VERSION 5.7 ;
  NOWIREEXTENSIONATPIN ON ;
  DIVIDERCHAR "/" ;
  BUSBITCHARS "[]" ;
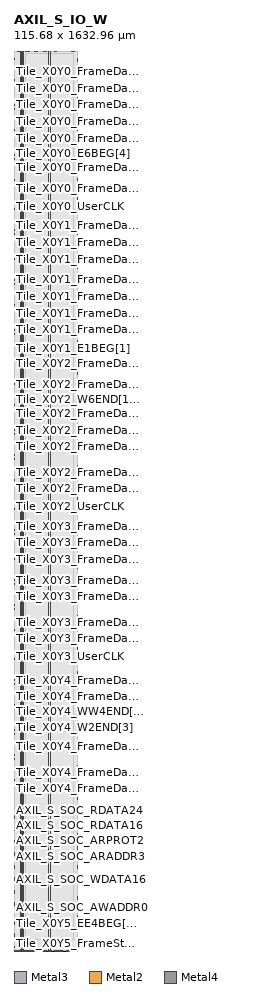
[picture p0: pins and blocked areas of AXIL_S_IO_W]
MACRO AXIL_S_IO_W
  CLASS BLOCK ;
  FOREIGN AXIL_S_IO_W ;
  ORIGIN 0.000 0.000 ;
  SIZE 115.680 BY 1632.960 ;
  PIN AXIL_S_SOC_ARADDR0
    DIRECTION INPUT ;
    USE SIGNAL ;
    ANTENNAGATEAREA 2.132000 ;
    PORT
      LAYER Metal3 ;
        RECT 0.000 165.700 0.400 166.100 ;
    END
  END AXIL_S_SOC_ARADDR0
  PIN AXIL_S_SOC_ARADDR1
    DIRECTION INPUT ;
    USE SIGNAL ;
    ANTENNAGATEAREA 2.132000 ;
    PORT
      LAYER Metal3 ;
        RECT 0.000 167.380 0.400 167.780 ;
    END
  END AXIL_S_SOC_ARADDR1
  PIN AXIL_S_SOC_ARADDR2
    DIRECTION INPUT ;
    USE SIGNAL ;
    ANTENNAGATEAREA 2.132000 ;
    PORT
      LAYER Metal3 ;
        RECT 0.000 169.060 0.400 169.460 ;
    END
  END AXIL_S_SOC_ARADDR2
  PIN AXIL_S_SOC_ARADDR3
    DIRECTION INPUT ;
    USE SIGNAL ;
    ANTENNAGATEAREA 2.132000 ;
    PORT
      LAYER Metal3 ;
        RECT 0.000 170.740 0.400 171.140 ;
    END
  END AXIL_S_SOC_ARADDR3
  PIN AXIL_S_SOC_ARADDR4
    DIRECTION INPUT ;
    USE SIGNAL ;
    ANTENNAGATEAREA 2.132000 ;
    PORT
      LAYER Metal3 ;
        RECT 0.000 172.420 0.400 172.820 ;
    END
  END AXIL_S_SOC_ARADDR4
  PIN AXIL_S_SOC_ARADDR5
    DIRECTION INPUT ;
    USE SIGNAL ;
    ANTENNAGATEAREA 2.132000 ;
    PORT
      LAYER Metal3 ;
        RECT 0.000 174.100 0.400 174.500 ;
    END
  END AXIL_S_SOC_ARADDR5
  PIN AXIL_S_SOC_ARADDR6
    DIRECTION INPUT ;
    USE SIGNAL ;
    ANTENNAGATEAREA 1.279200 ;
    PORT
      LAYER Metal3 ;
        RECT 0.000 175.780 0.400 176.180 ;
    END
  END AXIL_S_SOC_ARADDR6
  PIN AXIL_S_SOC_ARADDR7
    DIRECTION INPUT ;
    USE SIGNAL ;
    ANTENNAGATEAREA 1.279200 ;
    PORT
      LAYER Metal3 ;
        RECT 0.000 177.460 0.400 177.860 ;
    END
  END AXIL_S_SOC_ARADDR7
  PIN AXIL_S_SOC_ARADDR8
    DIRECTION INPUT ;
    USE SIGNAL ;
    ANTENNAGATEAREA 0.852800 ;
    PORT
      LAYER Metal3 ;
        RECT 0.000 179.140 0.400 179.540 ;
    END
  END AXIL_S_SOC_ARADDR8
  PIN AXIL_S_SOC_ARADDR9
    DIRECTION INPUT ;
    USE SIGNAL ;
    ANTENNAGATEAREA 0.852800 ;
    PORT
      LAYER Metal3 ;
        RECT 0.000 180.820 0.400 181.220 ;
    END
  END AXIL_S_SOC_ARADDR9
  PIN AXIL_S_SOC_ARPROT0
    DIRECTION INPUT ;
    USE SIGNAL ;
    ANTENNAGATEAREA 4.050800 ;
    PORT
      LAYER Metal3 ;
        RECT 0.000 182.500 0.400 182.900 ;
    END
  END AXIL_S_SOC_ARPROT0
  PIN AXIL_S_SOC_ARPROT1
    DIRECTION INPUT ;
    USE SIGNAL ;
    ANTENNAGATEAREA 3.411200 ;
    PORT
      LAYER Metal3 ;
        RECT 0.000 184.180 0.400 184.580 ;
    END
  END AXIL_S_SOC_ARPROT1
  PIN AXIL_S_SOC_ARPROT2
    DIRECTION INPUT ;
    USE SIGNAL ;
    ANTENNAGATEAREA 3.198000 ;
    PORT
      LAYER Metal3 ;
        RECT 0.000 185.860 0.400 186.260 ;
    END
  END AXIL_S_SOC_ARPROT2
  PIN AXIL_S_SOC_ARREADY
    DIRECTION OUTPUT ;
    USE SIGNAL ;
    ANTENNADIFFAREA 2.647800 ;
    PORT
      LAYER Metal3 ;
        RECT 0.000 199.300 0.400 199.700 ;
    END
  END AXIL_S_SOC_ARREADY
  PIN AXIL_S_SOC_ARVALID
    DIRECTION INPUT ;
    USE SIGNAL ;
    ANTENNAGATEAREA 2.984800 ;
    PORT
      LAYER Metal3 ;
        RECT 0.000 187.540 0.400 187.940 ;
    END
  END AXIL_S_SOC_ARVALID
  PIN AXIL_S_SOC_AWADDR0
    DIRECTION INPUT ;
    USE SIGNAL ;
    ANTENNAGATEAREA 2.132000 ;
    PORT
      LAYER Metal3 ;
        RECT 0.000 78.340 0.400 78.740 ;
    END
  END AXIL_S_SOC_AWADDR0
  PIN AXIL_S_SOC_AWADDR1
    DIRECTION INPUT ;
    USE SIGNAL ;
    ANTENNAGATEAREA 2.132000 ;
    PORT
      LAYER Metal3 ;
        RECT 0.000 80.020 0.400 80.420 ;
    END
  END AXIL_S_SOC_AWADDR1
  PIN AXIL_S_SOC_AWADDR2
    DIRECTION INPUT ;
    USE SIGNAL ;
    ANTENNAGATEAREA 1.279200 ;
    PORT
      LAYER Metal3 ;
        RECT 0.000 81.700 0.400 82.100 ;
    END
  END AXIL_S_SOC_AWADDR2
  PIN AXIL_S_SOC_AWADDR3
    DIRECTION INPUT ;
    USE SIGNAL ;
    ANTENNAGATEAREA 1.279200 ;
    PORT
      LAYER Metal3 ;
        RECT 0.000 83.380 0.400 83.780 ;
    END
  END AXIL_S_SOC_AWADDR3
  PIN AXIL_S_SOC_AWADDR4
    DIRECTION INPUT ;
    USE SIGNAL ;
    ANTENNAGATEAREA 1.279200 ;
    PORT
      LAYER Metal3 ;
        RECT 0.000 85.060 0.400 85.460 ;
    END
  END AXIL_S_SOC_AWADDR4
  PIN AXIL_S_SOC_AWADDR5
    DIRECTION INPUT ;
    USE SIGNAL ;
    ANTENNAGATEAREA 1.279200 ;
    PORT
      LAYER Metal3 ;
        RECT 0.000 86.740 0.400 87.140 ;
    END
  END AXIL_S_SOC_AWADDR5
  PIN AXIL_S_SOC_AWADDR6
    DIRECTION INPUT ;
    USE SIGNAL ;
    ANTENNAGATEAREA 1.279200 ;
    PORT
      LAYER Metal3 ;
        RECT 0.000 88.420 0.400 88.820 ;
    END
  END AXIL_S_SOC_AWADDR6
  PIN AXIL_S_SOC_AWADDR7
    DIRECTION INPUT ;
    USE SIGNAL ;
    ANTENNAGATEAREA 1.279200 ;
    PORT
      LAYER Metal3 ;
        RECT 0.000 90.100 0.400 90.500 ;
    END
  END AXIL_S_SOC_AWADDR7
  PIN AXIL_S_SOC_AWADDR8
    DIRECTION INPUT ;
    USE SIGNAL ;
    ANTENNAGATEAREA 0.852800 ;
    PORT
      LAYER Metal3 ;
        RECT 0.000 91.780 0.400 92.180 ;
    END
  END AXIL_S_SOC_AWADDR8
  PIN AXIL_S_SOC_AWADDR9
    DIRECTION INPUT ;
    USE SIGNAL ;
    ANTENNAGATEAREA 0.852800 ;
    PORT
      LAYER Metal3 ;
        RECT 0.000 93.460 0.400 93.860 ;
    END
  END AXIL_S_SOC_AWADDR9
  PIN AXIL_S_SOC_AWPROT0
    DIRECTION INPUT ;
    USE SIGNAL ;
    ANTENNAGATEAREA 0.852800 ;
    PORT
      LAYER Metal3 ;
        RECT 0.000 95.140 0.400 95.540 ;
    END
  END AXIL_S_SOC_AWPROT0
  PIN AXIL_S_SOC_AWPROT1
    DIRECTION INPUT ;
    USE SIGNAL ;
    ANTENNAGATEAREA 0.852800 ;
    PORT
      LAYER Metal3 ;
        RECT 0.000 96.820 0.400 97.220 ;
    END
  END AXIL_S_SOC_AWPROT1
  PIN AXIL_S_SOC_AWPROT2
    DIRECTION INPUT ;
    USE SIGNAL ;
    ANTENNAGATEAREA 0.852800 ;
    PORT
      LAYER Metal3 ;
        RECT 0.000 98.500 0.400 98.900 ;
    END
  END AXIL_S_SOC_AWPROT2
  PIN AXIL_S_SOC_AWREADY
    DIRECTION OUTPUT ;
    USE SIGNAL ;
    ANTENNADIFFAREA 2.647800 ;
    PORT
      LAYER Metal3 ;
        RECT 0.000 190.900 0.400 191.300 ;
    END
  END AXIL_S_SOC_AWREADY
  PIN AXIL_S_SOC_AWVALID
    DIRECTION INPUT ;
    USE SIGNAL ;
    ANTENNAGATEAREA 0.852800 ;
    PORT
      LAYER Metal3 ;
        RECT 0.000 100.180 0.400 100.580 ;
    END
  END AXIL_S_SOC_AWVALID
  PIN AXIL_S_SOC_BREADY
    DIRECTION INPUT ;
    USE SIGNAL ;
    ANTENNAGATEAREA 2.132000 ;
    PORT
      LAYER Metal3 ;
        RECT 0.000 164.020 0.400 164.420 ;
    END
  END AXIL_S_SOC_BREADY
  PIN AXIL_S_SOC_BRESP0
    DIRECTION OUTPUT ;
    USE SIGNAL ;
    ANTENNADIFFAREA 2.647800 ;
    PORT
      LAYER Metal3 ;
        RECT 0.000 194.260 0.400 194.660 ;
    END
  END AXIL_S_SOC_BRESP0
  PIN AXIL_S_SOC_BRESP1
    DIRECTION OUTPUT ;
    USE SIGNAL ;
    ANTENNADIFFAREA 2.647800 ;
    PORT
      LAYER Metal3 ;
        RECT 0.000 195.940 0.400 196.340 ;
    END
  END AXIL_S_SOC_BRESP1
  PIN AXIL_S_SOC_BVALID
    DIRECTION OUTPUT ;
    USE SIGNAL ;
    ANTENNADIFFAREA 2.647800 ;
    PORT
      LAYER Metal3 ;
        RECT 0.000 197.620 0.400 198.020 ;
    END
  END AXIL_S_SOC_BVALID
  PIN AXIL_S_SOC_RDATA0
    DIRECTION OUTPUT ;
    USE SIGNAL ;
    ANTENNADIFFAREA 2.647800 ;
    PORT
      LAYER Metal3 ;
        RECT 0.000 200.980 0.400 201.380 ;
    END
  END AXIL_S_SOC_RDATA0
  PIN AXIL_S_SOC_RDATA1
    DIRECTION OUTPUT ;
    USE SIGNAL ;
    ANTENNADIFFAREA 2.647800 ;
    PORT
      LAYER Metal3 ;
        RECT 0.000 202.660 0.400 203.060 ;
    END
  END AXIL_S_SOC_RDATA1
  PIN AXIL_S_SOC_RDATA10
    DIRECTION OUTPUT ;
    USE SIGNAL ;
    ANTENNADIFFAREA 2.647800 ;
    PORT
      LAYER Metal3 ;
        RECT 0.000 217.780 0.400 218.180 ;
    END
  END AXIL_S_SOC_RDATA10
  PIN AXIL_S_SOC_RDATA11
    DIRECTION OUTPUT ;
    USE SIGNAL ;
    ANTENNADIFFAREA 2.647800 ;
    PORT
      LAYER Metal3 ;
        RECT 0.000 219.460 0.400 219.860 ;
    END
  END AXIL_S_SOC_RDATA11
  PIN AXIL_S_SOC_RDATA12
    DIRECTION OUTPUT ;
    USE SIGNAL ;
    ANTENNADIFFAREA 2.647800 ;
    PORT
      LAYER Metal3 ;
        RECT 0.000 221.140 0.400 221.540 ;
    END
  END AXIL_S_SOC_RDATA12
  PIN AXIL_S_SOC_RDATA13
    DIRECTION OUTPUT ;
    USE SIGNAL ;
    ANTENNADIFFAREA 2.647800 ;
    PORT
      LAYER Metal3 ;
        RECT 0.000 222.820 0.400 223.220 ;
    END
  END AXIL_S_SOC_RDATA13
  PIN AXIL_S_SOC_RDATA14
    DIRECTION OUTPUT ;
    USE SIGNAL ;
    ANTENNADIFFAREA 2.647800 ;
    PORT
      LAYER Metal3 ;
        RECT 0.000 224.500 0.400 224.900 ;
    END
  END AXIL_S_SOC_RDATA14
  PIN AXIL_S_SOC_RDATA15
    DIRECTION OUTPUT ;
    USE SIGNAL ;
    ANTENNADIFFAREA 2.647800 ;
    PORT
      LAYER Metal3 ;
        RECT 0.000 226.180 0.400 226.580 ;
    END
  END AXIL_S_SOC_RDATA15
  PIN AXIL_S_SOC_RDATA16
    DIRECTION OUTPUT ;
    USE SIGNAL ;
    ANTENNADIFFAREA 2.647800 ;
    PORT
      LAYER Metal3 ;
        RECT 0.000 227.860 0.400 228.260 ;
    END
  END AXIL_S_SOC_RDATA16
  PIN AXIL_S_SOC_RDATA17
    DIRECTION OUTPUT ;
    USE SIGNAL ;
    ANTENNADIFFAREA 2.647800 ;
    PORT
      LAYER Metal3 ;
        RECT 0.000 229.540 0.400 229.940 ;
    END
  END AXIL_S_SOC_RDATA17
  PIN AXIL_S_SOC_RDATA18
    DIRECTION OUTPUT ;
    USE SIGNAL ;
    ANTENNADIFFAREA 2.647800 ;
    PORT
      LAYER Metal3 ;
        RECT 0.000 231.220 0.400 231.620 ;
    END
  END AXIL_S_SOC_RDATA18
  PIN AXIL_S_SOC_RDATA19
    DIRECTION OUTPUT ;
    USE SIGNAL ;
    ANTENNADIFFAREA 2.647800 ;
    PORT
      LAYER Metal3 ;
        RECT 0.000 232.900 0.400 233.300 ;
    END
  END AXIL_S_SOC_RDATA19
  PIN AXIL_S_SOC_RDATA2
    DIRECTION OUTPUT ;
    USE SIGNAL ;
    ANTENNADIFFAREA 2.647800 ;
    PORT
      LAYER Metal3 ;
        RECT 0.000 204.340 0.400 204.740 ;
    END
  END AXIL_S_SOC_RDATA2
  PIN AXIL_S_SOC_RDATA20
    DIRECTION OUTPUT ;
    USE SIGNAL ;
    ANTENNADIFFAREA 2.647800 ;
    PORT
      LAYER Metal3 ;
        RECT 0.000 234.580 0.400 234.980 ;
    END
  END AXIL_S_SOC_RDATA20
  PIN AXIL_S_SOC_RDATA21
    DIRECTION OUTPUT ;
    USE SIGNAL ;
    ANTENNADIFFAREA 2.647800 ;
    PORT
      LAYER Metal3 ;
        RECT 0.000 236.260 0.400 236.660 ;
    END
  END AXIL_S_SOC_RDATA21
  PIN AXIL_S_SOC_RDATA22
    DIRECTION OUTPUT ;
    USE SIGNAL ;
    ANTENNADIFFAREA 2.647800 ;
    PORT
      LAYER Metal3 ;
        RECT 0.000 237.940 0.400 238.340 ;
    END
  END AXIL_S_SOC_RDATA22
  PIN AXIL_S_SOC_RDATA23
    DIRECTION OUTPUT ;
    USE SIGNAL ;
    ANTENNADIFFAREA 2.647800 ;
    PORT
      LAYER Metal3 ;
        RECT 0.000 239.620 0.400 240.020 ;
    END
  END AXIL_S_SOC_RDATA23
  PIN AXIL_S_SOC_RDATA24
    DIRECTION OUTPUT ;
    USE SIGNAL ;
    ANTENNADIFFAREA 2.647800 ;
    PORT
      LAYER Metal3 ;
        RECT 0.000 241.300 0.400 241.700 ;
    END
  END AXIL_S_SOC_RDATA24
  PIN AXIL_S_SOC_RDATA25
    DIRECTION OUTPUT ;
    USE SIGNAL ;
    ANTENNADIFFAREA 2.647800 ;
    PORT
      LAYER Metal3 ;
        RECT 0.000 242.980 0.400 243.380 ;
    END
  END AXIL_S_SOC_RDATA25
  PIN AXIL_S_SOC_RDATA26
    DIRECTION OUTPUT ;
    USE SIGNAL ;
    ANTENNADIFFAREA 2.647800 ;
    PORT
      LAYER Metal3 ;
        RECT 0.000 244.660 0.400 245.060 ;
    END
  END AXIL_S_SOC_RDATA26
  PIN AXIL_S_SOC_RDATA27
    DIRECTION OUTPUT ;
    USE SIGNAL ;
    ANTENNADIFFAREA 2.647800 ;
    PORT
      LAYER Metal3 ;
        RECT 0.000 246.340 0.400 246.740 ;
    END
  END AXIL_S_SOC_RDATA27
  PIN AXIL_S_SOC_RDATA28
    DIRECTION OUTPUT ;
    USE SIGNAL ;
    ANTENNADIFFAREA 2.647800 ;
    PORT
      LAYER Metal3 ;
        RECT 0.000 248.020 0.400 248.420 ;
    END
  END AXIL_S_SOC_RDATA28
  PIN AXIL_S_SOC_RDATA29
    DIRECTION OUTPUT ;
    USE SIGNAL ;
    ANTENNADIFFAREA 2.647800 ;
    PORT
      LAYER Metal3 ;
        RECT 0.000 249.700 0.400 250.100 ;
    END
  END AXIL_S_SOC_RDATA29
  PIN AXIL_S_SOC_RDATA3
    DIRECTION OUTPUT ;
    USE SIGNAL ;
    ANTENNADIFFAREA 2.647800 ;
    PORT
      LAYER Metal3 ;
        RECT 0.000 206.020 0.400 206.420 ;
    END
  END AXIL_S_SOC_RDATA3
  PIN AXIL_S_SOC_RDATA30
    DIRECTION OUTPUT ;
    USE SIGNAL ;
    ANTENNADIFFAREA 2.647800 ;
    PORT
      LAYER Metal3 ;
        RECT 0.000 251.380 0.400 251.780 ;
    END
  END AXIL_S_SOC_RDATA30
  PIN AXIL_S_SOC_RDATA31
    DIRECTION OUTPUT ;
    USE SIGNAL ;
    ANTENNADIFFAREA 2.647800 ;
    PORT
      LAYER Metal3 ;
        RECT 0.000 253.060 0.400 253.460 ;
    END
  END AXIL_S_SOC_RDATA31
  PIN AXIL_S_SOC_RDATA4
    DIRECTION OUTPUT ;
    USE SIGNAL ;
    ANTENNADIFFAREA 2.647800 ;
    PORT
      LAYER Metal3 ;
        RECT 0.000 207.700 0.400 208.100 ;
    END
  END AXIL_S_SOC_RDATA4
  PIN AXIL_S_SOC_RDATA5
    DIRECTION OUTPUT ;
    USE SIGNAL ;
    ANTENNADIFFAREA 2.647800 ;
    PORT
      LAYER Metal3 ;
        RECT 0.000 209.380 0.400 209.780 ;
    END
  END AXIL_S_SOC_RDATA5
  PIN AXIL_S_SOC_RDATA6
    DIRECTION OUTPUT ;
    USE SIGNAL ;
    ANTENNADIFFAREA 2.647800 ;
    PORT
      LAYER Metal3 ;
        RECT 0.000 211.060 0.400 211.460 ;
    END
  END AXIL_S_SOC_RDATA6
  PIN AXIL_S_SOC_RDATA7
    DIRECTION OUTPUT ;
    USE SIGNAL ;
    ANTENNADIFFAREA 2.647800 ;
    PORT
      LAYER Metal3 ;
        RECT 0.000 212.740 0.400 213.140 ;
    END
  END AXIL_S_SOC_RDATA7
  PIN AXIL_S_SOC_RDATA8
    DIRECTION OUTPUT ;
    USE SIGNAL ;
    ANTENNADIFFAREA 2.647800 ;
    PORT
      LAYER Metal3 ;
        RECT 0.000 214.420 0.400 214.820 ;
    END
  END AXIL_S_SOC_RDATA8
  PIN AXIL_S_SOC_RDATA9
    DIRECTION OUTPUT ;
    USE SIGNAL ;
    ANTENNADIFFAREA 2.647800 ;
    PORT
      LAYER Metal3 ;
        RECT 0.000 216.100 0.400 216.500 ;
    END
  END AXIL_S_SOC_RDATA9
  PIN AXIL_S_SOC_RREADY
    DIRECTION INPUT ;
    USE SIGNAL ;
    ANTENNAGATEAREA 2.984800 ;
    PORT
      LAYER Metal3 ;
        RECT 0.000 189.220 0.400 189.620 ;
    END
  END AXIL_S_SOC_RREADY
  PIN AXIL_S_SOC_RRESP0
    DIRECTION OUTPUT ;
    USE SIGNAL ;
    ANTENNADIFFAREA 2.647800 ;
    PORT
      LAYER Metal3 ;
        RECT 0.000 254.740 0.400 255.140 ;
    END
  END AXIL_S_SOC_RRESP0
  PIN AXIL_S_SOC_RRESP1
    DIRECTION OUTPUT ;
    USE SIGNAL ;
    ANTENNADIFFAREA 2.647800 ;
    PORT
      LAYER Metal3 ;
        RECT 0.000 256.420 0.400 256.820 ;
    END
  END AXIL_S_SOC_RRESP1
  PIN AXIL_S_SOC_RVALID
    DIRECTION OUTPUT ;
    USE SIGNAL ;
    ANTENNADIFFAREA 2.647800 ;
    PORT
      LAYER Metal3 ;
        RECT 0.000 258.100 0.400 258.500 ;
    END
  END AXIL_S_SOC_RVALID
  PIN AXIL_S_SOC_WDATA0
    DIRECTION INPUT ;
    USE SIGNAL ;
    ANTENNAGATEAREA 1.279200 ;
    PORT
      LAYER Metal3 ;
        RECT 0.000 101.860 0.400 102.260 ;
    END
  END AXIL_S_SOC_WDATA0
  PIN AXIL_S_SOC_WDATA1
    DIRECTION INPUT ;
    USE SIGNAL ;
    ANTENNAGATEAREA 1.279200 ;
    ANTENNADIFFAREA 24.184799 ;
    PORT
      LAYER Metal3 ;
        RECT 0.000 103.540 0.400 103.940 ;
    END
  END AXIL_S_SOC_WDATA1
  PIN AXIL_S_SOC_WDATA10
    DIRECTION INPUT ;
    USE SIGNAL ;
    ANTENNAGATEAREA 0.852800 ;
    ANTENNADIFFAREA 32.246399 ;
    PORT
      LAYER Metal3 ;
        RECT 0.000 118.660 0.400 119.060 ;
    END
  END AXIL_S_SOC_WDATA10
  PIN AXIL_S_SOC_WDATA11
    DIRECTION INPUT ;
    USE SIGNAL ;
    ANTENNAGATEAREA 0.852800 ;
    PORT
      LAYER Metal3 ;
        RECT 0.000 120.340 0.400 120.740 ;
    END
  END AXIL_S_SOC_WDATA11
  PIN AXIL_S_SOC_WDATA12
    DIRECTION INPUT ;
    USE SIGNAL ;
    ANTENNAGATEAREA 0.852800 ;
    ANTENNADIFFAREA 32.246399 ;
    PORT
      LAYER Metal3 ;
        RECT 0.000 122.020 0.400 122.420 ;
    END
  END AXIL_S_SOC_WDATA12
  PIN AXIL_S_SOC_WDATA13
    DIRECTION INPUT ;
    USE SIGNAL ;
    ANTENNAGATEAREA 0.852800 ;
    ANTENNADIFFAREA 32.246399 ;
    PORT
      LAYER Metal3 ;
        RECT 0.000 123.700 0.400 124.100 ;
    END
  END AXIL_S_SOC_WDATA13
  PIN AXIL_S_SOC_WDATA14
    DIRECTION INPUT ;
    USE SIGNAL ;
    ANTENNAGATEAREA 0.852800 ;
    ANTENNADIFFAREA 32.246399 ;
    PORT
      LAYER Metal3 ;
        RECT 0.000 125.380 0.400 125.780 ;
    END
  END AXIL_S_SOC_WDATA14
  PIN AXIL_S_SOC_WDATA15
    DIRECTION INPUT ;
    USE SIGNAL ;
    ANTENNAGATEAREA 0.852800 ;
    ANTENNADIFFAREA 32.246399 ;
    PORT
      LAYER Metal3 ;
        RECT 0.000 127.060 0.400 127.460 ;
    END
  END AXIL_S_SOC_WDATA15
  PIN AXIL_S_SOC_WDATA16
    DIRECTION INPUT ;
    USE SIGNAL ;
    ANTENNAGATEAREA 1.279200 ;
    ANTENNADIFFAREA 72.554398 ;
    PORT
      LAYER Metal3 ;
        RECT 0.000 128.740 0.400 129.140 ;
    END
  END AXIL_S_SOC_WDATA16
  PIN AXIL_S_SOC_WDATA17
    DIRECTION INPUT ;
    USE SIGNAL ;
    ANTENNAGATEAREA 1.279200 ;
    PORT
      LAYER Metal3 ;
        RECT 0.000 130.420 0.400 130.820 ;
    END
  END AXIL_S_SOC_WDATA17
  PIN AXIL_S_SOC_WDATA18
    DIRECTION INPUT ;
    USE SIGNAL ;
    ANTENNAGATEAREA 1.279200 ;
    ANTENNADIFFAREA 72.554398 ;
    PORT
      LAYER Metal3 ;
        RECT 0.000 132.100 0.400 132.500 ;
    END
  END AXIL_S_SOC_WDATA18
  PIN AXIL_S_SOC_WDATA19
    DIRECTION INPUT ;
    USE SIGNAL ;
    ANTENNAGATEAREA 1.279200 ;
    ANTENNADIFFAREA 72.554398 ;
    PORT
      LAYER Metal3 ;
        RECT 0.000 133.780 0.400 134.180 ;
    END
  END AXIL_S_SOC_WDATA19
  PIN AXIL_S_SOC_WDATA2
    DIRECTION INPUT ;
    USE SIGNAL ;
    ANTENNAGATEAREA 1.279200 ;
    PORT
      LAYER Metal3 ;
        RECT 0.000 105.220 0.400 105.620 ;
    END
  END AXIL_S_SOC_WDATA2
  PIN AXIL_S_SOC_WDATA20
    DIRECTION INPUT ;
    USE SIGNAL ;
    ANTENNAGATEAREA 1.279200 ;
    ANTENNADIFFAREA 72.554398 ;
    PORT
      LAYER Metal3 ;
        RECT 0.000 135.460 0.400 135.860 ;
    END
  END AXIL_S_SOC_WDATA20
  PIN AXIL_S_SOC_WDATA21
    DIRECTION INPUT ;
    USE SIGNAL ;
    ANTENNAGATEAREA 1.279200 ;
    PORT
      LAYER Metal3 ;
        RECT 0.000 137.140 0.400 137.540 ;
    END
  END AXIL_S_SOC_WDATA21
  PIN AXIL_S_SOC_WDATA22
    DIRECTION INPUT ;
    USE SIGNAL ;
    ANTENNAGATEAREA 1.279200 ;
    ANTENNADIFFAREA 72.554398 ;
    PORT
      LAYER Metal3 ;
        RECT 0.000 138.820 0.400 139.220 ;
    END
  END AXIL_S_SOC_WDATA22
  PIN AXIL_S_SOC_WDATA23
    DIRECTION INPUT ;
    USE SIGNAL ;
    ANTENNAGATEAREA 1.279200 ;
    PORT
      LAYER Metal3 ;
        RECT 0.000 140.500 0.400 140.900 ;
    END
  END AXIL_S_SOC_WDATA23
  PIN AXIL_S_SOC_WDATA24
    DIRECTION INPUT ;
    USE SIGNAL ;
    ANTENNAGATEAREA 0.852800 ;
    ANTENNADIFFAREA 32.246399 ;
    PORT
      LAYER Metal3 ;
        RECT 0.000 142.180 0.400 142.580 ;
    END
  END AXIL_S_SOC_WDATA24
  PIN AXIL_S_SOC_WDATA25
    DIRECTION INPUT ;
    USE SIGNAL ;
    ANTENNAGATEAREA 0.852800 ;
    ANTENNADIFFAREA 32.246399 ;
    PORT
      LAYER Metal3 ;
        RECT 0.000 143.860 0.400 144.260 ;
    END
  END AXIL_S_SOC_WDATA25
  PIN AXIL_S_SOC_WDATA26
    DIRECTION INPUT ;
    USE SIGNAL ;
    ANTENNAGATEAREA 0.852800 ;
    ANTENNADIFFAREA 32.246399 ;
    PORT
      LAYER Metal3 ;
        RECT 0.000 145.540 0.400 145.940 ;
    END
  END AXIL_S_SOC_WDATA26
  PIN AXIL_S_SOC_WDATA27
    DIRECTION INPUT ;
    USE SIGNAL ;
    ANTENNAGATEAREA 0.852800 ;
    ANTENNADIFFAREA 32.246399 ;
    PORT
      LAYER Metal3 ;
        RECT 0.000 147.220 0.400 147.620 ;
    END
  END AXIL_S_SOC_WDATA27
  PIN AXIL_S_SOC_WDATA28
    DIRECTION INPUT ;
    USE SIGNAL ;
    ANTENNAGATEAREA 0.852800 ;
    ANTENNADIFFAREA 32.246399 ;
    PORT
      LAYER Metal3 ;
        RECT 0.000 148.900 0.400 149.300 ;
    END
  END AXIL_S_SOC_WDATA28
  PIN AXIL_S_SOC_WDATA29
    DIRECTION INPUT ;
    USE SIGNAL ;
    ANTENNAGATEAREA 0.852800 ;
    ANTENNADIFFAREA 32.246399 ;
    PORT
      LAYER Metal3 ;
        RECT 0.000 150.580 0.400 150.980 ;
    END
  END AXIL_S_SOC_WDATA29
  PIN AXIL_S_SOC_WDATA3
    DIRECTION INPUT ;
    USE SIGNAL ;
    ANTENNAGATEAREA 1.279200 ;
    PORT
      LAYER Metal3 ;
        RECT 0.000 106.900 0.400 107.300 ;
    END
  END AXIL_S_SOC_WDATA3
  PIN AXIL_S_SOC_WDATA30
    DIRECTION INPUT ;
    USE SIGNAL ;
    ANTENNAGATEAREA 0.852800 ;
    ANTENNADIFFAREA 32.246399 ;
    PORT
      LAYER Metal3 ;
        RECT 0.000 152.260 0.400 152.660 ;
    END
  END AXIL_S_SOC_WDATA30
  PIN AXIL_S_SOC_WDATA31
    DIRECTION INPUT ;
    USE SIGNAL ;
    ANTENNAGATEAREA 0.852800 ;
    ANTENNADIFFAREA 32.246399 ;
    PORT
      LAYER Metal3 ;
        RECT 0.000 153.940 0.400 154.340 ;
    END
  END AXIL_S_SOC_WDATA31
  PIN AXIL_S_SOC_WDATA4
    DIRECTION INPUT ;
    USE SIGNAL ;
    ANTENNAGATEAREA 1.279200 ;
    PORT
      LAYER Metal3 ;
        RECT 0.000 108.580 0.400 108.980 ;
    END
  END AXIL_S_SOC_WDATA4
  PIN AXIL_S_SOC_WDATA5
    DIRECTION INPUT ;
    USE SIGNAL ;
    ANTENNAGATEAREA 1.279200 ;
    PORT
      LAYER Metal3 ;
        RECT 0.000 110.260 0.400 110.660 ;
    END
  END AXIL_S_SOC_WDATA5
  PIN AXIL_S_SOC_WDATA6
    DIRECTION INPUT ;
    USE SIGNAL ;
    ANTENNAGATEAREA 1.279200 ;
    PORT
      LAYER Metal3 ;
        RECT 0.000 111.940 0.400 112.340 ;
    END
  END AXIL_S_SOC_WDATA6
  PIN AXIL_S_SOC_WDATA7
    DIRECTION INPUT ;
    USE SIGNAL ;
    ANTENNAGATEAREA 1.279200 ;
    PORT
      LAYER Metal3 ;
        RECT 0.000 113.620 0.400 114.020 ;
    END
  END AXIL_S_SOC_WDATA7
  PIN AXIL_S_SOC_WDATA8
    DIRECTION INPUT ;
    USE SIGNAL ;
    ANTENNAGATEAREA 0.852800 ;
    ANTENNADIFFAREA 32.246399 ;
    PORT
      LAYER Metal3 ;
        RECT 0.000 115.300 0.400 115.700 ;
    END
  END AXIL_S_SOC_WDATA8
  PIN AXIL_S_SOC_WDATA9
    DIRECTION INPUT ;
    USE SIGNAL ;
    ANTENNAGATEAREA 0.852800 ;
    ANTENNADIFFAREA 32.246399 ;
    PORT
      LAYER Metal3 ;
        RECT 0.000 116.980 0.400 117.380 ;
    END
  END AXIL_S_SOC_WDATA9
  PIN AXIL_S_SOC_WREADY
    DIRECTION OUTPUT ;
    USE SIGNAL ;
    ANTENNADIFFAREA 2.647800 ;
    PORT
      LAYER Metal3 ;
        RECT 0.000 192.580 0.400 192.980 ;
    END
  END AXIL_S_SOC_WREADY
  PIN AXIL_S_SOC_WSTRB0
    DIRECTION INPUT ;
    USE SIGNAL ;
    ANTENNAGATEAREA 2.984800 ;
    PORT
      LAYER Metal3 ;
        RECT 0.000 155.620 0.400 156.020 ;
    END
  END AXIL_S_SOC_WSTRB0
  PIN AXIL_S_SOC_WSTRB1
    DIRECTION INPUT ;
    USE SIGNAL ;
    ANTENNAGATEAREA 2.984800 ;
    PORT
      LAYER Metal3 ;
        RECT 0.000 157.300 0.400 157.700 ;
    END
  END AXIL_S_SOC_WSTRB1
  PIN AXIL_S_SOC_WSTRB2
    DIRECTION INPUT ;
    USE SIGNAL ;
    ANTENNAGATEAREA 2.558400 ;
    PORT
      LAYER Metal3 ;
        RECT 0.000 158.980 0.400 159.380 ;
    END
  END AXIL_S_SOC_WSTRB2
  PIN AXIL_S_SOC_WSTRB3
    DIRECTION INPUT ;
    USE SIGNAL ;
    ANTENNAGATEAREA 2.558400 ;
    PORT
      LAYER Metal3 ;
        RECT 0.000 160.660 0.400 161.060 ;
    END
  END AXIL_S_SOC_WSTRB3
  PIN AXIL_S_SOC_WVALID
    DIRECTION INPUT ;
    USE SIGNAL ;
    ANTENNAGATEAREA 2.132000 ;
    PORT
      LAYER Metal3 ;
        RECT 0.000 162.340 0.400 162.740 ;
    END
  END AXIL_S_SOC_WVALID
  PIN Tile_X0Y0_E1BEG[0]
    DIRECTION OUTPUT ;
    USE SIGNAL ;
    ANTENNADIFFAREA 2.724000 ;
    PORT
      LAYER Metal3 ;
        RECT 115.280 1362.700 115.680 1363.100 ;
    END
  END Tile_X0Y0_E1BEG[0]
  PIN Tile_X0Y0_E1BEG[1]
    DIRECTION OUTPUT ;
    USE SIGNAL ;
    ANTENNADIFFAREA 2.724000 ;
    PORT
      LAYER Metal3 ;
        RECT 115.280 1364.380 115.680 1364.780 ;
    END
  END Tile_X0Y0_E1BEG[1]
  PIN Tile_X0Y0_E1BEG[2]
    DIRECTION OUTPUT ;
    USE SIGNAL ;
    ANTENNADIFFAREA 2.724000 ;
    PORT
      LAYER Metal3 ;
        RECT 115.280 1366.060 115.680 1366.460 ;
    END
  END Tile_X0Y0_E1BEG[2]
  PIN Tile_X0Y0_E1BEG[3]
    DIRECTION OUTPUT ;
    USE SIGNAL ;
    ANTENNADIFFAREA 2.724000 ;
    PORT
      LAYER Metal3 ;
        RECT 115.280 1367.740 115.680 1368.140 ;
    END
  END Tile_X0Y0_E1BEG[3]
  PIN Tile_X0Y0_E2BEG[0]
    DIRECTION OUTPUT ;
    USE SIGNAL ;
    ANTENNADIFFAREA 2.724000 ;
    PORT
      LAYER Metal3 ;
        RECT 115.280 1371.940 115.680 1372.340 ;
    END
  END Tile_X0Y0_E2BEG[0]
  PIN Tile_X0Y0_E2BEG[1]
    DIRECTION OUTPUT ;
    USE SIGNAL ;
    ANTENNADIFFAREA 2.724000 ;
    PORT
      LAYER Metal3 ;
        RECT 115.280 1373.620 115.680 1374.020 ;
    END
  END Tile_X0Y0_E2BEG[1]
  PIN Tile_X0Y0_E2BEG[2]
    DIRECTION OUTPUT ;
    USE SIGNAL ;
    ANTENNADIFFAREA 2.724000 ;
    PORT
      LAYER Metal3 ;
        RECT 115.280 1375.300 115.680 1375.700 ;
    END
  END Tile_X0Y0_E2BEG[2]
  PIN Tile_X0Y0_E2BEG[3]
    DIRECTION OUTPUT ;
    USE SIGNAL ;
    ANTENNADIFFAREA 2.724000 ;
    PORT
      LAYER Metal3 ;
        RECT 115.280 1376.980 115.680 1377.380 ;
    END
  END Tile_X0Y0_E2BEG[3]
  PIN Tile_X0Y0_E2BEG[4]
    DIRECTION OUTPUT ;
    USE SIGNAL ;
    ANTENNADIFFAREA 2.724000 ;
    PORT
      LAYER Metal3 ;
        RECT 115.280 1378.660 115.680 1379.060 ;
    END
  END Tile_X0Y0_E2BEG[4]
  PIN Tile_X0Y0_E2BEG[5]
    DIRECTION OUTPUT ;
    USE SIGNAL ;
    ANTENNADIFFAREA 2.724000 ;
    PORT
      LAYER Metal3 ;
        RECT 115.280 1380.340 115.680 1380.740 ;
    END
  END Tile_X0Y0_E2BEG[5]
  PIN Tile_X0Y0_E2BEG[6]
    DIRECTION OUTPUT ;
    USE SIGNAL ;
    ANTENNADIFFAREA 2.724000 ;
    PORT
      LAYER Metal3 ;
        RECT 115.280 1382.020 115.680 1382.420 ;
    END
  END Tile_X0Y0_E2BEG[6]
  PIN Tile_X0Y0_E2BEG[7]
    DIRECTION OUTPUT ;
    USE SIGNAL ;
    ANTENNADIFFAREA 2.724000 ;
    PORT
      LAYER Metal3 ;
        RECT 115.280 1383.700 115.680 1384.100 ;
    END
  END Tile_X0Y0_E2BEG[7]
  PIN Tile_X0Y0_E2BEGb[0]
    DIRECTION OUTPUT ;
    USE SIGNAL ;
    ANTENNADIFFAREA 2.724000 ;
    PORT
      LAYER Metal3 ;
        RECT 115.280 1388.740 115.680 1389.140 ;
    END
  END Tile_X0Y0_E2BEGb[0]
  PIN Tile_X0Y0_E2BEGb[1]
    DIRECTION OUTPUT ;
    USE SIGNAL ;
    ANTENNADIFFAREA 2.724000 ;
    PORT
      LAYER Metal3 ;
        RECT 115.280 1390.420 115.680 1390.820 ;
    END
  END Tile_X0Y0_E2BEGb[1]
  PIN Tile_X0Y0_E2BEGb[2]
    DIRECTION OUTPUT ;
    USE SIGNAL ;
    ANTENNADIFFAREA 2.724000 ;
    PORT
      LAYER Metal3 ;
        RECT 115.280 1392.100 115.680 1392.500 ;
    END
  END Tile_X0Y0_E2BEGb[2]
  PIN Tile_X0Y0_E2BEGb[3]
    DIRECTION OUTPUT ;
    USE SIGNAL ;
    ANTENNADIFFAREA 2.724000 ;
    PORT
      LAYER Metal3 ;
        RECT 115.280 1393.780 115.680 1394.180 ;
    END
  END Tile_X0Y0_E2BEGb[3]
  PIN Tile_X0Y0_E2BEGb[4]
    DIRECTION OUTPUT ;
    USE SIGNAL ;
    ANTENNADIFFAREA 2.724000 ;
    PORT
      LAYER Metal3 ;
        RECT 115.280 1395.460 115.680 1395.860 ;
    END
  END Tile_X0Y0_E2BEGb[4]
  PIN Tile_X0Y0_E2BEGb[5]
    DIRECTION OUTPUT ;
    USE SIGNAL ;
    ANTENNADIFFAREA 2.724000 ;
    PORT
      LAYER Metal3 ;
        RECT 115.280 1397.140 115.680 1397.540 ;
    END
  END Tile_X0Y0_E2BEGb[5]
  PIN Tile_X0Y0_E2BEGb[6]
    DIRECTION OUTPUT ;
    USE SIGNAL ;
    ANTENNADIFFAREA 2.724000 ;
    PORT
      LAYER Metal3 ;
        RECT 115.280 1398.820 115.680 1399.220 ;
    END
  END Tile_X0Y0_E2BEGb[6]
  PIN Tile_X0Y0_E2BEGb[7]
    DIRECTION OUTPUT ;
    USE SIGNAL ;
    ANTENNADIFFAREA 2.724000 ;
    PORT
      LAYER Metal3 ;
        RECT 115.280 1400.500 115.680 1400.900 ;
    END
  END Tile_X0Y0_E2BEGb[7]
  PIN Tile_X0Y0_E6BEG[0]
    DIRECTION OUTPUT ;
    USE SIGNAL ;
    ANTENNADIFFAREA 2.724000 ;
    PORT
      LAYER Metal3 ;
        RECT 115.280 1439.980 115.680 1440.380 ;
    END
  END Tile_X0Y0_E6BEG[0]
  PIN Tile_X0Y0_E6BEG[10]
    DIRECTION OUTPUT ;
    USE SIGNAL ;
    ANTENNADIFFAREA 2.724000 ;
    PORT
      LAYER Metal3 ;
        RECT 115.280 1456.780 115.680 1457.180 ;
    END
  END Tile_X0Y0_E6BEG[10]
  PIN Tile_X0Y0_E6BEG[11]
    DIRECTION OUTPUT ;
    USE SIGNAL ;
    ANTENNADIFFAREA 2.724000 ;
    PORT
      LAYER Metal3 ;
        RECT 115.280 1458.460 115.680 1458.860 ;
    END
  END Tile_X0Y0_E6BEG[11]
  PIN Tile_X0Y0_E6BEG[1]
    DIRECTION OUTPUT ;
    USE SIGNAL ;
    ANTENNADIFFAREA 2.724000 ;
    PORT
      LAYER Metal3 ;
        RECT 115.280 1441.660 115.680 1442.060 ;
    END
  END Tile_X0Y0_E6BEG[1]
  PIN Tile_X0Y0_E6BEG[2]
    DIRECTION OUTPUT ;
    USE SIGNAL ;
    ANTENNADIFFAREA 2.724000 ;
    PORT
      LAYER Metal3 ;
        RECT 115.280 1443.340 115.680 1443.740 ;
    END
  END Tile_X0Y0_E6BEG[2]
  PIN Tile_X0Y0_E6BEG[3]
    DIRECTION OUTPUT ;
    USE SIGNAL ;
    ANTENNADIFFAREA 2.724000 ;
    PORT
      LAYER Metal3 ;
        RECT 115.280 1445.020 115.680 1445.420 ;
    END
  END Tile_X0Y0_E6BEG[3]
  PIN Tile_X0Y0_E6BEG[4]
    DIRECTION OUTPUT ;
    USE SIGNAL ;
    ANTENNADIFFAREA 2.724000 ;
    PORT
      LAYER Metal3 ;
        RECT 115.280 1446.700 115.680 1447.100 ;
    END
  END Tile_X0Y0_E6BEG[4]
  PIN Tile_X0Y0_E6BEG[5]
    DIRECTION OUTPUT ;
    USE SIGNAL ;
    ANTENNADIFFAREA 2.724000 ;
    PORT
      LAYER Metal3 ;
        RECT 115.280 1448.380 115.680 1448.780 ;
    END
  END Tile_X0Y0_E6BEG[5]
  PIN Tile_X0Y0_E6BEG[6]
    DIRECTION OUTPUT ;
    USE SIGNAL ;
    ANTENNADIFFAREA 2.724000 ;
    PORT
      LAYER Metal3 ;
        RECT 115.280 1450.060 115.680 1450.460 ;
    END
  END Tile_X0Y0_E6BEG[6]
  PIN Tile_X0Y0_E6BEG[7]
    DIRECTION OUTPUT ;
    USE SIGNAL ;
    ANTENNADIFFAREA 2.724000 ;
    PORT
      LAYER Metal3 ;
        RECT 115.280 1451.740 115.680 1452.140 ;
    END
  END Tile_X0Y0_E6BEG[7]
  PIN Tile_X0Y0_E6BEG[8]
    DIRECTION OUTPUT ;
    USE SIGNAL ;
    ANTENNADIFFAREA 2.724000 ;
    PORT
      LAYER Metal3 ;
        RECT 115.280 1453.420 115.680 1453.820 ;
    END
  END Tile_X0Y0_E6BEG[8]
  PIN Tile_X0Y0_E6BEG[9]
    DIRECTION OUTPUT ;
    USE SIGNAL ;
    ANTENNADIFFAREA 2.724000 ;
    PORT
      LAYER Metal3 ;
        RECT 115.280 1455.100 115.680 1455.500 ;
    END
  END Tile_X0Y0_E6BEG[9]
  PIN Tile_X0Y0_EE4BEG[0]
    DIRECTION OUTPUT ;
    USE SIGNAL ;
    ANTENNADIFFAREA 2.724000 ;
    PORT
      LAYER Metal3 ;
        RECT 115.280 1407.220 115.680 1407.620 ;
    END
  END Tile_X0Y0_EE4BEG[0]
  PIN Tile_X0Y0_EE4BEG[10]
    DIRECTION OUTPUT ;
    USE SIGNAL ;
    ANTENNADIFFAREA 2.724000 ;
    PORT
      LAYER Metal3 ;
        RECT 115.280 1424.020 115.680 1424.420 ;
    END
  END Tile_X0Y0_EE4BEG[10]
  PIN Tile_X0Y0_EE4BEG[11]
    DIRECTION OUTPUT ;
    USE SIGNAL ;
    ANTENNADIFFAREA 2.724000 ;
    PORT
      LAYER Metal3 ;
        RECT 115.280 1425.700 115.680 1426.100 ;
    END
  END Tile_X0Y0_EE4BEG[11]
  PIN Tile_X0Y0_EE4BEG[12]
    DIRECTION OUTPUT ;
    USE SIGNAL ;
    ANTENNADIFFAREA 2.724000 ;
    PORT
      LAYER Metal3 ;
        RECT 115.280 1427.380 115.680 1427.780 ;
    END
  END Tile_X0Y0_EE4BEG[12]
  PIN Tile_X0Y0_EE4BEG[13]
    DIRECTION OUTPUT ;
    USE SIGNAL ;
    ANTENNADIFFAREA 2.724000 ;
    PORT
      LAYER Metal3 ;
        RECT 115.280 1429.060 115.680 1429.460 ;
    END
  END Tile_X0Y0_EE4BEG[13]
  PIN Tile_X0Y0_EE4BEG[14]
    DIRECTION OUTPUT ;
    USE SIGNAL ;
    ANTENNADIFFAREA 2.724000 ;
    PORT
      LAYER Metal3 ;
        RECT 115.280 1430.740 115.680 1431.140 ;
    END
  END Tile_X0Y0_EE4BEG[14]
  PIN Tile_X0Y0_EE4BEG[15]
    DIRECTION OUTPUT ;
    USE SIGNAL ;
    ANTENNADIFFAREA 2.724000 ;
    PORT
      LAYER Metal3 ;
        RECT 115.280 1432.420 115.680 1432.820 ;
    END
  END Tile_X0Y0_EE4BEG[15]
  PIN Tile_X0Y0_EE4BEG[1]
    DIRECTION OUTPUT ;
    USE SIGNAL ;
    ANTENNADIFFAREA 2.724000 ;
    PORT
      LAYER Metal3 ;
        RECT 115.280 1408.900 115.680 1409.300 ;
    END
  END Tile_X0Y0_EE4BEG[1]
  PIN Tile_X0Y0_EE4BEG[2]
    DIRECTION OUTPUT ;
    USE SIGNAL ;
    ANTENNADIFFAREA 2.724000 ;
    PORT
      LAYER Metal3 ;
        RECT 115.280 1410.580 115.680 1410.980 ;
    END
  END Tile_X0Y0_EE4BEG[2]
  PIN Tile_X0Y0_EE4BEG[3]
    DIRECTION OUTPUT ;
    USE SIGNAL ;
    ANTENNADIFFAREA 2.724000 ;
    PORT
      LAYER Metal3 ;
        RECT 115.280 1412.260 115.680 1412.660 ;
    END
  END Tile_X0Y0_EE4BEG[3]
  PIN Tile_X0Y0_EE4BEG[4]
    DIRECTION OUTPUT ;
    USE SIGNAL ;
    ANTENNADIFFAREA 2.724000 ;
    PORT
      LAYER Metal3 ;
        RECT 115.280 1413.940 115.680 1414.340 ;
    END
  END Tile_X0Y0_EE4BEG[4]
  PIN Tile_X0Y0_EE4BEG[5]
    DIRECTION OUTPUT ;
    USE SIGNAL ;
    ANTENNADIFFAREA 2.724000 ;
    PORT
      LAYER Metal3 ;
        RECT 115.280 1415.620 115.680 1416.020 ;
    END
  END Tile_X0Y0_EE4BEG[5]
  PIN Tile_X0Y0_EE4BEG[6]
    DIRECTION OUTPUT ;
    USE SIGNAL ;
    ANTENNADIFFAREA 2.724000 ;
    PORT
      LAYER Metal3 ;
        RECT 115.280 1417.300 115.680 1417.700 ;
    END
  END Tile_X0Y0_EE4BEG[6]
  PIN Tile_X0Y0_EE4BEG[7]
    DIRECTION OUTPUT ;
    USE SIGNAL ;
    ANTENNADIFFAREA 2.724000 ;
    PORT
      LAYER Metal3 ;
        RECT 115.280 1418.980 115.680 1419.380 ;
    END
  END Tile_X0Y0_EE4BEG[7]
  PIN Tile_X0Y0_EE4BEG[8]
    DIRECTION OUTPUT ;
    USE SIGNAL ;
    ANTENNADIFFAREA 2.724000 ;
    PORT
      LAYER Metal3 ;
        RECT 115.280 1420.660 115.680 1421.060 ;
    END
  END Tile_X0Y0_EE4BEG[8]
  PIN Tile_X0Y0_EE4BEG[9]
    DIRECTION OUTPUT ;
    USE SIGNAL ;
    ANTENNADIFFAREA 2.724000 ;
    PORT
      LAYER Metal3 ;
        RECT 115.280 1422.340 115.680 1422.740 ;
    END
  END Tile_X0Y0_EE4BEG[9]
  PIN Tile_X0Y0_FrameData[0]
    DIRECTION INPUT ;
    USE SIGNAL ;
    ANTENNAGATEAREA 1.445600 ;
    PORT
      LAYER Metal3 ;
        RECT 0.000 1383.700 0.400 1384.100 ;
    END
  END Tile_X0Y0_FrameData[0]
  PIN Tile_X0Y0_FrameData[10]
    DIRECTION INPUT ;
    USE SIGNAL ;
    ANTENNAGATEAREA 1.445600 ;
    PORT
      LAYER Metal3 ;
        RECT 0.000 1459.300 0.400 1459.700 ;
    END
  END Tile_X0Y0_FrameData[10]
  PIN Tile_X0Y0_FrameData[11]
    DIRECTION INPUT ;
    USE SIGNAL ;
    ANTENNAGATEAREA 1.445600 ;
    PORT
      LAYER Metal3 ;
        RECT 0.000 1466.860 0.400 1467.260 ;
    END
  END Tile_X0Y0_FrameData[11]
  PIN Tile_X0Y0_FrameData[12]
    DIRECTION INPUT ;
    USE SIGNAL ;
    ANTENNAGATEAREA 1.445600 ;
    PORT
      LAYER Metal3 ;
        RECT 0.000 1474.420 0.400 1474.820 ;
    END
  END Tile_X0Y0_FrameData[12]
  PIN Tile_X0Y0_FrameData[13]
    DIRECTION INPUT ;
    USE SIGNAL ;
    ANTENNAGATEAREA 1.445600 ;
    PORT
      LAYER Metal3 ;
        RECT 0.000 1481.980 0.400 1482.380 ;
    END
  END Tile_X0Y0_FrameData[13]
  PIN Tile_X0Y0_FrameData[14]
    DIRECTION INPUT ;
    USE SIGNAL ;
    ANTENNAGATEAREA 1.445600 ;
    PORT
      LAYER Metal3 ;
        RECT 0.000 1489.540 0.400 1489.940 ;
    END
  END Tile_X0Y0_FrameData[14]
  PIN Tile_X0Y0_FrameData[15]
    DIRECTION INPUT ;
    USE SIGNAL ;
    ANTENNAGATEAREA 1.445600 ;
    PORT
      LAYER Metal3 ;
        RECT 0.000 1497.100 0.400 1497.500 ;
    END
  END Tile_X0Y0_FrameData[15]
  PIN Tile_X0Y0_FrameData[16]
    DIRECTION INPUT ;
    USE SIGNAL ;
    ANTENNAGATEAREA 1.626300 ;
    PORT
      LAYER Metal3 ;
        RECT 0.000 1504.660 0.400 1505.060 ;
    END
  END Tile_X0Y0_FrameData[16]
  PIN Tile_X0Y0_FrameData[17]
    DIRECTION INPUT ;
    USE SIGNAL ;
    ANTENNAGATEAREA 1.626300 ;
    PORT
      LAYER Metal3 ;
        RECT 0.000 1512.220 0.400 1512.620 ;
    END
  END Tile_X0Y0_FrameData[17]
  PIN Tile_X0Y0_FrameData[18]
    DIRECTION INPUT ;
    USE SIGNAL ;
    ANTENNAGATEAREA 1.626300 ;
    PORT
      LAYER Metal3 ;
        RECT 0.000 1519.780 0.400 1520.180 ;
    END
  END Tile_X0Y0_FrameData[18]
  PIN Tile_X0Y0_FrameData[19]
    DIRECTION INPUT ;
    USE SIGNAL ;
    ANTENNAGATEAREA 1.626300 ;
    PORT
      LAYER Metal3 ;
        RECT 0.000 1527.340 0.400 1527.740 ;
    END
  END Tile_X0Y0_FrameData[19]
  PIN Tile_X0Y0_FrameData[1]
    DIRECTION INPUT ;
    USE SIGNAL ;
    ANTENNAGATEAREA 1.445600 ;
    PORT
      LAYER Metal3 ;
        RECT 0.000 1391.260 0.400 1391.660 ;
    END
  END Tile_X0Y0_FrameData[1]
  PIN Tile_X0Y0_FrameData[20]
    DIRECTION INPUT ;
    USE SIGNAL ;
    ANTENNAGATEAREA 1.626300 ;
    PORT
      LAYER Metal3 ;
        RECT 0.000 1534.900 0.400 1535.300 ;
    END
  END Tile_X0Y0_FrameData[20]
  PIN Tile_X0Y0_FrameData[21]
    DIRECTION INPUT ;
    USE SIGNAL ;
    ANTENNAGATEAREA 1.626300 ;
    PORT
      LAYER Metal3 ;
        RECT 0.000 1542.460 0.400 1542.860 ;
    END
  END Tile_X0Y0_FrameData[21]
  PIN Tile_X0Y0_FrameData[22]
    DIRECTION INPUT ;
    USE SIGNAL ;
    ANTENNAGATEAREA 1.626300 ;
    PORT
      LAYER Metal3 ;
        RECT 0.000 1550.020 0.400 1550.420 ;
    END
  END Tile_X0Y0_FrameData[22]
  PIN Tile_X0Y0_FrameData[23]
    DIRECTION INPUT ;
    USE SIGNAL ;
    ANTENNAGATEAREA 1.626300 ;
    PORT
      LAYER Metal3 ;
        RECT 0.000 1557.580 0.400 1557.980 ;
    END
  END Tile_X0Y0_FrameData[23]
  PIN Tile_X0Y0_FrameData[24]
    DIRECTION INPUT ;
    USE SIGNAL ;
    ANTENNAGATEAREA 1.626300 ;
    PORT
      LAYER Metal3 ;
        RECT 0.000 1565.140 0.400 1565.540 ;
    END
  END Tile_X0Y0_FrameData[24]
  PIN Tile_X0Y0_FrameData[25]
    DIRECTION INPUT ;
    USE SIGNAL ;
    ANTENNAGATEAREA 1.626300 ;
    PORT
      LAYER Metal3 ;
        RECT 0.000 1572.700 0.400 1573.100 ;
    END
  END Tile_X0Y0_FrameData[25]
  PIN Tile_X0Y0_FrameData[26]
    DIRECTION INPUT ;
    USE SIGNAL ;
    ANTENNAGATEAREA 1.626300 ;
    PORT
      LAYER Metal3 ;
        RECT 0.000 1580.260 0.400 1580.660 ;
    END
  END Tile_X0Y0_FrameData[26]
  PIN Tile_X0Y0_FrameData[27]
    DIRECTION INPUT ;
    USE SIGNAL ;
    ANTENNAGATEAREA 1.626300 ;
    PORT
      LAYER Metal3 ;
        RECT 0.000 1587.820 0.400 1588.220 ;
    END
  END Tile_X0Y0_FrameData[27]
  PIN Tile_X0Y0_FrameData[28]
    DIRECTION INPUT ;
    USE SIGNAL ;
    ANTENNAGATEAREA 1.626300 ;
    PORT
      LAYER Metal3 ;
        RECT 0.000 1595.380 0.400 1595.780 ;
    END
  END Tile_X0Y0_FrameData[28]
  PIN Tile_X0Y0_FrameData[29]
    DIRECTION INPUT ;
    USE SIGNAL ;
    ANTENNAGATEAREA 1.626300 ;
    PORT
      LAYER Metal3 ;
        RECT 0.000 1602.940 0.400 1603.340 ;
    END
  END Tile_X0Y0_FrameData[29]
  PIN Tile_X0Y0_FrameData[2]
    DIRECTION INPUT ;
    USE SIGNAL ;
    ANTENNAGATEAREA 1.445600 ;
    PORT
      LAYER Metal3 ;
        RECT 0.000 1398.820 0.400 1399.220 ;
    END
  END Tile_X0Y0_FrameData[2]
  PIN Tile_X0Y0_FrameData[30]
    DIRECTION INPUT ;
    USE SIGNAL ;
    ANTENNAGATEAREA 1.626300 ;
    PORT
      LAYER Metal3 ;
        RECT 0.000 1610.500 0.400 1610.900 ;
    END
  END Tile_X0Y0_FrameData[30]
  PIN Tile_X0Y0_FrameData[31]
    DIRECTION INPUT ;
    USE SIGNAL ;
    ANTENNAGATEAREA 1.626300 ;
    PORT
      LAYER Metal3 ;
        RECT 0.000 1618.060 0.400 1618.460 ;
    END
  END Tile_X0Y0_FrameData[31]
  PIN Tile_X0Y0_FrameData[3]
    DIRECTION INPUT ;
    USE SIGNAL ;
    ANTENNAGATEAREA 1.445600 ;
    PORT
      LAYER Metal3 ;
        RECT 0.000 1406.380 0.400 1406.780 ;
    END
  END Tile_X0Y0_FrameData[3]
  PIN Tile_X0Y0_FrameData[4]
    DIRECTION INPUT ;
    USE SIGNAL ;
    ANTENNAGATEAREA 1.445600 ;
    PORT
      LAYER Metal3 ;
        RECT 0.000 1413.940 0.400 1414.340 ;
    END
  END Tile_X0Y0_FrameData[4]
  PIN Tile_X0Y0_FrameData[5]
    DIRECTION INPUT ;
    USE SIGNAL ;
    ANTENNAGATEAREA 1.445600 ;
    PORT
      LAYER Metal3 ;
        RECT 0.000 1421.500 0.400 1421.900 ;
    END
  END Tile_X0Y0_FrameData[5]
  PIN Tile_X0Y0_FrameData[6]
    DIRECTION INPUT ;
    USE SIGNAL ;
    ANTENNAGATEAREA 1.445600 ;
    PORT
      LAYER Metal3 ;
        RECT 0.000 1429.060 0.400 1429.460 ;
    END
  END Tile_X0Y0_FrameData[6]
  PIN Tile_X0Y0_FrameData[7]
    DIRECTION INPUT ;
    USE SIGNAL ;
    ANTENNAGATEAREA 1.445600 ;
    PORT
      LAYER Metal3 ;
        RECT 0.000 1436.620 0.400 1437.020 ;
    END
  END Tile_X0Y0_FrameData[7]
  PIN Tile_X0Y0_FrameData[8]
    DIRECTION INPUT ;
    USE SIGNAL ;
    ANTENNAGATEAREA 1.445600 ;
    PORT
      LAYER Metal3 ;
        RECT 0.000 1444.180 0.400 1444.580 ;
    END
  END Tile_X0Y0_FrameData[8]
  PIN Tile_X0Y0_FrameData[9]
    DIRECTION INPUT ;
    USE SIGNAL ;
    ANTENNAGATEAREA 1.445600 ;
    PORT
      LAYER Metal3 ;
        RECT 0.000 1451.740 0.400 1452.140 ;
    END
  END Tile_X0Y0_FrameData[9]
  PIN Tile_X0Y0_FrameData_O[0]
    DIRECTION OUTPUT ;
    USE SIGNAL ;
    ANTENNADIFFAREA 2.724000 ;
    PORT
      LAYER Metal3 ;
        RECT 115.280 1572.700 115.680 1573.100 ;
    END
  END Tile_X0Y0_FrameData_O[0]
  PIN Tile_X0Y0_FrameData_O[10]
    DIRECTION OUTPUT ;
    USE SIGNAL ;
    ANTENNADIFFAREA 2.724000 ;
    PORT
      LAYER Metal3 ;
        RECT 115.280 1589.500 115.680 1589.900 ;
    END
  END Tile_X0Y0_FrameData_O[10]
  PIN Tile_X0Y0_FrameData_O[11]
    DIRECTION OUTPUT ;
    USE SIGNAL ;
    ANTENNADIFFAREA 2.724000 ;
    PORT
      LAYER Metal3 ;
        RECT 115.280 1591.180 115.680 1591.580 ;
    END
  END Tile_X0Y0_FrameData_O[11]
  PIN Tile_X0Y0_FrameData_O[12]
    DIRECTION OUTPUT ;
    USE SIGNAL ;
    ANTENNADIFFAREA 2.724000 ;
    PORT
      LAYER Metal3 ;
        RECT 115.280 1592.860 115.680 1593.260 ;
    END
  END Tile_X0Y0_FrameData_O[12]
  PIN Tile_X0Y0_FrameData_O[13]
    DIRECTION OUTPUT ;
    USE SIGNAL ;
    ANTENNADIFFAREA 2.724000 ;
    PORT
      LAYER Metal3 ;
        RECT 115.280 1594.540 115.680 1594.940 ;
    END
  END Tile_X0Y0_FrameData_O[13]
  PIN Tile_X0Y0_FrameData_O[14]
    DIRECTION OUTPUT ;
    USE SIGNAL ;
    ANTENNADIFFAREA 2.724000 ;
    PORT
      LAYER Metal3 ;
        RECT 115.280 1596.220 115.680 1596.620 ;
    END
  END Tile_X0Y0_FrameData_O[14]
  PIN Tile_X0Y0_FrameData_O[15]
    DIRECTION OUTPUT ;
    USE SIGNAL ;
    ANTENNADIFFAREA 2.724000 ;
    PORT
      LAYER Metal3 ;
        RECT 115.280 1597.900 115.680 1598.300 ;
    END
  END Tile_X0Y0_FrameData_O[15]
  PIN Tile_X0Y0_FrameData_O[16]
    DIRECTION OUTPUT ;
    USE SIGNAL ;
    ANTENNADIFFAREA 2.724000 ;
    PORT
      LAYER Metal3 ;
        RECT 115.280 1599.580 115.680 1599.980 ;
    END
  END Tile_X0Y0_FrameData_O[16]
  PIN Tile_X0Y0_FrameData_O[17]
    DIRECTION OUTPUT ;
    USE SIGNAL ;
    ANTENNADIFFAREA 2.724000 ;
    PORT
      LAYER Metal3 ;
        RECT 115.280 1601.260 115.680 1601.660 ;
    END
  END Tile_X0Y0_FrameData_O[17]
  PIN Tile_X0Y0_FrameData_O[18]
    DIRECTION OUTPUT ;
    USE SIGNAL ;
    ANTENNADIFFAREA 2.724000 ;
    PORT
      LAYER Metal3 ;
        RECT 115.280 1602.940 115.680 1603.340 ;
    END
  END Tile_X0Y0_FrameData_O[18]
  PIN Tile_X0Y0_FrameData_O[19]
    DIRECTION OUTPUT ;
    USE SIGNAL ;
    ANTENNADIFFAREA 2.724000 ;
    PORT
      LAYER Metal3 ;
        RECT 115.280 1604.620 115.680 1605.020 ;
    END
  END Tile_X0Y0_FrameData_O[19]
  PIN Tile_X0Y0_FrameData_O[1]
    DIRECTION OUTPUT ;
    USE SIGNAL ;
    ANTENNADIFFAREA 2.724000 ;
    PORT
      LAYER Metal3 ;
        RECT 115.280 1574.380 115.680 1574.780 ;
    END
  END Tile_X0Y0_FrameData_O[1]
  PIN Tile_X0Y0_FrameData_O[20]
    DIRECTION OUTPUT ;
    USE SIGNAL ;
    ANTENNADIFFAREA 2.724000 ;
    PORT
      LAYER Metal3 ;
        RECT 115.280 1606.300 115.680 1606.700 ;
    END
  END Tile_X0Y0_FrameData_O[20]
  PIN Tile_X0Y0_FrameData_O[21]
    DIRECTION OUTPUT ;
    USE SIGNAL ;
    ANTENNADIFFAREA 2.724000 ;
    PORT
      LAYER Metal3 ;
        RECT 115.280 1607.980 115.680 1608.380 ;
    END
  END Tile_X0Y0_FrameData_O[21]
  PIN Tile_X0Y0_FrameData_O[22]
    DIRECTION OUTPUT ;
    USE SIGNAL ;
    ANTENNADIFFAREA 2.724000 ;
    PORT
      LAYER Metal3 ;
        RECT 115.280 1609.660 115.680 1610.060 ;
    END
  END Tile_X0Y0_FrameData_O[22]
  PIN Tile_X0Y0_FrameData_O[23]
    DIRECTION OUTPUT ;
    USE SIGNAL ;
    ANTENNADIFFAREA 2.724000 ;
    PORT
      LAYER Metal3 ;
        RECT 115.280 1611.340 115.680 1611.740 ;
    END
  END Tile_X0Y0_FrameData_O[23]
  PIN Tile_X0Y0_FrameData_O[24]
    DIRECTION OUTPUT ;
    USE SIGNAL ;
    ANTENNADIFFAREA 2.724000 ;
    PORT
      LAYER Metal3 ;
        RECT 115.280 1613.020 115.680 1613.420 ;
    END
  END Tile_X0Y0_FrameData_O[24]
  PIN Tile_X0Y0_FrameData_O[25]
    DIRECTION OUTPUT ;
    USE SIGNAL ;
    ANTENNADIFFAREA 2.724000 ;
    PORT
      LAYER Metal3 ;
        RECT 115.280 1614.700 115.680 1615.100 ;
    END
  END Tile_X0Y0_FrameData_O[25]
  PIN Tile_X0Y0_FrameData_O[26]
    DIRECTION OUTPUT ;
    USE SIGNAL ;
    ANTENNADIFFAREA 2.724000 ;
    PORT
      LAYER Metal3 ;
        RECT 115.280 1616.380 115.680 1616.780 ;
    END
  END Tile_X0Y0_FrameData_O[26]
  PIN Tile_X0Y0_FrameData_O[27]
    DIRECTION OUTPUT ;
    USE SIGNAL ;
    ANTENNADIFFAREA 2.724000 ;
    PORT
      LAYER Metal3 ;
        RECT 115.280 1618.060 115.680 1618.460 ;
    END
  END Tile_X0Y0_FrameData_O[27]
  PIN Tile_X0Y0_FrameData_O[28]
    DIRECTION OUTPUT ;
    USE SIGNAL ;
    ANTENNADIFFAREA 2.724000 ;
    PORT
      LAYER Metal3 ;
        RECT 115.280 1619.740 115.680 1620.140 ;
    END
  END Tile_X0Y0_FrameData_O[28]
  PIN Tile_X0Y0_FrameData_O[29]
    DIRECTION OUTPUT ;
    USE SIGNAL ;
    ANTENNADIFFAREA 2.724000 ;
    PORT
      LAYER Metal3 ;
        RECT 115.280 1621.420 115.680 1621.820 ;
    END
  END Tile_X0Y0_FrameData_O[29]
  PIN Tile_X0Y0_FrameData_O[2]
    DIRECTION OUTPUT ;
    USE SIGNAL ;
    ANTENNADIFFAREA 2.724000 ;
    PORT
      LAYER Metal3 ;
        RECT 115.280 1576.060 115.680 1576.460 ;
    END
  END Tile_X0Y0_FrameData_O[2]
  PIN Tile_X0Y0_FrameData_O[30]
    DIRECTION OUTPUT ;
    USE SIGNAL ;
    ANTENNADIFFAREA 2.724000 ;
    PORT
      LAYER Metal3 ;
        RECT 115.280 1623.100 115.680 1623.500 ;
    END
  END Tile_X0Y0_FrameData_O[30]
  PIN Tile_X0Y0_FrameData_O[31]
    DIRECTION OUTPUT ;
    USE SIGNAL ;
    ANTENNADIFFAREA 2.724000 ;
    PORT
      LAYER Metal3 ;
        RECT 115.280 1624.780 115.680 1625.180 ;
    END
  END Tile_X0Y0_FrameData_O[31]
  PIN Tile_X0Y0_FrameData_O[3]
    DIRECTION OUTPUT ;
    USE SIGNAL ;
    ANTENNADIFFAREA 2.724000 ;
    PORT
      LAYER Metal3 ;
        RECT 115.280 1577.740 115.680 1578.140 ;
    END
  END Tile_X0Y0_FrameData_O[3]
  PIN Tile_X0Y0_FrameData_O[4]
    DIRECTION OUTPUT ;
    USE SIGNAL ;
    ANTENNADIFFAREA 2.724000 ;
    PORT
      LAYER Metal3 ;
        RECT 115.280 1579.420 115.680 1579.820 ;
    END
  END Tile_X0Y0_FrameData_O[4]
  PIN Tile_X0Y0_FrameData_O[5]
    DIRECTION OUTPUT ;
    USE SIGNAL ;
    ANTENNADIFFAREA 2.724000 ;
    PORT
      LAYER Metal3 ;
        RECT 115.280 1581.100 115.680 1581.500 ;
    END
  END Tile_X0Y0_FrameData_O[5]
  PIN Tile_X0Y0_FrameData_O[6]
    DIRECTION OUTPUT ;
    USE SIGNAL ;
    ANTENNADIFFAREA 2.724000 ;
    PORT
      LAYER Metal3 ;
        RECT 115.280 1582.780 115.680 1583.180 ;
    END
  END Tile_X0Y0_FrameData_O[6]
  PIN Tile_X0Y0_FrameData_O[7]
    DIRECTION OUTPUT ;
    USE SIGNAL ;
    ANTENNADIFFAREA 2.724000 ;
    PORT
      LAYER Metal3 ;
        RECT 115.280 1584.460 115.680 1584.860 ;
    END
  END Tile_X0Y0_FrameData_O[7]
  PIN Tile_X0Y0_FrameData_O[8]
    DIRECTION OUTPUT ;
    USE SIGNAL ;
    ANTENNADIFFAREA 2.724000 ;
    PORT
      LAYER Metal3 ;
        RECT 115.280 1586.140 115.680 1586.540 ;
    END
  END Tile_X0Y0_FrameData_O[8]
  PIN Tile_X0Y0_FrameData_O[9]
    DIRECTION OUTPUT ;
    USE SIGNAL ;
    ANTENNADIFFAREA 2.724000 ;
    PORT
      LAYER Metal3 ;
        RECT 115.280 1587.820 115.680 1588.220 ;
    END
  END Tile_X0Y0_FrameData_O[9]
  PIN Tile_X0Y0_FrameStrobe_O[0]
    DIRECTION OUTPUT ;
    USE SIGNAL ;
    ANTENNADIFFAREA 2.724000 ;
    PORT
      LAYER Metal2 ;
        RECT 94.360 1632.560 94.760 1632.960 ;
    END
  END Tile_X0Y0_FrameStrobe_O[0]
  PIN Tile_X0Y0_FrameStrobe_O[10]
    DIRECTION OUTPUT ;
    USE SIGNAL ;
    ANTENNADIFFAREA 2.724000 ;
    PORT
      LAYER Metal2 ;
        RECT 103.960 1632.560 104.360 1632.960 ;
    END
  END Tile_X0Y0_FrameStrobe_O[10]
  PIN Tile_X0Y0_FrameStrobe_O[11]
    DIRECTION OUTPUT ;
    USE SIGNAL ;
    ANTENNADIFFAREA 2.724000 ;
    PORT
      LAYER Metal2 ;
        RECT 104.920 1632.560 105.320 1632.960 ;
    END
  END Tile_X0Y0_FrameStrobe_O[11]
  PIN Tile_X0Y0_FrameStrobe_O[12]
    DIRECTION OUTPUT ;
    USE SIGNAL ;
    ANTENNADIFFAREA 2.724000 ;
    PORT
      LAYER Metal2 ;
        RECT 105.880 1632.560 106.280 1632.960 ;
    END
  END Tile_X0Y0_FrameStrobe_O[12]
  PIN Tile_X0Y0_FrameStrobe_O[13]
    DIRECTION OUTPUT ;
    USE SIGNAL ;
    ANTENNADIFFAREA 2.724000 ;
    PORT
      LAYER Metal2 ;
        RECT 106.840 1632.560 107.240 1632.960 ;
    END
  END Tile_X0Y0_FrameStrobe_O[13]
  PIN Tile_X0Y0_FrameStrobe_O[14]
    DIRECTION OUTPUT ;
    USE SIGNAL ;
    ANTENNADIFFAREA 2.724000 ;
    PORT
      LAYER Metal2 ;
        RECT 107.800 1632.560 108.200 1632.960 ;
    END
  END Tile_X0Y0_FrameStrobe_O[14]
  PIN Tile_X0Y0_FrameStrobe_O[15]
    DIRECTION OUTPUT ;
    USE SIGNAL ;
    ANTENNADIFFAREA 2.724000 ;
    PORT
      LAYER Metal2 ;
        RECT 108.760 1632.560 109.160 1632.960 ;
    END
  END Tile_X0Y0_FrameStrobe_O[15]
  PIN Tile_X0Y0_FrameStrobe_O[16]
    DIRECTION OUTPUT ;
    USE SIGNAL ;
    ANTENNADIFFAREA 2.724000 ;
    PORT
      LAYER Metal2 ;
        RECT 109.720 1632.560 110.120 1632.960 ;
    END
  END Tile_X0Y0_FrameStrobe_O[16]
  PIN Tile_X0Y0_FrameStrobe_O[17]
    DIRECTION OUTPUT ;
    USE SIGNAL ;
    ANTENNADIFFAREA 2.724000 ;
    PORT
      LAYER Metal2 ;
        RECT 110.680 1632.560 111.080 1632.960 ;
    END
  END Tile_X0Y0_FrameStrobe_O[17]
  PIN Tile_X0Y0_FrameStrobe_O[18]
    DIRECTION OUTPUT ;
    USE SIGNAL ;
    ANTENNADIFFAREA 2.724000 ;
    PORT
      LAYER Metal2 ;
        RECT 111.640 1632.560 112.040 1632.960 ;
    END
  END Tile_X0Y0_FrameStrobe_O[18]
  PIN Tile_X0Y0_FrameStrobe_O[19]
    DIRECTION OUTPUT ;
    USE SIGNAL ;
    ANTENNADIFFAREA 2.724000 ;
    PORT
      LAYER Metal2 ;
        RECT 112.600 1632.560 113.000 1632.960 ;
    END
  END Tile_X0Y0_FrameStrobe_O[19]
  PIN Tile_X0Y0_FrameStrobe_O[1]
    DIRECTION OUTPUT ;
    USE SIGNAL ;
    ANTENNADIFFAREA 2.724000 ;
    PORT
      LAYER Metal2 ;
        RECT 95.320 1632.560 95.720 1632.960 ;
    END
  END Tile_X0Y0_FrameStrobe_O[1]
  PIN Tile_X0Y0_FrameStrobe_O[2]
    DIRECTION OUTPUT ;
    USE SIGNAL ;
    ANTENNADIFFAREA 2.724000 ;
    PORT
      LAYER Metal2 ;
        RECT 96.280 1632.560 96.680 1632.960 ;
    END
  END Tile_X0Y0_FrameStrobe_O[2]
  PIN Tile_X0Y0_FrameStrobe_O[3]
    DIRECTION OUTPUT ;
    USE SIGNAL ;
    ANTENNADIFFAREA 2.724000 ;
    PORT
      LAYER Metal2 ;
        RECT 97.240 1632.560 97.640 1632.960 ;
    END
  END Tile_X0Y0_FrameStrobe_O[3]
  PIN Tile_X0Y0_FrameStrobe_O[4]
    DIRECTION OUTPUT ;
    USE SIGNAL ;
    ANTENNADIFFAREA 2.724000 ;
    PORT
      LAYER Metal2 ;
        RECT 98.200 1632.560 98.600 1632.960 ;
    END
  END Tile_X0Y0_FrameStrobe_O[4]
  PIN Tile_X0Y0_FrameStrobe_O[5]
    DIRECTION OUTPUT ;
    USE SIGNAL ;
    ANTENNADIFFAREA 2.724000 ;
    PORT
      LAYER Metal2 ;
        RECT 99.160 1632.560 99.560 1632.960 ;
    END
  END Tile_X0Y0_FrameStrobe_O[5]
  PIN Tile_X0Y0_FrameStrobe_O[6]
    DIRECTION OUTPUT ;
    USE SIGNAL ;
    ANTENNADIFFAREA 2.724000 ;
    PORT
      LAYER Metal2 ;
        RECT 100.120 1632.560 100.520 1632.960 ;
    END
  END Tile_X0Y0_FrameStrobe_O[6]
  PIN Tile_X0Y0_FrameStrobe_O[7]
    DIRECTION OUTPUT ;
    USE SIGNAL ;
    ANTENNADIFFAREA 2.724000 ;
    PORT
      LAYER Metal2 ;
        RECT 101.080 1632.560 101.480 1632.960 ;
    END
  END Tile_X0Y0_FrameStrobe_O[7]
  PIN Tile_X0Y0_FrameStrobe_O[8]
    DIRECTION OUTPUT ;
    USE SIGNAL ;
    ANTENNADIFFAREA 2.724000 ;
    PORT
      LAYER Metal2 ;
        RECT 102.040 1632.560 102.440 1632.960 ;
    END
  END Tile_X0Y0_FrameStrobe_O[8]
  PIN Tile_X0Y0_FrameStrobe_O[9]
    DIRECTION OUTPUT ;
    USE SIGNAL ;
    ANTENNADIFFAREA 2.724000 ;
    PORT
      LAYER Metal2 ;
        RECT 103.000 1632.560 103.400 1632.960 ;
    END
  END Tile_X0Y0_FrameStrobe_O[9]
  PIN Tile_X0Y0_N1BEG[0]
    DIRECTION OUTPUT ;
    USE SIGNAL ;
    ANTENNADIFFAREA 2.724000 ;
    PORT
      LAYER Metal2 ;
        RECT 1.240 1632.560 1.640 1632.960 ;
    END
  END Tile_X0Y0_N1BEG[0]
  PIN Tile_X0Y0_N1BEG[1]
    DIRECTION OUTPUT ;
    USE SIGNAL ;
    ANTENNADIFFAREA 2.724000 ;
    PORT
      LAYER Metal2 ;
        RECT 2.200 1632.560 2.600 1632.960 ;
    END
  END Tile_X0Y0_N1BEG[1]
  PIN Tile_X0Y0_N1BEG[2]
    DIRECTION OUTPUT ;
    USE SIGNAL ;
    ANTENNADIFFAREA 2.724000 ;
    PORT
      LAYER Metal2 ;
        RECT 3.160 1632.560 3.560 1632.960 ;
    END
  END Tile_X0Y0_N1BEG[2]
  PIN Tile_X0Y0_N1BEG[3]
    DIRECTION OUTPUT ;
    USE SIGNAL ;
    ANTENNADIFFAREA 2.724000 ;
    PORT
      LAYER Metal2 ;
        RECT 4.120 1632.560 4.520 1632.960 ;
    END
  END Tile_X0Y0_N1BEG[3]
  PIN Tile_X0Y0_N2BEG[0]
    DIRECTION OUTPUT ;
    USE SIGNAL ;
    ANTENNADIFFAREA 2.724000 ;
    PORT
      LAYER Metal2 ;
        RECT 7.000 1632.560 7.400 1632.960 ;
    END
  END Tile_X0Y0_N2BEG[0]
  PIN Tile_X0Y0_N2BEG[1]
    DIRECTION OUTPUT ;
    USE SIGNAL ;
    ANTENNADIFFAREA 2.724000 ;
    PORT
      LAYER Metal2 ;
        RECT 7.960 1632.560 8.360 1632.960 ;
    END
  END Tile_X0Y0_N2BEG[1]
  PIN Tile_X0Y0_N2BEG[2]
    DIRECTION OUTPUT ;
    USE SIGNAL ;
    ANTENNADIFFAREA 2.724000 ;
    PORT
      LAYER Metal2 ;
        RECT 8.920 1632.560 9.320 1632.960 ;
    END
  END Tile_X0Y0_N2BEG[2]
  PIN Tile_X0Y0_N2BEG[3]
    DIRECTION OUTPUT ;
    USE SIGNAL ;
    ANTENNADIFFAREA 2.724000 ;
    PORT
      LAYER Metal2 ;
        RECT 9.880 1632.560 10.280 1632.960 ;
    END
  END Tile_X0Y0_N2BEG[3]
  PIN Tile_X0Y0_N2BEG[4]
    DIRECTION OUTPUT ;
    USE SIGNAL ;
    ANTENNADIFFAREA 2.724000 ;
    PORT
      LAYER Metal2 ;
        RECT 10.840 1632.560 11.240 1632.960 ;
    END
  END Tile_X0Y0_N2BEG[4]
  PIN Tile_X0Y0_N2BEG[5]
    DIRECTION OUTPUT ;
    USE SIGNAL ;
    ANTENNADIFFAREA 2.724000 ;
    PORT
      LAYER Metal2 ;
        RECT 11.800 1632.560 12.200 1632.960 ;
    END
  END Tile_X0Y0_N2BEG[5]
  PIN Tile_X0Y0_N2BEG[6]
    DIRECTION OUTPUT ;
    USE SIGNAL ;
    ANTENNADIFFAREA 2.724000 ;
    PORT
      LAYER Metal2 ;
        RECT 12.760 1632.560 13.160 1632.960 ;
    END
  END Tile_X0Y0_N2BEG[6]
  PIN Tile_X0Y0_N2BEG[7]
    DIRECTION OUTPUT ;
    USE SIGNAL ;
    ANTENNADIFFAREA 2.724000 ;
    PORT
      LAYER Metal2 ;
        RECT 13.720 1632.560 14.120 1632.960 ;
    END
  END Tile_X0Y0_N2BEG[7]
  PIN Tile_X0Y0_N2BEGb[0]
    DIRECTION OUTPUT ;
    USE SIGNAL ;
    ANTENNADIFFAREA 2.724000 ;
    PORT
      LAYER Metal2 ;
        RECT 16.600 1632.560 17.000 1632.960 ;
    END
  END Tile_X0Y0_N2BEGb[0]
  PIN Tile_X0Y0_N2BEGb[1]
    DIRECTION OUTPUT ;
    USE SIGNAL ;
    ANTENNADIFFAREA 2.724000 ;
    PORT
      LAYER Metal2 ;
        RECT 17.560 1632.560 17.960 1632.960 ;
    END
  END Tile_X0Y0_N2BEGb[1]
  PIN Tile_X0Y0_N2BEGb[2]
    DIRECTION OUTPUT ;
    USE SIGNAL ;
    ANTENNADIFFAREA 2.724000 ;
    PORT
      LAYER Metal2 ;
        RECT 18.520 1632.560 18.920 1632.960 ;
    END
  END Tile_X0Y0_N2BEGb[2]
  PIN Tile_X0Y0_N2BEGb[3]
    DIRECTION OUTPUT ;
    USE SIGNAL ;
    ANTENNADIFFAREA 2.724000 ;
    PORT
      LAYER Metal2 ;
        RECT 19.480 1632.560 19.880 1632.960 ;
    END
  END Tile_X0Y0_N2BEGb[3]
  PIN Tile_X0Y0_N2BEGb[4]
    DIRECTION OUTPUT ;
    USE SIGNAL ;
    ANTENNADIFFAREA 2.724000 ;
    PORT
      LAYER Metal2 ;
        RECT 20.440 1632.560 20.840 1632.960 ;
    END
  END Tile_X0Y0_N2BEGb[4]
  PIN Tile_X0Y0_N2BEGb[5]
    DIRECTION OUTPUT ;
    USE SIGNAL ;
    ANTENNADIFFAREA 2.724000 ;
    PORT
      LAYER Metal2 ;
        RECT 21.400 1632.560 21.800 1632.960 ;
    END
  END Tile_X0Y0_N2BEGb[5]
  PIN Tile_X0Y0_N2BEGb[6]
    DIRECTION OUTPUT ;
    USE SIGNAL ;
    ANTENNADIFFAREA 2.724000 ;
    PORT
      LAYER Metal2 ;
        RECT 22.360 1632.560 22.760 1632.960 ;
    END
  END Tile_X0Y0_N2BEGb[6]
  PIN Tile_X0Y0_N2BEGb[7]
    DIRECTION OUTPUT ;
    USE SIGNAL ;
    ANTENNADIFFAREA 2.724000 ;
    PORT
      LAYER Metal2 ;
        RECT 23.320 1632.560 23.720 1632.960 ;
    END
  END Tile_X0Y0_N2BEGb[7]
  PIN Tile_X0Y0_N4BEG[0]
    DIRECTION OUTPUT ;
    USE SIGNAL ;
    ANTENNADIFFAREA 2.724000 ;
    PORT
      LAYER Metal2 ;
        RECT 27.160 1632.560 27.560 1632.960 ;
    END
  END Tile_X0Y0_N4BEG[0]
  PIN Tile_X0Y0_N4BEG[10]
    DIRECTION OUTPUT ;
    USE SIGNAL ;
    ANTENNADIFFAREA 2.724000 ;
    PORT
      LAYER Metal2 ;
        RECT 36.760 1632.560 37.160 1632.960 ;
    END
  END Tile_X0Y0_N4BEG[10]
  PIN Tile_X0Y0_N4BEG[11]
    DIRECTION OUTPUT ;
    USE SIGNAL ;
    ANTENNADIFFAREA 2.724000 ;
    PORT
      LAYER Metal2 ;
        RECT 37.720 1632.560 38.120 1632.960 ;
    END
  END Tile_X0Y0_N4BEG[11]
  PIN Tile_X0Y0_N4BEG[12]
    DIRECTION OUTPUT ;
    USE SIGNAL ;
    ANTENNADIFFAREA 2.724000 ;
    PORT
      LAYER Metal2 ;
        RECT 38.680 1632.560 39.080 1632.960 ;
    END
  END Tile_X0Y0_N4BEG[12]
  PIN Tile_X0Y0_N4BEG[13]
    DIRECTION OUTPUT ;
    USE SIGNAL ;
    ANTENNADIFFAREA 2.724000 ;
    PORT
      LAYER Metal2 ;
        RECT 39.640 1632.560 40.040 1632.960 ;
    END
  END Tile_X0Y0_N4BEG[13]
  PIN Tile_X0Y0_N4BEG[14]
    DIRECTION OUTPUT ;
    USE SIGNAL ;
    ANTENNADIFFAREA 2.724000 ;
    PORT
      LAYER Metal2 ;
        RECT 40.600 1632.560 41.000 1632.960 ;
    END
  END Tile_X0Y0_N4BEG[14]
  PIN Tile_X0Y0_N4BEG[15]
    DIRECTION OUTPUT ;
    USE SIGNAL ;
    ANTENNADIFFAREA 2.724000 ;
    PORT
      LAYER Metal2 ;
        RECT 41.560 1632.560 41.960 1632.960 ;
    END
  END Tile_X0Y0_N4BEG[15]
  PIN Tile_X0Y0_N4BEG[1]
    DIRECTION OUTPUT ;
    USE SIGNAL ;
    ANTENNADIFFAREA 2.724000 ;
    PORT
      LAYER Metal2 ;
        RECT 28.120 1632.560 28.520 1632.960 ;
    END
  END Tile_X0Y0_N4BEG[1]
  PIN Tile_X0Y0_N4BEG[2]
    DIRECTION OUTPUT ;
    USE SIGNAL ;
    ANTENNADIFFAREA 2.724000 ;
    PORT
      LAYER Metal2 ;
        RECT 29.080 1632.560 29.480 1632.960 ;
    END
  END Tile_X0Y0_N4BEG[2]
  PIN Tile_X0Y0_N4BEG[3]
    DIRECTION OUTPUT ;
    USE SIGNAL ;
    ANTENNADIFFAREA 2.724000 ;
    PORT
      LAYER Metal2 ;
        RECT 30.040 1632.560 30.440 1632.960 ;
    END
  END Tile_X0Y0_N4BEG[3]
  PIN Tile_X0Y0_N4BEG[4]
    DIRECTION OUTPUT ;
    USE SIGNAL ;
    ANTENNADIFFAREA 2.724000 ;
    PORT
      LAYER Metal2 ;
        RECT 31.000 1632.560 31.400 1632.960 ;
    END
  END Tile_X0Y0_N4BEG[4]
  PIN Tile_X0Y0_N4BEG[5]
    DIRECTION OUTPUT ;
    USE SIGNAL ;
    ANTENNADIFFAREA 2.724000 ;
    PORT
      LAYER Metal2 ;
        RECT 31.960 1632.560 32.360 1632.960 ;
    END
  END Tile_X0Y0_N4BEG[5]
  PIN Tile_X0Y0_N4BEG[6]
    DIRECTION OUTPUT ;
    USE SIGNAL ;
    ANTENNADIFFAREA 2.724000 ;
    PORT
      LAYER Metal2 ;
        RECT 32.920 1632.560 33.320 1632.960 ;
    END
  END Tile_X0Y0_N4BEG[6]
  PIN Tile_X0Y0_N4BEG[7]
    DIRECTION OUTPUT ;
    USE SIGNAL ;
    ANTENNADIFFAREA 2.724000 ;
    PORT
      LAYER Metal2 ;
        RECT 33.880 1632.560 34.280 1632.960 ;
    END
  END Tile_X0Y0_N4BEG[7]
  PIN Tile_X0Y0_N4BEG[8]
    DIRECTION OUTPUT ;
    USE SIGNAL ;
    ANTENNADIFFAREA 2.724000 ;
    PORT
      LAYER Metal2 ;
        RECT 34.840 1632.560 35.240 1632.960 ;
    END
  END Tile_X0Y0_N4BEG[8]
  PIN Tile_X0Y0_N4BEG[9]
    DIRECTION OUTPUT ;
    USE SIGNAL ;
    ANTENNADIFFAREA 2.724000 ;
    PORT
      LAYER Metal2 ;
        RECT 35.800 1632.560 36.200 1632.960 ;
    END
  END Tile_X0Y0_N4BEG[9]
  PIN Tile_X0Y0_S1END[0]
    DIRECTION INPUT ;
    USE SIGNAL ;
    ANTENNAGATEAREA 1.279200 ;
    PORT
      LAYER Metal2 ;
        RECT 46.360 1632.560 46.760 1632.960 ;
    END
  END Tile_X0Y0_S1END[0]
  PIN Tile_X0Y0_S1END[1]
    DIRECTION INPUT ;
    USE SIGNAL ;
    ANTENNAGATEAREA 1.279200 ;
    PORT
      LAYER Metal2 ;
        RECT 47.320 1632.560 47.720 1632.960 ;
    END
  END Tile_X0Y0_S1END[1]
  PIN Tile_X0Y0_S1END[2]
    DIRECTION INPUT ;
    USE SIGNAL ;
    ANTENNAGATEAREA 1.279200 ;
    PORT
      LAYER Metal2 ;
        RECT 48.280 1632.560 48.680 1632.960 ;
    END
  END Tile_X0Y0_S1END[2]
  PIN Tile_X0Y0_S1END[3]
    DIRECTION INPUT ;
    USE SIGNAL ;
    ANTENNAGATEAREA 1.279200 ;
    PORT
      LAYER Metal2 ;
        RECT 49.240 1632.560 49.640 1632.960 ;
    END
  END Tile_X0Y0_S1END[3]
  PIN Tile_X0Y0_S2END[0]
    DIRECTION INPUT ;
    USE SIGNAL ;
    ANTENNAGATEAREA 0.213200 ;
    PORT
      LAYER Metal2 ;
        RECT 61.720 1632.560 62.120 1632.960 ;
    END
  END Tile_X0Y0_S2END[0]
  PIN Tile_X0Y0_S2END[1]
    DIRECTION INPUT ;
    USE SIGNAL ;
    ANTENNAGATEAREA 0.213200 ;
    PORT
      LAYER Metal2 ;
        RECT 62.680 1632.560 63.080 1632.960 ;
    END
  END Tile_X0Y0_S2END[1]
  PIN Tile_X0Y0_S2END[2]
    DIRECTION INPUT ;
    USE SIGNAL ;
    ANTENNAGATEAREA 0.213200 ;
    PORT
      LAYER Metal2 ;
        RECT 63.640 1632.560 64.040 1632.960 ;
    END
  END Tile_X0Y0_S2END[2]
  PIN Tile_X0Y0_S2END[3]
    DIRECTION INPUT ;
    USE SIGNAL ;
    ANTENNAGATEAREA 0.213200 ;
    PORT
      LAYER Metal2 ;
        RECT 64.600 1632.560 65.000 1632.960 ;
    END
  END Tile_X0Y0_S2END[3]
  PIN Tile_X0Y0_S2END[4]
    DIRECTION INPUT ;
    USE SIGNAL ;
    ANTENNAGATEAREA 0.213200 ;
    PORT
      LAYER Metal2 ;
        RECT 65.560 1632.560 65.960 1632.960 ;
    END
  END Tile_X0Y0_S2END[4]
  PIN Tile_X0Y0_S2END[5]
    DIRECTION INPUT ;
    USE SIGNAL ;
    ANTENNAGATEAREA 0.213200 ;
    PORT
      LAYER Metal2 ;
        RECT 66.520 1632.560 66.920 1632.960 ;
    END
  END Tile_X0Y0_S2END[5]
  PIN Tile_X0Y0_S2END[6]
    DIRECTION INPUT ;
    USE SIGNAL ;
    ANTENNAGATEAREA 0.213200 ;
    PORT
      LAYER Metal2 ;
        RECT 67.480 1632.560 67.880 1632.960 ;
    END
  END Tile_X0Y0_S2END[6]
  PIN Tile_X0Y0_S2END[7]
    DIRECTION INPUT ;
    USE SIGNAL ;
    ANTENNAGATEAREA 0.213200 ;
    PORT
      LAYER Metal2 ;
        RECT 68.440 1632.560 68.840 1632.960 ;
    END
  END Tile_X0Y0_S2END[7]
  PIN Tile_X0Y0_S2MID[0]
    DIRECTION INPUT ;
    USE SIGNAL ;
    ANTENNAGATEAREA 0.426400 ;
    PORT
      LAYER Metal2 ;
        RECT 52.120 1632.560 52.520 1632.960 ;
    END
  END Tile_X0Y0_S2MID[0]
  PIN Tile_X0Y0_S2MID[1]
    DIRECTION INPUT ;
    USE SIGNAL ;
    ANTENNAGATEAREA 0.426400 ;
    PORT
      LAYER Metal2 ;
        RECT 53.080 1632.560 53.480 1632.960 ;
    END
  END Tile_X0Y0_S2MID[1]
  PIN Tile_X0Y0_S2MID[2]
    DIRECTION INPUT ;
    USE SIGNAL ;
    ANTENNAGATEAREA 0.426400 ;
    ANTENNADIFFAREA 4.030800 ;
    PORT
      LAYER Metal2 ;
        RECT 54.040 1632.560 54.440 1632.960 ;
    END
  END Tile_X0Y0_S2MID[2]
  PIN Tile_X0Y0_S2MID[3]
    DIRECTION INPUT ;
    USE SIGNAL ;
    ANTENNAGATEAREA 0.426400 ;
    ANTENNADIFFAREA 8.061600 ;
    PORT
      LAYER Metal2 ;
        RECT 55.000 1632.560 55.400 1632.960 ;
    END
  END Tile_X0Y0_S2MID[3]
  PIN Tile_X0Y0_S2MID[4]
    DIRECTION INPUT ;
    USE SIGNAL ;
    ANTENNAGATEAREA 0.426400 ;
    ANTENNADIFFAREA 4.030800 ;
    PORT
      LAYER Metal2 ;
        RECT 55.960 1632.560 56.360 1632.960 ;
    END
  END Tile_X0Y0_S2MID[4]
  PIN Tile_X0Y0_S2MID[5]
    DIRECTION INPUT ;
    USE SIGNAL ;
    ANTENNAGATEAREA 0.426400 ;
    ANTENNADIFFAREA 8.061600 ;
    PORT
      LAYER Metal2 ;
        RECT 56.920 1632.560 57.320 1632.960 ;
    END
  END Tile_X0Y0_S2MID[5]
  PIN Tile_X0Y0_S2MID[6]
    DIRECTION INPUT ;
    USE SIGNAL ;
    ANTENNAGATEAREA 0.426400 ;
    ANTENNADIFFAREA 4.030800 ;
    PORT
      LAYER Metal2 ;
        RECT 57.880 1632.560 58.280 1632.960 ;
    END
  END Tile_X0Y0_S2MID[6]
  PIN Tile_X0Y0_S2MID[7]
    DIRECTION INPUT ;
    USE SIGNAL ;
    ANTENNAGATEAREA 0.426400 ;
    PORT
      LAYER Metal2 ;
        RECT 58.840 1632.560 59.240 1632.960 ;
    END
  END Tile_X0Y0_S2MID[7]
  PIN Tile_X0Y0_S4END[0]
    DIRECTION INPUT ;
    USE SIGNAL ;
    ANTENNAGATEAREA 1.066000 ;
    PORT
      LAYER Metal2 ;
        RECT 73.240 1632.560 73.640 1632.960 ;
    END
  END Tile_X0Y0_S4END[0]
  PIN Tile_X0Y0_S4END[10]
    DIRECTION INPUT ;
    USE SIGNAL ;
    ANTENNAGATEAREA 1.066000 ;
    PORT
      LAYER Metal2 ;
        RECT 82.840 1632.560 83.240 1632.960 ;
    END
  END Tile_X0Y0_S4END[10]
  PIN Tile_X0Y0_S4END[11]
    DIRECTION INPUT ;
    USE SIGNAL ;
    ANTENNAGATEAREA 1.066000 ;
    PORT
      LAYER Metal2 ;
        RECT 83.800 1632.560 84.200 1632.960 ;
    END
  END Tile_X0Y0_S4END[11]
  PIN Tile_X0Y0_S4END[12]
    DIRECTION INPUT ;
    USE SIGNAL ;
    ANTENNAGATEAREA 1.066000 ;
    ANTENNADIFFAREA 50.384998 ;
    PORT
      LAYER Metal2 ;
        RECT 84.760 1632.560 85.160 1632.960 ;
    END
  END Tile_X0Y0_S4END[12]
  PIN Tile_X0Y0_S4END[13]
    DIRECTION INPUT ;
    USE SIGNAL ;
    ANTENNAGATEAREA 1.066000 ;
    ANTENNADIFFAREA 50.384998 ;
    PORT
      LAYER Metal2 ;
        RECT 85.720 1632.560 86.120 1632.960 ;
    END
  END Tile_X0Y0_S4END[13]
  PIN Tile_X0Y0_S4END[14]
    DIRECTION INPUT ;
    USE SIGNAL ;
    ANTENNAGATEAREA 1.066000 ;
    PORT
      LAYER Metal2 ;
        RECT 86.680 1632.560 87.080 1632.960 ;
    END
  END Tile_X0Y0_S4END[14]
  PIN Tile_X0Y0_S4END[15]
    DIRECTION INPUT ;
    USE SIGNAL ;
    ANTENNAGATEAREA 1.066000 ;
    ANTENNADIFFAREA 10.077000 ;
    PORT
      LAYER Metal2 ;
        RECT 87.640 1632.560 88.040 1632.960 ;
    END
  END Tile_X0Y0_S4END[15]
  PIN Tile_X0Y0_S4END[1]
    DIRECTION INPUT ;
    USE SIGNAL ;
    ANTENNAGATEAREA 1.066000 ;
    PORT
      LAYER Metal2 ;
        RECT 74.200 1632.560 74.600 1632.960 ;
    END
  END Tile_X0Y0_S4END[1]
  PIN Tile_X0Y0_S4END[2]
    DIRECTION INPUT ;
    USE SIGNAL ;
    ANTENNAGATEAREA 1.066000 ;
    PORT
      LAYER Metal2 ;
        RECT 75.160 1632.560 75.560 1632.960 ;
    END
  END Tile_X0Y0_S4END[2]
  PIN Tile_X0Y0_S4END[3]
    DIRECTION INPUT ;
    USE SIGNAL ;
    ANTENNAGATEAREA 1.066000 ;
    PORT
      LAYER Metal2 ;
        RECT 76.120 1632.560 76.520 1632.960 ;
    END
  END Tile_X0Y0_S4END[3]
  PIN Tile_X0Y0_S4END[4]
    DIRECTION INPUT ;
    USE SIGNAL ;
    ANTENNAGATEAREA 1.066000 ;
    PORT
      LAYER Metal2 ;
        RECT 77.080 1632.560 77.480 1632.960 ;
    END
  END Tile_X0Y0_S4END[4]
  PIN Tile_X0Y0_S4END[5]
    DIRECTION INPUT ;
    USE SIGNAL ;
    ANTENNAGATEAREA 1.066000 ;
    PORT
      LAYER Metal2 ;
        RECT 78.040 1632.560 78.440 1632.960 ;
    END
  END Tile_X0Y0_S4END[5]
  PIN Tile_X0Y0_S4END[6]
    DIRECTION INPUT ;
    USE SIGNAL ;
    ANTENNAGATEAREA 1.066000 ;
    PORT
      LAYER Metal2 ;
        RECT 79.000 1632.560 79.400 1632.960 ;
    END
  END Tile_X0Y0_S4END[6]
  PIN Tile_X0Y0_S4END[7]
    DIRECTION INPUT ;
    USE SIGNAL ;
    ANTENNAGATEAREA 1.066000 ;
    PORT
      LAYER Metal2 ;
        RECT 79.960 1632.560 80.360 1632.960 ;
    END
  END Tile_X0Y0_S4END[7]
  PIN Tile_X0Y0_S4END[8]
    DIRECTION INPUT ;
    USE SIGNAL ;
    ANTENNAGATEAREA 1.066000 ;
    PORT
      LAYER Metal2 ;
        RECT 80.920 1632.560 81.320 1632.960 ;
    END
  END Tile_X0Y0_S4END[8]
  PIN Tile_X0Y0_S4END[9]
    DIRECTION INPUT ;
    USE SIGNAL ;
    ANTENNAGATEAREA 1.066000 ;
    PORT
      LAYER Metal2 ;
        RECT 81.880 1632.560 82.280 1632.960 ;
    END
  END Tile_X0Y0_S4END[9]
  PIN Tile_X0Y0_UserCLK
    DIRECTION INPUT ;
    USE SIGNAL ;
    ANTENNAGATEAREA 0.180700 ;
    PORT
      LAYER Metal3 ;
        RECT 0.000 1365.220 0.400 1365.620 ;
    END
  END Tile_X0Y0_UserCLK
  PIN Tile_X0Y0_UserCLKo
    DIRECTION OUTPUT ;
    USE SIGNAL ;
    ANTENNADIFFAREA 2.724000 ;
    PORT
      LAYER Metal3 ;
        RECT 115.280 1564.300 115.680 1564.700 ;
    END
  END Tile_X0Y0_UserCLKo
  PIN Tile_X0Y0_W1END[0]
    DIRECTION INPUT ;
    USE SIGNAL ;
    ANTENNAGATEAREA 1.066000 ;
    PORT
      LAYER Metal3 ;
        RECT 115.280 1463.500 115.680 1463.900 ;
    END
  END Tile_X0Y0_W1END[0]
  PIN Tile_X0Y0_W1END[1]
    DIRECTION INPUT ;
    USE SIGNAL ;
    ANTENNAGATEAREA 1.066000 ;
    PORT
      LAYER Metal3 ;
        RECT 115.280 1465.180 115.680 1465.580 ;
    END
  END Tile_X0Y0_W1END[1]
  PIN Tile_X0Y0_W1END[2]
    DIRECTION INPUT ;
    USE SIGNAL ;
    ANTENNAGATEAREA 1.066000 ;
    PORT
      LAYER Metal3 ;
        RECT 115.280 1466.860 115.680 1467.260 ;
    END
  END Tile_X0Y0_W1END[2]
  PIN Tile_X0Y0_W1END[3]
    DIRECTION INPUT ;
    USE SIGNAL ;
    ANTENNAGATEAREA 1.066000 ;
    PORT
      LAYER Metal3 ;
        RECT 115.280 1468.540 115.680 1468.940 ;
    END
  END Tile_X0Y0_W1END[3]
  PIN Tile_X0Y0_W2END[0]
    DIRECTION INPUT ;
    USE SIGNAL ;
    ANTENNAGATEAREA 0.639600 ;
    PORT
      LAYER Metal3 ;
        RECT 115.280 1489.540 115.680 1489.940 ;
    END
  END Tile_X0Y0_W2END[0]
  PIN Tile_X0Y0_W2END[1]
    DIRECTION INPUT ;
    USE SIGNAL ;
    ANTENNAGATEAREA 0.639600 ;
    PORT
      LAYER Metal3 ;
        RECT 115.280 1491.220 115.680 1491.620 ;
    END
  END Tile_X0Y0_W2END[1]
  PIN Tile_X0Y0_W2END[2]
    DIRECTION INPUT ;
    USE SIGNAL ;
    ANTENNAGATEAREA 0.639600 ;
    PORT
      LAYER Metal3 ;
        RECT 115.280 1492.900 115.680 1493.300 ;
    END
  END Tile_X0Y0_W2END[2]
  PIN Tile_X0Y0_W2END[3]
    DIRECTION INPUT ;
    USE SIGNAL ;
    ANTENNAGATEAREA 0.639600 ;
    PORT
      LAYER Metal3 ;
        RECT 115.280 1494.580 115.680 1494.980 ;
    END
  END Tile_X0Y0_W2END[3]
  PIN Tile_X0Y0_W2END[4]
    DIRECTION INPUT ;
    USE SIGNAL ;
    ANTENNAGATEAREA 0.639600 ;
    PORT
      LAYER Metal3 ;
        RECT 115.280 1496.260 115.680 1496.660 ;
    END
  END Tile_X0Y0_W2END[4]
  PIN Tile_X0Y0_W2END[5]
    DIRECTION INPUT ;
    USE SIGNAL ;
    ANTENNAGATEAREA 0.639600 ;
    PORT
      LAYER Metal3 ;
        RECT 115.280 1497.940 115.680 1498.340 ;
    END
  END Tile_X0Y0_W2END[5]
  PIN Tile_X0Y0_W2END[6]
    DIRECTION INPUT ;
    USE SIGNAL ;
    ANTENNAGATEAREA 0.639600 ;
    PORT
      LAYER Metal3 ;
        RECT 115.280 1499.620 115.680 1500.020 ;
    END
  END Tile_X0Y0_W2END[6]
  PIN Tile_X0Y0_W2END[7]
    DIRECTION INPUT ;
    USE SIGNAL ;
    ANTENNAGATEAREA 0.639600 ;
    PORT
      LAYER Metal3 ;
        RECT 115.280 1501.300 115.680 1501.700 ;
    END
  END Tile_X0Y0_W2END[7]
  PIN Tile_X0Y0_W2MID[0]
    DIRECTION INPUT ;
    USE SIGNAL ;
    ANTENNAGATEAREA 0.639600 ;
    PORT
      LAYER Metal3 ;
        RECT 115.280 1472.740 115.680 1473.140 ;
    END
  END Tile_X0Y0_W2MID[0]
  PIN Tile_X0Y0_W2MID[1]
    DIRECTION INPUT ;
    USE SIGNAL ;
    ANTENNAGATEAREA 0.639600 ;
    PORT
      LAYER Metal3 ;
        RECT 115.280 1474.420 115.680 1474.820 ;
    END
  END Tile_X0Y0_W2MID[1]
  PIN Tile_X0Y0_W2MID[2]
    DIRECTION INPUT ;
    USE SIGNAL ;
    ANTENNAGATEAREA 0.639600 ;
    PORT
      LAYER Metal3 ;
        RECT 115.280 1476.100 115.680 1476.500 ;
    END
  END Tile_X0Y0_W2MID[2]
  PIN Tile_X0Y0_W2MID[3]
    DIRECTION INPUT ;
    USE SIGNAL ;
    ANTENNAGATEAREA 0.639600 ;
    PORT
      LAYER Metal3 ;
        RECT 115.280 1477.780 115.680 1478.180 ;
    END
  END Tile_X0Y0_W2MID[3]
  PIN Tile_X0Y0_W2MID[4]
    DIRECTION INPUT ;
    USE SIGNAL ;
    ANTENNAGATEAREA 0.639600 ;
    PORT
      LAYER Metal3 ;
        RECT 115.280 1479.460 115.680 1479.860 ;
    END
  END Tile_X0Y0_W2MID[4]
  PIN Tile_X0Y0_W2MID[5]
    DIRECTION INPUT ;
    USE SIGNAL ;
    ANTENNAGATEAREA 0.639600 ;
    PORT
      LAYER Metal3 ;
        RECT 115.280 1481.140 115.680 1481.540 ;
    END
  END Tile_X0Y0_W2MID[5]
  PIN Tile_X0Y0_W2MID[6]
    DIRECTION INPUT ;
    USE SIGNAL ;
    ANTENNAGATEAREA 0.639600 ;
    PORT
      LAYER Metal3 ;
        RECT 115.280 1482.820 115.680 1483.220 ;
    END
  END Tile_X0Y0_W2MID[6]
  PIN Tile_X0Y0_W2MID[7]
    DIRECTION INPUT ;
    USE SIGNAL ;
    ANTENNAGATEAREA 0.639600 ;
    PORT
      LAYER Metal3 ;
        RECT 115.280 1484.500 115.680 1484.900 ;
    END
  END Tile_X0Y0_W2MID[7]
  PIN Tile_X0Y0_W6END[0]
    DIRECTION INPUT ;
    USE SIGNAL ;
    ANTENNAGATEAREA 0.639600 ;
    PORT
      LAYER Metal3 ;
        RECT 115.280 1540.780 115.680 1541.180 ;
    END
  END Tile_X0Y0_W6END[0]
  PIN Tile_X0Y0_W6END[10]
    DIRECTION INPUT ;
    USE SIGNAL ;
    ANTENNAGATEAREA 0.639600 ;
    PORT
      LAYER Metal3 ;
        RECT 115.280 1557.580 115.680 1557.980 ;
    END
  END Tile_X0Y0_W6END[10]
  PIN Tile_X0Y0_W6END[11]
    DIRECTION INPUT ;
    USE SIGNAL ;
    ANTENNAGATEAREA 0.639600 ;
    PORT
      LAYER Metal3 ;
        RECT 115.280 1559.260 115.680 1559.660 ;
    END
  END Tile_X0Y0_W6END[11]
  PIN Tile_X0Y0_W6END[1]
    DIRECTION INPUT ;
    USE SIGNAL ;
    ANTENNAGATEAREA 0.639600 ;
    PORT
      LAYER Metal3 ;
        RECT 115.280 1542.460 115.680 1542.860 ;
    END
  END Tile_X0Y0_W6END[1]
  PIN Tile_X0Y0_W6END[2]
    DIRECTION INPUT ;
    USE SIGNAL ;
    ANTENNAGATEAREA 0.639600 ;
    PORT
      LAYER Metal3 ;
        RECT 115.280 1544.140 115.680 1544.540 ;
    END
  END Tile_X0Y0_W6END[2]
  PIN Tile_X0Y0_W6END[3]
    DIRECTION INPUT ;
    USE SIGNAL ;
    ANTENNAGATEAREA 0.639600 ;
    PORT
      LAYER Metal3 ;
        RECT 115.280 1545.820 115.680 1546.220 ;
    END
  END Tile_X0Y0_W6END[3]
  PIN Tile_X0Y0_W6END[4]
    DIRECTION INPUT ;
    USE SIGNAL ;
    ANTENNAGATEAREA 0.852800 ;
    PORT
      LAYER Metal3 ;
        RECT 115.280 1547.500 115.680 1547.900 ;
    END
  END Tile_X0Y0_W6END[4]
  PIN Tile_X0Y0_W6END[5]
    DIRECTION INPUT ;
    USE SIGNAL ;
    ANTENNAGATEAREA 0.852800 ;
    PORT
      LAYER Metal3 ;
        RECT 115.280 1549.180 115.680 1549.580 ;
    END
  END Tile_X0Y0_W6END[5]
  PIN Tile_X0Y0_W6END[6]
    DIRECTION INPUT ;
    USE SIGNAL ;
    ANTENNAGATEAREA 0.852800 ;
    PORT
      LAYER Metal3 ;
        RECT 115.280 1550.860 115.680 1551.260 ;
    END
  END Tile_X0Y0_W6END[6]
  PIN Tile_X0Y0_W6END[7]
    DIRECTION INPUT ;
    USE SIGNAL ;
    ANTENNAGATEAREA 0.852800 ;
    PORT
      LAYER Metal3 ;
        RECT 115.280 1552.540 115.680 1552.940 ;
    END
  END Tile_X0Y0_W6END[7]
  PIN Tile_X0Y0_W6END[8]
    DIRECTION INPUT ;
    USE SIGNAL ;
    ANTENNAGATEAREA 0.639600 ;
    PORT
      LAYER Metal3 ;
        RECT 115.280 1554.220 115.680 1554.620 ;
    END
  END Tile_X0Y0_W6END[8]
  PIN Tile_X0Y0_W6END[9]
    DIRECTION INPUT ;
    USE SIGNAL ;
    ANTENNAGATEAREA 0.639600 ;
    PORT
      LAYER Metal3 ;
        RECT 115.280 1555.900 115.680 1556.300 ;
    END
  END Tile_X0Y0_W6END[9]
  PIN Tile_X0Y0_WW4END[0]
    DIRECTION INPUT ;
    USE SIGNAL ;
    ANTENNAGATEAREA 0.213200 ;
    PORT
      LAYER Metal3 ;
        RECT 115.280 1508.020 115.680 1508.420 ;
    END
  END Tile_X0Y0_WW4END[0]
  PIN Tile_X0Y0_WW4END[10]
    DIRECTION INPUT ;
    USE SIGNAL ;
    ANTENNAGATEAREA 0.213200 ;
    PORT
      LAYER Metal3 ;
        RECT 115.280 1524.820 115.680 1525.220 ;
    END
  END Tile_X0Y0_WW4END[10]
  PIN Tile_X0Y0_WW4END[11]
    DIRECTION INPUT ;
    USE SIGNAL ;
    ANTENNAGATEAREA 0.213200 ;
    PORT
      LAYER Metal3 ;
        RECT 115.280 1526.500 115.680 1526.900 ;
    END
  END Tile_X0Y0_WW4END[11]
  PIN Tile_X0Y0_WW4END[12]
    DIRECTION INPUT ;
    USE SIGNAL ;
    ANTENNAGATEAREA 0.213200 ;
    PORT
      LAYER Metal3 ;
        RECT 115.280 1528.180 115.680 1528.580 ;
    END
  END Tile_X0Y0_WW4END[12]
  PIN Tile_X0Y0_WW4END[13]
    DIRECTION INPUT ;
    USE SIGNAL ;
    ANTENNAGATEAREA 0.213200 ;
    PORT
      LAYER Metal3 ;
        RECT 115.280 1529.860 115.680 1530.260 ;
    END
  END Tile_X0Y0_WW4END[13]
  PIN Tile_X0Y0_WW4END[14]
    DIRECTION INPUT ;
    USE SIGNAL ;
    ANTENNAGATEAREA 0.213200 ;
    PORT
      LAYER Metal3 ;
        RECT 115.280 1531.540 115.680 1531.940 ;
    END
  END Tile_X0Y0_WW4END[14]
  PIN Tile_X0Y0_WW4END[15]
    DIRECTION INPUT ;
    USE SIGNAL ;
    ANTENNAGATEAREA 0.213200 ;
    PORT
      LAYER Metal3 ;
        RECT 115.280 1533.220 115.680 1533.620 ;
    END
  END Tile_X0Y0_WW4END[15]
  PIN Tile_X0Y0_WW4END[1]
    DIRECTION INPUT ;
    USE SIGNAL ;
    ANTENNAGATEAREA 0.213200 ;
    PORT
      LAYER Metal3 ;
        RECT 115.280 1509.700 115.680 1510.100 ;
    END
  END Tile_X0Y0_WW4END[1]
  PIN Tile_X0Y0_WW4END[2]
    DIRECTION INPUT ;
    USE SIGNAL ;
    ANTENNAGATEAREA 0.213200 ;
    PORT
      LAYER Metal3 ;
        RECT 115.280 1511.380 115.680 1511.780 ;
    END
  END Tile_X0Y0_WW4END[2]
  PIN Tile_X0Y0_WW4END[3]
    DIRECTION INPUT ;
    USE SIGNAL ;
    ANTENNAGATEAREA 0.213200 ;
    PORT
      LAYER Metal3 ;
        RECT 115.280 1513.060 115.680 1513.460 ;
    END
  END Tile_X0Y0_WW4END[3]
  PIN Tile_X0Y0_WW4END[4]
    DIRECTION INPUT ;
    USE SIGNAL ;
    ANTENNAGATEAREA 0.213200 ;
    PORT
      LAYER Metal3 ;
        RECT 115.280 1514.740 115.680 1515.140 ;
    END
  END Tile_X0Y0_WW4END[4]
  PIN Tile_X0Y0_WW4END[5]
    DIRECTION INPUT ;
    USE SIGNAL ;
    ANTENNAGATEAREA 0.213200 ;
    PORT
      LAYER Metal3 ;
        RECT 115.280 1516.420 115.680 1516.820 ;
    END
  END Tile_X0Y0_WW4END[5]
  PIN Tile_X0Y0_WW4END[6]
    DIRECTION INPUT ;
    USE SIGNAL ;
    ANTENNAGATEAREA 0.213200 ;
    PORT
      LAYER Metal3 ;
        RECT 115.280 1518.100 115.680 1518.500 ;
    END
  END Tile_X0Y0_WW4END[6]
  PIN Tile_X0Y0_WW4END[7]
    DIRECTION INPUT ;
    USE SIGNAL ;
    ANTENNAGATEAREA 0.213200 ;
    PORT
      LAYER Metal3 ;
        RECT 115.280 1519.780 115.680 1520.180 ;
    END
  END Tile_X0Y0_WW4END[7]
  PIN Tile_X0Y0_WW4END[8]
    DIRECTION INPUT ;
    USE SIGNAL ;
    ANTENNAGATEAREA 0.213200 ;
    PORT
      LAYER Metal3 ;
        RECT 115.280 1521.460 115.680 1521.860 ;
    END
  END Tile_X0Y0_WW4END[8]
  PIN Tile_X0Y0_WW4END[9]
    DIRECTION INPUT ;
    USE SIGNAL ;
    ANTENNAGATEAREA 0.213200 ;
    PORT
      LAYER Metal3 ;
        RECT 115.280 1523.140 115.680 1523.540 ;
    END
  END Tile_X0Y0_WW4END[9]
  PIN Tile_X0Y1_E1BEG[0]
    DIRECTION OUTPUT ;
    USE SIGNAL ;
    ANTENNADIFFAREA 2.724000 ;
    PORT
      LAYER Metal3 ;
        RECT 115.280 1090.540 115.680 1090.940 ;
    END
  END Tile_X0Y1_E1BEG[0]
  PIN Tile_X0Y1_E1BEG[1]
    DIRECTION OUTPUT ;
    USE SIGNAL ;
    ANTENNADIFFAREA 2.724000 ;
    PORT
      LAYER Metal3 ;
        RECT 115.280 1092.220 115.680 1092.620 ;
    END
  END Tile_X0Y1_E1BEG[1]
  PIN Tile_X0Y1_E1BEG[2]
    DIRECTION OUTPUT ;
    USE SIGNAL ;
    ANTENNADIFFAREA 2.724000 ;
    PORT
      LAYER Metal3 ;
        RECT 115.280 1093.900 115.680 1094.300 ;
    END
  END Tile_X0Y1_E1BEG[2]
  PIN Tile_X0Y1_E1BEG[3]
    DIRECTION OUTPUT ;
    USE SIGNAL ;
    ANTENNADIFFAREA 2.724000 ;
    PORT
      LAYER Metal3 ;
        RECT 115.280 1095.580 115.680 1095.980 ;
    END
  END Tile_X0Y1_E1BEG[3]
  PIN Tile_X0Y1_E2BEG[0]
    DIRECTION OUTPUT ;
    USE SIGNAL ;
    ANTENNADIFFAREA 2.724000 ;
    PORT
      LAYER Metal3 ;
        RECT 115.280 1099.780 115.680 1100.180 ;
    END
  END Tile_X0Y1_E2BEG[0]
  PIN Tile_X0Y1_E2BEG[1]
    DIRECTION OUTPUT ;
    USE SIGNAL ;
    ANTENNADIFFAREA 2.724000 ;
    PORT
      LAYER Metal3 ;
        RECT 115.280 1101.460 115.680 1101.860 ;
    END
  END Tile_X0Y1_E2BEG[1]
  PIN Tile_X0Y1_E2BEG[2]
    DIRECTION OUTPUT ;
    USE SIGNAL ;
    ANTENNADIFFAREA 2.724000 ;
    PORT
      LAYER Metal3 ;
        RECT 115.280 1103.140 115.680 1103.540 ;
    END
  END Tile_X0Y1_E2BEG[2]
  PIN Tile_X0Y1_E2BEG[3]
    DIRECTION OUTPUT ;
    USE SIGNAL ;
    ANTENNADIFFAREA 2.724000 ;
    PORT
      LAYER Metal3 ;
        RECT 115.280 1104.820 115.680 1105.220 ;
    END
  END Tile_X0Y1_E2BEG[3]
  PIN Tile_X0Y1_E2BEG[4]
    DIRECTION OUTPUT ;
    USE SIGNAL ;
    ANTENNADIFFAREA 2.724000 ;
    PORT
      LAYER Metal3 ;
        RECT 115.280 1106.500 115.680 1106.900 ;
    END
  END Tile_X0Y1_E2BEG[4]
  PIN Tile_X0Y1_E2BEG[5]
    DIRECTION OUTPUT ;
    USE SIGNAL ;
    ANTENNADIFFAREA 2.724000 ;
    PORT
      LAYER Metal3 ;
        RECT 115.280 1108.180 115.680 1108.580 ;
    END
  END Tile_X0Y1_E2BEG[5]
  PIN Tile_X0Y1_E2BEG[6]
    DIRECTION OUTPUT ;
    USE SIGNAL ;
    ANTENNADIFFAREA 2.724000 ;
    PORT
      LAYER Metal3 ;
        RECT 115.280 1109.860 115.680 1110.260 ;
    END
  END Tile_X0Y1_E2BEG[6]
  PIN Tile_X0Y1_E2BEG[7]
    DIRECTION OUTPUT ;
    USE SIGNAL ;
    ANTENNADIFFAREA 2.724000 ;
    PORT
      LAYER Metal3 ;
        RECT 115.280 1111.540 115.680 1111.940 ;
    END
  END Tile_X0Y1_E2BEG[7]
  PIN Tile_X0Y1_E2BEGb[0]
    DIRECTION OUTPUT ;
    USE SIGNAL ;
    ANTENNADIFFAREA 2.724000 ;
    PORT
      LAYER Metal3 ;
        RECT 115.280 1116.580 115.680 1116.980 ;
    END
  END Tile_X0Y1_E2BEGb[0]
  PIN Tile_X0Y1_E2BEGb[1]
    DIRECTION OUTPUT ;
    USE SIGNAL ;
    ANTENNADIFFAREA 2.724000 ;
    PORT
      LAYER Metal3 ;
        RECT 115.280 1118.260 115.680 1118.660 ;
    END
  END Tile_X0Y1_E2BEGb[1]
  PIN Tile_X0Y1_E2BEGb[2]
    DIRECTION OUTPUT ;
    USE SIGNAL ;
    ANTENNADIFFAREA 2.724000 ;
    PORT
      LAYER Metal3 ;
        RECT 115.280 1119.940 115.680 1120.340 ;
    END
  END Tile_X0Y1_E2BEGb[2]
  PIN Tile_X0Y1_E2BEGb[3]
    DIRECTION OUTPUT ;
    USE SIGNAL ;
    ANTENNADIFFAREA 2.724000 ;
    PORT
      LAYER Metal3 ;
        RECT 115.280 1121.620 115.680 1122.020 ;
    END
  END Tile_X0Y1_E2BEGb[3]
  PIN Tile_X0Y1_E2BEGb[4]
    DIRECTION OUTPUT ;
    USE SIGNAL ;
    ANTENNADIFFAREA 2.724000 ;
    PORT
      LAYER Metal3 ;
        RECT 115.280 1123.300 115.680 1123.700 ;
    END
  END Tile_X0Y1_E2BEGb[4]
  PIN Tile_X0Y1_E2BEGb[5]
    DIRECTION OUTPUT ;
    USE SIGNAL ;
    ANTENNADIFFAREA 2.724000 ;
    PORT
      LAYER Metal3 ;
        RECT 115.280 1124.980 115.680 1125.380 ;
    END
  END Tile_X0Y1_E2BEGb[5]
  PIN Tile_X0Y1_E2BEGb[6]
    DIRECTION OUTPUT ;
    USE SIGNAL ;
    ANTENNADIFFAREA 2.724000 ;
    PORT
      LAYER Metal3 ;
        RECT 115.280 1126.660 115.680 1127.060 ;
    END
  END Tile_X0Y1_E2BEGb[6]
  PIN Tile_X0Y1_E2BEGb[7]
    DIRECTION OUTPUT ;
    USE SIGNAL ;
    ANTENNADIFFAREA 2.724000 ;
    PORT
      LAYER Metal3 ;
        RECT 115.280 1128.340 115.680 1128.740 ;
    END
  END Tile_X0Y1_E2BEGb[7]
  PIN Tile_X0Y1_E6BEG[0]
    DIRECTION OUTPUT ;
    USE SIGNAL ;
    ANTENNADIFFAREA 2.724000 ;
    PORT
      LAYER Metal3 ;
        RECT 115.280 1167.820 115.680 1168.220 ;
    END
  END Tile_X0Y1_E6BEG[0]
  PIN Tile_X0Y1_E6BEG[10]
    DIRECTION OUTPUT ;
    USE SIGNAL ;
    ANTENNADIFFAREA 2.724000 ;
    PORT
      LAYER Metal3 ;
        RECT 115.280 1184.620 115.680 1185.020 ;
    END
  END Tile_X0Y1_E6BEG[10]
  PIN Tile_X0Y1_E6BEG[11]
    DIRECTION OUTPUT ;
    USE SIGNAL ;
    ANTENNADIFFAREA 2.724000 ;
    PORT
      LAYER Metal3 ;
        RECT 115.280 1186.300 115.680 1186.700 ;
    END
  END Tile_X0Y1_E6BEG[11]
  PIN Tile_X0Y1_E6BEG[1]
    DIRECTION OUTPUT ;
    USE SIGNAL ;
    ANTENNADIFFAREA 2.724000 ;
    PORT
      LAYER Metal3 ;
        RECT 115.280 1169.500 115.680 1169.900 ;
    END
  END Tile_X0Y1_E6BEG[1]
  PIN Tile_X0Y1_E6BEG[2]
    DIRECTION OUTPUT ;
    USE SIGNAL ;
    ANTENNADIFFAREA 2.724000 ;
    PORT
      LAYER Metal3 ;
        RECT 115.280 1171.180 115.680 1171.580 ;
    END
  END Tile_X0Y1_E6BEG[2]
  PIN Tile_X0Y1_E6BEG[3]
    DIRECTION OUTPUT ;
    USE SIGNAL ;
    ANTENNADIFFAREA 2.724000 ;
    PORT
      LAYER Metal3 ;
        RECT 115.280 1172.860 115.680 1173.260 ;
    END
  END Tile_X0Y1_E6BEG[3]
  PIN Tile_X0Y1_E6BEG[4]
    DIRECTION OUTPUT ;
    USE SIGNAL ;
    ANTENNADIFFAREA 2.724000 ;
    PORT
      LAYER Metal3 ;
        RECT 115.280 1174.540 115.680 1174.940 ;
    END
  END Tile_X0Y1_E6BEG[4]
  PIN Tile_X0Y1_E6BEG[5]
    DIRECTION OUTPUT ;
    USE SIGNAL ;
    ANTENNADIFFAREA 2.724000 ;
    PORT
      LAYER Metal3 ;
        RECT 115.280 1176.220 115.680 1176.620 ;
    END
  END Tile_X0Y1_E6BEG[5]
  PIN Tile_X0Y1_E6BEG[6]
    DIRECTION OUTPUT ;
    USE SIGNAL ;
    ANTENNADIFFAREA 2.724000 ;
    PORT
      LAYER Metal3 ;
        RECT 115.280 1177.900 115.680 1178.300 ;
    END
  END Tile_X0Y1_E6BEG[6]
  PIN Tile_X0Y1_E6BEG[7]
    DIRECTION OUTPUT ;
    USE SIGNAL ;
    ANTENNADIFFAREA 2.724000 ;
    PORT
      LAYER Metal3 ;
        RECT 115.280 1179.580 115.680 1179.980 ;
    END
  END Tile_X0Y1_E6BEG[7]
  PIN Tile_X0Y1_E6BEG[8]
    DIRECTION OUTPUT ;
    USE SIGNAL ;
    ANTENNADIFFAREA 2.724000 ;
    PORT
      LAYER Metal3 ;
        RECT 115.280 1181.260 115.680 1181.660 ;
    END
  END Tile_X0Y1_E6BEG[8]
  PIN Tile_X0Y1_E6BEG[9]
    DIRECTION OUTPUT ;
    USE SIGNAL ;
    ANTENNADIFFAREA 2.724000 ;
    PORT
      LAYER Metal3 ;
        RECT 115.280 1182.940 115.680 1183.340 ;
    END
  END Tile_X0Y1_E6BEG[9]
  PIN Tile_X0Y1_EE4BEG[0]
    DIRECTION OUTPUT ;
    USE SIGNAL ;
    ANTENNADIFFAREA 2.724000 ;
    PORT
      LAYER Metal3 ;
        RECT 115.280 1135.060 115.680 1135.460 ;
    END
  END Tile_X0Y1_EE4BEG[0]
  PIN Tile_X0Y1_EE4BEG[10]
    DIRECTION OUTPUT ;
    USE SIGNAL ;
    ANTENNADIFFAREA 2.724000 ;
    PORT
      LAYER Metal3 ;
        RECT 115.280 1151.860 115.680 1152.260 ;
    END
  END Tile_X0Y1_EE4BEG[10]
  PIN Tile_X0Y1_EE4BEG[11]
    DIRECTION OUTPUT ;
    USE SIGNAL ;
    ANTENNADIFFAREA 2.724000 ;
    PORT
      LAYER Metal3 ;
        RECT 115.280 1153.540 115.680 1153.940 ;
    END
  END Tile_X0Y1_EE4BEG[11]
  PIN Tile_X0Y1_EE4BEG[12]
    DIRECTION OUTPUT ;
    USE SIGNAL ;
    ANTENNADIFFAREA 2.724000 ;
    PORT
      LAYER Metal3 ;
        RECT 115.280 1155.220 115.680 1155.620 ;
    END
  END Tile_X0Y1_EE4BEG[12]
  PIN Tile_X0Y1_EE4BEG[13]
    DIRECTION OUTPUT ;
    USE SIGNAL ;
    ANTENNADIFFAREA 2.724000 ;
    PORT
      LAYER Metal3 ;
        RECT 115.280 1156.900 115.680 1157.300 ;
    END
  END Tile_X0Y1_EE4BEG[13]
  PIN Tile_X0Y1_EE4BEG[14]
    DIRECTION OUTPUT ;
    USE SIGNAL ;
    ANTENNADIFFAREA 2.724000 ;
    PORT
      LAYER Metal3 ;
        RECT 115.280 1158.580 115.680 1158.980 ;
    END
  END Tile_X0Y1_EE4BEG[14]
  PIN Tile_X0Y1_EE4BEG[15]
    DIRECTION OUTPUT ;
    USE SIGNAL ;
    ANTENNADIFFAREA 2.724000 ;
    PORT
      LAYER Metal3 ;
        RECT 115.280 1160.260 115.680 1160.660 ;
    END
  END Tile_X0Y1_EE4BEG[15]
  PIN Tile_X0Y1_EE4BEG[1]
    DIRECTION OUTPUT ;
    USE SIGNAL ;
    ANTENNADIFFAREA 2.724000 ;
    PORT
      LAYER Metal3 ;
        RECT 115.280 1136.740 115.680 1137.140 ;
    END
  END Tile_X0Y1_EE4BEG[1]
  PIN Tile_X0Y1_EE4BEG[2]
    DIRECTION OUTPUT ;
    USE SIGNAL ;
    ANTENNADIFFAREA 2.724000 ;
    PORT
      LAYER Metal3 ;
        RECT 115.280 1138.420 115.680 1138.820 ;
    END
  END Tile_X0Y1_EE4BEG[2]
  PIN Tile_X0Y1_EE4BEG[3]
    DIRECTION OUTPUT ;
    USE SIGNAL ;
    ANTENNADIFFAREA 2.724000 ;
    PORT
      LAYER Metal3 ;
        RECT 115.280 1140.100 115.680 1140.500 ;
    END
  END Tile_X0Y1_EE4BEG[3]
  PIN Tile_X0Y1_EE4BEG[4]
    DIRECTION OUTPUT ;
    USE SIGNAL ;
    ANTENNADIFFAREA 2.724000 ;
    PORT
      LAYER Metal3 ;
        RECT 115.280 1141.780 115.680 1142.180 ;
    END
  END Tile_X0Y1_EE4BEG[4]
  PIN Tile_X0Y1_EE4BEG[5]
    DIRECTION OUTPUT ;
    USE SIGNAL ;
    ANTENNADIFFAREA 2.724000 ;
    PORT
      LAYER Metal3 ;
        RECT 115.280 1143.460 115.680 1143.860 ;
    END
  END Tile_X0Y1_EE4BEG[5]
  PIN Tile_X0Y1_EE4BEG[6]
    DIRECTION OUTPUT ;
    USE SIGNAL ;
    ANTENNADIFFAREA 2.724000 ;
    PORT
      LAYER Metal3 ;
        RECT 115.280 1145.140 115.680 1145.540 ;
    END
  END Tile_X0Y1_EE4BEG[6]
  PIN Tile_X0Y1_EE4BEG[7]
    DIRECTION OUTPUT ;
    USE SIGNAL ;
    ANTENNADIFFAREA 2.724000 ;
    PORT
      LAYER Metal3 ;
        RECT 115.280 1146.820 115.680 1147.220 ;
    END
  END Tile_X0Y1_EE4BEG[7]
  PIN Tile_X0Y1_EE4BEG[8]
    DIRECTION OUTPUT ;
    USE SIGNAL ;
    ANTENNADIFFAREA 2.724000 ;
    PORT
      LAYER Metal3 ;
        RECT 115.280 1148.500 115.680 1148.900 ;
    END
  END Tile_X0Y1_EE4BEG[8]
  PIN Tile_X0Y1_EE4BEG[9]
    DIRECTION OUTPUT ;
    USE SIGNAL ;
    ANTENNADIFFAREA 2.724000 ;
    PORT
      LAYER Metal3 ;
        RECT 115.280 1150.180 115.680 1150.580 ;
    END
  END Tile_X0Y1_EE4BEG[9]
  PIN Tile_X0Y1_FrameData[0]
    DIRECTION INPUT ;
    USE SIGNAL ;
    ANTENNAGATEAREA 1.445600 ;
    PORT
      LAYER Metal3 ;
        RECT 0.000 1111.540 0.400 1111.940 ;
    END
  END Tile_X0Y1_FrameData[0]
  PIN Tile_X0Y1_FrameData[10]
    DIRECTION INPUT ;
    USE SIGNAL ;
    ANTENNAGATEAREA 1.445600 ;
    PORT
      LAYER Metal3 ;
        RECT 0.000 1187.140 0.400 1187.540 ;
    END
  END Tile_X0Y1_FrameData[10]
  PIN Tile_X0Y1_FrameData[11]
    DIRECTION INPUT ;
    USE SIGNAL ;
    ANTENNAGATEAREA 1.445600 ;
    PORT
      LAYER Metal3 ;
        RECT 0.000 1194.700 0.400 1195.100 ;
    END
  END Tile_X0Y1_FrameData[11]
  PIN Tile_X0Y1_FrameData[12]
    DIRECTION INPUT ;
    USE SIGNAL ;
    ANTENNAGATEAREA 1.445600 ;
    PORT
      LAYER Metal3 ;
        RECT 0.000 1202.260 0.400 1202.660 ;
    END
  END Tile_X0Y1_FrameData[12]
  PIN Tile_X0Y1_FrameData[13]
    DIRECTION INPUT ;
    USE SIGNAL ;
    ANTENNAGATEAREA 1.445600 ;
    PORT
      LAYER Metal3 ;
        RECT 0.000 1209.820 0.400 1210.220 ;
    END
  END Tile_X0Y1_FrameData[13]
  PIN Tile_X0Y1_FrameData[14]
    DIRECTION INPUT ;
    USE SIGNAL ;
    ANTENNAGATEAREA 1.445600 ;
    PORT
      LAYER Metal3 ;
        RECT 0.000 1217.380 0.400 1217.780 ;
    END
  END Tile_X0Y1_FrameData[14]
  PIN Tile_X0Y1_FrameData[15]
    DIRECTION INPUT ;
    USE SIGNAL ;
    ANTENNAGATEAREA 1.445600 ;
    PORT
      LAYER Metal3 ;
        RECT 0.000 1224.940 0.400 1225.340 ;
    END
  END Tile_X0Y1_FrameData[15]
  PIN Tile_X0Y1_FrameData[16]
    DIRECTION INPUT ;
    USE SIGNAL ;
    ANTENNAGATEAREA 1.626300 ;
    PORT
      LAYER Metal3 ;
        RECT 0.000 1232.500 0.400 1232.900 ;
    END
  END Tile_X0Y1_FrameData[16]
  PIN Tile_X0Y1_FrameData[17]
    DIRECTION INPUT ;
    USE SIGNAL ;
    ANTENNAGATEAREA 1.626300 ;
    PORT
      LAYER Metal3 ;
        RECT 0.000 1240.060 0.400 1240.460 ;
    END
  END Tile_X0Y1_FrameData[17]
  PIN Tile_X0Y1_FrameData[18]
    DIRECTION INPUT ;
    USE SIGNAL ;
    ANTENNAGATEAREA 1.626300 ;
    PORT
      LAYER Metal3 ;
        RECT 0.000 1247.620 0.400 1248.020 ;
    END
  END Tile_X0Y1_FrameData[18]
  PIN Tile_X0Y1_FrameData[19]
    DIRECTION INPUT ;
    USE SIGNAL ;
    ANTENNAGATEAREA 1.626300 ;
    PORT
      LAYER Metal3 ;
        RECT 0.000 1255.180 0.400 1255.580 ;
    END
  END Tile_X0Y1_FrameData[19]
  PIN Tile_X0Y1_FrameData[1]
    DIRECTION INPUT ;
    USE SIGNAL ;
    ANTENNAGATEAREA 1.445600 ;
    PORT
      LAYER Metal3 ;
        RECT 0.000 1119.100 0.400 1119.500 ;
    END
  END Tile_X0Y1_FrameData[1]
  PIN Tile_X0Y1_FrameData[20]
    DIRECTION INPUT ;
    USE SIGNAL ;
    ANTENNAGATEAREA 1.626300 ;
    PORT
      LAYER Metal3 ;
        RECT 0.000 1262.740 0.400 1263.140 ;
    END
  END Tile_X0Y1_FrameData[20]
  PIN Tile_X0Y1_FrameData[21]
    DIRECTION INPUT ;
    USE SIGNAL ;
    ANTENNAGATEAREA 1.626300 ;
    PORT
      LAYER Metal3 ;
        RECT 0.000 1270.300 0.400 1270.700 ;
    END
  END Tile_X0Y1_FrameData[21]
  PIN Tile_X0Y1_FrameData[22]
    DIRECTION INPUT ;
    USE SIGNAL ;
    ANTENNAGATEAREA 1.626300 ;
    PORT
      LAYER Metal3 ;
        RECT 0.000 1277.860 0.400 1278.260 ;
    END
  END Tile_X0Y1_FrameData[22]
  PIN Tile_X0Y1_FrameData[23]
    DIRECTION INPUT ;
    USE SIGNAL ;
    ANTENNAGATEAREA 1.626300 ;
    PORT
      LAYER Metal3 ;
        RECT 0.000 1285.420 0.400 1285.820 ;
    END
  END Tile_X0Y1_FrameData[23]
  PIN Tile_X0Y1_FrameData[24]
    DIRECTION INPUT ;
    USE SIGNAL ;
    ANTENNAGATEAREA 1.626300 ;
    PORT
      LAYER Metal3 ;
        RECT 0.000 1292.980 0.400 1293.380 ;
    END
  END Tile_X0Y1_FrameData[24]
  PIN Tile_X0Y1_FrameData[25]
    DIRECTION INPUT ;
    USE SIGNAL ;
    ANTENNAGATEAREA 1.626300 ;
    PORT
      LAYER Metal3 ;
        RECT 0.000 1300.540 0.400 1300.940 ;
    END
  END Tile_X0Y1_FrameData[25]
  PIN Tile_X0Y1_FrameData[26]
    DIRECTION INPUT ;
    USE SIGNAL ;
    ANTENNAGATEAREA 1.626300 ;
    PORT
      LAYER Metal3 ;
        RECT 0.000 1308.100 0.400 1308.500 ;
    END
  END Tile_X0Y1_FrameData[26]
  PIN Tile_X0Y1_FrameData[27]
    DIRECTION INPUT ;
    USE SIGNAL ;
    ANTENNAGATEAREA 1.626300 ;
    PORT
      LAYER Metal3 ;
        RECT 0.000 1315.660 0.400 1316.060 ;
    END
  END Tile_X0Y1_FrameData[27]
  PIN Tile_X0Y1_FrameData[28]
    DIRECTION INPUT ;
    USE SIGNAL ;
    ANTENNAGATEAREA 1.626300 ;
    PORT
      LAYER Metal3 ;
        RECT 0.000 1323.220 0.400 1323.620 ;
    END
  END Tile_X0Y1_FrameData[28]
  PIN Tile_X0Y1_FrameData[29]
    DIRECTION INPUT ;
    USE SIGNAL ;
    ANTENNAGATEAREA 1.626300 ;
    PORT
      LAYER Metal3 ;
        RECT 0.000 1330.780 0.400 1331.180 ;
    END
  END Tile_X0Y1_FrameData[29]
  PIN Tile_X0Y1_FrameData[2]
    DIRECTION INPUT ;
    USE SIGNAL ;
    ANTENNAGATEAREA 1.445600 ;
    PORT
      LAYER Metal3 ;
        RECT 0.000 1126.660 0.400 1127.060 ;
    END
  END Tile_X0Y1_FrameData[2]
  PIN Tile_X0Y1_FrameData[30]
    DIRECTION INPUT ;
    USE SIGNAL ;
    ANTENNAGATEAREA 1.626300 ;
    PORT
      LAYER Metal3 ;
        RECT 0.000 1338.340 0.400 1338.740 ;
    END
  END Tile_X0Y1_FrameData[30]
  PIN Tile_X0Y1_FrameData[31]
    DIRECTION INPUT ;
    USE SIGNAL ;
    ANTENNAGATEAREA 1.626300 ;
    PORT
      LAYER Metal3 ;
        RECT 0.000 1345.900 0.400 1346.300 ;
    END
  END Tile_X0Y1_FrameData[31]
  PIN Tile_X0Y1_FrameData[3]
    DIRECTION INPUT ;
    USE SIGNAL ;
    ANTENNAGATEAREA 1.445600 ;
    PORT
      LAYER Metal3 ;
        RECT 0.000 1134.220 0.400 1134.620 ;
    END
  END Tile_X0Y1_FrameData[3]
  PIN Tile_X0Y1_FrameData[4]
    DIRECTION INPUT ;
    USE SIGNAL ;
    ANTENNAGATEAREA 1.445600 ;
    PORT
      LAYER Metal3 ;
        RECT 0.000 1141.780 0.400 1142.180 ;
    END
  END Tile_X0Y1_FrameData[4]
  PIN Tile_X0Y1_FrameData[5]
    DIRECTION INPUT ;
    USE SIGNAL ;
    ANTENNAGATEAREA 1.445600 ;
    PORT
      LAYER Metal3 ;
        RECT 0.000 1149.340 0.400 1149.740 ;
    END
  END Tile_X0Y1_FrameData[5]
  PIN Tile_X0Y1_FrameData[6]
    DIRECTION INPUT ;
    USE SIGNAL ;
    ANTENNAGATEAREA 1.445600 ;
    PORT
      LAYER Metal3 ;
        RECT 0.000 1156.900 0.400 1157.300 ;
    END
  END Tile_X0Y1_FrameData[6]
  PIN Tile_X0Y1_FrameData[7]
    DIRECTION INPUT ;
    USE SIGNAL ;
    ANTENNAGATEAREA 1.445600 ;
    PORT
      LAYER Metal3 ;
        RECT 0.000 1164.460 0.400 1164.860 ;
    END
  END Tile_X0Y1_FrameData[7]
  PIN Tile_X0Y1_FrameData[8]
    DIRECTION INPUT ;
    USE SIGNAL ;
    ANTENNAGATEAREA 1.445600 ;
    PORT
      LAYER Metal3 ;
        RECT 0.000 1172.020 0.400 1172.420 ;
    END
  END Tile_X0Y1_FrameData[8]
  PIN Tile_X0Y1_FrameData[9]
    DIRECTION INPUT ;
    USE SIGNAL ;
    ANTENNAGATEAREA 1.445600 ;
    PORT
      LAYER Metal3 ;
        RECT 0.000 1179.580 0.400 1179.980 ;
    END
  END Tile_X0Y1_FrameData[9]
  PIN Tile_X0Y1_FrameData_O[0]
    DIRECTION OUTPUT ;
    USE SIGNAL ;
    ANTENNADIFFAREA 2.724000 ;
    PORT
      LAYER Metal3 ;
        RECT 115.280 1300.540 115.680 1300.940 ;
    END
  END Tile_X0Y1_FrameData_O[0]
  PIN Tile_X0Y1_FrameData_O[10]
    DIRECTION OUTPUT ;
    USE SIGNAL ;
    ANTENNADIFFAREA 2.724000 ;
    PORT
      LAYER Metal3 ;
        RECT 115.280 1317.340 115.680 1317.740 ;
    END
  END Tile_X0Y1_FrameData_O[10]
  PIN Tile_X0Y1_FrameData_O[11]
    DIRECTION OUTPUT ;
    USE SIGNAL ;
    ANTENNADIFFAREA 2.724000 ;
    PORT
      LAYER Metal3 ;
        RECT 115.280 1319.020 115.680 1319.420 ;
    END
  END Tile_X0Y1_FrameData_O[11]
  PIN Tile_X0Y1_FrameData_O[12]
    DIRECTION OUTPUT ;
    USE SIGNAL ;
    ANTENNADIFFAREA 2.724000 ;
    PORT
      LAYER Metal3 ;
        RECT 115.280 1320.700 115.680 1321.100 ;
    END
  END Tile_X0Y1_FrameData_O[12]
  PIN Tile_X0Y1_FrameData_O[13]
    DIRECTION OUTPUT ;
    USE SIGNAL ;
    ANTENNADIFFAREA 2.724000 ;
    PORT
      LAYER Metal3 ;
        RECT 115.280 1322.380 115.680 1322.780 ;
    END
  END Tile_X0Y1_FrameData_O[13]
  PIN Tile_X0Y1_FrameData_O[14]
    DIRECTION OUTPUT ;
    USE SIGNAL ;
    ANTENNADIFFAREA 2.724000 ;
    PORT
      LAYER Metal3 ;
        RECT 115.280 1324.060 115.680 1324.460 ;
    END
  END Tile_X0Y1_FrameData_O[14]
  PIN Tile_X0Y1_FrameData_O[15]
    DIRECTION OUTPUT ;
    USE SIGNAL ;
    ANTENNADIFFAREA 2.724000 ;
    PORT
      LAYER Metal3 ;
        RECT 115.280 1325.740 115.680 1326.140 ;
    END
  END Tile_X0Y1_FrameData_O[15]
  PIN Tile_X0Y1_FrameData_O[16]
    DIRECTION OUTPUT ;
    USE SIGNAL ;
    ANTENNADIFFAREA 2.724000 ;
    PORT
      LAYER Metal3 ;
        RECT 115.280 1327.420 115.680 1327.820 ;
    END
  END Tile_X0Y1_FrameData_O[16]
  PIN Tile_X0Y1_FrameData_O[17]
    DIRECTION OUTPUT ;
    USE SIGNAL ;
    ANTENNADIFFAREA 2.724000 ;
    PORT
      LAYER Metal3 ;
        RECT 115.280 1329.100 115.680 1329.500 ;
    END
  END Tile_X0Y1_FrameData_O[17]
  PIN Tile_X0Y1_FrameData_O[18]
    DIRECTION OUTPUT ;
    USE SIGNAL ;
    ANTENNADIFFAREA 2.724000 ;
    PORT
      LAYER Metal3 ;
        RECT 115.280 1330.780 115.680 1331.180 ;
    END
  END Tile_X0Y1_FrameData_O[18]
  PIN Tile_X0Y1_FrameData_O[19]
    DIRECTION OUTPUT ;
    USE SIGNAL ;
    ANTENNADIFFAREA 2.724000 ;
    PORT
      LAYER Metal3 ;
        RECT 115.280 1332.460 115.680 1332.860 ;
    END
  END Tile_X0Y1_FrameData_O[19]
  PIN Tile_X0Y1_FrameData_O[1]
    DIRECTION OUTPUT ;
    USE SIGNAL ;
    ANTENNADIFFAREA 2.724000 ;
    PORT
      LAYER Metal3 ;
        RECT 115.280 1302.220 115.680 1302.620 ;
    END
  END Tile_X0Y1_FrameData_O[1]
  PIN Tile_X0Y1_FrameData_O[20]
    DIRECTION OUTPUT ;
    USE SIGNAL ;
    ANTENNADIFFAREA 2.724000 ;
    PORT
      LAYER Metal3 ;
        RECT 115.280 1334.140 115.680 1334.540 ;
    END
  END Tile_X0Y1_FrameData_O[20]
  PIN Tile_X0Y1_FrameData_O[21]
    DIRECTION OUTPUT ;
    USE SIGNAL ;
    ANTENNADIFFAREA 2.724000 ;
    PORT
      LAYER Metal3 ;
        RECT 115.280 1335.820 115.680 1336.220 ;
    END
  END Tile_X0Y1_FrameData_O[21]
  PIN Tile_X0Y1_FrameData_O[22]
    DIRECTION OUTPUT ;
    USE SIGNAL ;
    ANTENNADIFFAREA 2.724000 ;
    PORT
      LAYER Metal3 ;
        RECT 115.280 1337.500 115.680 1337.900 ;
    END
  END Tile_X0Y1_FrameData_O[22]
  PIN Tile_X0Y1_FrameData_O[23]
    DIRECTION OUTPUT ;
    USE SIGNAL ;
    ANTENNADIFFAREA 2.724000 ;
    PORT
      LAYER Metal3 ;
        RECT 115.280 1339.180 115.680 1339.580 ;
    END
  END Tile_X0Y1_FrameData_O[23]
  PIN Tile_X0Y1_FrameData_O[24]
    DIRECTION OUTPUT ;
    USE SIGNAL ;
    ANTENNADIFFAREA 2.724000 ;
    PORT
      LAYER Metal3 ;
        RECT 115.280 1340.860 115.680 1341.260 ;
    END
  END Tile_X0Y1_FrameData_O[24]
  PIN Tile_X0Y1_FrameData_O[25]
    DIRECTION OUTPUT ;
    USE SIGNAL ;
    ANTENNADIFFAREA 2.724000 ;
    PORT
      LAYER Metal3 ;
        RECT 115.280 1342.540 115.680 1342.940 ;
    END
  END Tile_X0Y1_FrameData_O[25]
  PIN Tile_X0Y1_FrameData_O[26]
    DIRECTION OUTPUT ;
    USE SIGNAL ;
    ANTENNADIFFAREA 2.724000 ;
    PORT
      LAYER Metal3 ;
        RECT 115.280 1344.220 115.680 1344.620 ;
    END
  END Tile_X0Y1_FrameData_O[26]
  PIN Tile_X0Y1_FrameData_O[27]
    DIRECTION OUTPUT ;
    USE SIGNAL ;
    ANTENNADIFFAREA 2.724000 ;
    PORT
      LAYER Metal3 ;
        RECT 115.280 1345.900 115.680 1346.300 ;
    END
  END Tile_X0Y1_FrameData_O[27]
  PIN Tile_X0Y1_FrameData_O[28]
    DIRECTION OUTPUT ;
    USE SIGNAL ;
    ANTENNADIFFAREA 2.724000 ;
    PORT
      LAYER Metal3 ;
        RECT 115.280 1347.580 115.680 1347.980 ;
    END
  END Tile_X0Y1_FrameData_O[28]
  PIN Tile_X0Y1_FrameData_O[29]
    DIRECTION OUTPUT ;
    USE SIGNAL ;
    ANTENNADIFFAREA 2.724000 ;
    PORT
      LAYER Metal3 ;
        RECT 115.280 1349.260 115.680 1349.660 ;
    END
  END Tile_X0Y1_FrameData_O[29]
  PIN Tile_X0Y1_FrameData_O[2]
    DIRECTION OUTPUT ;
    USE SIGNAL ;
    ANTENNADIFFAREA 2.724000 ;
    PORT
      LAYER Metal3 ;
        RECT 115.280 1303.900 115.680 1304.300 ;
    END
  END Tile_X0Y1_FrameData_O[2]
  PIN Tile_X0Y1_FrameData_O[30]
    DIRECTION OUTPUT ;
    USE SIGNAL ;
    ANTENNADIFFAREA 2.724000 ;
    PORT
      LAYER Metal3 ;
        RECT 115.280 1350.940 115.680 1351.340 ;
    END
  END Tile_X0Y1_FrameData_O[30]
  PIN Tile_X0Y1_FrameData_O[31]
    DIRECTION OUTPUT ;
    USE SIGNAL ;
    ANTENNADIFFAREA 2.724000 ;
    PORT
      LAYER Metal3 ;
        RECT 115.280 1352.620 115.680 1353.020 ;
    END
  END Tile_X0Y1_FrameData_O[31]
  PIN Tile_X0Y1_FrameData_O[3]
    DIRECTION OUTPUT ;
    USE SIGNAL ;
    ANTENNADIFFAREA 2.724000 ;
    PORT
      LAYER Metal3 ;
        RECT 115.280 1305.580 115.680 1305.980 ;
    END
  END Tile_X0Y1_FrameData_O[3]
  PIN Tile_X0Y1_FrameData_O[4]
    DIRECTION OUTPUT ;
    USE SIGNAL ;
    ANTENNADIFFAREA 2.724000 ;
    PORT
      LAYER Metal3 ;
        RECT 115.280 1307.260 115.680 1307.660 ;
    END
  END Tile_X0Y1_FrameData_O[4]
  PIN Tile_X0Y1_FrameData_O[5]
    DIRECTION OUTPUT ;
    USE SIGNAL ;
    ANTENNADIFFAREA 2.724000 ;
    PORT
      LAYER Metal3 ;
        RECT 115.280 1308.940 115.680 1309.340 ;
    END
  END Tile_X0Y1_FrameData_O[5]
  PIN Tile_X0Y1_FrameData_O[6]
    DIRECTION OUTPUT ;
    USE SIGNAL ;
    ANTENNADIFFAREA 2.724000 ;
    PORT
      LAYER Metal3 ;
        RECT 115.280 1310.620 115.680 1311.020 ;
    END
  END Tile_X0Y1_FrameData_O[6]
  PIN Tile_X0Y1_FrameData_O[7]
    DIRECTION OUTPUT ;
    USE SIGNAL ;
    ANTENNADIFFAREA 2.724000 ;
    PORT
      LAYER Metal3 ;
        RECT 115.280 1312.300 115.680 1312.700 ;
    END
  END Tile_X0Y1_FrameData_O[7]
  PIN Tile_X0Y1_FrameData_O[8]
    DIRECTION OUTPUT ;
    USE SIGNAL ;
    ANTENNADIFFAREA 2.724000 ;
    PORT
      LAYER Metal3 ;
        RECT 115.280 1313.980 115.680 1314.380 ;
    END
  END Tile_X0Y1_FrameData_O[8]
  PIN Tile_X0Y1_FrameData_O[9]
    DIRECTION OUTPUT ;
    USE SIGNAL ;
    ANTENNADIFFAREA 2.724000 ;
    PORT
      LAYER Metal3 ;
        RECT 115.280 1315.660 115.680 1316.060 ;
    END
  END Tile_X0Y1_FrameData_O[9]
  PIN Tile_X0Y1_UserCLK
    DIRECTION INPUT ;
    USE SIGNAL ;
    ANTENNAGATEAREA 0.180700 ;
    PORT
      LAYER Metal3 ;
        RECT 0.000 1093.060 0.400 1093.460 ;
    END
  END Tile_X0Y1_UserCLK
  PIN Tile_X0Y1_UserCLKo
    DIRECTION OUTPUT ;
    USE SIGNAL ;
    ANTENNADIFFAREA 2.724000 ;
    PORT
      LAYER Metal3 ;
        RECT 115.280 1292.140 115.680 1292.540 ;
    END
  END Tile_X0Y1_UserCLKo
  PIN Tile_X0Y1_W1END[0]
    DIRECTION INPUT ;
    USE SIGNAL ;
    ANTENNAGATEAREA 1.066000 ;
    PORT
      LAYER Metal3 ;
        RECT 115.280 1191.340 115.680 1191.740 ;
    END
  END Tile_X0Y1_W1END[0]
  PIN Tile_X0Y1_W1END[1]
    DIRECTION INPUT ;
    USE SIGNAL ;
    ANTENNAGATEAREA 1.066000 ;
    PORT
      LAYER Metal3 ;
        RECT 115.280 1193.020 115.680 1193.420 ;
    END
  END Tile_X0Y1_W1END[1]
  PIN Tile_X0Y1_W1END[2]
    DIRECTION INPUT ;
    USE SIGNAL ;
    ANTENNAGATEAREA 1.066000 ;
    PORT
      LAYER Metal3 ;
        RECT 115.280 1194.700 115.680 1195.100 ;
    END
  END Tile_X0Y1_W1END[2]
  PIN Tile_X0Y1_W1END[3]
    DIRECTION INPUT ;
    USE SIGNAL ;
    ANTENNAGATEAREA 1.066000 ;
    PORT
      LAYER Metal3 ;
        RECT 115.280 1196.380 115.680 1196.780 ;
    END
  END Tile_X0Y1_W1END[3]
  PIN Tile_X0Y1_W2END[0]
    DIRECTION INPUT ;
    USE SIGNAL ;
    ANTENNAGATEAREA 0.639600 ;
    PORT
      LAYER Metal3 ;
        RECT 115.280 1217.380 115.680 1217.780 ;
    END
  END Tile_X0Y1_W2END[0]
  PIN Tile_X0Y1_W2END[1]
    DIRECTION INPUT ;
    USE SIGNAL ;
    ANTENNAGATEAREA 0.639600 ;
    PORT
      LAYER Metal3 ;
        RECT 115.280 1219.060 115.680 1219.460 ;
    END
  END Tile_X0Y1_W2END[1]
  PIN Tile_X0Y1_W2END[2]
    DIRECTION INPUT ;
    USE SIGNAL ;
    ANTENNAGATEAREA 0.639600 ;
    PORT
      LAYER Metal3 ;
        RECT 115.280 1220.740 115.680 1221.140 ;
    END
  END Tile_X0Y1_W2END[2]
  PIN Tile_X0Y1_W2END[3]
    DIRECTION INPUT ;
    USE SIGNAL ;
    ANTENNAGATEAREA 0.639600 ;
    PORT
      LAYER Metal3 ;
        RECT 115.280 1222.420 115.680 1222.820 ;
    END
  END Tile_X0Y1_W2END[3]
  PIN Tile_X0Y1_W2END[4]
    DIRECTION INPUT ;
    USE SIGNAL ;
    ANTENNAGATEAREA 0.639600 ;
    PORT
      LAYER Metal3 ;
        RECT 115.280 1224.100 115.680 1224.500 ;
    END
  END Tile_X0Y1_W2END[4]
  PIN Tile_X0Y1_W2END[5]
    DIRECTION INPUT ;
    USE SIGNAL ;
    ANTENNAGATEAREA 0.639600 ;
    PORT
      LAYER Metal3 ;
        RECT 115.280 1225.780 115.680 1226.180 ;
    END
  END Tile_X0Y1_W2END[5]
  PIN Tile_X0Y1_W2END[6]
    DIRECTION INPUT ;
    USE SIGNAL ;
    ANTENNAGATEAREA 0.639600 ;
    PORT
      LAYER Metal3 ;
        RECT 115.280 1227.460 115.680 1227.860 ;
    END
  END Tile_X0Y1_W2END[6]
  PIN Tile_X0Y1_W2END[7]
    DIRECTION INPUT ;
    USE SIGNAL ;
    ANTENNAGATEAREA 0.639600 ;
    PORT
      LAYER Metal3 ;
        RECT 115.280 1229.140 115.680 1229.540 ;
    END
  END Tile_X0Y1_W2END[7]
  PIN Tile_X0Y1_W2MID[0]
    DIRECTION INPUT ;
    USE SIGNAL ;
    ANTENNAGATEAREA 0.639600 ;
    PORT
      LAYER Metal3 ;
        RECT 115.280 1200.580 115.680 1200.980 ;
    END
  END Tile_X0Y1_W2MID[0]
  PIN Tile_X0Y1_W2MID[1]
    DIRECTION INPUT ;
    USE SIGNAL ;
    ANTENNAGATEAREA 0.639600 ;
    PORT
      LAYER Metal3 ;
        RECT 115.280 1202.260 115.680 1202.660 ;
    END
  END Tile_X0Y1_W2MID[1]
  PIN Tile_X0Y1_W2MID[2]
    DIRECTION INPUT ;
    USE SIGNAL ;
    ANTENNAGATEAREA 0.639600 ;
    PORT
      LAYER Metal3 ;
        RECT 115.280 1203.940 115.680 1204.340 ;
    END
  END Tile_X0Y1_W2MID[2]
  PIN Tile_X0Y1_W2MID[3]
    DIRECTION INPUT ;
    USE SIGNAL ;
    ANTENNAGATEAREA 0.639600 ;
    PORT
      LAYER Metal3 ;
        RECT 115.280 1205.620 115.680 1206.020 ;
    END
  END Tile_X0Y1_W2MID[3]
  PIN Tile_X0Y1_W2MID[4]
    DIRECTION INPUT ;
    USE SIGNAL ;
    ANTENNAGATEAREA 0.639600 ;
    PORT
      LAYER Metal3 ;
        RECT 115.280 1207.300 115.680 1207.700 ;
    END
  END Tile_X0Y1_W2MID[4]
  PIN Tile_X0Y1_W2MID[5]
    DIRECTION INPUT ;
    USE SIGNAL ;
    ANTENNAGATEAREA 0.639600 ;
    PORT
      LAYER Metal3 ;
        RECT 115.280 1208.980 115.680 1209.380 ;
    END
  END Tile_X0Y1_W2MID[5]
  PIN Tile_X0Y1_W2MID[6]
    DIRECTION INPUT ;
    USE SIGNAL ;
    ANTENNAGATEAREA 0.639600 ;
    PORT
      LAYER Metal3 ;
        RECT 115.280 1210.660 115.680 1211.060 ;
    END
  END Tile_X0Y1_W2MID[6]
  PIN Tile_X0Y1_W2MID[7]
    DIRECTION INPUT ;
    USE SIGNAL ;
    ANTENNAGATEAREA 0.639600 ;
    PORT
      LAYER Metal3 ;
        RECT 115.280 1212.340 115.680 1212.740 ;
    END
  END Tile_X0Y1_W2MID[7]
  PIN Tile_X0Y1_W6END[0]
    DIRECTION INPUT ;
    USE SIGNAL ;
    ANTENNAGATEAREA 0.639600 ;
    PORT
      LAYER Metal3 ;
        RECT 115.280 1268.620 115.680 1269.020 ;
    END
  END Tile_X0Y1_W6END[0]
  PIN Tile_X0Y1_W6END[10]
    DIRECTION INPUT ;
    USE SIGNAL ;
    ANTENNAGATEAREA 0.639600 ;
    PORT
      LAYER Metal3 ;
        RECT 115.280 1285.420 115.680 1285.820 ;
    END
  END Tile_X0Y1_W6END[10]
  PIN Tile_X0Y1_W6END[11]
    DIRECTION INPUT ;
    USE SIGNAL ;
    ANTENNAGATEAREA 0.639600 ;
    PORT
      LAYER Metal3 ;
        RECT 115.280 1287.100 115.680 1287.500 ;
    END
  END Tile_X0Y1_W6END[11]
  PIN Tile_X0Y1_W6END[1]
    DIRECTION INPUT ;
    USE SIGNAL ;
    ANTENNAGATEAREA 0.639600 ;
    PORT
      LAYER Metal3 ;
        RECT 115.280 1270.300 115.680 1270.700 ;
    END
  END Tile_X0Y1_W6END[1]
  PIN Tile_X0Y1_W6END[2]
    DIRECTION INPUT ;
    USE SIGNAL ;
    ANTENNAGATEAREA 0.639600 ;
    PORT
      LAYER Metal3 ;
        RECT 115.280 1271.980 115.680 1272.380 ;
    END
  END Tile_X0Y1_W6END[2]
  PIN Tile_X0Y1_W6END[3]
    DIRECTION INPUT ;
    USE SIGNAL ;
    ANTENNAGATEAREA 0.639600 ;
    PORT
      LAYER Metal3 ;
        RECT 115.280 1273.660 115.680 1274.060 ;
    END
  END Tile_X0Y1_W6END[3]
  PIN Tile_X0Y1_W6END[4]
    DIRECTION INPUT ;
    USE SIGNAL ;
    ANTENNAGATEAREA 0.852800 ;
    PORT
      LAYER Metal3 ;
        RECT 115.280 1275.340 115.680 1275.740 ;
    END
  END Tile_X0Y1_W6END[4]
  PIN Tile_X0Y1_W6END[5]
    DIRECTION INPUT ;
    USE SIGNAL ;
    ANTENNAGATEAREA 0.852800 ;
    PORT
      LAYER Metal3 ;
        RECT 115.280 1277.020 115.680 1277.420 ;
    END
  END Tile_X0Y1_W6END[5]
  PIN Tile_X0Y1_W6END[6]
    DIRECTION INPUT ;
    USE SIGNAL ;
    ANTENNAGATEAREA 0.852800 ;
    PORT
      LAYER Metal3 ;
        RECT 115.280 1278.700 115.680 1279.100 ;
    END
  END Tile_X0Y1_W6END[6]
  PIN Tile_X0Y1_W6END[7]
    DIRECTION INPUT ;
    USE SIGNAL ;
    ANTENNAGATEAREA 0.852800 ;
    PORT
      LAYER Metal3 ;
        RECT 115.280 1280.380 115.680 1280.780 ;
    END
  END Tile_X0Y1_W6END[7]
  PIN Tile_X0Y1_W6END[8]
    DIRECTION INPUT ;
    USE SIGNAL ;
    ANTENNAGATEAREA 0.639600 ;
    PORT
      LAYER Metal3 ;
        RECT 115.280 1282.060 115.680 1282.460 ;
    END
  END Tile_X0Y1_W6END[8]
  PIN Tile_X0Y1_W6END[9]
    DIRECTION INPUT ;
    USE SIGNAL ;
    ANTENNAGATEAREA 0.639600 ;
    PORT
      LAYER Metal3 ;
        RECT 115.280 1283.740 115.680 1284.140 ;
    END
  END Tile_X0Y1_W6END[9]
  PIN Tile_X0Y1_WW4END[0]
    DIRECTION INPUT ;
    USE SIGNAL ;
    ANTENNAGATEAREA 0.213200 ;
    PORT
      LAYER Metal3 ;
        RECT 115.280 1235.860 115.680 1236.260 ;
    END
  END Tile_X0Y1_WW4END[0]
  PIN Tile_X0Y1_WW4END[10]
    DIRECTION INPUT ;
    USE SIGNAL ;
    ANTENNAGATEAREA 0.213200 ;
    PORT
      LAYER Metal3 ;
        RECT 115.280 1252.660 115.680 1253.060 ;
    END
  END Tile_X0Y1_WW4END[10]
  PIN Tile_X0Y1_WW4END[11]
    DIRECTION INPUT ;
    USE SIGNAL ;
    ANTENNAGATEAREA 0.213200 ;
    PORT
      LAYER Metal3 ;
        RECT 115.280 1254.340 115.680 1254.740 ;
    END
  END Tile_X0Y1_WW4END[11]
  PIN Tile_X0Y1_WW4END[12]
    DIRECTION INPUT ;
    USE SIGNAL ;
    ANTENNAGATEAREA 0.213200 ;
    PORT
      LAYER Metal3 ;
        RECT 115.280 1256.020 115.680 1256.420 ;
    END
  END Tile_X0Y1_WW4END[12]
  PIN Tile_X0Y1_WW4END[13]
    DIRECTION INPUT ;
    USE SIGNAL ;
    ANTENNAGATEAREA 0.213200 ;
    PORT
      LAYER Metal3 ;
        RECT 115.280 1257.700 115.680 1258.100 ;
    END
  END Tile_X0Y1_WW4END[13]
  PIN Tile_X0Y1_WW4END[14]
    DIRECTION INPUT ;
    USE SIGNAL ;
    ANTENNAGATEAREA 0.213200 ;
    PORT
      LAYER Metal3 ;
        RECT 115.280 1259.380 115.680 1259.780 ;
    END
  END Tile_X0Y1_WW4END[14]
  PIN Tile_X0Y1_WW4END[15]
    DIRECTION INPUT ;
    USE SIGNAL ;
    ANTENNAGATEAREA 0.213200 ;
    PORT
      LAYER Metal3 ;
        RECT 115.280 1261.060 115.680 1261.460 ;
    END
  END Tile_X0Y1_WW4END[15]
  PIN Tile_X0Y1_WW4END[1]
    DIRECTION INPUT ;
    USE SIGNAL ;
    ANTENNAGATEAREA 0.213200 ;
    PORT
      LAYER Metal3 ;
        RECT 115.280 1237.540 115.680 1237.940 ;
    END
  END Tile_X0Y1_WW4END[1]
  PIN Tile_X0Y1_WW4END[2]
    DIRECTION INPUT ;
    USE SIGNAL ;
    ANTENNAGATEAREA 0.213200 ;
    PORT
      LAYER Metal3 ;
        RECT 115.280 1239.220 115.680 1239.620 ;
    END
  END Tile_X0Y1_WW4END[2]
  PIN Tile_X0Y1_WW4END[3]
    DIRECTION INPUT ;
    USE SIGNAL ;
    ANTENNAGATEAREA 0.213200 ;
    PORT
      LAYER Metal3 ;
        RECT 115.280 1240.900 115.680 1241.300 ;
    END
  END Tile_X0Y1_WW4END[3]
  PIN Tile_X0Y1_WW4END[4]
    DIRECTION INPUT ;
    USE SIGNAL ;
    ANTENNAGATEAREA 0.213200 ;
    PORT
      LAYER Metal3 ;
        RECT 115.280 1242.580 115.680 1242.980 ;
    END
  END Tile_X0Y1_WW4END[4]
  PIN Tile_X0Y1_WW4END[5]
    DIRECTION INPUT ;
    USE SIGNAL ;
    ANTENNAGATEAREA 0.213200 ;
    PORT
      LAYER Metal3 ;
        RECT 115.280 1244.260 115.680 1244.660 ;
    END
  END Tile_X0Y1_WW4END[5]
  PIN Tile_X0Y1_WW4END[6]
    DIRECTION INPUT ;
    USE SIGNAL ;
    ANTENNAGATEAREA 0.213200 ;
    PORT
      LAYER Metal3 ;
        RECT 115.280 1245.940 115.680 1246.340 ;
    END
  END Tile_X0Y1_WW4END[6]
  PIN Tile_X0Y1_WW4END[7]
    DIRECTION INPUT ;
    USE SIGNAL ;
    ANTENNAGATEAREA 0.213200 ;
    PORT
      LAYER Metal3 ;
        RECT 115.280 1247.620 115.680 1248.020 ;
    END
  END Tile_X0Y1_WW4END[7]
  PIN Tile_X0Y1_WW4END[8]
    DIRECTION INPUT ;
    USE SIGNAL ;
    ANTENNAGATEAREA 0.213200 ;
    PORT
      LAYER Metal3 ;
        RECT 115.280 1249.300 115.680 1249.700 ;
    END
  END Tile_X0Y1_WW4END[8]
  PIN Tile_X0Y1_WW4END[9]
    DIRECTION INPUT ;
    USE SIGNAL ;
    ANTENNAGATEAREA 0.213200 ;
    PORT
      LAYER Metal3 ;
        RECT 115.280 1250.980 115.680 1251.380 ;
    END
  END Tile_X0Y1_WW4END[9]
  PIN Tile_X0Y2_E1BEG[0]
    DIRECTION OUTPUT ;
    USE SIGNAL ;
    ANTENNADIFFAREA 2.724000 ;
    PORT
      LAYER Metal3 ;
        RECT 115.280 818.380 115.680 818.780 ;
    END
  END Tile_X0Y2_E1BEG[0]
  PIN Tile_X0Y2_E1BEG[1]
    DIRECTION OUTPUT ;
    USE SIGNAL ;
    ANTENNADIFFAREA 2.724000 ;
    PORT
      LAYER Metal3 ;
        RECT 115.280 820.060 115.680 820.460 ;
    END
  END Tile_X0Y2_E1BEG[1]
  PIN Tile_X0Y2_E1BEG[2]
    DIRECTION OUTPUT ;
    USE SIGNAL ;
    ANTENNADIFFAREA 2.724000 ;
    PORT
      LAYER Metal3 ;
        RECT 115.280 821.740 115.680 822.140 ;
    END
  END Tile_X0Y2_E1BEG[2]
  PIN Tile_X0Y2_E1BEG[3]
    DIRECTION OUTPUT ;
    USE SIGNAL ;
    ANTENNADIFFAREA 2.724000 ;
    PORT
      LAYER Metal3 ;
        RECT 115.280 823.420 115.680 823.820 ;
    END
  END Tile_X0Y2_E1BEG[3]
  PIN Tile_X0Y2_E2BEG[0]
    DIRECTION OUTPUT ;
    USE SIGNAL ;
    ANTENNADIFFAREA 2.724000 ;
    PORT
      LAYER Metal3 ;
        RECT 115.280 827.620 115.680 828.020 ;
    END
  END Tile_X0Y2_E2BEG[0]
  PIN Tile_X0Y2_E2BEG[1]
    DIRECTION OUTPUT ;
    USE SIGNAL ;
    ANTENNADIFFAREA 2.724000 ;
    PORT
      LAYER Metal3 ;
        RECT 115.280 829.300 115.680 829.700 ;
    END
  END Tile_X0Y2_E2BEG[1]
  PIN Tile_X0Y2_E2BEG[2]
    DIRECTION OUTPUT ;
    USE SIGNAL ;
    ANTENNADIFFAREA 2.724000 ;
    PORT
      LAYER Metal3 ;
        RECT 115.280 830.980 115.680 831.380 ;
    END
  END Tile_X0Y2_E2BEG[2]
  PIN Tile_X0Y2_E2BEG[3]
    DIRECTION OUTPUT ;
    USE SIGNAL ;
    ANTENNADIFFAREA 2.724000 ;
    PORT
      LAYER Metal3 ;
        RECT 115.280 832.660 115.680 833.060 ;
    END
  END Tile_X0Y2_E2BEG[3]
  PIN Tile_X0Y2_E2BEG[4]
    DIRECTION OUTPUT ;
    USE SIGNAL ;
    ANTENNADIFFAREA 2.724000 ;
    PORT
      LAYER Metal3 ;
        RECT 115.280 834.340 115.680 834.740 ;
    END
  END Tile_X0Y2_E2BEG[4]
  PIN Tile_X0Y2_E2BEG[5]
    DIRECTION OUTPUT ;
    USE SIGNAL ;
    ANTENNADIFFAREA 2.724000 ;
    PORT
      LAYER Metal3 ;
        RECT 115.280 836.020 115.680 836.420 ;
    END
  END Tile_X0Y2_E2BEG[5]
  PIN Tile_X0Y2_E2BEG[6]
    DIRECTION OUTPUT ;
    USE SIGNAL ;
    ANTENNADIFFAREA 2.724000 ;
    PORT
      LAYER Metal3 ;
        RECT 115.280 837.700 115.680 838.100 ;
    END
  END Tile_X0Y2_E2BEG[6]
  PIN Tile_X0Y2_E2BEG[7]
    DIRECTION OUTPUT ;
    USE SIGNAL ;
    ANTENNADIFFAREA 2.724000 ;
    PORT
      LAYER Metal3 ;
        RECT 115.280 839.380 115.680 839.780 ;
    END
  END Tile_X0Y2_E2BEG[7]
  PIN Tile_X0Y2_E2BEGb[0]
    DIRECTION OUTPUT ;
    USE SIGNAL ;
    ANTENNADIFFAREA 2.724000 ;
    PORT
      LAYER Metal3 ;
        RECT 115.280 844.420 115.680 844.820 ;
    END
  END Tile_X0Y2_E2BEGb[0]
  PIN Tile_X0Y2_E2BEGb[1]
    DIRECTION OUTPUT ;
    USE SIGNAL ;
    ANTENNADIFFAREA 2.724000 ;
    PORT
      LAYER Metal3 ;
        RECT 115.280 846.100 115.680 846.500 ;
    END
  END Tile_X0Y2_E2BEGb[1]
  PIN Tile_X0Y2_E2BEGb[2]
    DIRECTION OUTPUT ;
    USE SIGNAL ;
    ANTENNADIFFAREA 2.724000 ;
    PORT
      LAYER Metal3 ;
        RECT 115.280 847.780 115.680 848.180 ;
    END
  END Tile_X0Y2_E2BEGb[2]
  PIN Tile_X0Y2_E2BEGb[3]
    DIRECTION OUTPUT ;
    USE SIGNAL ;
    ANTENNADIFFAREA 2.724000 ;
    PORT
      LAYER Metal3 ;
        RECT 115.280 849.460 115.680 849.860 ;
    END
  END Tile_X0Y2_E2BEGb[3]
  PIN Tile_X0Y2_E2BEGb[4]
    DIRECTION OUTPUT ;
    USE SIGNAL ;
    ANTENNADIFFAREA 2.724000 ;
    PORT
      LAYER Metal3 ;
        RECT 115.280 851.140 115.680 851.540 ;
    END
  END Tile_X0Y2_E2BEGb[4]
  PIN Tile_X0Y2_E2BEGb[5]
    DIRECTION OUTPUT ;
    USE SIGNAL ;
    ANTENNADIFFAREA 2.724000 ;
    PORT
      LAYER Metal3 ;
        RECT 115.280 852.820 115.680 853.220 ;
    END
  END Tile_X0Y2_E2BEGb[5]
  PIN Tile_X0Y2_E2BEGb[6]
    DIRECTION OUTPUT ;
    USE SIGNAL ;
    ANTENNADIFFAREA 2.724000 ;
    PORT
      LAYER Metal3 ;
        RECT 115.280 854.500 115.680 854.900 ;
    END
  END Tile_X0Y2_E2BEGb[6]
  PIN Tile_X0Y2_E2BEGb[7]
    DIRECTION OUTPUT ;
    USE SIGNAL ;
    ANTENNADIFFAREA 2.724000 ;
    PORT
      LAYER Metal3 ;
        RECT 115.280 856.180 115.680 856.580 ;
    END
  END Tile_X0Y2_E2BEGb[7]
  PIN Tile_X0Y2_E6BEG[0]
    DIRECTION OUTPUT ;
    USE SIGNAL ;
    ANTENNADIFFAREA 2.724000 ;
    PORT
      LAYER Metal3 ;
        RECT 115.280 895.660 115.680 896.060 ;
    END
  END Tile_X0Y2_E6BEG[0]
  PIN Tile_X0Y2_E6BEG[10]
    DIRECTION OUTPUT ;
    USE SIGNAL ;
    ANTENNADIFFAREA 2.724000 ;
    PORT
      LAYER Metal3 ;
        RECT 115.280 912.460 115.680 912.860 ;
    END
  END Tile_X0Y2_E6BEG[10]
  PIN Tile_X0Y2_E6BEG[11]
    DIRECTION OUTPUT ;
    USE SIGNAL ;
    ANTENNADIFFAREA 2.724000 ;
    PORT
      LAYER Metal3 ;
        RECT 115.280 914.140 115.680 914.540 ;
    END
  END Tile_X0Y2_E6BEG[11]
  PIN Tile_X0Y2_E6BEG[1]
    DIRECTION OUTPUT ;
    USE SIGNAL ;
    ANTENNADIFFAREA 2.724000 ;
    PORT
      LAYER Metal3 ;
        RECT 115.280 897.340 115.680 897.740 ;
    END
  END Tile_X0Y2_E6BEG[1]
  PIN Tile_X0Y2_E6BEG[2]
    DIRECTION OUTPUT ;
    USE SIGNAL ;
    ANTENNADIFFAREA 2.724000 ;
    PORT
      LAYER Metal3 ;
        RECT 115.280 899.020 115.680 899.420 ;
    END
  END Tile_X0Y2_E6BEG[2]
  PIN Tile_X0Y2_E6BEG[3]
    DIRECTION OUTPUT ;
    USE SIGNAL ;
    ANTENNADIFFAREA 2.724000 ;
    PORT
      LAYER Metal3 ;
        RECT 115.280 900.700 115.680 901.100 ;
    END
  END Tile_X0Y2_E6BEG[3]
  PIN Tile_X0Y2_E6BEG[4]
    DIRECTION OUTPUT ;
    USE SIGNAL ;
    ANTENNADIFFAREA 2.724000 ;
    PORT
      LAYER Metal3 ;
        RECT 115.280 902.380 115.680 902.780 ;
    END
  END Tile_X0Y2_E6BEG[4]
  PIN Tile_X0Y2_E6BEG[5]
    DIRECTION OUTPUT ;
    USE SIGNAL ;
    ANTENNADIFFAREA 2.724000 ;
    PORT
      LAYER Metal3 ;
        RECT 115.280 904.060 115.680 904.460 ;
    END
  END Tile_X0Y2_E6BEG[5]
  PIN Tile_X0Y2_E6BEG[6]
    DIRECTION OUTPUT ;
    USE SIGNAL ;
    ANTENNADIFFAREA 2.724000 ;
    PORT
      LAYER Metal3 ;
        RECT 115.280 905.740 115.680 906.140 ;
    END
  END Tile_X0Y2_E6BEG[6]
  PIN Tile_X0Y2_E6BEG[7]
    DIRECTION OUTPUT ;
    USE SIGNAL ;
    ANTENNADIFFAREA 2.724000 ;
    PORT
      LAYER Metal3 ;
        RECT 115.280 907.420 115.680 907.820 ;
    END
  END Tile_X0Y2_E6BEG[7]
  PIN Tile_X0Y2_E6BEG[8]
    DIRECTION OUTPUT ;
    USE SIGNAL ;
    ANTENNADIFFAREA 2.724000 ;
    PORT
      LAYER Metal3 ;
        RECT 115.280 909.100 115.680 909.500 ;
    END
  END Tile_X0Y2_E6BEG[8]
  PIN Tile_X0Y2_E6BEG[9]
    DIRECTION OUTPUT ;
    USE SIGNAL ;
    ANTENNADIFFAREA 2.724000 ;
    PORT
      LAYER Metal3 ;
        RECT 115.280 910.780 115.680 911.180 ;
    END
  END Tile_X0Y2_E6BEG[9]
  PIN Tile_X0Y2_EE4BEG[0]
    DIRECTION OUTPUT ;
    USE SIGNAL ;
    ANTENNADIFFAREA 2.724000 ;
    PORT
      LAYER Metal3 ;
        RECT 115.280 862.900 115.680 863.300 ;
    END
  END Tile_X0Y2_EE4BEG[0]
  PIN Tile_X0Y2_EE4BEG[10]
    DIRECTION OUTPUT ;
    USE SIGNAL ;
    ANTENNADIFFAREA 2.724000 ;
    PORT
      LAYER Metal3 ;
        RECT 115.280 879.700 115.680 880.100 ;
    END
  END Tile_X0Y2_EE4BEG[10]
  PIN Tile_X0Y2_EE4BEG[11]
    DIRECTION OUTPUT ;
    USE SIGNAL ;
    ANTENNADIFFAREA 2.724000 ;
    PORT
      LAYER Metal3 ;
        RECT 115.280 881.380 115.680 881.780 ;
    END
  END Tile_X0Y2_EE4BEG[11]
  PIN Tile_X0Y2_EE4BEG[12]
    DIRECTION OUTPUT ;
    USE SIGNAL ;
    ANTENNADIFFAREA 2.724000 ;
    PORT
      LAYER Metal3 ;
        RECT 115.280 883.060 115.680 883.460 ;
    END
  END Tile_X0Y2_EE4BEG[12]
  PIN Tile_X0Y2_EE4BEG[13]
    DIRECTION OUTPUT ;
    USE SIGNAL ;
    ANTENNADIFFAREA 2.724000 ;
    PORT
      LAYER Metal3 ;
        RECT 115.280 884.740 115.680 885.140 ;
    END
  END Tile_X0Y2_EE4BEG[13]
  PIN Tile_X0Y2_EE4BEG[14]
    DIRECTION OUTPUT ;
    USE SIGNAL ;
    ANTENNADIFFAREA 2.724000 ;
    PORT
      LAYER Metal3 ;
        RECT 115.280 886.420 115.680 886.820 ;
    END
  END Tile_X0Y2_EE4BEG[14]
  PIN Tile_X0Y2_EE4BEG[15]
    DIRECTION OUTPUT ;
    USE SIGNAL ;
    ANTENNADIFFAREA 2.724000 ;
    PORT
      LAYER Metal3 ;
        RECT 115.280 888.100 115.680 888.500 ;
    END
  END Tile_X0Y2_EE4BEG[15]
  PIN Tile_X0Y2_EE4BEG[1]
    DIRECTION OUTPUT ;
    USE SIGNAL ;
    ANTENNADIFFAREA 2.724000 ;
    PORT
      LAYER Metal3 ;
        RECT 115.280 864.580 115.680 864.980 ;
    END
  END Tile_X0Y2_EE4BEG[1]
  PIN Tile_X0Y2_EE4BEG[2]
    DIRECTION OUTPUT ;
    USE SIGNAL ;
    ANTENNADIFFAREA 2.724000 ;
    PORT
      LAYER Metal3 ;
        RECT 115.280 866.260 115.680 866.660 ;
    END
  END Tile_X0Y2_EE4BEG[2]
  PIN Tile_X0Y2_EE4BEG[3]
    DIRECTION OUTPUT ;
    USE SIGNAL ;
    ANTENNADIFFAREA 2.724000 ;
    PORT
      LAYER Metal3 ;
        RECT 115.280 867.940 115.680 868.340 ;
    END
  END Tile_X0Y2_EE4BEG[3]
  PIN Tile_X0Y2_EE4BEG[4]
    DIRECTION OUTPUT ;
    USE SIGNAL ;
    ANTENNADIFFAREA 2.724000 ;
    PORT
      LAYER Metal3 ;
        RECT 115.280 869.620 115.680 870.020 ;
    END
  END Tile_X0Y2_EE4BEG[4]
  PIN Tile_X0Y2_EE4BEG[5]
    DIRECTION OUTPUT ;
    USE SIGNAL ;
    ANTENNADIFFAREA 2.724000 ;
    PORT
      LAYER Metal3 ;
        RECT 115.280 871.300 115.680 871.700 ;
    END
  END Tile_X0Y2_EE4BEG[5]
  PIN Tile_X0Y2_EE4BEG[6]
    DIRECTION OUTPUT ;
    USE SIGNAL ;
    ANTENNADIFFAREA 2.724000 ;
    PORT
      LAYER Metal3 ;
        RECT 115.280 872.980 115.680 873.380 ;
    END
  END Tile_X0Y2_EE4BEG[6]
  PIN Tile_X0Y2_EE4BEG[7]
    DIRECTION OUTPUT ;
    USE SIGNAL ;
    ANTENNADIFFAREA 2.724000 ;
    PORT
      LAYER Metal3 ;
        RECT 115.280 874.660 115.680 875.060 ;
    END
  END Tile_X0Y2_EE4BEG[7]
  PIN Tile_X0Y2_EE4BEG[8]
    DIRECTION OUTPUT ;
    USE SIGNAL ;
    ANTENNADIFFAREA 2.724000 ;
    PORT
      LAYER Metal3 ;
        RECT 115.280 876.340 115.680 876.740 ;
    END
  END Tile_X0Y2_EE4BEG[8]
  PIN Tile_X0Y2_EE4BEG[9]
    DIRECTION OUTPUT ;
    USE SIGNAL ;
    ANTENNADIFFAREA 2.724000 ;
    PORT
      LAYER Metal3 ;
        RECT 115.280 878.020 115.680 878.420 ;
    END
  END Tile_X0Y2_EE4BEG[9]
  PIN Tile_X0Y2_FrameData[0]
    DIRECTION INPUT ;
    USE SIGNAL ;
    ANTENNAGATEAREA 1.445600 ;
    PORT
      LAYER Metal3 ;
        RECT 0.000 839.380 0.400 839.780 ;
    END
  END Tile_X0Y2_FrameData[0]
  PIN Tile_X0Y2_FrameData[10]
    DIRECTION INPUT ;
    USE SIGNAL ;
    ANTENNAGATEAREA 1.445600 ;
    PORT
      LAYER Metal3 ;
        RECT 0.000 914.980 0.400 915.380 ;
    END
  END Tile_X0Y2_FrameData[10]
  PIN Tile_X0Y2_FrameData[11]
    DIRECTION INPUT ;
    USE SIGNAL ;
    ANTENNAGATEAREA 1.445600 ;
    PORT
      LAYER Metal3 ;
        RECT 0.000 922.540 0.400 922.940 ;
    END
  END Tile_X0Y2_FrameData[11]
  PIN Tile_X0Y2_FrameData[12]
    DIRECTION INPUT ;
    USE SIGNAL ;
    ANTENNAGATEAREA 1.445600 ;
    PORT
      LAYER Metal3 ;
        RECT 0.000 930.100 0.400 930.500 ;
    END
  END Tile_X0Y2_FrameData[12]
  PIN Tile_X0Y2_FrameData[13]
    DIRECTION INPUT ;
    USE SIGNAL ;
    ANTENNAGATEAREA 1.445600 ;
    PORT
      LAYER Metal3 ;
        RECT 0.000 937.660 0.400 938.060 ;
    END
  END Tile_X0Y2_FrameData[13]
  PIN Tile_X0Y2_FrameData[14]
    DIRECTION INPUT ;
    USE SIGNAL ;
    ANTENNAGATEAREA 1.445600 ;
    PORT
      LAYER Metal3 ;
        RECT 0.000 945.220 0.400 945.620 ;
    END
  END Tile_X0Y2_FrameData[14]
  PIN Tile_X0Y2_FrameData[15]
    DIRECTION INPUT ;
    USE SIGNAL ;
    ANTENNAGATEAREA 1.445600 ;
    PORT
      LAYER Metal3 ;
        RECT 0.000 952.780 0.400 953.180 ;
    END
  END Tile_X0Y2_FrameData[15]
  PIN Tile_X0Y2_FrameData[16]
    DIRECTION INPUT ;
    USE SIGNAL ;
    ANTENNAGATEAREA 1.626300 ;
    PORT
      LAYER Metal3 ;
        RECT 0.000 960.340 0.400 960.740 ;
    END
  END Tile_X0Y2_FrameData[16]
  PIN Tile_X0Y2_FrameData[17]
    DIRECTION INPUT ;
    USE SIGNAL ;
    ANTENNAGATEAREA 1.626300 ;
    PORT
      LAYER Metal3 ;
        RECT 0.000 967.900 0.400 968.300 ;
    END
  END Tile_X0Y2_FrameData[17]
  PIN Tile_X0Y2_FrameData[18]
    DIRECTION INPUT ;
    USE SIGNAL ;
    ANTENNAGATEAREA 1.626300 ;
    PORT
      LAYER Metal3 ;
        RECT 0.000 975.460 0.400 975.860 ;
    END
  END Tile_X0Y2_FrameData[18]
  PIN Tile_X0Y2_FrameData[19]
    DIRECTION INPUT ;
    USE SIGNAL ;
    ANTENNAGATEAREA 1.626300 ;
    PORT
      LAYER Metal3 ;
        RECT 0.000 983.020 0.400 983.420 ;
    END
  END Tile_X0Y2_FrameData[19]
  PIN Tile_X0Y2_FrameData[1]
    DIRECTION INPUT ;
    USE SIGNAL ;
    ANTENNAGATEAREA 1.445600 ;
    PORT
      LAYER Metal3 ;
        RECT 0.000 846.940 0.400 847.340 ;
    END
  END Tile_X0Y2_FrameData[1]
  PIN Tile_X0Y2_FrameData[20]
    DIRECTION INPUT ;
    USE SIGNAL ;
    ANTENNAGATEAREA 1.626300 ;
    PORT
      LAYER Metal3 ;
        RECT 0.000 990.580 0.400 990.980 ;
    END
  END Tile_X0Y2_FrameData[20]
  PIN Tile_X0Y2_FrameData[21]
    DIRECTION INPUT ;
    USE SIGNAL ;
    ANTENNAGATEAREA 1.626300 ;
    PORT
      LAYER Metal3 ;
        RECT 0.000 998.140 0.400 998.540 ;
    END
  END Tile_X0Y2_FrameData[21]
  PIN Tile_X0Y2_FrameData[22]
    DIRECTION INPUT ;
    USE SIGNAL ;
    ANTENNAGATEAREA 1.626300 ;
    PORT
      LAYER Metal3 ;
        RECT 0.000 1005.700 0.400 1006.100 ;
    END
  END Tile_X0Y2_FrameData[22]
  PIN Tile_X0Y2_FrameData[23]
    DIRECTION INPUT ;
    USE SIGNAL ;
    ANTENNAGATEAREA 1.626300 ;
    PORT
      LAYER Metal3 ;
        RECT 0.000 1013.260 0.400 1013.660 ;
    END
  END Tile_X0Y2_FrameData[23]
  PIN Tile_X0Y2_FrameData[24]
    DIRECTION INPUT ;
    USE SIGNAL ;
    ANTENNAGATEAREA 1.626300 ;
    PORT
      LAYER Metal3 ;
        RECT 0.000 1020.820 0.400 1021.220 ;
    END
  END Tile_X0Y2_FrameData[24]
  PIN Tile_X0Y2_FrameData[25]
    DIRECTION INPUT ;
    USE SIGNAL ;
    ANTENNAGATEAREA 1.626300 ;
    ANTENNADIFFAREA 18.138599 ;
    PORT
      LAYER Metal3 ;
        RECT 0.000 1028.380 0.400 1028.780 ;
    END
  END Tile_X0Y2_FrameData[25]
  PIN Tile_X0Y2_FrameData[26]
    DIRECTION INPUT ;
    USE SIGNAL ;
    ANTENNAGATEAREA 1.626300 ;
    PORT
      LAYER Metal3 ;
        RECT 0.000 1035.940 0.400 1036.340 ;
    END
  END Tile_X0Y2_FrameData[26]
  PIN Tile_X0Y2_FrameData[27]
    DIRECTION INPUT ;
    USE SIGNAL ;
    ANTENNAGATEAREA 1.626300 ;
    PORT
      LAYER Metal3 ;
        RECT 0.000 1043.500 0.400 1043.900 ;
    END
  END Tile_X0Y2_FrameData[27]
  PIN Tile_X0Y2_FrameData[28]
    DIRECTION INPUT ;
    USE SIGNAL ;
    ANTENNAGATEAREA 1.626300 ;
    PORT
      LAYER Metal3 ;
        RECT 0.000 1051.060 0.400 1051.460 ;
    END
  END Tile_X0Y2_FrameData[28]
  PIN Tile_X0Y2_FrameData[29]
    DIRECTION INPUT ;
    USE SIGNAL ;
    ANTENNAGATEAREA 1.626300 ;
    PORT
      LAYER Metal3 ;
        RECT 0.000 1058.620 0.400 1059.020 ;
    END
  END Tile_X0Y2_FrameData[29]
  PIN Tile_X0Y2_FrameData[2]
    DIRECTION INPUT ;
    USE SIGNAL ;
    ANTENNAGATEAREA 1.445600 ;
    PORT
      LAYER Metal3 ;
        RECT 0.000 854.500 0.400 854.900 ;
    END
  END Tile_X0Y2_FrameData[2]
  PIN Tile_X0Y2_FrameData[30]
    DIRECTION INPUT ;
    USE SIGNAL ;
    ANTENNAGATEAREA 1.626300 ;
    PORT
      LAYER Metal3 ;
        RECT 0.000 1066.180 0.400 1066.580 ;
    END
  END Tile_X0Y2_FrameData[30]
  PIN Tile_X0Y2_FrameData[31]
    DIRECTION INPUT ;
    USE SIGNAL ;
    ANTENNAGATEAREA 1.626300 ;
    PORT
      LAYER Metal3 ;
        RECT 0.000 1073.740 0.400 1074.140 ;
    END
  END Tile_X0Y2_FrameData[31]
  PIN Tile_X0Y2_FrameData[3]
    DIRECTION INPUT ;
    USE SIGNAL ;
    ANTENNAGATEAREA 1.445600 ;
    PORT
      LAYER Metal3 ;
        RECT 0.000 862.060 0.400 862.460 ;
    END
  END Tile_X0Y2_FrameData[3]
  PIN Tile_X0Y2_FrameData[4]
    DIRECTION INPUT ;
    USE SIGNAL ;
    ANTENNAGATEAREA 1.445600 ;
    PORT
      LAYER Metal3 ;
        RECT 0.000 869.620 0.400 870.020 ;
    END
  END Tile_X0Y2_FrameData[4]
  PIN Tile_X0Y2_FrameData[5]
    DIRECTION INPUT ;
    USE SIGNAL ;
    ANTENNAGATEAREA 1.445600 ;
    PORT
      LAYER Metal3 ;
        RECT 0.000 877.180 0.400 877.580 ;
    END
  END Tile_X0Y2_FrameData[5]
  PIN Tile_X0Y2_FrameData[6]
    DIRECTION INPUT ;
    USE SIGNAL ;
    ANTENNAGATEAREA 1.445600 ;
    PORT
      LAYER Metal3 ;
        RECT 0.000 884.740 0.400 885.140 ;
    END
  END Tile_X0Y2_FrameData[6]
  PIN Tile_X0Y2_FrameData[7]
    DIRECTION INPUT ;
    USE SIGNAL ;
    ANTENNAGATEAREA 1.445600 ;
    PORT
      LAYER Metal3 ;
        RECT 0.000 892.300 0.400 892.700 ;
    END
  END Tile_X0Y2_FrameData[7]
  PIN Tile_X0Y2_FrameData[8]
    DIRECTION INPUT ;
    USE SIGNAL ;
    ANTENNAGATEAREA 1.445600 ;
    PORT
      LAYER Metal3 ;
        RECT 0.000 899.860 0.400 900.260 ;
    END
  END Tile_X0Y2_FrameData[8]
  PIN Tile_X0Y2_FrameData[9]
    DIRECTION INPUT ;
    USE SIGNAL ;
    ANTENNAGATEAREA 1.445600 ;
    PORT
      LAYER Metal3 ;
        RECT 0.000 907.420 0.400 907.820 ;
    END
  END Tile_X0Y2_FrameData[9]
  PIN Tile_X0Y2_FrameData_O[0]
    DIRECTION OUTPUT ;
    USE SIGNAL ;
    ANTENNADIFFAREA 2.724000 ;
    PORT
      LAYER Metal3 ;
        RECT 115.280 1028.380 115.680 1028.780 ;
    END
  END Tile_X0Y2_FrameData_O[0]
  PIN Tile_X0Y2_FrameData_O[10]
    DIRECTION OUTPUT ;
    USE SIGNAL ;
    ANTENNADIFFAREA 2.724000 ;
    PORT
      LAYER Metal3 ;
        RECT 115.280 1045.180 115.680 1045.580 ;
    END
  END Tile_X0Y2_FrameData_O[10]
  PIN Tile_X0Y2_FrameData_O[11]
    DIRECTION OUTPUT ;
    USE SIGNAL ;
    ANTENNADIFFAREA 2.724000 ;
    PORT
      LAYER Metal3 ;
        RECT 115.280 1046.860 115.680 1047.260 ;
    END
  END Tile_X0Y2_FrameData_O[11]
  PIN Tile_X0Y2_FrameData_O[12]
    DIRECTION OUTPUT ;
    USE SIGNAL ;
    ANTENNADIFFAREA 2.724000 ;
    PORT
      LAYER Metal3 ;
        RECT 115.280 1048.540 115.680 1048.940 ;
    END
  END Tile_X0Y2_FrameData_O[12]
  PIN Tile_X0Y2_FrameData_O[13]
    DIRECTION OUTPUT ;
    USE SIGNAL ;
    ANTENNADIFFAREA 2.724000 ;
    PORT
      LAYER Metal3 ;
        RECT 115.280 1050.220 115.680 1050.620 ;
    END
  END Tile_X0Y2_FrameData_O[13]
  PIN Tile_X0Y2_FrameData_O[14]
    DIRECTION OUTPUT ;
    USE SIGNAL ;
    ANTENNADIFFAREA 2.724000 ;
    PORT
      LAYER Metal3 ;
        RECT 115.280 1051.900 115.680 1052.300 ;
    END
  END Tile_X0Y2_FrameData_O[14]
  PIN Tile_X0Y2_FrameData_O[15]
    DIRECTION OUTPUT ;
    USE SIGNAL ;
    ANTENNADIFFAREA 2.724000 ;
    PORT
      LAYER Metal3 ;
        RECT 115.280 1053.580 115.680 1053.980 ;
    END
  END Tile_X0Y2_FrameData_O[15]
  PIN Tile_X0Y2_FrameData_O[16]
    DIRECTION OUTPUT ;
    USE SIGNAL ;
    ANTENNADIFFAREA 2.724000 ;
    PORT
      LAYER Metal3 ;
        RECT 115.280 1055.260 115.680 1055.660 ;
    END
  END Tile_X0Y2_FrameData_O[16]
  PIN Tile_X0Y2_FrameData_O[17]
    DIRECTION OUTPUT ;
    USE SIGNAL ;
    ANTENNADIFFAREA 2.724000 ;
    PORT
      LAYER Metal3 ;
        RECT 115.280 1056.940 115.680 1057.340 ;
    END
  END Tile_X0Y2_FrameData_O[17]
  PIN Tile_X0Y2_FrameData_O[18]
    DIRECTION OUTPUT ;
    USE SIGNAL ;
    ANTENNADIFFAREA 2.724000 ;
    PORT
      LAYER Metal3 ;
        RECT 115.280 1058.620 115.680 1059.020 ;
    END
  END Tile_X0Y2_FrameData_O[18]
  PIN Tile_X0Y2_FrameData_O[19]
    DIRECTION OUTPUT ;
    USE SIGNAL ;
    ANTENNADIFFAREA 2.724000 ;
    PORT
      LAYER Metal3 ;
        RECT 115.280 1060.300 115.680 1060.700 ;
    END
  END Tile_X0Y2_FrameData_O[19]
  PIN Tile_X0Y2_FrameData_O[1]
    DIRECTION OUTPUT ;
    USE SIGNAL ;
    ANTENNADIFFAREA 2.724000 ;
    PORT
      LAYER Metal3 ;
        RECT 115.280 1030.060 115.680 1030.460 ;
    END
  END Tile_X0Y2_FrameData_O[1]
  PIN Tile_X0Y2_FrameData_O[20]
    DIRECTION OUTPUT ;
    USE SIGNAL ;
    ANTENNADIFFAREA 2.724000 ;
    PORT
      LAYER Metal3 ;
        RECT 115.280 1061.980 115.680 1062.380 ;
    END
  END Tile_X0Y2_FrameData_O[20]
  PIN Tile_X0Y2_FrameData_O[21]
    DIRECTION OUTPUT ;
    USE SIGNAL ;
    ANTENNADIFFAREA 2.724000 ;
    PORT
      LAYER Metal3 ;
        RECT 115.280 1063.660 115.680 1064.060 ;
    END
  END Tile_X0Y2_FrameData_O[21]
  PIN Tile_X0Y2_FrameData_O[22]
    DIRECTION OUTPUT ;
    USE SIGNAL ;
    ANTENNADIFFAREA 2.724000 ;
    PORT
      LAYER Metal3 ;
        RECT 115.280 1065.340 115.680 1065.740 ;
    END
  END Tile_X0Y2_FrameData_O[22]
  PIN Tile_X0Y2_FrameData_O[23]
    DIRECTION OUTPUT ;
    USE SIGNAL ;
    ANTENNADIFFAREA 2.724000 ;
    PORT
      LAYER Metal3 ;
        RECT 115.280 1067.020 115.680 1067.420 ;
    END
  END Tile_X0Y2_FrameData_O[23]
  PIN Tile_X0Y2_FrameData_O[24]
    DIRECTION OUTPUT ;
    USE SIGNAL ;
    ANTENNADIFFAREA 2.724000 ;
    PORT
      LAYER Metal3 ;
        RECT 115.280 1068.700 115.680 1069.100 ;
    END
  END Tile_X0Y2_FrameData_O[24]
  PIN Tile_X0Y2_FrameData_O[25]
    DIRECTION OUTPUT ;
    USE SIGNAL ;
    ANTENNADIFFAREA 2.724000 ;
    PORT
      LAYER Metal3 ;
        RECT 115.280 1070.380 115.680 1070.780 ;
    END
  END Tile_X0Y2_FrameData_O[25]
  PIN Tile_X0Y2_FrameData_O[26]
    DIRECTION OUTPUT ;
    USE SIGNAL ;
    ANTENNADIFFAREA 2.724000 ;
    PORT
      LAYER Metal3 ;
        RECT 115.280 1072.060 115.680 1072.460 ;
    END
  END Tile_X0Y2_FrameData_O[26]
  PIN Tile_X0Y2_FrameData_O[27]
    DIRECTION OUTPUT ;
    USE SIGNAL ;
    ANTENNADIFFAREA 2.724000 ;
    PORT
      LAYER Metal3 ;
        RECT 115.280 1073.740 115.680 1074.140 ;
    END
  END Tile_X0Y2_FrameData_O[27]
  PIN Tile_X0Y2_FrameData_O[28]
    DIRECTION OUTPUT ;
    USE SIGNAL ;
    ANTENNADIFFAREA 2.724000 ;
    PORT
      LAYER Metal3 ;
        RECT 115.280 1075.420 115.680 1075.820 ;
    END
  END Tile_X0Y2_FrameData_O[28]
  PIN Tile_X0Y2_FrameData_O[29]
    DIRECTION OUTPUT ;
    USE SIGNAL ;
    ANTENNADIFFAREA 2.724000 ;
    PORT
      LAYER Metal3 ;
        RECT 115.280 1077.100 115.680 1077.500 ;
    END
  END Tile_X0Y2_FrameData_O[29]
  PIN Tile_X0Y2_FrameData_O[2]
    DIRECTION OUTPUT ;
    USE SIGNAL ;
    ANTENNADIFFAREA 2.724000 ;
    PORT
      LAYER Metal3 ;
        RECT 115.280 1031.740 115.680 1032.140 ;
    END
  END Tile_X0Y2_FrameData_O[2]
  PIN Tile_X0Y2_FrameData_O[30]
    DIRECTION OUTPUT ;
    USE SIGNAL ;
    ANTENNADIFFAREA 2.724000 ;
    PORT
      LAYER Metal3 ;
        RECT 115.280 1078.780 115.680 1079.180 ;
    END
  END Tile_X0Y2_FrameData_O[30]
  PIN Tile_X0Y2_FrameData_O[31]
    DIRECTION OUTPUT ;
    USE SIGNAL ;
    ANTENNADIFFAREA 2.724000 ;
    PORT
      LAYER Metal3 ;
        RECT 115.280 1080.460 115.680 1080.860 ;
    END
  END Tile_X0Y2_FrameData_O[31]
  PIN Tile_X0Y2_FrameData_O[3]
    DIRECTION OUTPUT ;
    USE SIGNAL ;
    ANTENNADIFFAREA 2.724000 ;
    PORT
      LAYER Metal3 ;
        RECT 115.280 1033.420 115.680 1033.820 ;
    END
  END Tile_X0Y2_FrameData_O[3]
  PIN Tile_X0Y2_FrameData_O[4]
    DIRECTION OUTPUT ;
    USE SIGNAL ;
    ANTENNADIFFAREA 2.724000 ;
    PORT
      LAYER Metal3 ;
        RECT 115.280 1035.100 115.680 1035.500 ;
    END
  END Tile_X0Y2_FrameData_O[4]
  PIN Tile_X0Y2_FrameData_O[5]
    DIRECTION OUTPUT ;
    USE SIGNAL ;
    ANTENNADIFFAREA 2.724000 ;
    PORT
      LAYER Metal3 ;
        RECT 115.280 1036.780 115.680 1037.180 ;
    END
  END Tile_X0Y2_FrameData_O[5]
  PIN Tile_X0Y2_FrameData_O[6]
    DIRECTION OUTPUT ;
    USE SIGNAL ;
    ANTENNADIFFAREA 2.724000 ;
    PORT
      LAYER Metal3 ;
        RECT 115.280 1038.460 115.680 1038.860 ;
    END
  END Tile_X0Y2_FrameData_O[6]
  PIN Tile_X0Y2_FrameData_O[7]
    DIRECTION OUTPUT ;
    USE SIGNAL ;
    ANTENNADIFFAREA 2.724000 ;
    PORT
      LAYER Metal3 ;
        RECT 115.280 1040.140 115.680 1040.540 ;
    END
  END Tile_X0Y2_FrameData_O[7]
  PIN Tile_X0Y2_FrameData_O[8]
    DIRECTION OUTPUT ;
    USE SIGNAL ;
    ANTENNADIFFAREA 2.724000 ;
    PORT
      LAYER Metal3 ;
        RECT 115.280 1041.820 115.680 1042.220 ;
    END
  END Tile_X0Y2_FrameData_O[8]
  PIN Tile_X0Y2_FrameData_O[9]
    DIRECTION OUTPUT ;
    USE SIGNAL ;
    ANTENNADIFFAREA 2.724000 ;
    PORT
      LAYER Metal3 ;
        RECT 115.280 1043.500 115.680 1043.900 ;
    END
  END Tile_X0Y2_FrameData_O[9]
  PIN Tile_X0Y2_UserCLK
    DIRECTION INPUT ;
    USE SIGNAL ;
    ANTENNAGATEAREA 0.180700 ;
    PORT
      LAYER Metal3 ;
        RECT 0.000 820.900 0.400 821.300 ;
    END
  END Tile_X0Y2_UserCLK
  PIN Tile_X0Y2_UserCLKo
    DIRECTION OUTPUT ;
    USE SIGNAL ;
    ANTENNADIFFAREA 2.724000 ;
    PORT
      LAYER Metal3 ;
        RECT 115.280 1019.980 115.680 1020.380 ;
    END
  END Tile_X0Y2_UserCLKo
  PIN Tile_X0Y2_W1END[0]
    DIRECTION INPUT ;
    USE SIGNAL ;
    ANTENNAGATEAREA 1.066000 ;
    PORT
      LAYER Metal3 ;
        RECT 115.280 919.180 115.680 919.580 ;
    END
  END Tile_X0Y2_W1END[0]
  PIN Tile_X0Y2_W1END[1]
    DIRECTION INPUT ;
    USE SIGNAL ;
    ANTENNAGATEAREA 1.066000 ;
    PORT
      LAYER Metal3 ;
        RECT 115.280 920.860 115.680 921.260 ;
    END
  END Tile_X0Y2_W1END[1]
  PIN Tile_X0Y2_W1END[2]
    DIRECTION INPUT ;
    USE SIGNAL ;
    ANTENNAGATEAREA 1.066000 ;
    PORT
      LAYER Metal3 ;
        RECT 115.280 922.540 115.680 922.940 ;
    END
  END Tile_X0Y2_W1END[2]
  PIN Tile_X0Y2_W1END[3]
    DIRECTION INPUT ;
    USE SIGNAL ;
    ANTENNAGATEAREA 1.066000 ;
    PORT
      LAYER Metal3 ;
        RECT 115.280 924.220 115.680 924.620 ;
    END
  END Tile_X0Y2_W1END[3]
  PIN Tile_X0Y2_W2END[0]
    DIRECTION INPUT ;
    USE SIGNAL ;
    ANTENNAGATEAREA 0.639600 ;
    PORT
      LAYER Metal3 ;
        RECT 115.280 945.220 115.680 945.620 ;
    END
  END Tile_X0Y2_W2END[0]
  PIN Tile_X0Y2_W2END[1]
    DIRECTION INPUT ;
    USE SIGNAL ;
    ANTENNAGATEAREA 0.639600 ;
    PORT
      LAYER Metal3 ;
        RECT 115.280 946.900 115.680 947.300 ;
    END
  END Tile_X0Y2_W2END[1]
  PIN Tile_X0Y2_W2END[2]
    DIRECTION INPUT ;
    USE SIGNAL ;
    ANTENNAGATEAREA 0.639600 ;
    PORT
      LAYER Metal3 ;
        RECT 115.280 948.580 115.680 948.980 ;
    END
  END Tile_X0Y2_W2END[2]
  PIN Tile_X0Y2_W2END[3]
    DIRECTION INPUT ;
    USE SIGNAL ;
    ANTENNAGATEAREA 0.639600 ;
    PORT
      LAYER Metal3 ;
        RECT 115.280 950.260 115.680 950.660 ;
    END
  END Tile_X0Y2_W2END[3]
  PIN Tile_X0Y2_W2END[4]
    DIRECTION INPUT ;
    USE SIGNAL ;
    ANTENNAGATEAREA 0.639600 ;
    PORT
      LAYER Metal3 ;
        RECT 115.280 951.940 115.680 952.340 ;
    END
  END Tile_X0Y2_W2END[4]
  PIN Tile_X0Y2_W2END[5]
    DIRECTION INPUT ;
    USE SIGNAL ;
    ANTENNAGATEAREA 0.639600 ;
    PORT
      LAYER Metal3 ;
        RECT 115.280 953.620 115.680 954.020 ;
    END
  END Tile_X0Y2_W2END[5]
  PIN Tile_X0Y2_W2END[6]
    DIRECTION INPUT ;
    USE SIGNAL ;
    ANTENNAGATEAREA 0.639600 ;
    PORT
      LAYER Metal3 ;
        RECT 115.280 955.300 115.680 955.700 ;
    END
  END Tile_X0Y2_W2END[6]
  PIN Tile_X0Y2_W2END[7]
    DIRECTION INPUT ;
    USE SIGNAL ;
    ANTENNAGATEAREA 0.639600 ;
    PORT
      LAYER Metal3 ;
        RECT 115.280 956.980 115.680 957.380 ;
    END
  END Tile_X0Y2_W2END[7]
  PIN Tile_X0Y2_W2MID[0]
    DIRECTION INPUT ;
    USE SIGNAL ;
    ANTENNAGATEAREA 0.639600 ;
    PORT
      LAYER Metal3 ;
        RECT 115.280 928.420 115.680 928.820 ;
    END
  END Tile_X0Y2_W2MID[0]
  PIN Tile_X0Y2_W2MID[1]
    DIRECTION INPUT ;
    USE SIGNAL ;
    ANTENNAGATEAREA 0.639600 ;
    PORT
      LAYER Metal3 ;
        RECT 115.280 930.100 115.680 930.500 ;
    END
  END Tile_X0Y2_W2MID[1]
  PIN Tile_X0Y2_W2MID[2]
    DIRECTION INPUT ;
    USE SIGNAL ;
    ANTENNAGATEAREA 0.639600 ;
    PORT
      LAYER Metal3 ;
        RECT 115.280 931.780 115.680 932.180 ;
    END
  END Tile_X0Y2_W2MID[2]
  PIN Tile_X0Y2_W2MID[3]
    DIRECTION INPUT ;
    USE SIGNAL ;
    ANTENNAGATEAREA 0.639600 ;
    PORT
      LAYER Metal3 ;
        RECT 115.280 933.460 115.680 933.860 ;
    END
  END Tile_X0Y2_W2MID[3]
  PIN Tile_X0Y2_W2MID[4]
    DIRECTION INPUT ;
    USE SIGNAL ;
    ANTENNAGATEAREA 0.639600 ;
    PORT
      LAYER Metal3 ;
        RECT 115.280 935.140 115.680 935.540 ;
    END
  END Tile_X0Y2_W2MID[4]
  PIN Tile_X0Y2_W2MID[5]
    DIRECTION INPUT ;
    USE SIGNAL ;
    ANTENNAGATEAREA 0.639600 ;
    PORT
      LAYER Metal3 ;
        RECT 115.280 936.820 115.680 937.220 ;
    END
  END Tile_X0Y2_W2MID[5]
  PIN Tile_X0Y2_W2MID[6]
    DIRECTION INPUT ;
    USE SIGNAL ;
    ANTENNAGATEAREA 0.639600 ;
    PORT
      LAYER Metal3 ;
        RECT 115.280 938.500 115.680 938.900 ;
    END
  END Tile_X0Y2_W2MID[6]
  PIN Tile_X0Y2_W2MID[7]
    DIRECTION INPUT ;
    USE SIGNAL ;
    ANTENNAGATEAREA 0.639600 ;
    PORT
      LAYER Metal3 ;
        RECT 115.280 940.180 115.680 940.580 ;
    END
  END Tile_X0Y2_W2MID[7]
  PIN Tile_X0Y2_W6END[0]
    DIRECTION INPUT ;
    USE SIGNAL ;
    ANTENNAGATEAREA 0.639600 ;
    PORT
      LAYER Metal3 ;
        RECT 115.280 996.460 115.680 996.860 ;
    END
  END Tile_X0Y2_W6END[0]
  PIN Tile_X0Y2_W6END[10]
    DIRECTION INPUT ;
    USE SIGNAL ;
    ANTENNAGATEAREA 0.639600 ;
    PORT
      LAYER Metal3 ;
        RECT 115.280 1013.260 115.680 1013.660 ;
    END
  END Tile_X0Y2_W6END[10]
  PIN Tile_X0Y2_W6END[11]
    DIRECTION INPUT ;
    USE SIGNAL ;
    ANTENNAGATEAREA 0.639600 ;
    PORT
      LAYER Metal3 ;
        RECT 115.280 1014.940 115.680 1015.340 ;
    END
  END Tile_X0Y2_W6END[11]
  PIN Tile_X0Y2_W6END[1]
    DIRECTION INPUT ;
    USE SIGNAL ;
    ANTENNAGATEAREA 0.639600 ;
    PORT
      LAYER Metal3 ;
        RECT 115.280 998.140 115.680 998.540 ;
    END
  END Tile_X0Y2_W6END[1]
  PIN Tile_X0Y2_W6END[2]
    DIRECTION INPUT ;
    USE SIGNAL ;
    ANTENNAGATEAREA 0.639600 ;
    PORT
      LAYER Metal3 ;
        RECT 115.280 999.820 115.680 1000.220 ;
    END
  END Tile_X0Y2_W6END[2]
  PIN Tile_X0Y2_W6END[3]
    DIRECTION INPUT ;
    USE SIGNAL ;
    ANTENNAGATEAREA 0.639600 ;
    PORT
      LAYER Metal3 ;
        RECT 115.280 1001.500 115.680 1001.900 ;
    END
  END Tile_X0Y2_W6END[3]
  PIN Tile_X0Y2_W6END[4]
    DIRECTION INPUT ;
    USE SIGNAL ;
    ANTENNAGATEAREA 0.852800 ;
    PORT
      LAYER Metal3 ;
        RECT 115.280 1003.180 115.680 1003.580 ;
    END
  END Tile_X0Y2_W6END[4]
  PIN Tile_X0Y2_W6END[5]
    DIRECTION INPUT ;
    USE SIGNAL ;
    ANTENNAGATEAREA 0.852800 ;
    PORT
      LAYER Metal3 ;
        RECT 115.280 1004.860 115.680 1005.260 ;
    END
  END Tile_X0Y2_W6END[5]
  PIN Tile_X0Y2_W6END[6]
    DIRECTION INPUT ;
    USE SIGNAL ;
    ANTENNAGATEAREA 0.852800 ;
    PORT
      LAYER Metal3 ;
        RECT 115.280 1006.540 115.680 1006.940 ;
    END
  END Tile_X0Y2_W6END[6]
  PIN Tile_X0Y2_W6END[7]
    DIRECTION INPUT ;
    USE SIGNAL ;
    ANTENNAGATEAREA 0.852800 ;
    PORT
      LAYER Metal3 ;
        RECT 115.280 1008.220 115.680 1008.620 ;
    END
  END Tile_X0Y2_W6END[7]
  PIN Tile_X0Y2_W6END[8]
    DIRECTION INPUT ;
    USE SIGNAL ;
    ANTENNAGATEAREA 0.639600 ;
    PORT
      LAYER Metal3 ;
        RECT 115.280 1009.900 115.680 1010.300 ;
    END
  END Tile_X0Y2_W6END[8]
  PIN Tile_X0Y2_W6END[9]
    DIRECTION INPUT ;
    USE SIGNAL ;
    ANTENNAGATEAREA 0.639600 ;
    PORT
      LAYER Metal3 ;
        RECT 115.280 1011.580 115.680 1011.980 ;
    END
  END Tile_X0Y2_W6END[9]
  PIN Tile_X0Y2_WW4END[0]
    DIRECTION INPUT ;
    USE SIGNAL ;
    ANTENNAGATEAREA 0.213200 ;
    PORT
      LAYER Metal3 ;
        RECT 115.280 963.700 115.680 964.100 ;
    END
  END Tile_X0Y2_WW4END[0]
  PIN Tile_X0Y2_WW4END[10]
    DIRECTION INPUT ;
    USE SIGNAL ;
    ANTENNAGATEAREA 0.213200 ;
    PORT
      LAYER Metal3 ;
        RECT 115.280 980.500 115.680 980.900 ;
    END
  END Tile_X0Y2_WW4END[10]
  PIN Tile_X0Y2_WW4END[11]
    DIRECTION INPUT ;
    USE SIGNAL ;
    ANTENNAGATEAREA 0.213200 ;
    PORT
      LAYER Metal3 ;
        RECT 115.280 982.180 115.680 982.580 ;
    END
  END Tile_X0Y2_WW4END[11]
  PIN Tile_X0Y2_WW4END[12]
    DIRECTION INPUT ;
    USE SIGNAL ;
    ANTENNAGATEAREA 0.213200 ;
    PORT
      LAYER Metal3 ;
        RECT 115.280 983.860 115.680 984.260 ;
    END
  END Tile_X0Y2_WW4END[12]
  PIN Tile_X0Y2_WW4END[13]
    DIRECTION INPUT ;
    USE SIGNAL ;
    ANTENNAGATEAREA 0.213200 ;
    PORT
      LAYER Metal3 ;
        RECT 115.280 985.540 115.680 985.940 ;
    END
  END Tile_X0Y2_WW4END[13]
  PIN Tile_X0Y2_WW4END[14]
    DIRECTION INPUT ;
    USE SIGNAL ;
    ANTENNAGATEAREA 0.213200 ;
    PORT
      LAYER Metal3 ;
        RECT 115.280 987.220 115.680 987.620 ;
    END
  END Tile_X0Y2_WW4END[14]
  PIN Tile_X0Y2_WW4END[15]
    DIRECTION INPUT ;
    USE SIGNAL ;
    ANTENNAGATEAREA 0.213200 ;
    PORT
      LAYER Metal3 ;
        RECT 115.280 988.900 115.680 989.300 ;
    END
  END Tile_X0Y2_WW4END[15]
  PIN Tile_X0Y2_WW4END[1]
    DIRECTION INPUT ;
    USE SIGNAL ;
    ANTENNAGATEAREA 0.213200 ;
    PORT
      LAYER Metal3 ;
        RECT 115.280 965.380 115.680 965.780 ;
    END
  END Tile_X0Y2_WW4END[1]
  PIN Tile_X0Y2_WW4END[2]
    DIRECTION INPUT ;
    USE SIGNAL ;
    ANTENNAGATEAREA 0.213200 ;
    PORT
      LAYER Metal3 ;
        RECT 115.280 967.060 115.680 967.460 ;
    END
  END Tile_X0Y2_WW4END[2]
  PIN Tile_X0Y2_WW4END[3]
    DIRECTION INPUT ;
    USE SIGNAL ;
    ANTENNAGATEAREA 0.213200 ;
    PORT
      LAYER Metal3 ;
        RECT 115.280 968.740 115.680 969.140 ;
    END
  END Tile_X0Y2_WW4END[3]
  PIN Tile_X0Y2_WW4END[4]
    DIRECTION INPUT ;
    USE SIGNAL ;
    ANTENNAGATEAREA 0.213200 ;
    PORT
      LAYER Metal3 ;
        RECT 115.280 970.420 115.680 970.820 ;
    END
  END Tile_X0Y2_WW4END[4]
  PIN Tile_X0Y2_WW4END[5]
    DIRECTION INPUT ;
    USE SIGNAL ;
    ANTENNAGATEAREA 0.213200 ;
    PORT
      LAYER Metal3 ;
        RECT 115.280 972.100 115.680 972.500 ;
    END
  END Tile_X0Y2_WW4END[5]
  PIN Tile_X0Y2_WW4END[6]
    DIRECTION INPUT ;
    USE SIGNAL ;
    ANTENNAGATEAREA 0.213200 ;
    PORT
      LAYER Metal3 ;
        RECT 115.280 973.780 115.680 974.180 ;
    END
  END Tile_X0Y2_WW4END[6]
  PIN Tile_X0Y2_WW4END[7]
    DIRECTION INPUT ;
    USE SIGNAL ;
    ANTENNAGATEAREA 0.213200 ;
    PORT
      LAYER Metal3 ;
        RECT 115.280 975.460 115.680 975.860 ;
    END
  END Tile_X0Y2_WW4END[7]
  PIN Tile_X0Y2_WW4END[8]
    DIRECTION INPUT ;
    USE SIGNAL ;
    ANTENNAGATEAREA 0.213200 ;
    PORT
      LAYER Metal3 ;
        RECT 115.280 977.140 115.680 977.540 ;
    END
  END Tile_X0Y2_WW4END[8]
  PIN Tile_X0Y2_WW4END[9]
    DIRECTION INPUT ;
    USE SIGNAL ;
    ANTENNAGATEAREA 0.213200 ;
    PORT
      LAYER Metal3 ;
        RECT 115.280 978.820 115.680 979.220 ;
    END
  END Tile_X0Y2_WW4END[9]
  PIN Tile_X0Y3_E1BEG[0]
    DIRECTION OUTPUT ;
    USE SIGNAL ;
    ANTENNADIFFAREA 2.724000 ;
    PORT
      LAYER Metal3 ;
        RECT 115.280 546.220 115.680 546.620 ;
    END
  END Tile_X0Y3_E1BEG[0]
  PIN Tile_X0Y3_E1BEG[1]
    DIRECTION OUTPUT ;
    USE SIGNAL ;
    ANTENNADIFFAREA 2.724000 ;
    PORT
      LAYER Metal3 ;
        RECT 115.280 547.900 115.680 548.300 ;
    END
  END Tile_X0Y3_E1BEG[1]
  PIN Tile_X0Y3_E1BEG[2]
    DIRECTION OUTPUT ;
    USE SIGNAL ;
    ANTENNADIFFAREA 2.724000 ;
    PORT
      LAYER Metal3 ;
        RECT 115.280 549.580 115.680 549.980 ;
    END
  END Tile_X0Y3_E1BEG[2]
  PIN Tile_X0Y3_E1BEG[3]
    DIRECTION OUTPUT ;
    USE SIGNAL ;
    ANTENNADIFFAREA 2.724000 ;
    PORT
      LAYER Metal3 ;
        RECT 115.280 551.260 115.680 551.660 ;
    END
  END Tile_X0Y3_E1BEG[3]
  PIN Tile_X0Y3_E2BEG[0]
    DIRECTION OUTPUT ;
    USE SIGNAL ;
    ANTENNADIFFAREA 2.724000 ;
    PORT
      LAYER Metal3 ;
        RECT 115.280 555.460 115.680 555.860 ;
    END
  END Tile_X0Y3_E2BEG[0]
  PIN Tile_X0Y3_E2BEG[1]
    DIRECTION OUTPUT ;
    USE SIGNAL ;
    ANTENNADIFFAREA 2.724000 ;
    PORT
      LAYER Metal3 ;
        RECT 115.280 557.140 115.680 557.540 ;
    END
  END Tile_X0Y3_E2BEG[1]
  PIN Tile_X0Y3_E2BEG[2]
    DIRECTION OUTPUT ;
    USE SIGNAL ;
    ANTENNADIFFAREA 2.724000 ;
    PORT
      LAYER Metal3 ;
        RECT 115.280 558.820 115.680 559.220 ;
    END
  END Tile_X0Y3_E2BEG[2]
  PIN Tile_X0Y3_E2BEG[3]
    DIRECTION OUTPUT ;
    USE SIGNAL ;
    ANTENNADIFFAREA 2.724000 ;
    PORT
      LAYER Metal3 ;
        RECT 115.280 560.500 115.680 560.900 ;
    END
  END Tile_X0Y3_E2BEG[3]
  PIN Tile_X0Y3_E2BEG[4]
    DIRECTION OUTPUT ;
    USE SIGNAL ;
    ANTENNADIFFAREA 2.724000 ;
    PORT
      LAYER Metal3 ;
        RECT 115.280 562.180 115.680 562.580 ;
    END
  END Tile_X0Y3_E2BEG[4]
  PIN Tile_X0Y3_E2BEG[5]
    DIRECTION OUTPUT ;
    USE SIGNAL ;
    ANTENNADIFFAREA 2.724000 ;
    PORT
      LAYER Metal3 ;
        RECT 115.280 563.860 115.680 564.260 ;
    END
  END Tile_X0Y3_E2BEG[5]
  PIN Tile_X0Y3_E2BEG[6]
    DIRECTION OUTPUT ;
    USE SIGNAL ;
    ANTENNADIFFAREA 2.724000 ;
    PORT
      LAYER Metal3 ;
        RECT 115.280 565.540 115.680 565.940 ;
    END
  END Tile_X0Y3_E2BEG[6]
  PIN Tile_X0Y3_E2BEG[7]
    DIRECTION OUTPUT ;
    USE SIGNAL ;
    ANTENNADIFFAREA 2.724000 ;
    PORT
      LAYER Metal3 ;
        RECT 115.280 567.220 115.680 567.620 ;
    END
  END Tile_X0Y3_E2BEG[7]
  PIN Tile_X0Y3_E2BEGb[0]
    DIRECTION OUTPUT ;
    USE SIGNAL ;
    ANTENNADIFFAREA 2.724000 ;
    PORT
      LAYER Metal3 ;
        RECT 115.280 572.260 115.680 572.660 ;
    END
  END Tile_X0Y3_E2BEGb[0]
  PIN Tile_X0Y3_E2BEGb[1]
    DIRECTION OUTPUT ;
    USE SIGNAL ;
    ANTENNADIFFAREA 2.724000 ;
    PORT
      LAYER Metal3 ;
        RECT 115.280 573.940 115.680 574.340 ;
    END
  END Tile_X0Y3_E2BEGb[1]
  PIN Tile_X0Y3_E2BEGb[2]
    DIRECTION OUTPUT ;
    USE SIGNAL ;
    ANTENNADIFFAREA 2.724000 ;
    PORT
      LAYER Metal3 ;
        RECT 115.280 575.620 115.680 576.020 ;
    END
  END Tile_X0Y3_E2BEGb[2]
  PIN Tile_X0Y3_E2BEGb[3]
    DIRECTION OUTPUT ;
    USE SIGNAL ;
    ANTENNADIFFAREA 2.724000 ;
    PORT
      LAYER Metal3 ;
        RECT 115.280 577.300 115.680 577.700 ;
    END
  END Tile_X0Y3_E2BEGb[3]
  PIN Tile_X0Y3_E2BEGb[4]
    DIRECTION OUTPUT ;
    USE SIGNAL ;
    ANTENNADIFFAREA 2.724000 ;
    PORT
      LAYER Metal3 ;
        RECT 115.280 578.980 115.680 579.380 ;
    END
  END Tile_X0Y3_E2BEGb[4]
  PIN Tile_X0Y3_E2BEGb[5]
    DIRECTION OUTPUT ;
    USE SIGNAL ;
    ANTENNADIFFAREA 2.724000 ;
    PORT
      LAYER Metal3 ;
        RECT 115.280 580.660 115.680 581.060 ;
    END
  END Tile_X0Y3_E2BEGb[5]
  PIN Tile_X0Y3_E2BEGb[6]
    DIRECTION OUTPUT ;
    USE SIGNAL ;
    ANTENNADIFFAREA 2.724000 ;
    PORT
      LAYER Metal3 ;
        RECT 115.280 582.340 115.680 582.740 ;
    END
  END Tile_X0Y3_E2BEGb[6]
  PIN Tile_X0Y3_E2BEGb[7]
    DIRECTION OUTPUT ;
    USE SIGNAL ;
    ANTENNADIFFAREA 2.724000 ;
    PORT
      LAYER Metal3 ;
        RECT 115.280 584.020 115.680 584.420 ;
    END
  END Tile_X0Y3_E2BEGb[7]
  PIN Tile_X0Y3_E6BEG[0]
    DIRECTION OUTPUT ;
    USE SIGNAL ;
    ANTENNADIFFAREA 2.724000 ;
    PORT
      LAYER Metal3 ;
        RECT 115.280 623.500 115.680 623.900 ;
    END
  END Tile_X0Y3_E6BEG[0]
  PIN Tile_X0Y3_E6BEG[10]
    DIRECTION OUTPUT ;
    USE SIGNAL ;
    ANTENNADIFFAREA 2.724000 ;
    PORT
      LAYER Metal3 ;
        RECT 115.280 640.300 115.680 640.700 ;
    END
  END Tile_X0Y3_E6BEG[10]
  PIN Tile_X0Y3_E6BEG[11]
    DIRECTION OUTPUT ;
    USE SIGNAL ;
    ANTENNADIFFAREA 2.724000 ;
    PORT
      LAYER Metal3 ;
        RECT 115.280 641.980 115.680 642.380 ;
    END
  END Tile_X0Y3_E6BEG[11]
  PIN Tile_X0Y3_E6BEG[1]
    DIRECTION OUTPUT ;
    USE SIGNAL ;
    ANTENNADIFFAREA 2.724000 ;
    PORT
      LAYER Metal3 ;
        RECT 115.280 625.180 115.680 625.580 ;
    END
  END Tile_X0Y3_E6BEG[1]
  PIN Tile_X0Y3_E6BEG[2]
    DIRECTION OUTPUT ;
    USE SIGNAL ;
    ANTENNADIFFAREA 2.724000 ;
    PORT
      LAYER Metal3 ;
        RECT 115.280 626.860 115.680 627.260 ;
    END
  END Tile_X0Y3_E6BEG[2]
  PIN Tile_X0Y3_E6BEG[3]
    DIRECTION OUTPUT ;
    USE SIGNAL ;
    ANTENNADIFFAREA 2.724000 ;
    PORT
      LAYER Metal3 ;
        RECT 115.280 628.540 115.680 628.940 ;
    END
  END Tile_X0Y3_E6BEG[3]
  PIN Tile_X0Y3_E6BEG[4]
    DIRECTION OUTPUT ;
    USE SIGNAL ;
    ANTENNADIFFAREA 2.724000 ;
    PORT
      LAYER Metal3 ;
        RECT 115.280 630.220 115.680 630.620 ;
    END
  END Tile_X0Y3_E6BEG[4]
  PIN Tile_X0Y3_E6BEG[5]
    DIRECTION OUTPUT ;
    USE SIGNAL ;
    ANTENNADIFFAREA 2.724000 ;
    PORT
      LAYER Metal3 ;
        RECT 115.280 631.900 115.680 632.300 ;
    END
  END Tile_X0Y3_E6BEG[5]
  PIN Tile_X0Y3_E6BEG[6]
    DIRECTION OUTPUT ;
    USE SIGNAL ;
    ANTENNADIFFAREA 2.724000 ;
    PORT
      LAYER Metal3 ;
        RECT 115.280 633.580 115.680 633.980 ;
    END
  END Tile_X0Y3_E6BEG[6]
  PIN Tile_X0Y3_E6BEG[7]
    DIRECTION OUTPUT ;
    USE SIGNAL ;
    ANTENNADIFFAREA 2.724000 ;
    PORT
      LAYER Metal3 ;
        RECT 115.280 635.260 115.680 635.660 ;
    END
  END Tile_X0Y3_E6BEG[7]
  PIN Tile_X0Y3_E6BEG[8]
    DIRECTION OUTPUT ;
    USE SIGNAL ;
    ANTENNADIFFAREA 2.724000 ;
    PORT
      LAYER Metal3 ;
        RECT 115.280 636.940 115.680 637.340 ;
    END
  END Tile_X0Y3_E6BEG[8]
  PIN Tile_X0Y3_E6BEG[9]
    DIRECTION OUTPUT ;
    USE SIGNAL ;
    ANTENNADIFFAREA 2.724000 ;
    PORT
      LAYER Metal3 ;
        RECT 115.280 638.620 115.680 639.020 ;
    END
  END Tile_X0Y3_E6BEG[9]
  PIN Tile_X0Y3_EE4BEG[0]
    DIRECTION OUTPUT ;
    USE SIGNAL ;
    ANTENNADIFFAREA 2.724000 ;
    PORT
      LAYER Metal3 ;
        RECT 115.280 590.740 115.680 591.140 ;
    END
  END Tile_X0Y3_EE4BEG[0]
  PIN Tile_X0Y3_EE4BEG[10]
    DIRECTION OUTPUT ;
    USE SIGNAL ;
    ANTENNADIFFAREA 2.724000 ;
    PORT
      LAYER Metal3 ;
        RECT 115.280 607.540 115.680 607.940 ;
    END
  END Tile_X0Y3_EE4BEG[10]
  PIN Tile_X0Y3_EE4BEG[11]
    DIRECTION OUTPUT ;
    USE SIGNAL ;
    ANTENNADIFFAREA 2.724000 ;
    PORT
      LAYER Metal3 ;
        RECT 115.280 609.220 115.680 609.620 ;
    END
  END Tile_X0Y3_EE4BEG[11]
  PIN Tile_X0Y3_EE4BEG[12]
    DIRECTION OUTPUT ;
    USE SIGNAL ;
    ANTENNADIFFAREA 2.724000 ;
    PORT
      LAYER Metal3 ;
        RECT 115.280 610.900 115.680 611.300 ;
    END
  END Tile_X0Y3_EE4BEG[12]
  PIN Tile_X0Y3_EE4BEG[13]
    DIRECTION OUTPUT ;
    USE SIGNAL ;
    ANTENNADIFFAREA 2.724000 ;
    PORT
      LAYER Metal3 ;
        RECT 115.280 612.580 115.680 612.980 ;
    END
  END Tile_X0Y3_EE4BEG[13]
  PIN Tile_X0Y3_EE4BEG[14]
    DIRECTION OUTPUT ;
    USE SIGNAL ;
    ANTENNADIFFAREA 2.724000 ;
    PORT
      LAYER Metal3 ;
        RECT 115.280 614.260 115.680 614.660 ;
    END
  END Tile_X0Y3_EE4BEG[14]
  PIN Tile_X0Y3_EE4BEG[15]
    DIRECTION OUTPUT ;
    USE SIGNAL ;
    ANTENNADIFFAREA 2.724000 ;
    PORT
      LAYER Metal3 ;
        RECT 115.280 615.940 115.680 616.340 ;
    END
  END Tile_X0Y3_EE4BEG[15]
  PIN Tile_X0Y3_EE4BEG[1]
    DIRECTION OUTPUT ;
    USE SIGNAL ;
    ANTENNADIFFAREA 2.724000 ;
    PORT
      LAYER Metal3 ;
        RECT 115.280 592.420 115.680 592.820 ;
    END
  END Tile_X0Y3_EE4BEG[1]
  PIN Tile_X0Y3_EE4BEG[2]
    DIRECTION OUTPUT ;
    USE SIGNAL ;
    ANTENNADIFFAREA 2.724000 ;
    PORT
      LAYER Metal3 ;
        RECT 115.280 594.100 115.680 594.500 ;
    END
  END Tile_X0Y3_EE4BEG[2]
  PIN Tile_X0Y3_EE4BEG[3]
    DIRECTION OUTPUT ;
    USE SIGNAL ;
    ANTENNADIFFAREA 2.724000 ;
    PORT
      LAYER Metal3 ;
        RECT 115.280 595.780 115.680 596.180 ;
    END
  END Tile_X0Y3_EE4BEG[3]
  PIN Tile_X0Y3_EE4BEG[4]
    DIRECTION OUTPUT ;
    USE SIGNAL ;
    ANTENNADIFFAREA 2.724000 ;
    PORT
      LAYER Metal3 ;
        RECT 115.280 597.460 115.680 597.860 ;
    END
  END Tile_X0Y3_EE4BEG[4]
  PIN Tile_X0Y3_EE4BEG[5]
    DIRECTION OUTPUT ;
    USE SIGNAL ;
    ANTENNADIFFAREA 2.724000 ;
    PORT
      LAYER Metal3 ;
        RECT 115.280 599.140 115.680 599.540 ;
    END
  END Tile_X0Y3_EE4BEG[5]
  PIN Tile_X0Y3_EE4BEG[6]
    DIRECTION OUTPUT ;
    USE SIGNAL ;
    ANTENNADIFFAREA 2.724000 ;
    PORT
      LAYER Metal3 ;
        RECT 115.280 600.820 115.680 601.220 ;
    END
  END Tile_X0Y3_EE4BEG[6]
  PIN Tile_X0Y3_EE4BEG[7]
    DIRECTION OUTPUT ;
    USE SIGNAL ;
    ANTENNADIFFAREA 2.724000 ;
    PORT
      LAYER Metal3 ;
        RECT 115.280 602.500 115.680 602.900 ;
    END
  END Tile_X0Y3_EE4BEG[7]
  PIN Tile_X0Y3_EE4BEG[8]
    DIRECTION OUTPUT ;
    USE SIGNAL ;
    ANTENNADIFFAREA 2.724000 ;
    PORT
      LAYER Metal3 ;
        RECT 115.280 604.180 115.680 604.580 ;
    END
  END Tile_X0Y3_EE4BEG[8]
  PIN Tile_X0Y3_EE4BEG[9]
    DIRECTION OUTPUT ;
    USE SIGNAL ;
    ANTENNADIFFAREA 2.724000 ;
    PORT
      LAYER Metal3 ;
        RECT 115.280 605.860 115.680 606.260 ;
    END
  END Tile_X0Y3_EE4BEG[9]
  PIN Tile_X0Y3_FrameData[0]
    DIRECTION INPUT ;
    USE SIGNAL ;
    ANTENNAGATEAREA 1.445600 ;
    PORT
      LAYER Metal3 ;
        RECT 0.000 567.220 0.400 567.620 ;
    END
  END Tile_X0Y3_FrameData[0]
  PIN Tile_X0Y3_FrameData[10]
    DIRECTION INPUT ;
    USE SIGNAL ;
    ANTENNAGATEAREA 1.445600 ;
    PORT
      LAYER Metal3 ;
        RECT 0.000 642.820 0.400 643.220 ;
    END
  END Tile_X0Y3_FrameData[10]
  PIN Tile_X0Y3_FrameData[11]
    DIRECTION INPUT ;
    USE SIGNAL ;
    ANTENNAGATEAREA 1.445600 ;
    PORT
      LAYER Metal3 ;
        RECT 0.000 650.380 0.400 650.780 ;
    END
  END Tile_X0Y3_FrameData[11]
  PIN Tile_X0Y3_FrameData[12]
    DIRECTION INPUT ;
    USE SIGNAL ;
    ANTENNAGATEAREA 1.445600 ;
    PORT
      LAYER Metal3 ;
        RECT 0.000 657.940 0.400 658.340 ;
    END
  END Tile_X0Y3_FrameData[12]
  PIN Tile_X0Y3_FrameData[13]
    DIRECTION INPUT ;
    USE SIGNAL ;
    ANTENNAGATEAREA 1.445600 ;
    PORT
      LAYER Metal3 ;
        RECT 0.000 665.500 0.400 665.900 ;
    END
  END Tile_X0Y3_FrameData[13]
  PIN Tile_X0Y3_FrameData[14]
    DIRECTION INPUT ;
    USE SIGNAL ;
    ANTENNAGATEAREA 1.445600 ;
    PORT
      LAYER Metal3 ;
        RECT 0.000 673.060 0.400 673.460 ;
    END
  END Tile_X0Y3_FrameData[14]
  PIN Tile_X0Y3_FrameData[15]
    DIRECTION INPUT ;
    USE SIGNAL ;
    ANTENNAGATEAREA 1.445600 ;
    PORT
      LAYER Metal3 ;
        RECT 0.000 680.620 0.400 681.020 ;
    END
  END Tile_X0Y3_FrameData[15]
  PIN Tile_X0Y3_FrameData[16]
    DIRECTION INPUT ;
    USE SIGNAL ;
    ANTENNAGATEAREA 1.626300 ;
    PORT
      LAYER Metal3 ;
        RECT 0.000 688.180 0.400 688.580 ;
    END
  END Tile_X0Y3_FrameData[16]
  PIN Tile_X0Y3_FrameData[17]
    DIRECTION INPUT ;
    USE SIGNAL ;
    ANTENNAGATEAREA 1.626300 ;
    PORT
      LAYER Metal3 ;
        RECT 0.000 695.740 0.400 696.140 ;
    END
  END Tile_X0Y3_FrameData[17]
  PIN Tile_X0Y3_FrameData[18]
    DIRECTION INPUT ;
    USE SIGNAL ;
    ANTENNAGATEAREA 1.626300 ;
    PORT
      LAYER Metal3 ;
        RECT 0.000 703.300 0.400 703.700 ;
    END
  END Tile_X0Y3_FrameData[18]
  PIN Tile_X0Y3_FrameData[19]
    DIRECTION INPUT ;
    USE SIGNAL ;
    ANTENNAGATEAREA 1.626300 ;
    PORT
      LAYER Metal3 ;
        RECT 0.000 710.860 0.400 711.260 ;
    END
  END Tile_X0Y3_FrameData[19]
  PIN Tile_X0Y3_FrameData[1]
    DIRECTION INPUT ;
    USE SIGNAL ;
    ANTENNAGATEAREA 1.445600 ;
    PORT
      LAYER Metal3 ;
        RECT 0.000 574.780 0.400 575.180 ;
    END
  END Tile_X0Y3_FrameData[1]
  PIN Tile_X0Y3_FrameData[20]
    DIRECTION INPUT ;
    USE SIGNAL ;
    ANTENNAGATEAREA 1.626300 ;
    PORT
      LAYER Metal3 ;
        RECT 0.000 718.420 0.400 718.820 ;
    END
  END Tile_X0Y3_FrameData[20]
  PIN Tile_X0Y3_FrameData[21]
    DIRECTION INPUT ;
    USE SIGNAL ;
    ANTENNAGATEAREA 1.626300 ;
    PORT
      LAYER Metal3 ;
        RECT 0.000 725.980 0.400 726.380 ;
    END
  END Tile_X0Y3_FrameData[21]
  PIN Tile_X0Y3_FrameData[22]
    DIRECTION INPUT ;
    USE SIGNAL ;
    ANTENNAGATEAREA 1.626300 ;
    PORT
      LAYER Metal3 ;
        RECT 0.000 733.540 0.400 733.940 ;
    END
  END Tile_X0Y3_FrameData[22]
  PIN Tile_X0Y3_FrameData[23]
    DIRECTION INPUT ;
    USE SIGNAL ;
    ANTENNAGATEAREA 1.626300 ;
    PORT
      LAYER Metal3 ;
        RECT 0.000 741.100 0.400 741.500 ;
    END
  END Tile_X0Y3_FrameData[23]
  PIN Tile_X0Y3_FrameData[24]
    DIRECTION INPUT ;
    USE SIGNAL ;
    ANTENNAGATEAREA 1.626300 ;
    PORT
      LAYER Metal3 ;
        RECT 0.000 748.660 0.400 749.060 ;
    END
  END Tile_X0Y3_FrameData[24]
  PIN Tile_X0Y3_FrameData[25]
    DIRECTION INPUT ;
    USE SIGNAL ;
    ANTENNAGATEAREA 1.626300 ;
    PORT
      LAYER Metal3 ;
        RECT 0.000 756.220 0.400 756.620 ;
    END
  END Tile_X0Y3_FrameData[25]
  PIN Tile_X0Y3_FrameData[26]
    DIRECTION INPUT ;
    USE SIGNAL ;
    ANTENNAGATEAREA 1.626300 ;
    PORT
      LAYER Metal3 ;
        RECT 0.000 763.780 0.400 764.180 ;
    END
  END Tile_X0Y3_FrameData[26]
  PIN Tile_X0Y3_FrameData[27]
    DIRECTION INPUT ;
    USE SIGNAL ;
    ANTENNAGATEAREA 1.626300 ;
    PORT
      LAYER Metal3 ;
        RECT 0.000 771.340 0.400 771.740 ;
    END
  END Tile_X0Y3_FrameData[27]
  PIN Tile_X0Y3_FrameData[28]
    DIRECTION INPUT ;
    USE SIGNAL ;
    ANTENNAGATEAREA 1.626300 ;
    PORT
      LAYER Metal3 ;
        RECT 0.000 778.900 0.400 779.300 ;
    END
  END Tile_X0Y3_FrameData[28]
  PIN Tile_X0Y3_FrameData[29]
    DIRECTION INPUT ;
    USE SIGNAL ;
    ANTENNAGATEAREA 1.626300 ;
    PORT
      LAYER Metal3 ;
        RECT 0.000 786.460 0.400 786.860 ;
    END
  END Tile_X0Y3_FrameData[29]
  PIN Tile_X0Y3_FrameData[2]
    DIRECTION INPUT ;
    USE SIGNAL ;
    ANTENNAGATEAREA 1.445600 ;
    PORT
      LAYER Metal3 ;
        RECT 0.000 582.340 0.400 582.740 ;
    END
  END Tile_X0Y3_FrameData[2]
  PIN Tile_X0Y3_FrameData[30]
    DIRECTION INPUT ;
    USE SIGNAL ;
    ANTENNAGATEAREA 1.626300 ;
    PORT
      LAYER Metal3 ;
        RECT 0.000 794.020 0.400 794.420 ;
    END
  END Tile_X0Y3_FrameData[30]
  PIN Tile_X0Y3_FrameData[31]
    DIRECTION INPUT ;
    USE SIGNAL ;
    ANTENNAGATEAREA 1.626300 ;
    PORT
      LAYER Metal3 ;
        RECT 0.000 801.580 0.400 801.980 ;
    END
  END Tile_X0Y3_FrameData[31]
  PIN Tile_X0Y3_FrameData[3]
    DIRECTION INPUT ;
    USE SIGNAL ;
    ANTENNAGATEAREA 1.445600 ;
    PORT
      LAYER Metal3 ;
        RECT 0.000 589.900 0.400 590.300 ;
    END
  END Tile_X0Y3_FrameData[3]
  PIN Tile_X0Y3_FrameData[4]
    DIRECTION INPUT ;
    USE SIGNAL ;
    ANTENNAGATEAREA 1.445600 ;
    PORT
      LAYER Metal3 ;
        RECT 0.000 597.460 0.400 597.860 ;
    END
  END Tile_X0Y3_FrameData[4]
  PIN Tile_X0Y3_FrameData[5]
    DIRECTION INPUT ;
    USE SIGNAL ;
    ANTENNAGATEAREA 1.445600 ;
    PORT
      LAYER Metal3 ;
        RECT 0.000 605.020 0.400 605.420 ;
    END
  END Tile_X0Y3_FrameData[5]
  PIN Tile_X0Y3_FrameData[6]
    DIRECTION INPUT ;
    USE SIGNAL ;
    ANTENNAGATEAREA 1.445600 ;
    PORT
      LAYER Metal3 ;
        RECT 0.000 612.580 0.400 612.980 ;
    END
  END Tile_X0Y3_FrameData[6]
  PIN Tile_X0Y3_FrameData[7]
    DIRECTION INPUT ;
    USE SIGNAL ;
    ANTENNAGATEAREA 1.445600 ;
    PORT
      LAYER Metal3 ;
        RECT 0.000 620.140 0.400 620.540 ;
    END
  END Tile_X0Y3_FrameData[7]
  PIN Tile_X0Y3_FrameData[8]
    DIRECTION INPUT ;
    USE SIGNAL ;
    ANTENNAGATEAREA 1.445600 ;
    PORT
      LAYER Metal3 ;
        RECT 0.000 627.700 0.400 628.100 ;
    END
  END Tile_X0Y3_FrameData[8]
  PIN Tile_X0Y3_FrameData[9]
    DIRECTION INPUT ;
    USE SIGNAL ;
    ANTENNAGATEAREA 1.445600 ;
    PORT
      LAYER Metal3 ;
        RECT 0.000 635.260 0.400 635.660 ;
    END
  END Tile_X0Y3_FrameData[9]
  PIN Tile_X0Y3_FrameData_O[0]
    DIRECTION OUTPUT ;
    USE SIGNAL ;
    ANTENNADIFFAREA 2.724000 ;
    PORT
      LAYER Metal3 ;
        RECT 115.280 756.220 115.680 756.620 ;
    END
  END Tile_X0Y3_FrameData_O[0]
  PIN Tile_X0Y3_FrameData_O[10]
    DIRECTION OUTPUT ;
    USE SIGNAL ;
    ANTENNADIFFAREA 2.724000 ;
    PORT
      LAYER Metal3 ;
        RECT 115.280 773.020 115.680 773.420 ;
    END
  END Tile_X0Y3_FrameData_O[10]
  PIN Tile_X0Y3_FrameData_O[11]
    DIRECTION OUTPUT ;
    USE SIGNAL ;
    ANTENNADIFFAREA 2.724000 ;
    PORT
      LAYER Metal3 ;
        RECT 115.280 774.700 115.680 775.100 ;
    END
  END Tile_X0Y3_FrameData_O[11]
  PIN Tile_X0Y3_FrameData_O[12]
    DIRECTION OUTPUT ;
    USE SIGNAL ;
    ANTENNADIFFAREA 2.724000 ;
    PORT
      LAYER Metal3 ;
        RECT 115.280 776.380 115.680 776.780 ;
    END
  END Tile_X0Y3_FrameData_O[12]
  PIN Tile_X0Y3_FrameData_O[13]
    DIRECTION OUTPUT ;
    USE SIGNAL ;
    ANTENNADIFFAREA 2.724000 ;
    PORT
      LAYER Metal3 ;
        RECT 115.280 778.060 115.680 778.460 ;
    END
  END Tile_X0Y3_FrameData_O[13]
  PIN Tile_X0Y3_FrameData_O[14]
    DIRECTION OUTPUT ;
    USE SIGNAL ;
    ANTENNADIFFAREA 2.724000 ;
    PORT
      LAYER Metal3 ;
        RECT 115.280 779.740 115.680 780.140 ;
    END
  END Tile_X0Y3_FrameData_O[14]
  PIN Tile_X0Y3_FrameData_O[15]
    DIRECTION OUTPUT ;
    USE SIGNAL ;
    ANTENNADIFFAREA 2.724000 ;
    PORT
      LAYER Metal3 ;
        RECT 115.280 781.420 115.680 781.820 ;
    END
  END Tile_X0Y3_FrameData_O[15]
  PIN Tile_X0Y3_FrameData_O[16]
    DIRECTION OUTPUT ;
    USE SIGNAL ;
    ANTENNADIFFAREA 2.724000 ;
    PORT
      LAYER Metal3 ;
        RECT 115.280 783.100 115.680 783.500 ;
    END
  END Tile_X0Y3_FrameData_O[16]
  PIN Tile_X0Y3_FrameData_O[17]
    DIRECTION OUTPUT ;
    USE SIGNAL ;
    ANTENNADIFFAREA 2.724000 ;
    PORT
      LAYER Metal3 ;
        RECT 115.280 784.780 115.680 785.180 ;
    END
  END Tile_X0Y3_FrameData_O[17]
  PIN Tile_X0Y3_FrameData_O[18]
    DIRECTION OUTPUT ;
    USE SIGNAL ;
    ANTENNADIFFAREA 2.724000 ;
    PORT
      LAYER Metal3 ;
        RECT 115.280 786.460 115.680 786.860 ;
    END
  END Tile_X0Y3_FrameData_O[18]
  PIN Tile_X0Y3_FrameData_O[19]
    DIRECTION OUTPUT ;
    USE SIGNAL ;
    ANTENNADIFFAREA 2.724000 ;
    PORT
      LAYER Metal3 ;
        RECT 115.280 788.140 115.680 788.540 ;
    END
  END Tile_X0Y3_FrameData_O[19]
  PIN Tile_X0Y3_FrameData_O[1]
    DIRECTION OUTPUT ;
    USE SIGNAL ;
    ANTENNADIFFAREA 2.724000 ;
    PORT
      LAYER Metal3 ;
        RECT 115.280 757.900 115.680 758.300 ;
    END
  END Tile_X0Y3_FrameData_O[1]
  PIN Tile_X0Y3_FrameData_O[20]
    DIRECTION OUTPUT ;
    USE SIGNAL ;
    ANTENNADIFFAREA 2.724000 ;
    PORT
      LAYER Metal3 ;
        RECT 115.280 789.820 115.680 790.220 ;
    END
  END Tile_X0Y3_FrameData_O[20]
  PIN Tile_X0Y3_FrameData_O[21]
    DIRECTION OUTPUT ;
    USE SIGNAL ;
    ANTENNADIFFAREA 2.724000 ;
    PORT
      LAYER Metal3 ;
        RECT 115.280 791.500 115.680 791.900 ;
    END
  END Tile_X0Y3_FrameData_O[21]
  PIN Tile_X0Y3_FrameData_O[22]
    DIRECTION OUTPUT ;
    USE SIGNAL ;
    ANTENNADIFFAREA 2.724000 ;
    PORT
      LAYER Metal3 ;
        RECT 115.280 793.180 115.680 793.580 ;
    END
  END Tile_X0Y3_FrameData_O[22]
  PIN Tile_X0Y3_FrameData_O[23]
    DIRECTION OUTPUT ;
    USE SIGNAL ;
    ANTENNADIFFAREA 2.724000 ;
    PORT
      LAYER Metal3 ;
        RECT 115.280 794.860 115.680 795.260 ;
    END
  END Tile_X0Y3_FrameData_O[23]
  PIN Tile_X0Y3_FrameData_O[24]
    DIRECTION OUTPUT ;
    USE SIGNAL ;
    ANTENNADIFFAREA 2.724000 ;
    PORT
      LAYER Metal3 ;
        RECT 115.280 796.540 115.680 796.940 ;
    END
  END Tile_X0Y3_FrameData_O[24]
  PIN Tile_X0Y3_FrameData_O[25]
    DIRECTION OUTPUT ;
    USE SIGNAL ;
    ANTENNADIFFAREA 2.724000 ;
    PORT
      LAYER Metal3 ;
        RECT 115.280 798.220 115.680 798.620 ;
    END
  END Tile_X0Y3_FrameData_O[25]
  PIN Tile_X0Y3_FrameData_O[26]
    DIRECTION OUTPUT ;
    USE SIGNAL ;
    ANTENNADIFFAREA 2.724000 ;
    PORT
      LAYER Metal3 ;
        RECT 115.280 799.900 115.680 800.300 ;
    END
  END Tile_X0Y3_FrameData_O[26]
  PIN Tile_X0Y3_FrameData_O[27]
    DIRECTION OUTPUT ;
    USE SIGNAL ;
    ANTENNADIFFAREA 2.724000 ;
    PORT
      LAYER Metal3 ;
        RECT 115.280 801.580 115.680 801.980 ;
    END
  END Tile_X0Y3_FrameData_O[27]
  PIN Tile_X0Y3_FrameData_O[28]
    DIRECTION OUTPUT ;
    USE SIGNAL ;
    ANTENNADIFFAREA 2.724000 ;
    PORT
      LAYER Metal3 ;
        RECT 115.280 803.260 115.680 803.660 ;
    END
  END Tile_X0Y3_FrameData_O[28]
  PIN Tile_X0Y3_FrameData_O[29]
    DIRECTION OUTPUT ;
    USE SIGNAL ;
    ANTENNADIFFAREA 2.724000 ;
    PORT
      LAYER Metal3 ;
        RECT 115.280 804.940 115.680 805.340 ;
    END
  END Tile_X0Y3_FrameData_O[29]
  PIN Tile_X0Y3_FrameData_O[2]
    DIRECTION OUTPUT ;
    USE SIGNAL ;
    ANTENNADIFFAREA 2.724000 ;
    PORT
      LAYER Metal3 ;
        RECT 115.280 759.580 115.680 759.980 ;
    END
  END Tile_X0Y3_FrameData_O[2]
  PIN Tile_X0Y3_FrameData_O[30]
    DIRECTION OUTPUT ;
    USE SIGNAL ;
    ANTENNADIFFAREA 2.724000 ;
    PORT
      LAYER Metal3 ;
        RECT 115.280 806.620 115.680 807.020 ;
    END
  END Tile_X0Y3_FrameData_O[30]
  PIN Tile_X0Y3_FrameData_O[31]
    DIRECTION OUTPUT ;
    USE SIGNAL ;
    ANTENNADIFFAREA 2.724000 ;
    PORT
      LAYER Metal3 ;
        RECT 115.280 808.300 115.680 808.700 ;
    END
  END Tile_X0Y3_FrameData_O[31]
  PIN Tile_X0Y3_FrameData_O[3]
    DIRECTION OUTPUT ;
    USE SIGNAL ;
    ANTENNADIFFAREA 2.724000 ;
    PORT
      LAYER Metal3 ;
        RECT 115.280 761.260 115.680 761.660 ;
    END
  END Tile_X0Y3_FrameData_O[3]
  PIN Tile_X0Y3_FrameData_O[4]
    DIRECTION OUTPUT ;
    USE SIGNAL ;
    ANTENNADIFFAREA 2.724000 ;
    PORT
      LAYER Metal3 ;
        RECT 115.280 762.940 115.680 763.340 ;
    END
  END Tile_X0Y3_FrameData_O[4]
  PIN Tile_X0Y3_FrameData_O[5]
    DIRECTION OUTPUT ;
    USE SIGNAL ;
    ANTENNADIFFAREA 2.724000 ;
    PORT
      LAYER Metal3 ;
        RECT 115.280 764.620 115.680 765.020 ;
    END
  END Tile_X0Y3_FrameData_O[5]
  PIN Tile_X0Y3_FrameData_O[6]
    DIRECTION OUTPUT ;
    USE SIGNAL ;
    ANTENNADIFFAREA 2.724000 ;
    PORT
      LAYER Metal3 ;
        RECT 115.280 766.300 115.680 766.700 ;
    END
  END Tile_X0Y3_FrameData_O[6]
  PIN Tile_X0Y3_FrameData_O[7]
    DIRECTION OUTPUT ;
    USE SIGNAL ;
    ANTENNADIFFAREA 2.724000 ;
    PORT
      LAYER Metal3 ;
        RECT 115.280 767.980 115.680 768.380 ;
    END
  END Tile_X0Y3_FrameData_O[7]
  PIN Tile_X0Y3_FrameData_O[8]
    DIRECTION OUTPUT ;
    USE SIGNAL ;
    ANTENNADIFFAREA 2.724000 ;
    PORT
      LAYER Metal3 ;
        RECT 115.280 769.660 115.680 770.060 ;
    END
  END Tile_X0Y3_FrameData_O[8]
  PIN Tile_X0Y3_FrameData_O[9]
    DIRECTION OUTPUT ;
    USE SIGNAL ;
    ANTENNADIFFAREA 2.724000 ;
    PORT
      LAYER Metal3 ;
        RECT 115.280 771.340 115.680 771.740 ;
    END
  END Tile_X0Y3_FrameData_O[9]
  PIN Tile_X0Y3_UserCLK
    DIRECTION INPUT ;
    USE SIGNAL ;
    ANTENNAGATEAREA 0.180700 ;
    PORT
      LAYER Metal3 ;
        RECT 0.000 548.740 0.400 549.140 ;
    END
  END Tile_X0Y3_UserCLK
  PIN Tile_X0Y3_UserCLKo
    DIRECTION OUTPUT ;
    USE SIGNAL ;
    ANTENNADIFFAREA 2.724000 ;
    PORT
      LAYER Metal3 ;
        RECT 115.280 747.820 115.680 748.220 ;
    END
  END Tile_X0Y3_UserCLKo
  PIN Tile_X0Y3_W1END[0]
    DIRECTION INPUT ;
    USE SIGNAL ;
    ANTENNAGATEAREA 1.066000 ;
    PORT
      LAYER Metal3 ;
        RECT 115.280 647.020 115.680 647.420 ;
    END
  END Tile_X0Y3_W1END[0]
  PIN Tile_X0Y3_W1END[1]
    DIRECTION INPUT ;
    USE SIGNAL ;
    ANTENNAGATEAREA 1.066000 ;
    PORT
      LAYER Metal3 ;
        RECT 115.280 648.700 115.680 649.100 ;
    END
  END Tile_X0Y3_W1END[1]
  PIN Tile_X0Y3_W1END[2]
    DIRECTION INPUT ;
    USE SIGNAL ;
    ANTENNAGATEAREA 1.066000 ;
    PORT
      LAYER Metal3 ;
        RECT 115.280 650.380 115.680 650.780 ;
    END
  END Tile_X0Y3_W1END[2]
  PIN Tile_X0Y3_W1END[3]
    DIRECTION INPUT ;
    USE SIGNAL ;
    ANTENNAGATEAREA 1.066000 ;
    PORT
      LAYER Metal3 ;
        RECT 115.280 652.060 115.680 652.460 ;
    END
  END Tile_X0Y3_W1END[3]
  PIN Tile_X0Y3_W2END[0]
    DIRECTION INPUT ;
    USE SIGNAL ;
    ANTENNAGATEAREA 0.639600 ;
    PORT
      LAYER Metal3 ;
        RECT 115.280 673.060 115.680 673.460 ;
    END
  END Tile_X0Y3_W2END[0]
  PIN Tile_X0Y3_W2END[1]
    DIRECTION INPUT ;
    USE SIGNAL ;
    ANTENNAGATEAREA 0.639600 ;
    PORT
      LAYER Metal3 ;
        RECT 115.280 674.740 115.680 675.140 ;
    END
  END Tile_X0Y3_W2END[1]
  PIN Tile_X0Y3_W2END[2]
    DIRECTION INPUT ;
    USE SIGNAL ;
    ANTENNAGATEAREA 0.639600 ;
    PORT
      LAYER Metal3 ;
        RECT 115.280 676.420 115.680 676.820 ;
    END
  END Tile_X0Y3_W2END[2]
  PIN Tile_X0Y3_W2END[3]
    DIRECTION INPUT ;
    USE SIGNAL ;
    ANTENNAGATEAREA 0.639600 ;
    PORT
      LAYER Metal3 ;
        RECT 115.280 678.100 115.680 678.500 ;
    END
  END Tile_X0Y3_W2END[3]
  PIN Tile_X0Y3_W2END[4]
    DIRECTION INPUT ;
    USE SIGNAL ;
    ANTENNAGATEAREA 0.639600 ;
    PORT
      LAYER Metal3 ;
        RECT 115.280 679.780 115.680 680.180 ;
    END
  END Tile_X0Y3_W2END[4]
  PIN Tile_X0Y3_W2END[5]
    DIRECTION INPUT ;
    USE SIGNAL ;
    ANTENNAGATEAREA 0.639600 ;
    PORT
      LAYER Metal3 ;
        RECT 115.280 681.460 115.680 681.860 ;
    END
  END Tile_X0Y3_W2END[5]
  PIN Tile_X0Y3_W2END[6]
    DIRECTION INPUT ;
    USE SIGNAL ;
    ANTENNAGATEAREA 0.639600 ;
    PORT
      LAYER Metal3 ;
        RECT 115.280 683.140 115.680 683.540 ;
    END
  END Tile_X0Y3_W2END[6]
  PIN Tile_X0Y3_W2END[7]
    DIRECTION INPUT ;
    USE SIGNAL ;
    ANTENNAGATEAREA 0.639600 ;
    PORT
      LAYER Metal3 ;
        RECT 115.280 684.820 115.680 685.220 ;
    END
  END Tile_X0Y3_W2END[7]
  PIN Tile_X0Y3_W2MID[0]
    DIRECTION INPUT ;
    USE SIGNAL ;
    ANTENNAGATEAREA 0.639600 ;
    PORT
      LAYER Metal3 ;
        RECT 115.280 656.260 115.680 656.660 ;
    END
  END Tile_X0Y3_W2MID[0]
  PIN Tile_X0Y3_W2MID[1]
    DIRECTION INPUT ;
    USE SIGNAL ;
    ANTENNAGATEAREA 0.639600 ;
    PORT
      LAYER Metal3 ;
        RECT 115.280 657.940 115.680 658.340 ;
    END
  END Tile_X0Y3_W2MID[1]
  PIN Tile_X0Y3_W2MID[2]
    DIRECTION INPUT ;
    USE SIGNAL ;
    ANTENNAGATEAREA 0.639600 ;
    PORT
      LAYER Metal3 ;
        RECT 115.280 659.620 115.680 660.020 ;
    END
  END Tile_X0Y3_W2MID[2]
  PIN Tile_X0Y3_W2MID[3]
    DIRECTION INPUT ;
    USE SIGNAL ;
    ANTENNAGATEAREA 0.639600 ;
    PORT
      LAYER Metal3 ;
        RECT 115.280 661.300 115.680 661.700 ;
    END
  END Tile_X0Y3_W2MID[3]
  PIN Tile_X0Y3_W2MID[4]
    DIRECTION INPUT ;
    USE SIGNAL ;
    ANTENNAGATEAREA 0.639600 ;
    PORT
      LAYER Metal3 ;
        RECT 115.280 662.980 115.680 663.380 ;
    END
  END Tile_X0Y3_W2MID[4]
  PIN Tile_X0Y3_W2MID[5]
    DIRECTION INPUT ;
    USE SIGNAL ;
    ANTENNAGATEAREA 0.639600 ;
    PORT
      LAYER Metal3 ;
        RECT 115.280 664.660 115.680 665.060 ;
    END
  END Tile_X0Y3_W2MID[5]
  PIN Tile_X0Y3_W2MID[6]
    DIRECTION INPUT ;
    USE SIGNAL ;
    ANTENNAGATEAREA 0.639600 ;
    PORT
      LAYER Metal3 ;
        RECT 115.280 666.340 115.680 666.740 ;
    END
  END Tile_X0Y3_W2MID[6]
  PIN Tile_X0Y3_W2MID[7]
    DIRECTION INPUT ;
    USE SIGNAL ;
    ANTENNAGATEAREA 0.639600 ;
    PORT
      LAYER Metal3 ;
        RECT 115.280 668.020 115.680 668.420 ;
    END
  END Tile_X0Y3_W2MID[7]
  PIN Tile_X0Y3_W6END[0]
    DIRECTION INPUT ;
    USE SIGNAL ;
    ANTENNAGATEAREA 0.639600 ;
    PORT
      LAYER Metal3 ;
        RECT 115.280 724.300 115.680 724.700 ;
    END
  END Tile_X0Y3_W6END[0]
  PIN Tile_X0Y3_W6END[10]
    DIRECTION INPUT ;
    USE SIGNAL ;
    ANTENNAGATEAREA 0.639600 ;
    PORT
      LAYER Metal3 ;
        RECT 115.280 741.100 115.680 741.500 ;
    END
  END Tile_X0Y3_W6END[10]
  PIN Tile_X0Y3_W6END[11]
    DIRECTION INPUT ;
    USE SIGNAL ;
    ANTENNAGATEAREA 0.639600 ;
    PORT
      LAYER Metal3 ;
        RECT 115.280 742.780 115.680 743.180 ;
    END
  END Tile_X0Y3_W6END[11]
  PIN Tile_X0Y3_W6END[1]
    DIRECTION INPUT ;
    USE SIGNAL ;
    ANTENNAGATEAREA 0.639600 ;
    PORT
      LAYER Metal3 ;
        RECT 115.280 725.980 115.680 726.380 ;
    END
  END Tile_X0Y3_W6END[1]
  PIN Tile_X0Y3_W6END[2]
    DIRECTION INPUT ;
    USE SIGNAL ;
    ANTENNAGATEAREA 0.639600 ;
    PORT
      LAYER Metal3 ;
        RECT 115.280 727.660 115.680 728.060 ;
    END
  END Tile_X0Y3_W6END[2]
  PIN Tile_X0Y3_W6END[3]
    DIRECTION INPUT ;
    USE SIGNAL ;
    ANTENNAGATEAREA 0.639600 ;
    PORT
      LAYER Metal3 ;
        RECT 115.280 729.340 115.680 729.740 ;
    END
  END Tile_X0Y3_W6END[3]
  PIN Tile_X0Y3_W6END[4]
    DIRECTION INPUT ;
    USE SIGNAL ;
    ANTENNAGATEAREA 0.852800 ;
    PORT
      LAYER Metal3 ;
        RECT 115.280 731.020 115.680 731.420 ;
    END
  END Tile_X0Y3_W6END[4]
  PIN Tile_X0Y3_W6END[5]
    DIRECTION INPUT ;
    USE SIGNAL ;
    ANTENNAGATEAREA 0.852800 ;
    PORT
      LAYER Metal3 ;
        RECT 115.280 732.700 115.680 733.100 ;
    END
  END Tile_X0Y3_W6END[5]
  PIN Tile_X0Y3_W6END[6]
    DIRECTION INPUT ;
    USE SIGNAL ;
    ANTENNAGATEAREA 0.852800 ;
    PORT
      LAYER Metal3 ;
        RECT 115.280 734.380 115.680 734.780 ;
    END
  END Tile_X0Y3_W6END[6]
  PIN Tile_X0Y3_W6END[7]
    DIRECTION INPUT ;
    USE SIGNAL ;
    ANTENNAGATEAREA 0.852800 ;
    PORT
      LAYER Metal3 ;
        RECT 115.280 736.060 115.680 736.460 ;
    END
  END Tile_X0Y3_W6END[7]
  PIN Tile_X0Y3_W6END[8]
    DIRECTION INPUT ;
    USE SIGNAL ;
    ANTENNAGATEAREA 0.639600 ;
    PORT
      LAYER Metal3 ;
        RECT 115.280 737.740 115.680 738.140 ;
    END
  END Tile_X0Y3_W6END[8]
  PIN Tile_X0Y3_W6END[9]
    DIRECTION INPUT ;
    USE SIGNAL ;
    ANTENNAGATEAREA 0.639600 ;
    PORT
      LAYER Metal3 ;
        RECT 115.280 739.420 115.680 739.820 ;
    END
  END Tile_X0Y3_W6END[9]
  PIN Tile_X0Y3_WW4END[0]
    DIRECTION INPUT ;
    USE SIGNAL ;
    ANTENNAGATEAREA 0.213200 ;
    PORT
      LAYER Metal3 ;
        RECT 115.280 691.540 115.680 691.940 ;
    END
  END Tile_X0Y3_WW4END[0]
  PIN Tile_X0Y3_WW4END[10]
    DIRECTION INPUT ;
    USE SIGNAL ;
    ANTENNAGATEAREA 0.213200 ;
    PORT
      LAYER Metal3 ;
        RECT 115.280 708.340 115.680 708.740 ;
    END
  END Tile_X0Y3_WW4END[10]
  PIN Tile_X0Y3_WW4END[11]
    DIRECTION INPUT ;
    USE SIGNAL ;
    ANTENNAGATEAREA 0.213200 ;
    PORT
      LAYER Metal3 ;
        RECT 115.280 710.020 115.680 710.420 ;
    END
  END Tile_X0Y3_WW4END[11]
  PIN Tile_X0Y3_WW4END[12]
    DIRECTION INPUT ;
    USE SIGNAL ;
    ANTENNAGATEAREA 0.213200 ;
    PORT
      LAYER Metal3 ;
        RECT 115.280 711.700 115.680 712.100 ;
    END
  END Tile_X0Y3_WW4END[12]
  PIN Tile_X0Y3_WW4END[13]
    DIRECTION INPUT ;
    USE SIGNAL ;
    ANTENNAGATEAREA 0.213200 ;
    PORT
      LAYER Metal3 ;
        RECT 115.280 713.380 115.680 713.780 ;
    END
  END Tile_X0Y3_WW4END[13]
  PIN Tile_X0Y3_WW4END[14]
    DIRECTION INPUT ;
    USE SIGNAL ;
    ANTENNAGATEAREA 0.213200 ;
    PORT
      LAYER Metal3 ;
        RECT 115.280 715.060 115.680 715.460 ;
    END
  END Tile_X0Y3_WW4END[14]
  PIN Tile_X0Y3_WW4END[15]
    DIRECTION INPUT ;
    USE SIGNAL ;
    ANTENNAGATEAREA 0.213200 ;
    PORT
      LAYER Metal3 ;
        RECT 115.280 716.740 115.680 717.140 ;
    END
  END Tile_X0Y3_WW4END[15]
  PIN Tile_X0Y3_WW4END[1]
    DIRECTION INPUT ;
    USE SIGNAL ;
    ANTENNAGATEAREA 0.213200 ;
    PORT
      LAYER Metal3 ;
        RECT 115.280 693.220 115.680 693.620 ;
    END
  END Tile_X0Y3_WW4END[1]
  PIN Tile_X0Y3_WW4END[2]
    DIRECTION INPUT ;
    USE SIGNAL ;
    ANTENNAGATEAREA 0.213200 ;
    PORT
      LAYER Metal3 ;
        RECT 115.280 694.900 115.680 695.300 ;
    END
  END Tile_X0Y3_WW4END[2]
  PIN Tile_X0Y3_WW4END[3]
    DIRECTION INPUT ;
    USE SIGNAL ;
    ANTENNAGATEAREA 0.213200 ;
    PORT
      LAYER Metal3 ;
        RECT 115.280 696.580 115.680 696.980 ;
    END
  END Tile_X0Y3_WW4END[3]
  PIN Tile_X0Y3_WW4END[4]
    DIRECTION INPUT ;
    USE SIGNAL ;
    ANTENNAGATEAREA 0.213200 ;
    PORT
      LAYER Metal3 ;
        RECT 115.280 698.260 115.680 698.660 ;
    END
  END Tile_X0Y3_WW4END[4]
  PIN Tile_X0Y3_WW4END[5]
    DIRECTION INPUT ;
    USE SIGNAL ;
    ANTENNAGATEAREA 0.213200 ;
    PORT
      LAYER Metal3 ;
        RECT 115.280 699.940 115.680 700.340 ;
    END
  END Tile_X0Y3_WW4END[5]
  PIN Tile_X0Y3_WW4END[6]
    DIRECTION INPUT ;
    USE SIGNAL ;
    ANTENNAGATEAREA 0.213200 ;
    PORT
      LAYER Metal3 ;
        RECT 115.280 701.620 115.680 702.020 ;
    END
  END Tile_X0Y3_WW4END[6]
  PIN Tile_X0Y3_WW4END[7]
    DIRECTION INPUT ;
    USE SIGNAL ;
    ANTENNAGATEAREA 0.213200 ;
    PORT
      LAYER Metal3 ;
        RECT 115.280 703.300 115.680 703.700 ;
    END
  END Tile_X0Y3_WW4END[7]
  PIN Tile_X0Y3_WW4END[8]
    DIRECTION INPUT ;
    USE SIGNAL ;
    ANTENNAGATEAREA 0.213200 ;
    PORT
      LAYER Metal3 ;
        RECT 115.280 704.980 115.680 705.380 ;
    END
  END Tile_X0Y3_WW4END[8]
  PIN Tile_X0Y3_WW4END[9]
    DIRECTION INPUT ;
    USE SIGNAL ;
    ANTENNAGATEAREA 0.213200 ;
    PORT
      LAYER Metal3 ;
        RECT 115.280 706.660 115.680 707.060 ;
    END
  END Tile_X0Y3_WW4END[9]
  PIN Tile_X0Y4_E1BEG[0]
    DIRECTION OUTPUT ;
    USE SIGNAL ;
    ANTENNADIFFAREA 2.724000 ;
    PORT
      LAYER Metal3 ;
        RECT 115.280 274.060 115.680 274.460 ;
    END
  END Tile_X0Y4_E1BEG[0]
  PIN Tile_X0Y4_E1BEG[1]
    DIRECTION OUTPUT ;
    USE SIGNAL ;
    ANTENNADIFFAREA 2.724000 ;
    PORT
      LAYER Metal3 ;
        RECT 115.280 275.740 115.680 276.140 ;
    END
  END Tile_X0Y4_E1BEG[1]
  PIN Tile_X0Y4_E1BEG[2]
    DIRECTION OUTPUT ;
    USE SIGNAL ;
    ANTENNADIFFAREA 2.724000 ;
    PORT
      LAYER Metal3 ;
        RECT 115.280 277.420 115.680 277.820 ;
    END
  END Tile_X0Y4_E1BEG[2]
  PIN Tile_X0Y4_E1BEG[3]
    DIRECTION OUTPUT ;
    USE SIGNAL ;
    ANTENNADIFFAREA 2.724000 ;
    PORT
      LAYER Metal3 ;
        RECT 115.280 279.100 115.680 279.500 ;
    END
  END Tile_X0Y4_E1BEG[3]
  PIN Tile_X0Y4_E2BEG[0]
    DIRECTION OUTPUT ;
    USE SIGNAL ;
    ANTENNADIFFAREA 2.724000 ;
    PORT
      LAYER Metal3 ;
        RECT 115.280 283.300 115.680 283.700 ;
    END
  END Tile_X0Y4_E2BEG[0]
  PIN Tile_X0Y4_E2BEG[1]
    DIRECTION OUTPUT ;
    USE SIGNAL ;
    ANTENNADIFFAREA 2.724000 ;
    PORT
      LAYER Metal3 ;
        RECT 115.280 284.980 115.680 285.380 ;
    END
  END Tile_X0Y4_E2BEG[1]
  PIN Tile_X0Y4_E2BEG[2]
    DIRECTION OUTPUT ;
    USE SIGNAL ;
    ANTENNADIFFAREA 2.724000 ;
    PORT
      LAYER Metal3 ;
        RECT 115.280 286.660 115.680 287.060 ;
    END
  END Tile_X0Y4_E2BEG[2]
  PIN Tile_X0Y4_E2BEG[3]
    DIRECTION OUTPUT ;
    USE SIGNAL ;
    ANTENNADIFFAREA 2.724000 ;
    PORT
      LAYER Metal3 ;
        RECT 115.280 288.340 115.680 288.740 ;
    END
  END Tile_X0Y4_E2BEG[3]
  PIN Tile_X0Y4_E2BEG[4]
    DIRECTION OUTPUT ;
    USE SIGNAL ;
    ANTENNADIFFAREA 2.724000 ;
    PORT
      LAYER Metal3 ;
        RECT 115.280 290.020 115.680 290.420 ;
    END
  END Tile_X0Y4_E2BEG[4]
  PIN Tile_X0Y4_E2BEG[5]
    DIRECTION OUTPUT ;
    USE SIGNAL ;
    ANTENNADIFFAREA 2.724000 ;
    PORT
      LAYER Metal3 ;
        RECT 115.280 291.700 115.680 292.100 ;
    END
  END Tile_X0Y4_E2BEG[5]
  PIN Tile_X0Y4_E2BEG[6]
    DIRECTION OUTPUT ;
    USE SIGNAL ;
    ANTENNADIFFAREA 2.724000 ;
    PORT
      LAYER Metal3 ;
        RECT 115.280 293.380 115.680 293.780 ;
    END
  END Tile_X0Y4_E2BEG[6]
  PIN Tile_X0Y4_E2BEG[7]
    DIRECTION OUTPUT ;
    USE SIGNAL ;
    ANTENNADIFFAREA 2.724000 ;
    PORT
      LAYER Metal3 ;
        RECT 115.280 295.060 115.680 295.460 ;
    END
  END Tile_X0Y4_E2BEG[7]
  PIN Tile_X0Y4_E2BEGb[0]
    DIRECTION OUTPUT ;
    USE SIGNAL ;
    ANTENNADIFFAREA 2.724000 ;
    PORT
      LAYER Metal3 ;
        RECT 115.280 300.100 115.680 300.500 ;
    END
  END Tile_X0Y4_E2BEGb[0]
  PIN Tile_X0Y4_E2BEGb[1]
    DIRECTION OUTPUT ;
    USE SIGNAL ;
    ANTENNADIFFAREA 2.724000 ;
    PORT
      LAYER Metal3 ;
        RECT 115.280 301.780 115.680 302.180 ;
    END
  END Tile_X0Y4_E2BEGb[1]
  PIN Tile_X0Y4_E2BEGb[2]
    DIRECTION OUTPUT ;
    USE SIGNAL ;
    ANTENNADIFFAREA 2.724000 ;
    PORT
      LAYER Metal3 ;
        RECT 115.280 303.460 115.680 303.860 ;
    END
  END Tile_X0Y4_E2BEGb[2]
  PIN Tile_X0Y4_E2BEGb[3]
    DIRECTION OUTPUT ;
    USE SIGNAL ;
    ANTENNADIFFAREA 2.724000 ;
    PORT
      LAYER Metal3 ;
        RECT 115.280 305.140 115.680 305.540 ;
    END
  END Tile_X0Y4_E2BEGb[3]
  PIN Tile_X0Y4_E2BEGb[4]
    DIRECTION OUTPUT ;
    USE SIGNAL ;
    ANTENNADIFFAREA 2.724000 ;
    PORT
      LAYER Metal3 ;
        RECT 115.280 306.820 115.680 307.220 ;
    END
  END Tile_X0Y4_E2BEGb[4]
  PIN Tile_X0Y4_E2BEGb[5]
    DIRECTION OUTPUT ;
    USE SIGNAL ;
    ANTENNADIFFAREA 2.724000 ;
    PORT
      LAYER Metal3 ;
        RECT 115.280 308.500 115.680 308.900 ;
    END
  END Tile_X0Y4_E2BEGb[5]
  PIN Tile_X0Y4_E2BEGb[6]
    DIRECTION OUTPUT ;
    USE SIGNAL ;
    ANTENNADIFFAREA 2.724000 ;
    PORT
      LAYER Metal3 ;
        RECT 115.280 310.180 115.680 310.580 ;
    END
  END Tile_X0Y4_E2BEGb[6]
  PIN Tile_X0Y4_E2BEGb[7]
    DIRECTION OUTPUT ;
    USE SIGNAL ;
    ANTENNADIFFAREA 2.724000 ;
    PORT
      LAYER Metal3 ;
        RECT 115.280 311.860 115.680 312.260 ;
    END
  END Tile_X0Y4_E2BEGb[7]
  PIN Tile_X0Y4_E6BEG[0]
    DIRECTION OUTPUT ;
    USE SIGNAL ;
    ANTENNADIFFAREA 2.724000 ;
    PORT
      LAYER Metal3 ;
        RECT 115.280 351.340 115.680 351.740 ;
    END
  END Tile_X0Y4_E6BEG[0]
  PIN Tile_X0Y4_E6BEG[10]
    DIRECTION OUTPUT ;
    USE SIGNAL ;
    ANTENNADIFFAREA 2.724000 ;
    PORT
      LAYER Metal3 ;
        RECT 115.280 368.140 115.680 368.540 ;
    END
  END Tile_X0Y4_E6BEG[10]
  PIN Tile_X0Y4_E6BEG[11]
    DIRECTION OUTPUT ;
    USE SIGNAL ;
    ANTENNADIFFAREA 2.724000 ;
    PORT
      LAYER Metal3 ;
        RECT 115.280 369.820 115.680 370.220 ;
    END
  END Tile_X0Y4_E6BEG[11]
  PIN Tile_X0Y4_E6BEG[1]
    DIRECTION OUTPUT ;
    USE SIGNAL ;
    ANTENNADIFFAREA 2.724000 ;
    PORT
      LAYER Metal3 ;
        RECT 115.280 353.020 115.680 353.420 ;
    END
  END Tile_X0Y4_E6BEG[1]
  PIN Tile_X0Y4_E6BEG[2]
    DIRECTION OUTPUT ;
    USE SIGNAL ;
    ANTENNADIFFAREA 2.724000 ;
    PORT
      LAYER Metal3 ;
        RECT 115.280 354.700 115.680 355.100 ;
    END
  END Tile_X0Y4_E6BEG[2]
  PIN Tile_X0Y4_E6BEG[3]
    DIRECTION OUTPUT ;
    USE SIGNAL ;
    ANTENNADIFFAREA 2.724000 ;
    PORT
      LAYER Metal3 ;
        RECT 115.280 356.380 115.680 356.780 ;
    END
  END Tile_X0Y4_E6BEG[3]
  PIN Tile_X0Y4_E6BEG[4]
    DIRECTION OUTPUT ;
    USE SIGNAL ;
    ANTENNADIFFAREA 2.724000 ;
    PORT
      LAYER Metal3 ;
        RECT 115.280 358.060 115.680 358.460 ;
    END
  END Tile_X0Y4_E6BEG[4]
  PIN Tile_X0Y4_E6BEG[5]
    DIRECTION OUTPUT ;
    USE SIGNAL ;
    ANTENNADIFFAREA 2.724000 ;
    PORT
      LAYER Metal3 ;
        RECT 115.280 359.740 115.680 360.140 ;
    END
  END Tile_X0Y4_E6BEG[5]
  PIN Tile_X0Y4_E6BEG[6]
    DIRECTION OUTPUT ;
    USE SIGNAL ;
    ANTENNADIFFAREA 2.724000 ;
    PORT
      LAYER Metal3 ;
        RECT 115.280 361.420 115.680 361.820 ;
    END
  END Tile_X0Y4_E6BEG[6]
  PIN Tile_X0Y4_E6BEG[7]
    DIRECTION OUTPUT ;
    USE SIGNAL ;
    ANTENNADIFFAREA 2.724000 ;
    PORT
      LAYER Metal3 ;
        RECT 115.280 363.100 115.680 363.500 ;
    END
  END Tile_X0Y4_E6BEG[7]
  PIN Tile_X0Y4_E6BEG[8]
    DIRECTION OUTPUT ;
    USE SIGNAL ;
    ANTENNADIFFAREA 2.724000 ;
    PORT
      LAYER Metal3 ;
        RECT 115.280 364.780 115.680 365.180 ;
    END
  END Tile_X0Y4_E6BEG[8]
  PIN Tile_X0Y4_E6BEG[9]
    DIRECTION OUTPUT ;
    USE SIGNAL ;
    ANTENNADIFFAREA 2.724000 ;
    PORT
      LAYER Metal3 ;
        RECT 115.280 366.460 115.680 366.860 ;
    END
  END Tile_X0Y4_E6BEG[9]
  PIN Tile_X0Y4_EE4BEG[0]
    DIRECTION OUTPUT ;
    USE SIGNAL ;
    ANTENNADIFFAREA 2.724000 ;
    PORT
      LAYER Metal3 ;
        RECT 115.280 318.580 115.680 318.980 ;
    END
  END Tile_X0Y4_EE4BEG[0]
  PIN Tile_X0Y4_EE4BEG[10]
    DIRECTION OUTPUT ;
    USE SIGNAL ;
    ANTENNADIFFAREA 2.724000 ;
    PORT
      LAYER Metal3 ;
        RECT 115.280 335.380 115.680 335.780 ;
    END
  END Tile_X0Y4_EE4BEG[10]
  PIN Tile_X0Y4_EE4BEG[11]
    DIRECTION OUTPUT ;
    USE SIGNAL ;
    ANTENNADIFFAREA 2.724000 ;
    PORT
      LAYER Metal3 ;
        RECT 115.280 337.060 115.680 337.460 ;
    END
  END Tile_X0Y4_EE4BEG[11]
  PIN Tile_X0Y4_EE4BEG[12]
    DIRECTION OUTPUT ;
    USE SIGNAL ;
    ANTENNADIFFAREA 2.724000 ;
    PORT
      LAYER Metal3 ;
        RECT 115.280 338.740 115.680 339.140 ;
    END
  END Tile_X0Y4_EE4BEG[12]
  PIN Tile_X0Y4_EE4BEG[13]
    DIRECTION OUTPUT ;
    USE SIGNAL ;
    ANTENNADIFFAREA 2.724000 ;
    PORT
      LAYER Metal3 ;
        RECT 115.280 340.420 115.680 340.820 ;
    END
  END Tile_X0Y4_EE4BEG[13]
  PIN Tile_X0Y4_EE4BEG[14]
    DIRECTION OUTPUT ;
    USE SIGNAL ;
    ANTENNADIFFAREA 2.724000 ;
    PORT
      LAYER Metal3 ;
        RECT 115.280 342.100 115.680 342.500 ;
    END
  END Tile_X0Y4_EE4BEG[14]
  PIN Tile_X0Y4_EE4BEG[15]
    DIRECTION OUTPUT ;
    USE SIGNAL ;
    ANTENNADIFFAREA 2.724000 ;
    PORT
      LAYER Metal3 ;
        RECT 115.280 343.780 115.680 344.180 ;
    END
  END Tile_X0Y4_EE4BEG[15]
  PIN Tile_X0Y4_EE4BEG[1]
    DIRECTION OUTPUT ;
    USE SIGNAL ;
    ANTENNADIFFAREA 2.724000 ;
    PORT
      LAYER Metal3 ;
        RECT 115.280 320.260 115.680 320.660 ;
    END
  END Tile_X0Y4_EE4BEG[1]
  PIN Tile_X0Y4_EE4BEG[2]
    DIRECTION OUTPUT ;
    USE SIGNAL ;
    ANTENNADIFFAREA 2.724000 ;
    PORT
      LAYER Metal3 ;
        RECT 115.280 321.940 115.680 322.340 ;
    END
  END Tile_X0Y4_EE4BEG[2]
  PIN Tile_X0Y4_EE4BEG[3]
    DIRECTION OUTPUT ;
    USE SIGNAL ;
    ANTENNADIFFAREA 2.724000 ;
    PORT
      LAYER Metal3 ;
        RECT 115.280 323.620 115.680 324.020 ;
    END
  END Tile_X0Y4_EE4BEG[3]
  PIN Tile_X0Y4_EE4BEG[4]
    DIRECTION OUTPUT ;
    USE SIGNAL ;
    ANTENNADIFFAREA 2.724000 ;
    PORT
      LAYER Metal3 ;
        RECT 115.280 325.300 115.680 325.700 ;
    END
  END Tile_X0Y4_EE4BEG[4]
  PIN Tile_X0Y4_EE4BEG[5]
    DIRECTION OUTPUT ;
    USE SIGNAL ;
    ANTENNADIFFAREA 2.724000 ;
    PORT
      LAYER Metal3 ;
        RECT 115.280 326.980 115.680 327.380 ;
    END
  END Tile_X0Y4_EE4BEG[5]
  PIN Tile_X0Y4_EE4BEG[6]
    DIRECTION OUTPUT ;
    USE SIGNAL ;
    ANTENNADIFFAREA 2.724000 ;
    PORT
      LAYER Metal3 ;
        RECT 115.280 328.660 115.680 329.060 ;
    END
  END Tile_X0Y4_EE4BEG[6]
  PIN Tile_X0Y4_EE4BEG[7]
    DIRECTION OUTPUT ;
    USE SIGNAL ;
    ANTENNADIFFAREA 2.724000 ;
    PORT
      LAYER Metal3 ;
        RECT 115.280 330.340 115.680 330.740 ;
    END
  END Tile_X0Y4_EE4BEG[7]
  PIN Tile_X0Y4_EE4BEG[8]
    DIRECTION OUTPUT ;
    USE SIGNAL ;
    ANTENNADIFFAREA 2.724000 ;
    PORT
      LAYER Metal3 ;
        RECT 115.280 332.020 115.680 332.420 ;
    END
  END Tile_X0Y4_EE4BEG[8]
  PIN Tile_X0Y4_EE4BEG[9]
    DIRECTION OUTPUT ;
    USE SIGNAL ;
    ANTENNADIFFAREA 2.724000 ;
    PORT
      LAYER Metal3 ;
        RECT 115.280 333.700 115.680 334.100 ;
    END
  END Tile_X0Y4_EE4BEG[9]
  PIN Tile_X0Y4_FrameData[0]
    DIRECTION INPUT ;
    USE SIGNAL ;
    ANTENNAGATEAREA 1.445600 ;
    PORT
      LAYER Metal3 ;
        RECT 0.000 295.060 0.400 295.460 ;
    END
  END Tile_X0Y4_FrameData[0]
  PIN Tile_X0Y4_FrameData[10]
    DIRECTION INPUT ;
    USE SIGNAL ;
    ANTENNAGATEAREA 1.445600 ;
    PORT
      LAYER Metal3 ;
        RECT 0.000 370.660 0.400 371.060 ;
    END
  END Tile_X0Y4_FrameData[10]
  PIN Tile_X0Y4_FrameData[11]
    DIRECTION INPUT ;
    USE SIGNAL ;
    ANTENNAGATEAREA 1.445600 ;
    PORT
      LAYER Metal3 ;
        RECT 0.000 378.220 0.400 378.620 ;
    END
  END Tile_X0Y4_FrameData[11]
  PIN Tile_X0Y4_FrameData[12]
    DIRECTION INPUT ;
    USE SIGNAL ;
    ANTENNAGATEAREA 1.445600 ;
    PORT
      LAYER Metal3 ;
        RECT 0.000 385.780 0.400 386.180 ;
    END
  END Tile_X0Y4_FrameData[12]
  PIN Tile_X0Y4_FrameData[13]
    DIRECTION INPUT ;
    USE SIGNAL ;
    ANTENNAGATEAREA 1.445600 ;
    PORT
      LAYER Metal3 ;
        RECT 0.000 393.340 0.400 393.740 ;
    END
  END Tile_X0Y4_FrameData[13]
  PIN Tile_X0Y4_FrameData[14]
    DIRECTION INPUT ;
    USE SIGNAL ;
    ANTENNAGATEAREA 1.445600 ;
    PORT
      LAYER Metal3 ;
        RECT 0.000 400.900 0.400 401.300 ;
    END
  END Tile_X0Y4_FrameData[14]
  PIN Tile_X0Y4_FrameData[15]
    DIRECTION INPUT ;
    USE SIGNAL ;
    ANTENNAGATEAREA 1.445600 ;
    PORT
      LAYER Metal3 ;
        RECT 0.000 408.460 0.400 408.860 ;
    END
  END Tile_X0Y4_FrameData[15]
  PIN Tile_X0Y4_FrameData[16]
    DIRECTION INPUT ;
    USE SIGNAL ;
    ANTENNAGATEAREA 1.445600 ;
    PORT
      LAYER Metal3 ;
        RECT 0.000 416.020 0.400 416.420 ;
    END
  END Tile_X0Y4_FrameData[16]
  PIN Tile_X0Y4_FrameData[17]
    DIRECTION INPUT ;
    USE SIGNAL ;
    ANTENNAGATEAREA 1.445600 ;
    PORT
      LAYER Metal3 ;
        RECT 0.000 423.580 0.400 423.980 ;
    END
  END Tile_X0Y4_FrameData[17]
  PIN Tile_X0Y4_FrameData[18]
    DIRECTION INPUT ;
    USE SIGNAL ;
    ANTENNAGATEAREA 1.445600 ;
    PORT
      LAYER Metal3 ;
        RECT 0.000 431.140 0.400 431.540 ;
    END
  END Tile_X0Y4_FrameData[18]
  PIN Tile_X0Y4_FrameData[19]
    DIRECTION INPUT ;
    USE SIGNAL ;
    ANTENNAGATEAREA 1.445600 ;
    PORT
      LAYER Metal3 ;
        RECT 0.000 438.700 0.400 439.100 ;
    END
  END Tile_X0Y4_FrameData[19]
  PIN Tile_X0Y4_FrameData[1]
    DIRECTION INPUT ;
    USE SIGNAL ;
    ANTENNAGATEAREA 1.445600 ;
    PORT
      LAYER Metal3 ;
        RECT 0.000 302.620 0.400 303.020 ;
    END
  END Tile_X0Y4_FrameData[1]
  PIN Tile_X0Y4_FrameData[20]
    DIRECTION INPUT ;
    USE SIGNAL ;
    ANTENNAGATEAREA 1.445600 ;
    PORT
      LAYER Metal3 ;
        RECT 0.000 446.260 0.400 446.660 ;
    END
  END Tile_X0Y4_FrameData[20]
  PIN Tile_X0Y4_FrameData[21]
    DIRECTION INPUT ;
    USE SIGNAL ;
    ANTENNAGATEAREA 1.445600 ;
    PORT
      LAYER Metal3 ;
        RECT 0.000 453.820 0.400 454.220 ;
    END
  END Tile_X0Y4_FrameData[21]
  PIN Tile_X0Y4_FrameData[22]
    DIRECTION INPUT ;
    USE SIGNAL ;
    ANTENNAGATEAREA 1.626300 ;
    PORT
      LAYER Metal3 ;
        RECT 0.000 461.380 0.400 461.780 ;
    END
  END Tile_X0Y4_FrameData[22]
  PIN Tile_X0Y4_FrameData[23]
    DIRECTION INPUT ;
    USE SIGNAL ;
    ANTENNAGATEAREA 1.626300 ;
    PORT
      LAYER Metal3 ;
        RECT 0.000 468.940 0.400 469.340 ;
    END
  END Tile_X0Y4_FrameData[23]
  PIN Tile_X0Y4_FrameData[24]
    DIRECTION INPUT ;
    USE SIGNAL ;
    ANTENNAGATEAREA 1.626300 ;
    PORT
      LAYER Metal3 ;
        RECT 0.000 476.500 0.400 476.900 ;
    END
  END Tile_X0Y4_FrameData[24]
  PIN Tile_X0Y4_FrameData[25]
    DIRECTION INPUT ;
    USE SIGNAL ;
    ANTENNAGATEAREA 1.626300 ;
    PORT
      LAYER Metal3 ;
        RECT 0.000 484.060 0.400 484.460 ;
    END
  END Tile_X0Y4_FrameData[25]
  PIN Tile_X0Y4_FrameData[26]
    DIRECTION INPUT ;
    USE SIGNAL ;
    ANTENNAGATEAREA 1.626300 ;
    PORT
      LAYER Metal3 ;
        RECT 0.000 491.620 0.400 492.020 ;
    END
  END Tile_X0Y4_FrameData[26]
  PIN Tile_X0Y4_FrameData[27]
    DIRECTION INPUT ;
    USE SIGNAL ;
    ANTENNAGATEAREA 1.626300 ;
    PORT
      LAYER Metal3 ;
        RECT 0.000 499.180 0.400 499.580 ;
    END
  END Tile_X0Y4_FrameData[27]
  PIN Tile_X0Y4_FrameData[28]
    DIRECTION INPUT ;
    USE SIGNAL ;
    ANTENNAGATEAREA 1.626300 ;
    PORT
      LAYER Metal3 ;
        RECT 0.000 506.740 0.400 507.140 ;
    END
  END Tile_X0Y4_FrameData[28]
  PIN Tile_X0Y4_FrameData[29]
    DIRECTION INPUT ;
    USE SIGNAL ;
    ANTENNAGATEAREA 1.626300 ;
    PORT
      LAYER Metal3 ;
        RECT 0.000 514.300 0.400 514.700 ;
    END
  END Tile_X0Y4_FrameData[29]
  PIN Tile_X0Y4_FrameData[2]
    DIRECTION INPUT ;
    USE SIGNAL ;
    ANTENNAGATEAREA 1.445600 ;
    PORT
      LAYER Metal3 ;
        RECT 0.000 310.180 0.400 310.580 ;
    END
  END Tile_X0Y4_FrameData[2]
  PIN Tile_X0Y4_FrameData[30]
    DIRECTION INPUT ;
    USE SIGNAL ;
    ANTENNAGATEAREA 1.626300 ;
    PORT
      LAYER Metal3 ;
        RECT 0.000 521.860 0.400 522.260 ;
    END
  END Tile_X0Y4_FrameData[30]
  PIN Tile_X0Y4_FrameData[31]
    DIRECTION INPUT ;
    USE SIGNAL ;
    ANTENNAGATEAREA 1.626300 ;
    PORT
      LAYER Metal3 ;
        RECT 0.000 529.420 0.400 529.820 ;
    END
  END Tile_X0Y4_FrameData[31]
  PIN Tile_X0Y4_FrameData[3]
    DIRECTION INPUT ;
    USE SIGNAL ;
    ANTENNAGATEAREA 1.445600 ;
    PORT
      LAYER Metal3 ;
        RECT 0.000 317.740 0.400 318.140 ;
    END
  END Tile_X0Y4_FrameData[3]
  PIN Tile_X0Y4_FrameData[4]
    DIRECTION INPUT ;
    USE SIGNAL ;
    ANTENNAGATEAREA 1.445600 ;
    PORT
      LAYER Metal3 ;
        RECT 0.000 325.300 0.400 325.700 ;
    END
  END Tile_X0Y4_FrameData[4]
  PIN Tile_X0Y4_FrameData[5]
    DIRECTION INPUT ;
    USE SIGNAL ;
    ANTENNAGATEAREA 1.445600 ;
    PORT
      LAYER Metal3 ;
        RECT 0.000 332.860 0.400 333.260 ;
    END
  END Tile_X0Y4_FrameData[5]
  PIN Tile_X0Y4_FrameData[6]
    DIRECTION INPUT ;
    USE SIGNAL ;
    ANTENNAGATEAREA 1.445600 ;
    PORT
      LAYER Metal3 ;
        RECT 0.000 340.420 0.400 340.820 ;
    END
  END Tile_X0Y4_FrameData[6]
  PIN Tile_X0Y4_FrameData[7]
    DIRECTION INPUT ;
    USE SIGNAL ;
    ANTENNAGATEAREA 1.445600 ;
    PORT
      LAYER Metal3 ;
        RECT 0.000 347.980 0.400 348.380 ;
    END
  END Tile_X0Y4_FrameData[7]
  PIN Tile_X0Y4_FrameData[8]
    DIRECTION INPUT ;
    USE SIGNAL ;
    ANTENNAGATEAREA 1.445600 ;
    PORT
      LAYER Metal3 ;
        RECT 0.000 355.540 0.400 355.940 ;
    END
  END Tile_X0Y4_FrameData[8]
  PIN Tile_X0Y4_FrameData[9]
    DIRECTION INPUT ;
    USE SIGNAL ;
    ANTENNAGATEAREA 1.445600 ;
    PORT
      LAYER Metal3 ;
        RECT 0.000 363.100 0.400 363.500 ;
    END
  END Tile_X0Y4_FrameData[9]
  PIN Tile_X0Y4_FrameData_O[0]
    DIRECTION OUTPUT ;
    USE SIGNAL ;
    ANTENNADIFFAREA 2.724000 ;
    PORT
      LAYER Metal3 ;
        RECT 115.280 484.060 115.680 484.460 ;
    END
  END Tile_X0Y4_FrameData_O[0]
  PIN Tile_X0Y4_FrameData_O[10]
    DIRECTION OUTPUT ;
    USE SIGNAL ;
    ANTENNADIFFAREA 2.724000 ;
    PORT
      LAYER Metal3 ;
        RECT 115.280 500.860 115.680 501.260 ;
    END
  END Tile_X0Y4_FrameData_O[10]
  PIN Tile_X0Y4_FrameData_O[11]
    DIRECTION OUTPUT ;
    USE SIGNAL ;
    ANTENNADIFFAREA 2.724000 ;
    PORT
      LAYER Metal3 ;
        RECT 115.280 502.540 115.680 502.940 ;
    END
  END Tile_X0Y4_FrameData_O[11]
  PIN Tile_X0Y4_FrameData_O[12]
    DIRECTION OUTPUT ;
    USE SIGNAL ;
    ANTENNADIFFAREA 2.724000 ;
    PORT
      LAYER Metal3 ;
        RECT 115.280 504.220 115.680 504.620 ;
    END
  END Tile_X0Y4_FrameData_O[12]
  PIN Tile_X0Y4_FrameData_O[13]
    DIRECTION OUTPUT ;
    USE SIGNAL ;
    ANTENNADIFFAREA 2.724000 ;
    PORT
      LAYER Metal3 ;
        RECT 115.280 505.900 115.680 506.300 ;
    END
  END Tile_X0Y4_FrameData_O[13]
  PIN Tile_X0Y4_FrameData_O[14]
    DIRECTION OUTPUT ;
    USE SIGNAL ;
    ANTENNADIFFAREA 2.724000 ;
    PORT
      LAYER Metal3 ;
        RECT 115.280 507.580 115.680 507.980 ;
    END
  END Tile_X0Y4_FrameData_O[14]
  PIN Tile_X0Y4_FrameData_O[15]
    DIRECTION OUTPUT ;
    USE SIGNAL ;
    ANTENNADIFFAREA 2.724000 ;
    PORT
      LAYER Metal3 ;
        RECT 115.280 509.260 115.680 509.660 ;
    END
  END Tile_X0Y4_FrameData_O[15]
  PIN Tile_X0Y4_FrameData_O[16]
    DIRECTION OUTPUT ;
    USE SIGNAL ;
    ANTENNADIFFAREA 2.724000 ;
    PORT
      LAYER Metal3 ;
        RECT 115.280 510.940 115.680 511.340 ;
    END
  END Tile_X0Y4_FrameData_O[16]
  PIN Tile_X0Y4_FrameData_O[17]
    DIRECTION OUTPUT ;
    USE SIGNAL ;
    ANTENNADIFFAREA 2.724000 ;
    PORT
      LAYER Metal3 ;
        RECT 115.280 512.620 115.680 513.020 ;
    END
  END Tile_X0Y4_FrameData_O[17]
  PIN Tile_X0Y4_FrameData_O[18]
    DIRECTION OUTPUT ;
    USE SIGNAL ;
    ANTENNADIFFAREA 2.724000 ;
    PORT
      LAYER Metal3 ;
        RECT 115.280 514.300 115.680 514.700 ;
    END
  END Tile_X0Y4_FrameData_O[18]
  PIN Tile_X0Y4_FrameData_O[19]
    DIRECTION OUTPUT ;
    USE SIGNAL ;
    ANTENNADIFFAREA 2.724000 ;
    PORT
      LAYER Metal3 ;
        RECT 115.280 515.980 115.680 516.380 ;
    END
  END Tile_X0Y4_FrameData_O[19]
  PIN Tile_X0Y4_FrameData_O[1]
    DIRECTION OUTPUT ;
    USE SIGNAL ;
    ANTENNADIFFAREA 2.724000 ;
    PORT
      LAYER Metal3 ;
        RECT 115.280 485.740 115.680 486.140 ;
    END
  END Tile_X0Y4_FrameData_O[1]
  PIN Tile_X0Y4_FrameData_O[20]
    DIRECTION OUTPUT ;
    USE SIGNAL ;
    ANTENNADIFFAREA 2.724000 ;
    PORT
      LAYER Metal3 ;
        RECT 115.280 517.660 115.680 518.060 ;
    END
  END Tile_X0Y4_FrameData_O[20]
  PIN Tile_X0Y4_FrameData_O[21]
    DIRECTION OUTPUT ;
    USE SIGNAL ;
    ANTENNADIFFAREA 2.724000 ;
    PORT
      LAYER Metal3 ;
        RECT 115.280 519.340 115.680 519.740 ;
    END
  END Tile_X0Y4_FrameData_O[21]
  PIN Tile_X0Y4_FrameData_O[22]
    DIRECTION OUTPUT ;
    USE SIGNAL ;
    ANTENNADIFFAREA 2.724000 ;
    PORT
      LAYER Metal3 ;
        RECT 115.280 521.020 115.680 521.420 ;
    END
  END Tile_X0Y4_FrameData_O[22]
  PIN Tile_X0Y4_FrameData_O[23]
    DIRECTION OUTPUT ;
    USE SIGNAL ;
    ANTENNADIFFAREA 2.724000 ;
    PORT
      LAYER Metal3 ;
        RECT 115.280 522.700 115.680 523.100 ;
    END
  END Tile_X0Y4_FrameData_O[23]
  PIN Tile_X0Y4_FrameData_O[24]
    DIRECTION OUTPUT ;
    USE SIGNAL ;
    ANTENNADIFFAREA 2.724000 ;
    PORT
      LAYER Metal3 ;
        RECT 115.280 524.380 115.680 524.780 ;
    END
  END Tile_X0Y4_FrameData_O[24]
  PIN Tile_X0Y4_FrameData_O[25]
    DIRECTION OUTPUT ;
    USE SIGNAL ;
    ANTENNADIFFAREA 2.724000 ;
    PORT
      LAYER Metal3 ;
        RECT 115.280 526.060 115.680 526.460 ;
    END
  END Tile_X0Y4_FrameData_O[25]
  PIN Tile_X0Y4_FrameData_O[26]
    DIRECTION OUTPUT ;
    USE SIGNAL ;
    ANTENNADIFFAREA 2.724000 ;
    PORT
      LAYER Metal3 ;
        RECT 115.280 527.740 115.680 528.140 ;
    END
  END Tile_X0Y4_FrameData_O[26]
  PIN Tile_X0Y4_FrameData_O[27]
    DIRECTION OUTPUT ;
    USE SIGNAL ;
    ANTENNADIFFAREA 2.724000 ;
    PORT
      LAYER Metal3 ;
        RECT 115.280 529.420 115.680 529.820 ;
    END
  END Tile_X0Y4_FrameData_O[27]
  PIN Tile_X0Y4_FrameData_O[28]
    DIRECTION OUTPUT ;
    USE SIGNAL ;
    ANTENNADIFFAREA 2.724000 ;
    PORT
      LAYER Metal3 ;
        RECT 115.280 531.100 115.680 531.500 ;
    END
  END Tile_X0Y4_FrameData_O[28]
  PIN Tile_X0Y4_FrameData_O[29]
    DIRECTION OUTPUT ;
    USE SIGNAL ;
    ANTENNADIFFAREA 2.724000 ;
    PORT
      LAYER Metal3 ;
        RECT 115.280 532.780 115.680 533.180 ;
    END
  END Tile_X0Y4_FrameData_O[29]
  PIN Tile_X0Y4_FrameData_O[2]
    DIRECTION OUTPUT ;
    USE SIGNAL ;
    ANTENNADIFFAREA 2.724000 ;
    PORT
      LAYER Metal3 ;
        RECT 115.280 487.420 115.680 487.820 ;
    END
  END Tile_X0Y4_FrameData_O[2]
  PIN Tile_X0Y4_FrameData_O[30]
    DIRECTION OUTPUT ;
    USE SIGNAL ;
    ANTENNADIFFAREA 2.724000 ;
    PORT
      LAYER Metal3 ;
        RECT 115.280 534.460 115.680 534.860 ;
    END
  END Tile_X0Y4_FrameData_O[30]
  PIN Tile_X0Y4_FrameData_O[31]
    DIRECTION OUTPUT ;
    USE SIGNAL ;
    ANTENNADIFFAREA 2.724000 ;
    PORT
      LAYER Metal3 ;
        RECT 115.280 536.140 115.680 536.540 ;
    END
  END Tile_X0Y4_FrameData_O[31]
  PIN Tile_X0Y4_FrameData_O[3]
    DIRECTION OUTPUT ;
    USE SIGNAL ;
    ANTENNADIFFAREA 2.724000 ;
    PORT
      LAYER Metal3 ;
        RECT 115.280 489.100 115.680 489.500 ;
    END
  END Tile_X0Y4_FrameData_O[3]
  PIN Tile_X0Y4_FrameData_O[4]
    DIRECTION OUTPUT ;
    USE SIGNAL ;
    ANTENNADIFFAREA 2.724000 ;
    PORT
      LAYER Metal3 ;
        RECT 115.280 490.780 115.680 491.180 ;
    END
  END Tile_X0Y4_FrameData_O[4]
  PIN Tile_X0Y4_FrameData_O[5]
    DIRECTION OUTPUT ;
    USE SIGNAL ;
    ANTENNADIFFAREA 2.724000 ;
    PORT
      LAYER Metal3 ;
        RECT 115.280 492.460 115.680 492.860 ;
    END
  END Tile_X0Y4_FrameData_O[5]
  PIN Tile_X0Y4_FrameData_O[6]
    DIRECTION OUTPUT ;
    USE SIGNAL ;
    ANTENNADIFFAREA 2.724000 ;
    PORT
      LAYER Metal3 ;
        RECT 115.280 494.140 115.680 494.540 ;
    END
  END Tile_X0Y4_FrameData_O[6]
  PIN Tile_X0Y4_FrameData_O[7]
    DIRECTION OUTPUT ;
    USE SIGNAL ;
    ANTENNADIFFAREA 2.724000 ;
    PORT
      LAYER Metal3 ;
        RECT 115.280 495.820 115.680 496.220 ;
    END
  END Tile_X0Y4_FrameData_O[7]
  PIN Tile_X0Y4_FrameData_O[8]
    DIRECTION OUTPUT ;
    USE SIGNAL ;
    ANTENNADIFFAREA 2.724000 ;
    PORT
      LAYER Metal3 ;
        RECT 115.280 497.500 115.680 497.900 ;
    END
  END Tile_X0Y4_FrameData_O[8]
  PIN Tile_X0Y4_FrameData_O[9]
    DIRECTION OUTPUT ;
    USE SIGNAL ;
    ANTENNADIFFAREA 2.724000 ;
    PORT
      LAYER Metal3 ;
        RECT 115.280 499.180 115.680 499.580 ;
    END
  END Tile_X0Y4_FrameData_O[9]
  PIN Tile_X0Y4_UserCLK
    DIRECTION INPUT ;
    USE SIGNAL ;
    ANTENNAGATEAREA 0.180700 ;
    PORT
      LAYER Metal3 ;
        RECT 0.000 276.580 0.400 276.980 ;
    END
  END Tile_X0Y4_UserCLK
  PIN Tile_X0Y4_UserCLKo
    DIRECTION OUTPUT ;
    USE SIGNAL ;
    ANTENNADIFFAREA 2.724000 ;
    PORT
      LAYER Metal3 ;
        RECT 115.280 475.660 115.680 476.060 ;
    END
  END Tile_X0Y4_UserCLKo
  PIN Tile_X0Y4_W1END[0]
    DIRECTION INPUT ;
    USE SIGNAL ;
    ANTENNAGATEAREA 1.066000 ;
    PORT
      LAYER Metal3 ;
        RECT 115.280 374.860 115.680 375.260 ;
    END
  END Tile_X0Y4_W1END[0]
  PIN Tile_X0Y4_W1END[1]
    DIRECTION INPUT ;
    USE SIGNAL ;
    ANTENNAGATEAREA 1.066000 ;
    PORT
      LAYER Metal3 ;
        RECT 115.280 376.540 115.680 376.940 ;
    END
  END Tile_X0Y4_W1END[1]
  PIN Tile_X0Y4_W1END[2]
    DIRECTION INPUT ;
    USE SIGNAL ;
    ANTENNAGATEAREA 1.066000 ;
    PORT
      LAYER Metal3 ;
        RECT 115.280 378.220 115.680 378.620 ;
    END
  END Tile_X0Y4_W1END[2]
  PIN Tile_X0Y4_W1END[3]
    DIRECTION INPUT ;
    USE SIGNAL ;
    ANTENNAGATEAREA 1.066000 ;
    PORT
      LAYER Metal3 ;
        RECT 115.280 379.900 115.680 380.300 ;
    END
  END Tile_X0Y4_W1END[3]
  PIN Tile_X0Y4_W2END[0]
    DIRECTION INPUT ;
    USE SIGNAL ;
    ANTENNAGATEAREA 0.639600 ;
    PORT
      LAYER Metal3 ;
        RECT 115.280 400.900 115.680 401.300 ;
    END
  END Tile_X0Y4_W2END[0]
  PIN Tile_X0Y4_W2END[1]
    DIRECTION INPUT ;
    USE SIGNAL ;
    ANTENNAGATEAREA 0.639600 ;
    PORT
      LAYER Metal3 ;
        RECT 115.280 402.580 115.680 402.980 ;
    END
  END Tile_X0Y4_W2END[1]
  PIN Tile_X0Y4_W2END[2]
    DIRECTION INPUT ;
    USE SIGNAL ;
    ANTENNAGATEAREA 0.639600 ;
    PORT
      LAYER Metal3 ;
        RECT 115.280 404.260 115.680 404.660 ;
    END
  END Tile_X0Y4_W2END[2]
  PIN Tile_X0Y4_W2END[3]
    DIRECTION INPUT ;
    USE SIGNAL ;
    ANTENNAGATEAREA 0.639600 ;
    PORT
      LAYER Metal3 ;
        RECT 115.280 405.940 115.680 406.340 ;
    END
  END Tile_X0Y4_W2END[3]
  PIN Tile_X0Y4_W2END[4]
    DIRECTION INPUT ;
    USE SIGNAL ;
    ANTENNAGATEAREA 0.639600 ;
    PORT
      LAYER Metal3 ;
        RECT 115.280 407.620 115.680 408.020 ;
    END
  END Tile_X0Y4_W2END[4]
  PIN Tile_X0Y4_W2END[5]
    DIRECTION INPUT ;
    USE SIGNAL ;
    ANTENNAGATEAREA 0.426400 ;
    PORT
      LAYER Metal3 ;
        RECT 115.280 409.300 115.680 409.700 ;
    END
  END Tile_X0Y4_W2END[5]
  PIN Tile_X0Y4_W2END[6]
    DIRECTION INPUT ;
    USE SIGNAL ;
    ANTENNAGATEAREA 0.426400 ;
    PORT
      LAYER Metal3 ;
        RECT 115.280 410.980 115.680 411.380 ;
    END
  END Tile_X0Y4_W2END[6]
  PIN Tile_X0Y4_W2END[7]
    DIRECTION INPUT ;
    USE SIGNAL ;
    ANTENNAGATEAREA 0.426400 ;
    PORT
      LAYER Metal3 ;
        RECT 115.280 412.660 115.680 413.060 ;
    END
  END Tile_X0Y4_W2END[7]
  PIN Tile_X0Y4_W2MID[0]
    DIRECTION INPUT ;
    USE SIGNAL ;
    ANTENNAGATEAREA 0.639600 ;
    PORT
      LAYER Metal3 ;
        RECT 115.280 384.100 115.680 384.500 ;
    END
  END Tile_X0Y4_W2MID[0]
  PIN Tile_X0Y4_W2MID[1]
    DIRECTION INPUT ;
    USE SIGNAL ;
    ANTENNAGATEAREA 0.639600 ;
    PORT
      LAYER Metal3 ;
        RECT 115.280 385.780 115.680 386.180 ;
    END
  END Tile_X0Y4_W2MID[1]
  PIN Tile_X0Y4_W2MID[2]
    DIRECTION INPUT ;
    USE SIGNAL ;
    ANTENNAGATEAREA 0.639600 ;
    PORT
      LAYER Metal3 ;
        RECT 115.280 387.460 115.680 387.860 ;
    END
  END Tile_X0Y4_W2MID[2]
  PIN Tile_X0Y4_W2MID[3]
    DIRECTION INPUT ;
    USE SIGNAL ;
    ANTENNAGATEAREA 0.639600 ;
    PORT
      LAYER Metal3 ;
        RECT 115.280 389.140 115.680 389.540 ;
    END
  END Tile_X0Y4_W2MID[3]
  PIN Tile_X0Y4_W2MID[4]
    DIRECTION INPUT ;
    USE SIGNAL ;
    ANTENNAGATEAREA 0.639600 ;
    PORT
      LAYER Metal3 ;
        RECT 115.280 390.820 115.680 391.220 ;
    END
  END Tile_X0Y4_W2MID[4]
  PIN Tile_X0Y4_W2MID[5]
    DIRECTION INPUT ;
    USE SIGNAL ;
    ANTENNAGATEAREA 0.426400 ;
    PORT
      LAYER Metal3 ;
        RECT 115.280 392.500 115.680 392.900 ;
    END
  END Tile_X0Y4_W2MID[5]
  PIN Tile_X0Y4_W2MID[6]
    DIRECTION INPUT ;
    USE SIGNAL ;
    ANTENNAGATEAREA 0.426400 ;
    PORT
      LAYER Metal3 ;
        RECT 115.280 394.180 115.680 394.580 ;
    END
  END Tile_X0Y4_W2MID[6]
  PIN Tile_X0Y4_W2MID[7]
    DIRECTION INPUT ;
    USE SIGNAL ;
    ANTENNAGATEAREA 0.426400 ;
    PORT
      LAYER Metal3 ;
        RECT 115.280 395.860 115.680 396.260 ;
    END
  END Tile_X0Y4_W2MID[7]
  PIN Tile_X0Y4_W6END[0]
    DIRECTION INPUT ;
    USE SIGNAL ;
    ANTENNAGATEAREA 0.639600 ;
    PORT
      LAYER Metal3 ;
        RECT 115.280 452.140 115.680 452.540 ;
    END
  END Tile_X0Y4_W6END[0]
  PIN Tile_X0Y4_W6END[10]
    DIRECTION INPUT ;
    USE SIGNAL ;
    ANTENNAGATEAREA 0.639600 ;
    PORT
      LAYER Metal3 ;
        RECT 115.280 468.940 115.680 469.340 ;
    END
  END Tile_X0Y4_W6END[10]
  PIN Tile_X0Y4_W6END[11]
    DIRECTION INPUT ;
    USE SIGNAL ;
    ANTENNAGATEAREA 0.639600 ;
    PORT
      LAYER Metal3 ;
        RECT 115.280 470.620 115.680 471.020 ;
    END
  END Tile_X0Y4_W6END[11]
  PIN Tile_X0Y4_W6END[1]
    DIRECTION INPUT ;
    USE SIGNAL ;
    ANTENNAGATEAREA 0.639600 ;
    PORT
      LAYER Metal3 ;
        RECT 115.280 453.820 115.680 454.220 ;
    END
  END Tile_X0Y4_W6END[1]
  PIN Tile_X0Y4_W6END[2]
    DIRECTION INPUT ;
    USE SIGNAL ;
    ANTENNAGATEAREA 0.639600 ;
    PORT
      LAYER Metal3 ;
        RECT 115.280 455.500 115.680 455.900 ;
    END
  END Tile_X0Y4_W6END[2]
  PIN Tile_X0Y4_W6END[3]
    DIRECTION INPUT ;
    USE SIGNAL ;
    ANTENNAGATEAREA 0.639600 ;
    PORT
      LAYER Metal3 ;
        RECT 115.280 457.180 115.680 457.580 ;
    END
  END Tile_X0Y4_W6END[3]
  PIN Tile_X0Y4_W6END[4]
    DIRECTION INPUT ;
    USE SIGNAL ;
    ANTENNAGATEAREA 0.852800 ;
    PORT
      LAYER Metal3 ;
        RECT 115.280 458.860 115.680 459.260 ;
    END
  END Tile_X0Y4_W6END[4]
  PIN Tile_X0Y4_W6END[5]
    DIRECTION INPUT ;
    USE SIGNAL ;
    ANTENNAGATEAREA 0.639600 ;
    PORT
      LAYER Metal3 ;
        RECT 115.280 460.540 115.680 460.940 ;
    END
  END Tile_X0Y4_W6END[5]
  PIN Tile_X0Y4_W6END[6]
    DIRECTION INPUT ;
    USE SIGNAL ;
    ANTENNAGATEAREA 0.639600 ;
    PORT
      LAYER Metal3 ;
        RECT 115.280 462.220 115.680 462.620 ;
    END
  END Tile_X0Y4_W6END[6]
  PIN Tile_X0Y4_W6END[7]
    DIRECTION INPUT ;
    USE SIGNAL ;
    ANTENNAGATEAREA 0.639600 ;
    PORT
      LAYER Metal3 ;
        RECT 115.280 463.900 115.680 464.300 ;
    END
  END Tile_X0Y4_W6END[7]
  PIN Tile_X0Y4_W6END[8]
    DIRECTION INPUT ;
    USE SIGNAL ;
    ANTENNAGATEAREA 0.639600 ;
    PORT
      LAYER Metal3 ;
        RECT 115.280 465.580 115.680 465.980 ;
    END
  END Tile_X0Y4_W6END[8]
  PIN Tile_X0Y4_W6END[9]
    DIRECTION INPUT ;
    USE SIGNAL ;
    ANTENNAGATEAREA 0.639600 ;
    PORT
      LAYER Metal3 ;
        RECT 115.280 467.260 115.680 467.660 ;
    END
  END Tile_X0Y4_W6END[9]
  PIN Tile_X0Y4_WW4END[0]
    DIRECTION INPUT ;
    USE SIGNAL ;
    ANTENNAGATEAREA 0.213200 ;
    PORT
      LAYER Metal3 ;
        RECT 115.280 419.380 115.680 419.780 ;
    END
  END Tile_X0Y4_WW4END[0]
  PIN Tile_X0Y4_WW4END[10]
    DIRECTION INPUT ;
    USE SIGNAL ;
    ANTENNAGATEAREA 0.213200 ;
    PORT
      LAYER Metal3 ;
        RECT 115.280 436.180 115.680 436.580 ;
    END
  END Tile_X0Y4_WW4END[10]
  PIN Tile_X0Y4_WW4END[11]
    DIRECTION INPUT ;
    USE SIGNAL ;
    ANTENNAGATEAREA 0.213200 ;
    PORT
      LAYER Metal3 ;
        RECT 115.280 437.860 115.680 438.260 ;
    END
  END Tile_X0Y4_WW4END[11]
  PIN Tile_X0Y4_WW4END[12]
    DIRECTION INPUT ;
    USE SIGNAL ;
    ANTENNAGATEAREA 0.213200 ;
    PORT
      LAYER Metal3 ;
        RECT 115.280 439.540 115.680 439.940 ;
    END
  END Tile_X0Y4_WW4END[12]
  PIN Tile_X0Y4_WW4END[13]
    DIRECTION INPUT ;
    USE SIGNAL ;
    ANTENNAGATEAREA 0.213200 ;
    PORT
      LAYER Metal3 ;
        RECT 115.280 441.220 115.680 441.620 ;
    END
  END Tile_X0Y4_WW4END[13]
  PIN Tile_X0Y4_WW4END[14]
    DIRECTION INPUT ;
    USE SIGNAL ;
    ANTENNAGATEAREA 0.213200 ;
    PORT
      LAYER Metal3 ;
        RECT 115.280 442.900 115.680 443.300 ;
    END
  END Tile_X0Y4_WW4END[14]
  PIN Tile_X0Y4_WW4END[15]
    DIRECTION INPUT ;
    USE SIGNAL ;
    ANTENNAGATEAREA 0.213200 ;
    PORT
      LAYER Metal3 ;
        RECT 115.280 444.580 115.680 444.980 ;
    END
  END Tile_X0Y4_WW4END[15]
  PIN Tile_X0Y4_WW4END[1]
    DIRECTION INPUT ;
    USE SIGNAL ;
    ANTENNAGATEAREA 0.213200 ;
    PORT
      LAYER Metal3 ;
        RECT 115.280 421.060 115.680 421.460 ;
    END
  END Tile_X0Y4_WW4END[1]
  PIN Tile_X0Y4_WW4END[2]
    DIRECTION INPUT ;
    USE SIGNAL ;
    ANTENNAGATEAREA 0.213200 ;
    PORT
      LAYER Metal3 ;
        RECT 115.280 422.740 115.680 423.140 ;
    END
  END Tile_X0Y4_WW4END[2]
  PIN Tile_X0Y4_WW4END[3]
    DIRECTION INPUT ;
    USE SIGNAL ;
    ANTENNAGATEAREA 0.213200 ;
    PORT
      LAYER Metal3 ;
        RECT 115.280 424.420 115.680 424.820 ;
    END
  END Tile_X0Y4_WW4END[3]
  PIN Tile_X0Y4_WW4END[4]
    DIRECTION INPUT ;
    USE SIGNAL ;
    ANTENNAGATEAREA 0.213200 ;
    PORT
      LAYER Metal3 ;
        RECT 115.280 426.100 115.680 426.500 ;
    END
  END Tile_X0Y4_WW4END[4]
  PIN Tile_X0Y4_WW4END[5]
    DIRECTION INPUT ;
    USE SIGNAL ;
    ANTENNAGATEAREA 0.213200 ;
    PORT
      LAYER Metal3 ;
        RECT 115.280 427.780 115.680 428.180 ;
    END
  END Tile_X0Y4_WW4END[5]
  PIN Tile_X0Y4_WW4END[6]
    DIRECTION INPUT ;
    USE SIGNAL ;
    ANTENNAGATEAREA 0.213200 ;
    PORT
      LAYER Metal3 ;
        RECT 115.280 429.460 115.680 429.860 ;
    END
  END Tile_X0Y4_WW4END[6]
  PIN Tile_X0Y4_WW4END[7]
    DIRECTION INPUT ;
    USE SIGNAL ;
    ANTENNAGATEAREA 0.213200 ;
    PORT
      LAYER Metal3 ;
        RECT 115.280 431.140 115.680 431.540 ;
    END
  END Tile_X0Y4_WW4END[7]
  PIN Tile_X0Y4_WW4END[8]
    DIRECTION INPUT ;
    USE SIGNAL ;
    ANTENNAGATEAREA 0.213200 ;
    PORT
      LAYER Metal3 ;
        RECT 115.280 432.820 115.680 433.220 ;
    END
  END Tile_X0Y4_WW4END[8]
  PIN Tile_X0Y4_WW4END[9]
    DIRECTION INPUT ;
    USE SIGNAL ;
    ANTENNAGATEAREA 0.213200 ;
    PORT
      LAYER Metal3 ;
        RECT 115.280 434.500 115.680 434.900 ;
    END
  END Tile_X0Y4_WW4END[9]
  PIN Tile_X0Y5_E1BEG[0]
    DIRECTION OUTPUT ;
    USE SIGNAL ;
    ANTENNADIFFAREA 2.724000 ;
    PORT
      LAYER Metal3 ;
        RECT 115.280 1.900 115.680 2.300 ;
    END
  END Tile_X0Y5_E1BEG[0]
  PIN Tile_X0Y5_E1BEG[1]
    DIRECTION OUTPUT ;
    USE SIGNAL ;
    ANTENNADIFFAREA 2.724000 ;
    PORT
      LAYER Metal3 ;
        RECT 115.280 3.580 115.680 3.980 ;
    END
  END Tile_X0Y5_E1BEG[1]
  PIN Tile_X0Y5_E1BEG[2]
    DIRECTION OUTPUT ;
    USE SIGNAL ;
    ANTENNADIFFAREA 2.724000 ;
    PORT
      LAYER Metal3 ;
        RECT 115.280 5.260 115.680 5.660 ;
    END
  END Tile_X0Y5_E1BEG[2]
  PIN Tile_X0Y5_E1BEG[3]
    DIRECTION OUTPUT ;
    USE SIGNAL ;
    ANTENNADIFFAREA 2.724000 ;
    PORT
      LAYER Metal3 ;
        RECT 115.280 6.940 115.680 7.340 ;
    END
  END Tile_X0Y5_E1BEG[3]
  PIN Tile_X0Y5_E2BEG[0]
    DIRECTION OUTPUT ;
    USE SIGNAL ;
    ANTENNADIFFAREA 2.724000 ;
    PORT
      LAYER Metal3 ;
        RECT 115.280 11.140 115.680 11.540 ;
    END
  END Tile_X0Y5_E2BEG[0]
  PIN Tile_X0Y5_E2BEG[1]
    DIRECTION OUTPUT ;
    USE SIGNAL ;
    ANTENNADIFFAREA 2.724000 ;
    PORT
      LAYER Metal3 ;
        RECT 115.280 12.820 115.680 13.220 ;
    END
  END Tile_X0Y5_E2BEG[1]
  PIN Tile_X0Y5_E2BEG[2]
    DIRECTION OUTPUT ;
    USE SIGNAL ;
    ANTENNADIFFAREA 2.724000 ;
    PORT
      LAYER Metal3 ;
        RECT 115.280 14.500 115.680 14.900 ;
    END
  END Tile_X0Y5_E2BEG[2]
  PIN Tile_X0Y5_E2BEG[3]
    DIRECTION OUTPUT ;
    USE SIGNAL ;
    ANTENNADIFFAREA 2.724000 ;
    PORT
      LAYER Metal3 ;
        RECT 115.280 16.180 115.680 16.580 ;
    END
  END Tile_X0Y5_E2BEG[3]
  PIN Tile_X0Y5_E2BEG[4]
    DIRECTION OUTPUT ;
    USE SIGNAL ;
    ANTENNADIFFAREA 2.724000 ;
    PORT
      LAYER Metal3 ;
        RECT 115.280 17.860 115.680 18.260 ;
    END
  END Tile_X0Y5_E2BEG[4]
  PIN Tile_X0Y5_E2BEG[5]
    DIRECTION OUTPUT ;
    USE SIGNAL ;
    ANTENNADIFFAREA 2.724000 ;
    PORT
      LAYER Metal3 ;
        RECT 115.280 19.540 115.680 19.940 ;
    END
  END Tile_X0Y5_E2BEG[5]
  PIN Tile_X0Y5_E2BEG[6]
    DIRECTION OUTPUT ;
    USE SIGNAL ;
    ANTENNADIFFAREA 2.724000 ;
    PORT
      LAYER Metal3 ;
        RECT 115.280 21.220 115.680 21.620 ;
    END
  END Tile_X0Y5_E2BEG[6]
  PIN Tile_X0Y5_E2BEG[7]
    DIRECTION OUTPUT ;
    USE SIGNAL ;
    ANTENNADIFFAREA 2.724000 ;
    PORT
      LAYER Metal3 ;
        RECT 115.280 22.900 115.680 23.300 ;
    END
  END Tile_X0Y5_E2BEG[7]
  PIN Tile_X0Y5_E2BEGb[0]
    DIRECTION OUTPUT ;
    USE SIGNAL ;
    ANTENNADIFFAREA 2.724000 ;
    PORT
      LAYER Metal3 ;
        RECT 115.280 27.940 115.680 28.340 ;
    END
  END Tile_X0Y5_E2BEGb[0]
  PIN Tile_X0Y5_E2BEGb[1]
    DIRECTION OUTPUT ;
    USE SIGNAL ;
    ANTENNADIFFAREA 2.724000 ;
    PORT
      LAYER Metal3 ;
        RECT 115.280 29.620 115.680 30.020 ;
    END
  END Tile_X0Y5_E2BEGb[1]
  PIN Tile_X0Y5_E2BEGb[2]
    DIRECTION OUTPUT ;
    USE SIGNAL ;
    ANTENNADIFFAREA 2.724000 ;
    PORT
      LAYER Metal3 ;
        RECT 115.280 31.300 115.680 31.700 ;
    END
  END Tile_X0Y5_E2BEGb[2]
  PIN Tile_X0Y5_E2BEGb[3]
    DIRECTION OUTPUT ;
    USE SIGNAL ;
    ANTENNADIFFAREA 2.724000 ;
    PORT
      LAYER Metal3 ;
        RECT 115.280 32.980 115.680 33.380 ;
    END
  END Tile_X0Y5_E2BEGb[3]
  PIN Tile_X0Y5_E2BEGb[4]
    DIRECTION OUTPUT ;
    USE SIGNAL ;
    ANTENNADIFFAREA 2.724000 ;
    PORT
      LAYER Metal3 ;
        RECT 115.280 34.660 115.680 35.060 ;
    END
  END Tile_X0Y5_E2BEGb[4]
  PIN Tile_X0Y5_E2BEGb[5]
    DIRECTION OUTPUT ;
    USE SIGNAL ;
    ANTENNADIFFAREA 2.724000 ;
    PORT
      LAYER Metal3 ;
        RECT 115.280 36.340 115.680 36.740 ;
    END
  END Tile_X0Y5_E2BEGb[5]
  PIN Tile_X0Y5_E2BEGb[6]
    DIRECTION OUTPUT ;
    USE SIGNAL ;
    ANTENNADIFFAREA 2.724000 ;
    PORT
      LAYER Metal3 ;
        RECT 115.280 38.020 115.680 38.420 ;
    END
  END Tile_X0Y5_E2BEGb[6]
  PIN Tile_X0Y5_E2BEGb[7]
    DIRECTION OUTPUT ;
    USE SIGNAL ;
    ANTENNADIFFAREA 2.724000 ;
    PORT
      LAYER Metal3 ;
        RECT 115.280 39.700 115.680 40.100 ;
    END
  END Tile_X0Y5_E2BEGb[7]
  PIN Tile_X0Y5_E6BEG[0]
    DIRECTION OUTPUT ;
    USE SIGNAL ;
    ANTENNADIFFAREA 2.724000 ;
    PORT
      LAYER Metal3 ;
        RECT 115.280 79.180 115.680 79.580 ;
    END
  END Tile_X0Y5_E6BEG[0]
  PIN Tile_X0Y5_E6BEG[10]
    DIRECTION OUTPUT ;
    USE SIGNAL ;
    ANTENNADIFFAREA 2.724000 ;
    PORT
      LAYER Metal3 ;
        RECT 115.280 95.980 115.680 96.380 ;
    END
  END Tile_X0Y5_E6BEG[10]
  PIN Tile_X0Y5_E6BEG[11]
    DIRECTION OUTPUT ;
    USE SIGNAL ;
    ANTENNADIFFAREA 2.724000 ;
    PORT
      LAYER Metal3 ;
        RECT 115.280 97.660 115.680 98.060 ;
    END
  END Tile_X0Y5_E6BEG[11]
  PIN Tile_X0Y5_E6BEG[1]
    DIRECTION OUTPUT ;
    USE SIGNAL ;
    ANTENNADIFFAREA 2.724000 ;
    PORT
      LAYER Metal3 ;
        RECT 115.280 80.860 115.680 81.260 ;
    END
  END Tile_X0Y5_E6BEG[1]
  PIN Tile_X0Y5_E6BEG[2]
    DIRECTION OUTPUT ;
    USE SIGNAL ;
    ANTENNADIFFAREA 2.724000 ;
    PORT
      LAYER Metal3 ;
        RECT 115.280 82.540 115.680 82.940 ;
    END
  END Tile_X0Y5_E6BEG[2]
  PIN Tile_X0Y5_E6BEG[3]
    DIRECTION OUTPUT ;
    USE SIGNAL ;
    ANTENNADIFFAREA 2.724000 ;
    PORT
      LAYER Metal3 ;
        RECT 115.280 84.220 115.680 84.620 ;
    END
  END Tile_X0Y5_E6BEG[3]
  PIN Tile_X0Y5_E6BEG[4]
    DIRECTION OUTPUT ;
    USE SIGNAL ;
    ANTENNADIFFAREA 2.724000 ;
    PORT
      LAYER Metal3 ;
        RECT 115.280 85.900 115.680 86.300 ;
    END
  END Tile_X0Y5_E6BEG[4]
  PIN Tile_X0Y5_E6BEG[5]
    DIRECTION OUTPUT ;
    USE SIGNAL ;
    ANTENNADIFFAREA 2.724000 ;
    PORT
      LAYER Metal3 ;
        RECT 115.280 87.580 115.680 87.980 ;
    END
  END Tile_X0Y5_E6BEG[5]
  PIN Tile_X0Y5_E6BEG[6]
    DIRECTION OUTPUT ;
    USE SIGNAL ;
    ANTENNADIFFAREA 2.724000 ;
    PORT
      LAYER Metal3 ;
        RECT 115.280 89.260 115.680 89.660 ;
    END
  END Tile_X0Y5_E6BEG[6]
  PIN Tile_X0Y5_E6BEG[7]
    DIRECTION OUTPUT ;
    USE SIGNAL ;
    ANTENNADIFFAREA 2.724000 ;
    PORT
      LAYER Metal3 ;
        RECT 115.280 90.940 115.680 91.340 ;
    END
  END Tile_X0Y5_E6BEG[7]
  PIN Tile_X0Y5_E6BEG[8]
    DIRECTION OUTPUT ;
    USE SIGNAL ;
    ANTENNADIFFAREA 2.724000 ;
    PORT
      LAYER Metal3 ;
        RECT 115.280 92.620 115.680 93.020 ;
    END
  END Tile_X0Y5_E6BEG[8]
  PIN Tile_X0Y5_E6BEG[9]
    DIRECTION OUTPUT ;
    USE SIGNAL ;
    ANTENNADIFFAREA 2.724000 ;
    PORT
      LAYER Metal3 ;
        RECT 115.280 94.300 115.680 94.700 ;
    END
  END Tile_X0Y5_E6BEG[9]
  PIN Tile_X0Y5_EE4BEG[0]
    DIRECTION OUTPUT ;
    USE SIGNAL ;
    ANTENNADIFFAREA 2.724000 ;
    PORT
      LAYER Metal3 ;
        RECT 115.280 46.420 115.680 46.820 ;
    END
  END Tile_X0Y5_EE4BEG[0]
  PIN Tile_X0Y5_EE4BEG[10]
    DIRECTION OUTPUT ;
    USE SIGNAL ;
    ANTENNADIFFAREA 2.724000 ;
    PORT
      LAYER Metal3 ;
        RECT 115.280 63.220 115.680 63.620 ;
    END
  END Tile_X0Y5_EE4BEG[10]
  PIN Tile_X0Y5_EE4BEG[11]
    DIRECTION OUTPUT ;
    USE SIGNAL ;
    ANTENNADIFFAREA 2.724000 ;
    PORT
      LAYER Metal3 ;
        RECT 115.280 64.900 115.680 65.300 ;
    END
  END Tile_X0Y5_EE4BEG[11]
  PIN Tile_X0Y5_EE4BEG[12]
    DIRECTION OUTPUT ;
    USE SIGNAL ;
    ANTENNADIFFAREA 2.724000 ;
    PORT
      LAYER Metal3 ;
        RECT 115.280 66.580 115.680 66.980 ;
    END
  END Tile_X0Y5_EE4BEG[12]
  PIN Tile_X0Y5_EE4BEG[13]
    DIRECTION OUTPUT ;
    USE SIGNAL ;
    ANTENNADIFFAREA 2.724000 ;
    PORT
      LAYER Metal3 ;
        RECT 115.280 68.260 115.680 68.660 ;
    END
  END Tile_X0Y5_EE4BEG[13]
  PIN Tile_X0Y5_EE4BEG[14]
    DIRECTION OUTPUT ;
    USE SIGNAL ;
    ANTENNADIFFAREA 2.724000 ;
    PORT
      LAYER Metal3 ;
        RECT 115.280 69.940 115.680 70.340 ;
    END
  END Tile_X0Y5_EE4BEG[14]
  PIN Tile_X0Y5_EE4BEG[15]
    DIRECTION OUTPUT ;
    USE SIGNAL ;
    ANTENNADIFFAREA 2.724000 ;
    PORT
      LAYER Metal3 ;
        RECT 115.280 71.620 115.680 72.020 ;
    END
  END Tile_X0Y5_EE4BEG[15]
  PIN Tile_X0Y5_EE4BEG[1]
    DIRECTION OUTPUT ;
    USE SIGNAL ;
    ANTENNADIFFAREA 2.724000 ;
    PORT
      LAYER Metal3 ;
        RECT 115.280 48.100 115.680 48.500 ;
    END
  END Tile_X0Y5_EE4BEG[1]
  PIN Tile_X0Y5_EE4BEG[2]
    DIRECTION OUTPUT ;
    USE SIGNAL ;
    ANTENNADIFFAREA 2.724000 ;
    PORT
      LAYER Metal3 ;
        RECT 115.280 49.780 115.680 50.180 ;
    END
  END Tile_X0Y5_EE4BEG[2]
  PIN Tile_X0Y5_EE4BEG[3]
    DIRECTION OUTPUT ;
    USE SIGNAL ;
    ANTENNADIFFAREA 2.724000 ;
    PORT
      LAYER Metal3 ;
        RECT 115.280 51.460 115.680 51.860 ;
    END
  END Tile_X0Y5_EE4BEG[3]
  PIN Tile_X0Y5_EE4BEG[4]
    DIRECTION OUTPUT ;
    USE SIGNAL ;
    ANTENNADIFFAREA 2.724000 ;
    PORT
      LAYER Metal3 ;
        RECT 115.280 53.140 115.680 53.540 ;
    END
  END Tile_X0Y5_EE4BEG[4]
  PIN Tile_X0Y5_EE4BEG[5]
    DIRECTION OUTPUT ;
    USE SIGNAL ;
    ANTENNADIFFAREA 2.724000 ;
    PORT
      LAYER Metal3 ;
        RECT 115.280 54.820 115.680 55.220 ;
    END
  END Tile_X0Y5_EE4BEG[5]
  PIN Tile_X0Y5_EE4BEG[6]
    DIRECTION OUTPUT ;
    USE SIGNAL ;
    ANTENNADIFFAREA 2.724000 ;
    PORT
      LAYER Metal3 ;
        RECT 115.280 56.500 115.680 56.900 ;
    END
  END Tile_X0Y5_EE4BEG[6]
  PIN Tile_X0Y5_EE4BEG[7]
    DIRECTION OUTPUT ;
    USE SIGNAL ;
    ANTENNADIFFAREA 2.724000 ;
    PORT
      LAYER Metal3 ;
        RECT 115.280 58.180 115.680 58.580 ;
    END
  END Tile_X0Y5_EE4BEG[7]
  PIN Tile_X0Y5_EE4BEG[8]
    DIRECTION OUTPUT ;
    USE SIGNAL ;
    ANTENNADIFFAREA 2.724000 ;
    PORT
      LAYER Metal3 ;
        RECT 115.280 59.860 115.680 60.260 ;
    END
  END Tile_X0Y5_EE4BEG[8]
  PIN Tile_X0Y5_EE4BEG[9]
    DIRECTION OUTPUT ;
    USE SIGNAL ;
    ANTENNADIFFAREA 2.724000 ;
    PORT
      LAYER Metal3 ;
        RECT 115.280 61.540 115.680 61.940 ;
    END
  END Tile_X0Y5_EE4BEG[9]
  PIN Tile_X0Y5_FrameData[0]
    DIRECTION INPUT ;
    USE SIGNAL ;
    ANTENNAGATEAREA 1.445600 ;
    PORT
      LAYER Metal3 ;
        RECT 0.000 6.940 0.400 7.340 ;
    END
  END Tile_X0Y5_FrameData[0]
  PIN Tile_X0Y5_FrameData[10]
    DIRECTION INPUT ;
    USE SIGNAL ;
    ANTENNAGATEAREA 1.445600 ;
    PORT
      LAYER Metal3 ;
        RECT 0.000 23.740 0.400 24.140 ;
    END
  END Tile_X0Y5_FrameData[10]
  PIN Tile_X0Y5_FrameData[11]
    DIRECTION INPUT ;
    USE SIGNAL ;
    ANTENNAGATEAREA 1.445600 ;
    PORT
      LAYER Metal3 ;
        RECT 0.000 25.420 0.400 25.820 ;
    END
  END Tile_X0Y5_FrameData[11]
  PIN Tile_X0Y5_FrameData[12]
    DIRECTION INPUT ;
    USE SIGNAL ;
    ANTENNAGATEAREA 1.445600 ;
    PORT
      LAYER Metal3 ;
        RECT 0.000 27.100 0.400 27.500 ;
    END
  END Tile_X0Y5_FrameData[12]
  PIN Tile_X0Y5_FrameData[13]
    DIRECTION INPUT ;
    USE SIGNAL ;
    ANTENNAGATEAREA 1.445600 ;
    PORT
      LAYER Metal3 ;
        RECT 0.000 28.780 0.400 29.180 ;
    END
  END Tile_X0Y5_FrameData[13]
  PIN Tile_X0Y5_FrameData[14]
    DIRECTION INPUT ;
    USE SIGNAL ;
    ANTENNAGATEAREA 1.445600 ;
    PORT
      LAYER Metal3 ;
        RECT 0.000 30.460 0.400 30.860 ;
    END
  END Tile_X0Y5_FrameData[14]
  PIN Tile_X0Y5_FrameData[15]
    DIRECTION INPUT ;
    USE SIGNAL ;
    ANTENNAGATEAREA 1.445600 ;
    PORT
      LAYER Metal3 ;
        RECT 0.000 32.140 0.400 32.540 ;
    END
  END Tile_X0Y5_FrameData[15]
  PIN Tile_X0Y5_FrameData[16]
    DIRECTION INPUT ;
    USE SIGNAL ;
    ANTENNAGATEAREA 1.445600 ;
    PORT
      LAYER Metal3 ;
        RECT 0.000 33.820 0.400 34.220 ;
    END
  END Tile_X0Y5_FrameData[16]
  PIN Tile_X0Y5_FrameData[17]
    DIRECTION INPUT ;
    USE SIGNAL ;
    ANTENNAGATEAREA 1.445600 ;
    PORT
      LAYER Metal3 ;
        RECT 0.000 35.500 0.400 35.900 ;
    END
  END Tile_X0Y5_FrameData[17]
  PIN Tile_X0Y5_FrameData[18]
    DIRECTION INPUT ;
    USE SIGNAL ;
    ANTENNAGATEAREA 1.445600 ;
    PORT
      LAYER Metal3 ;
        RECT 0.000 37.180 0.400 37.580 ;
    END
  END Tile_X0Y5_FrameData[18]
  PIN Tile_X0Y5_FrameData[19]
    DIRECTION INPUT ;
    USE SIGNAL ;
    ANTENNAGATEAREA 1.445600 ;
    PORT
      LAYER Metal3 ;
        RECT 0.000 38.860 0.400 39.260 ;
    END
  END Tile_X0Y5_FrameData[19]
  PIN Tile_X0Y5_FrameData[1]
    DIRECTION INPUT ;
    USE SIGNAL ;
    ANTENNAGATEAREA 1.445600 ;
    PORT
      LAYER Metal3 ;
        RECT 0.000 8.620 0.400 9.020 ;
    END
  END Tile_X0Y5_FrameData[1]
  PIN Tile_X0Y5_FrameData[20]
    DIRECTION INPUT ;
    USE SIGNAL ;
    ANTENNAGATEAREA 1.445600 ;
    PORT
      LAYER Metal3 ;
        RECT 0.000 40.540 0.400 40.940 ;
    END
  END Tile_X0Y5_FrameData[20]
  PIN Tile_X0Y5_FrameData[21]
    DIRECTION INPUT ;
    USE SIGNAL ;
    ANTENNAGATEAREA 1.445600 ;
    PORT
      LAYER Metal3 ;
        RECT 0.000 42.220 0.400 42.620 ;
    END
  END Tile_X0Y5_FrameData[21]
  PIN Tile_X0Y5_FrameData[22]
    DIRECTION INPUT ;
    USE SIGNAL ;
    ANTENNAGATEAREA 1.445600 ;
    PORT
      LAYER Metal3 ;
        RECT 0.000 43.900 0.400 44.300 ;
    END
  END Tile_X0Y5_FrameData[22]
  PIN Tile_X0Y5_FrameData[23]
    DIRECTION INPUT ;
    USE SIGNAL ;
    ANTENNAGATEAREA 1.445600 ;
    PORT
      LAYER Metal3 ;
        RECT 0.000 45.580 0.400 45.980 ;
    END
  END Tile_X0Y5_FrameData[23]
  PIN Tile_X0Y5_FrameData[24]
    DIRECTION INPUT ;
    USE SIGNAL ;
    ANTENNAGATEAREA 1.626300 ;
    PORT
      LAYER Metal3 ;
        RECT 0.000 47.260 0.400 47.660 ;
    END
  END Tile_X0Y5_FrameData[24]
  PIN Tile_X0Y5_FrameData[25]
    DIRECTION INPUT ;
    USE SIGNAL ;
    ANTENNAGATEAREA 1.626300 ;
    PORT
      LAYER Metal3 ;
        RECT 0.000 48.940 0.400 49.340 ;
    END
  END Tile_X0Y5_FrameData[25]
  PIN Tile_X0Y5_FrameData[26]
    DIRECTION INPUT ;
    USE SIGNAL ;
    ANTENNAGATEAREA 1.626300 ;
    PORT
      LAYER Metal3 ;
        RECT 0.000 50.620 0.400 51.020 ;
    END
  END Tile_X0Y5_FrameData[26]
  PIN Tile_X0Y5_FrameData[27]
    DIRECTION INPUT ;
    USE SIGNAL ;
    ANTENNAGATEAREA 1.626300 ;
    PORT
      LAYER Metal3 ;
        RECT 0.000 52.300 0.400 52.700 ;
    END
  END Tile_X0Y5_FrameData[27]
  PIN Tile_X0Y5_FrameData[28]
    DIRECTION INPUT ;
    USE SIGNAL ;
    ANTENNAGATEAREA 1.626300 ;
    PORT
      LAYER Metal3 ;
        RECT 0.000 53.980 0.400 54.380 ;
    END
  END Tile_X0Y5_FrameData[28]
  PIN Tile_X0Y5_FrameData[29]
    DIRECTION INPUT ;
    USE SIGNAL ;
    ANTENNAGATEAREA 1.626300 ;
    PORT
      LAYER Metal3 ;
        RECT 0.000 55.660 0.400 56.060 ;
    END
  END Tile_X0Y5_FrameData[29]
  PIN Tile_X0Y5_FrameData[2]
    DIRECTION INPUT ;
    USE SIGNAL ;
    ANTENNAGATEAREA 1.445600 ;
    PORT
      LAYER Metal3 ;
        RECT 0.000 10.300 0.400 10.700 ;
    END
  END Tile_X0Y5_FrameData[2]
  PIN Tile_X0Y5_FrameData[30]
    DIRECTION INPUT ;
    USE SIGNAL ;
    ANTENNAGATEAREA 1.626300 ;
    PORT
      LAYER Metal3 ;
        RECT 0.000 57.340 0.400 57.740 ;
    END
  END Tile_X0Y5_FrameData[30]
  PIN Tile_X0Y5_FrameData[31]
    DIRECTION INPUT ;
    USE SIGNAL ;
    ANTENNAGATEAREA 1.626300 ;
    PORT
      LAYER Metal3 ;
        RECT 0.000 59.020 0.400 59.420 ;
    END
  END Tile_X0Y5_FrameData[31]
  PIN Tile_X0Y5_FrameData[3]
    DIRECTION INPUT ;
    USE SIGNAL ;
    ANTENNAGATEAREA 1.445600 ;
    PORT
      LAYER Metal3 ;
        RECT 0.000 11.980 0.400 12.380 ;
    END
  END Tile_X0Y5_FrameData[3]
  PIN Tile_X0Y5_FrameData[4]
    DIRECTION INPUT ;
    USE SIGNAL ;
    ANTENNAGATEAREA 1.445600 ;
    PORT
      LAYER Metal3 ;
        RECT 0.000 13.660 0.400 14.060 ;
    END
  END Tile_X0Y5_FrameData[4]
  PIN Tile_X0Y5_FrameData[5]
    DIRECTION INPUT ;
    USE SIGNAL ;
    ANTENNAGATEAREA 1.445600 ;
    PORT
      LAYER Metal3 ;
        RECT 0.000 15.340 0.400 15.740 ;
    END
  END Tile_X0Y5_FrameData[5]
  PIN Tile_X0Y5_FrameData[6]
    DIRECTION INPUT ;
    USE SIGNAL ;
    ANTENNAGATEAREA 1.445600 ;
    PORT
      LAYER Metal3 ;
        RECT 0.000 17.020 0.400 17.420 ;
    END
  END Tile_X0Y5_FrameData[6]
  PIN Tile_X0Y5_FrameData[7]
    DIRECTION INPUT ;
    USE SIGNAL ;
    ANTENNAGATEAREA 1.445600 ;
    PORT
      LAYER Metal3 ;
        RECT 0.000 18.700 0.400 19.100 ;
    END
  END Tile_X0Y5_FrameData[7]
  PIN Tile_X0Y5_FrameData[8]
    DIRECTION INPUT ;
    USE SIGNAL ;
    ANTENNAGATEAREA 1.445600 ;
    PORT
      LAYER Metal3 ;
        RECT 0.000 20.380 0.400 20.780 ;
    END
  END Tile_X0Y5_FrameData[8]
  PIN Tile_X0Y5_FrameData[9]
    DIRECTION INPUT ;
    USE SIGNAL ;
    ANTENNAGATEAREA 1.445600 ;
    PORT
      LAYER Metal3 ;
        RECT 0.000 22.060 0.400 22.460 ;
    END
  END Tile_X0Y5_FrameData[9]
  PIN Tile_X0Y5_FrameData_O[0]
    DIRECTION OUTPUT ;
    USE SIGNAL ;
    ANTENNADIFFAREA 2.724000 ;
    PORT
      LAYER Metal3 ;
        RECT 115.280 211.900 115.680 212.300 ;
    END
  END Tile_X0Y5_FrameData_O[0]
  PIN Tile_X0Y5_FrameData_O[10]
    DIRECTION OUTPUT ;
    USE SIGNAL ;
    ANTENNADIFFAREA 2.724000 ;
    PORT
      LAYER Metal3 ;
        RECT 115.280 228.700 115.680 229.100 ;
    END
  END Tile_X0Y5_FrameData_O[10]
  PIN Tile_X0Y5_FrameData_O[11]
    DIRECTION OUTPUT ;
    USE SIGNAL ;
    ANTENNADIFFAREA 2.724000 ;
    PORT
      LAYER Metal3 ;
        RECT 115.280 230.380 115.680 230.780 ;
    END
  END Tile_X0Y5_FrameData_O[11]
  PIN Tile_X0Y5_FrameData_O[12]
    DIRECTION OUTPUT ;
    USE SIGNAL ;
    ANTENNADIFFAREA 2.724000 ;
    PORT
      LAYER Metal3 ;
        RECT 115.280 232.060 115.680 232.460 ;
    END
  END Tile_X0Y5_FrameData_O[12]
  PIN Tile_X0Y5_FrameData_O[13]
    DIRECTION OUTPUT ;
    USE SIGNAL ;
    ANTENNADIFFAREA 2.724000 ;
    PORT
      LAYER Metal3 ;
        RECT 115.280 233.740 115.680 234.140 ;
    END
  END Tile_X0Y5_FrameData_O[13]
  PIN Tile_X0Y5_FrameData_O[14]
    DIRECTION OUTPUT ;
    USE SIGNAL ;
    ANTENNADIFFAREA 2.724000 ;
    PORT
      LAYER Metal3 ;
        RECT 115.280 235.420 115.680 235.820 ;
    END
  END Tile_X0Y5_FrameData_O[14]
  PIN Tile_X0Y5_FrameData_O[15]
    DIRECTION OUTPUT ;
    USE SIGNAL ;
    ANTENNADIFFAREA 2.724000 ;
    PORT
      LAYER Metal3 ;
        RECT 115.280 237.100 115.680 237.500 ;
    END
  END Tile_X0Y5_FrameData_O[15]
  PIN Tile_X0Y5_FrameData_O[16]
    DIRECTION OUTPUT ;
    USE SIGNAL ;
    ANTENNADIFFAREA 2.724000 ;
    PORT
      LAYER Metal3 ;
        RECT 115.280 238.780 115.680 239.180 ;
    END
  END Tile_X0Y5_FrameData_O[16]
  PIN Tile_X0Y5_FrameData_O[17]
    DIRECTION OUTPUT ;
    USE SIGNAL ;
    ANTENNADIFFAREA 2.724000 ;
    PORT
      LAYER Metal3 ;
        RECT 115.280 240.460 115.680 240.860 ;
    END
  END Tile_X0Y5_FrameData_O[17]
  PIN Tile_X0Y5_FrameData_O[18]
    DIRECTION OUTPUT ;
    USE SIGNAL ;
    ANTENNADIFFAREA 2.724000 ;
    PORT
      LAYER Metal3 ;
        RECT 115.280 242.140 115.680 242.540 ;
    END
  END Tile_X0Y5_FrameData_O[18]
  PIN Tile_X0Y5_FrameData_O[19]
    DIRECTION OUTPUT ;
    USE SIGNAL ;
    ANTENNADIFFAREA 2.724000 ;
    PORT
      LAYER Metal3 ;
        RECT 115.280 243.820 115.680 244.220 ;
    END
  END Tile_X0Y5_FrameData_O[19]
  PIN Tile_X0Y5_FrameData_O[1]
    DIRECTION OUTPUT ;
    USE SIGNAL ;
    ANTENNADIFFAREA 2.724000 ;
    PORT
      LAYER Metal3 ;
        RECT 115.280 213.580 115.680 213.980 ;
    END
  END Tile_X0Y5_FrameData_O[1]
  PIN Tile_X0Y5_FrameData_O[20]
    DIRECTION OUTPUT ;
    USE SIGNAL ;
    ANTENNADIFFAREA 2.724000 ;
    PORT
      LAYER Metal3 ;
        RECT 115.280 245.500 115.680 245.900 ;
    END
  END Tile_X0Y5_FrameData_O[20]
  PIN Tile_X0Y5_FrameData_O[21]
    DIRECTION OUTPUT ;
    USE SIGNAL ;
    ANTENNADIFFAREA 2.724000 ;
    PORT
      LAYER Metal3 ;
        RECT 115.280 247.180 115.680 247.580 ;
    END
  END Tile_X0Y5_FrameData_O[21]
  PIN Tile_X0Y5_FrameData_O[22]
    DIRECTION OUTPUT ;
    USE SIGNAL ;
    ANTENNADIFFAREA 2.724000 ;
    PORT
      LAYER Metal3 ;
        RECT 115.280 248.860 115.680 249.260 ;
    END
  END Tile_X0Y5_FrameData_O[22]
  PIN Tile_X0Y5_FrameData_O[23]
    DIRECTION OUTPUT ;
    USE SIGNAL ;
    ANTENNADIFFAREA 2.724000 ;
    PORT
      LAYER Metal3 ;
        RECT 115.280 250.540 115.680 250.940 ;
    END
  END Tile_X0Y5_FrameData_O[23]
  PIN Tile_X0Y5_FrameData_O[24]
    DIRECTION OUTPUT ;
    USE SIGNAL ;
    ANTENNADIFFAREA 2.724000 ;
    PORT
      LAYER Metal3 ;
        RECT 115.280 252.220 115.680 252.620 ;
    END
  END Tile_X0Y5_FrameData_O[24]
  PIN Tile_X0Y5_FrameData_O[25]
    DIRECTION OUTPUT ;
    USE SIGNAL ;
    ANTENNADIFFAREA 2.724000 ;
    PORT
      LAYER Metal3 ;
        RECT 115.280 253.900 115.680 254.300 ;
    END
  END Tile_X0Y5_FrameData_O[25]
  PIN Tile_X0Y5_FrameData_O[26]
    DIRECTION OUTPUT ;
    USE SIGNAL ;
    ANTENNADIFFAREA 2.724000 ;
    PORT
      LAYER Metal3 ;
        RECT 115.280 255.580 115.680 255.980 ;
    END
  END Tile_X0Y5_FrameData_O[26]
  PIN Tile_X0Y5_FrameData_O[27]
    DIRECTION OUTPUT ;
    USE SIGNAL ;
    ANTENNADIFFAREA 2.724000 ;
    PORT
      LAYER Metal3 ;
        RECT 115.280 257.260 115.680 257.660 ;
    END
  END Tile_X0Y5_FrameData_O[27]
  PIN Tile_X0Y5_FrameData_O[28]
    DIRECTION OUTPUT ;
    USE SIGNAL ;
    ANTENNADIFFAREA 2.724000 ;
    PORT
      LAYER Metal3 ;
        RECT 115.280 258.940 115.680 259.340 ;
    END
  END Tile_X0Y5_FrameData_O[28]
  PIN Tile_X0Y5_FrameData_O[29]
    DIRECTION OUTPUT ;
    USE SIGNAL ;
    ANTENNADIFFAREA 2.724000 ;
    PORT
      LAYER Metal3 ;
        RECT 115.280 260.620 115.680 261.020 ;
    END
  END Tile_X0Y5_FrameData_O[29]
  PIN Tile_X0Y5_FrameData_O[2]
    DIRECTION OUTPUT ;
    USE SIGNAL ;
    ANTENNADIFFAREA 2.724000 ;
    PORT
      LAYER Metal3 ;
        RECT 115.280 215.260 115.680 215.660 ;
    END
  END Tile_X0Y5_FrameData_O[2]
  PIN Tile_X0Y5_FrameData_O[30]
    DIRECTION OUTPUT ;
    USE SIGNAL ;
    ANTENNADIFFAREA 2.724000 ;
    PORT
      LAYER Metal3 ;
        RECT 115.280 262.300 115.680 262.700 ;
    END
  END Tile_X0Y5_FrameData_O[30]
  PIN Tile_X0Y5_FrameData_O[31]
    DIRECTION OUTPUT ;
    USE SIGNAL ;
    ANTENNADIFFAREA 2.724000 ;
    PORT
      LAYER Metal3 ;
        RECT 115.280 263.980 115.680 264.380 ;
    END
  END Tile_X0Y5_FrameData_O[31]
  PIN Tile_X0Y5_FrameData_O[3]
    DIRECTION OUTPUT ;
    USE SIGNAL ;
    ANTENNADIFFAREA 2.724000 ;
    PORT
      LAYER Metal3 ;
        RECT 115.280 216.940 115.680 217.340 ;
    END
  END Tile_X0Y5_FrameData_O[3]
  PIN Tile_X0Y5_FrameData_O[4]
    DIRECTION OUTPUT ;
    USE SIGNAL ;
    ANTENNADIFFAREA 2.724000 ;
    PORT
      LAYER Metal3 ;
        RECT 115.280 218.620 115.680 219.020 ;
    END
  END Tile_X0Y5_FrameData_O[4]
  PIN Tile_X0Y5_FrameData_O[5]
    DIRECTION OUTPUT ;
    USE SIGNAL ;
    ANTENNADIFFAREA 2.724000 ;
    PORT
      LAYER Metal3 ;
        RECT 115.280 220.300 115.680 220.700 ;
    END
  END Tile_X0Y5_FrameData_O[5]
  PIN Tile_X0Y5_FrameData_O[6]
    DIRECTION OUTPUT ;
    USE SIGNAL ;
    ANTENNADIFFAREA 2.724000 ;
    PORT
      LAYER Metal3 ;
        RECT 115.280 221.980 115.680 222.380 ;
    END
  END Tile_X0Y5_FrameData_O[6]
  PIN Tile_X0Y5_FrameData_O[7]
    DIRECTION OUTPUT ;
    USE SIGNAL ;
    ANTENNADIFFAREA 2.724000 ;
    PORT
      LAYER Metal3 ;
        RECT 115.280 223.660 115.680 224.060 ;
    END
  END Tile_X0Y5_FrameData_O[7]
  PIN Tile_X0Y5_FrameData_O[8]
    DIRECTION OUTPUT ;
    USE SIGNAL ;
    ANTENNADIFFAREA 2.724000 ;
    PORT
      LAYER Metal3 ;
        RECT 115.280 225.340 115.680 225.740 ;
    END
  END Tile_X0Y5_FrameData_O[8]
  PIN Tile_X0Y5_FrameData_O[9]
    DIRECTION OUTPUT ;
    USE SIGNAL ;
    ANTENNADIFFAREA 2.724000 ;
    PORT
      LAYER Metal3 ;
        RECT 115.280 227.020 115.680 227.420 ;
    END
  END Tile_X0Y5_FrameData_O[9]
  PIN Tile_X0Y5_FrameStrobe[0]
    DIRECTION INPUT ;
    USE SIGNAL ;
    ANTENNAGATEAREA 69.569496 ;
    PORT
      LAYER Metal2 ;
        RECT 94.360 0.000 94.760 0.400 ;
    END
  END Tile_X0Y5_FrameStrobe[0]
  PIN Tile_X0Y5_FrameStrobe[10]
    DIRECTION INPUT ;
    USE SIGNAL ;
    ANTENNAGATEAREA 0.180700 ;
    ANTENNADIFFAREA 2.015400 ;
    PORT
      LAYER Metal2 ;
        RECT 103.960 0.000 104.360 0.400 ;
    END
  END Tile_X0Y5_FrameStrobe[10]
  PIN Tile_X0Y5_FrameStrobe[11]
    DIRECTION INPUT ;
    USE SIGNAL ;
    ANTENNAGATEAREA 0.180700 ;
    ANTENNADIFFAREA 2.015400 ;
    PORT
      LAYER Metal2 ;
        RECT 104.920 0.000 105.320 0.400 ;
    END
  END Tile_X0Y5_FrameStrobe[11]
  PIN Tile_X0Y5_FrameStrobe[12]
    DIRECTION INPUT ;
    USE SIGNAL ;
    ANTENNAGATEAREA 0.180700 ;
    ANTENNADIFFAREA 2.015400 ;
    PORT
      LAYER Metal2 ;
        RECT 105.880 0.000 106.280 0.400 ;
    END
  END Tile_X0Y5_FrameStrobe[12]
  PIN Tile_X0Y5_FrameStrobe[13]
    DIRECTION INPUT ;
    USE SIGNAL ;
    ANTENNAGATEAREA 0.180700 ;
    ANTENNADIFFAREA 2.015400 ;
    PORT
      LAYER Metal2 ;
        RECT 106.840 0.000 107.240 0.400 ;
    END
  END Tile_X0Y5_FrameStrobe[13]
  PIN Tile_X0Y5_FrameStrobe[14]
    DIRECTION INPUT ;
    USE SIGNAL ;
    ANTENNAGATEAREA 0.180700 ;
    ANTENNADIFFAREA 2.015400 ;
    PORT
      LAYER Metal2 ;
        RECT 107.800 0.000 108.200 0.400 ;
    END
  END Tile_X0Y5_FrameStrobe[14]
  PIN Tile_X0Y5_FrameStrobe[15]
    DIRECTION INPUT ;
    USE SIGNAL ;
    ANTENNAGATEAREA 0.180700 ;
    ANTENNADIFFAREA 2.015400 ;
    PORT
      LAYER Metal2 ;
        RECT 108.760 0.000 109.160 0.400 ;
    END
  END Tile_X0Y5_FrameStrobe[15]
  PIN Tile_X0Y5_FrameStrobe[16]
    DIRECTION INPUT ;
    USE SIGNAL ;
    ANTENNAGATEAREA 0.180700 ;
    ANTENNADIFFAREA 2.015400 ;
    PORT
      LAYER Metal2 ;
        RECT 109.720 0.000 110.120 0.400 ;
    END
  END Tile_X0Y5_FrameStrobe[16]
  PIN Tile_X0Y5_FrameStrobe[17]
    DIRECTION INPUT ;
    USE SIGNAL ;
    ANTENNAGATEAREA 0.180700 ;
    ANTENNADIFFAREA 2.015400 ;
    PORT
      LAYER Metal2 ;
        RECT 110.680 0.000 111.080 0.400 ;
    END
  END Tile_X0Y5_FrameStrobe[17]
  PIN Tile_X0Y5_FrameStrobe[18]
    DIRECTION INPUT ;
    USE SIGNAL ;
    ANTENNAGATEAREA 0.180700 ;
    ANTENNADIFFAREA 2.015400 ;
    PORT
      LAYER Metal2 ;
        RECT 111.640 0.000 112.040 0.400 ;
    END
  END Tile_X0Y5_FrameStrobe[18]
  PIN Tile_X0Y5_FrameStrobe[19]
    DIRECTION INPUT ;
    USE SIGNAL ;
    ANTENNAGATEAREA 0.180700 ;
    ANTENNADIFFAREA 2.015400 ;
    PORT
      LAYER Metal2 ;
        RECT 112.600 0.000 113.000 0.400 ;
    END
  END Tile_X0Y5_FrameStrobe[19]
  PIN Tile_X0Y5_FrameStrobe[1]
    DIRECTION INPUT ;
    USE SIGNAL ;
    ANTENNAGATEAREA 69.569496 ;
    PORT
      LAYER Metal2 ;
        RECT 95.320 0.000 95.720 0.400 ;
    END
  END Tile_X0Y5_FrameStrobe[1]
  PIN Tile_X0Y5_FrameStrobe[2]
    DIRECTION INPUT ;
    USE SIGNAL ;
    ANTENNAGATEAREA 69.569496 ;
    PORT
      LAYER Metal2 ;
        RECT 96.280 0.000 96.680 0.400 ;
    END
  END Tile_X0Y5_FrameStrobe[2]
  PIN Tile_X0Y5_FrameStrobe[3]
    DIRECTION INPUT ;
    USE SIGNAL ;
    ANTENNAGATEAREA 69.569496 ;
    PORT
      LAYER Metal2 ;
        RECT 97.240 0.000 97.640 0.400 ;
    END
  END Tile_X0Y5_FrameStrobe[3]
  PIN Tile_X0Y5_FrameStrobe[4]
    DIRECTION INPUT ;
    USE SIGNAL ;
    ANTENNAGATEAREA 69.569496 ;
    PORT
      LAYER Metal2 ;
        RECT 98.200 0.000 98.600 0.400 ;
    END
  END Tile_X0Y5_FrameStrobe[4]
  PIN Tile_X0Y5_FrameStrobe[5]
    DIRECTION INPUT ;
    USE SIGNAL ;
    ANTENNAGATEAREA 69.569496 ;
    PORT
      LAYER Metal2 ;
        RECT 99.160 0.000 99.560 0.400 ;
    END
  END Tile_X0Y5_FrameStrobe[5]
  PIN Tile_X0Y5_FrameStrobe[6]
    DIRECTION INPUT ;
    USE SIGNAL ;
    ANTENNAGATEAREA 69.569496 ;
    PORT
      LAYER Metal2 ;
        RECT 100.120 0.000 100.520 0.400 ;
    END
  END Tile_X0Y5_FrameStrobe[6]
  PIN Tile_X0Y5_FrameStrobe[7]
    DIRECTION INPUT ;
    USE SIGNAL ;
    ANTENNAGATEAREA 29.815498 ;
    PORT
      LAYER Metal2 ;
        RECT 101.080 0.000 101.480 0.400 ;
    END
  END Tile_X0Y5_FrameStrobe[7]
  PIN Tile_X0Y5_FrameStrobe[8]
    DIRECTION INPUT ;
    USE SIGNAL ;
    ANTENNAGATEAREA 0.180700 ;
    ANTENNADIFFAREA 2.015400 ;
    PORT
      LAYER Metal2 ;
        RECT 102.040 0.000 102.440 0.400 ;
    END
  END Tile_X0Y5_FrameStrobe[8]
  PIN Tile_X0Y5_FrameStrobe[9]
    DIRECTION INPUT ;
    USE SIGNAL ;
    ANTENNAGATEAREA 0.180700 ;
    ANTENNADIFFAREA 2.015400 ;
    PORT
      LAYER Metal2 ;
        RECT 103.000 0.000 103.400 0.400 ;
    END
  END Tile_X0Y5_FrameStrobe[9]
  PIN Tile_X0Y5_N1END[0]
    DIRECTION INPUT ;
    USE SIGNAL ;
    ANTENNAGATEAREA 1.279200 ;
    PORT
      LAYER Metal2 ;
        RECT 1.240 0.000 1.640 0.400 ;
    END
  END Tile_X0Y5_N1END[0]
  PIN Tile_X0Y5_N1END[1]
    DIRECTION INPUT ;
    USE SIGNAL ;
    ANTENNAGATEAREA 1.279200 ;
    PORT
      LAYER Metal2 ;
        RECT 2.200 0.000 2.600 0.400 ;
    END
  END Tile_X0Y5_N1END[1]
  PIN Tile_X0Y5_N1END[2]
    DIRECTION INPUT ;
    USE SIGNAL ;
    ANTENNAGATEAREA 1.279200 ;
    PORT
      LAYER Metal2 ;
        RECT 3.160 0.000 3.560 0.400 ;
    END
  END Tile_X0Y5_N1END[2]
  PIN Tile_X0Y5_N1END[3]
    DIRECTION INPUT ;
    USE SIGNAL ;
    ANTENNAGATEAREA 1.279200 ;
    PORT
      LAYER Metal2 ;
        RECT 4.120 0.000 4.520 0.400 ;
    END
  END Tile_X0Y5_N1END[3]
  PIN Tile_X0Y5_N2END[0]
    DIRECTION INPUT ;
    USE SIGNAL ;
    ANTENNAGATEAREA 0.213200 ;
    PORT
      LAYER Metal2 ;
        RECT 16.600 0.000 17.000 0.400 ;
    END
  END Tile_X0Y5_N2END[0]
  PIN Tile_X0Y5_N2END[1]
    DIRECTION INPUT ;
    USE SIGNAL ;
    ANTENNAGATEAREA 0.213200 ;
    PORT
      LAYER Metal2 ;
        RECT 17.560 0.000 17.960 0.400 ;
    END
  END Tile_X0Y5_N2END[1]
  PIN Tile_X0Y5_N2END[2]
    DIRECTION INPUT ;
    USE SIGNAL ;
    ANTENNAGATEAREA 0.213200 ;
    PORT
      LAYER Metal2 ;
        RECT 18.520 0.000 18.920 0.400 ;
    END
  END Tile_X0Y5_N2END[2]
  PIN Tile_X0Y5_N2END[3]
    DIRECTION INPUT ;
    USE SIGNAL ;
    ANTENNAGATEAREA 0.213200 ;
    PORT
      LAYER Metal2 ;
        RECT 19.480 0.000 19.880 0.400 ;
    END
  END Tile_X0Y5_N2END[3]
  PIN Tile_X0Y5_N2END[4]
    DIRECTION INPUT ;
    USE SIGNAL ;
    ANTENNAGATEAREA 0.213200 ;
    PORT
      LAYER Metal2 ;
        RECT 20.440 0.000 20.840 0.400 ;
    END
  END Tile_X0Y5_N2END[4]
  PIN Tile_X0Y5_N2END[5]
    DIRECTION INPUT ;
    USE SIGNAL ;
    ANTENNAGATEAREA 0.213200 ;
    PORT
      LAYER Metal2 ;
        RECT 21.400 0.000 21.800 0.400 ;
    END
  END Tile_X0Y5_N2END[5]
  PIN Tile_X0Y5_N2END[6]
    DIRECTION INPUT ;
    USE SIGNAL ;
    ANTENNAGATEAREA 0.213200 ;
    PORT
      LAYER Metal2 ;
        RECT 22.360 0.000 22.760 0.400 ;
    END
  END Tile_X0Y5_N2END[6]
  PIN Tile_X0Y5_N2END[7]
    DIRECTION INPUT ;
    USE SIGNAL ;
    ANTENNAGATEAREA 0.213200 ;
    PORT
      LAYER Metal2 ;
        RECT 23.320 0.000 23.720 0.400 ;
    END
  END Tile_X0Y5_N2END[7]
  PIN Tile_X0Y5_N2MID[0]
    DIRECTION INPUT ;
    USE SIGNAL ;
    ANTENNAGATEAREA 0.426400 ;
    ANTENNADIFFAREA 8.061600 ;
    PORT
      LAYER Metal2 ;
        RECT 7.000 0.000 7.400 0.400 ;
    END
  END Tile_X0Y5_N2MID[0]
  PIN Tile_X0Y5_N2MID[1]
    DIRECTION INPUT ;
    USE SIGNAL ;
    ANTENNAGATEAREA 0.426400 ;
    ANTENNADIFFAREA 4.030800 ;
    PORT
      LAYER Metal2 ;
        RECT 7.960 0.000 8.360 0.400 ;
    END
  END Tile_X0Y5_N2MID[1]
  PIN Tile_X0Y5_N2MID[2]
    DIRECTION INPUT ;
    USE SIGNAL ;
    ANTENNAGATEAREA 0.426400 ;
    ANTENNADIFFAREA 8.061600 ;
    PORT
      LAYER Metal2 ;
        RECT 8.920 0.000 9.320 0.400 ;
    END
  END Tile_X0Y5_N2MID[2]
  PIN Tile_X0Y5_N2MID[3]
    DIRECTION INPUT ;
    USE SIGNAL ;
    ANTENNAGATEAREA 0.426400 ;
    ANTENNADIFFAREA 8.061600 ;
    PORT
      LAYER Metal2 ;
        RECT 9.880 0.000 10.280 0.400 ;
    END
  END Tile_X0Y5_N2MID[3]
  PIN Tile_X0Y5_N2MID[4]
    DIRECTION INPUT ;
    USE SIGNAL ;
    ANTENNAGATEAREA 0.426400 ;
    PORT
      LAYER Metal2 ;
        RECT 10.840 0.000 11.240 0.400 ;
    END
  END Tile_X0Y5_N2MID[4]
  PIN Tile_X0Y5_N2MID[5]
    DIRECTION INPUT ;
    USE SIGNAL ;
    ANTENNAGATEAREA 0.426400 ;
    PORT
      LAYER Metal2 ;
        RECT 11.800 0.000 12.200 0.400 ;
    END
  END Tile_X0Y5_N2MID[5]
  PIN Tile_X0Y5_N2MID[6]
    DIRECTION INPUT ;
    USE SIGNAL ;
    ANTENNAGATEAREA 0.426400 ;
    PORT
      LAYER Metal2 ;
        RECT 12.760 0.000 13.160 0.400 ;
    END
  END Tile_X0Y5_N2MID[6]
  PIN Tile_X0Y5_N2MID[7]
    DIRECTION INPUT ;
    USE SIGNAL ;
    ANTENNAGATEAREA 0.426400 ;
    PORT
      LAYER Metal2 ;
        RECT 13.720 0.000 14.120 0.400 ;
    END
  END Tile_X0Y5_N2MID[7]
  PIN Tile_X0Y5_N4END[0]
    DIRECTION INPUT ;
    USE SIGNAL ;
    ANTENNAGATEAREA 1.066000 ;
    PORT
      LAYER Metal2 ;
        RECT 27.160 0.000 27.560 0.400 ;
    END
  END Tile_X0Y5_N4END[0]
  PIN Tile_X0Y5_N4END[10]
    DIRECTION INPUT ;
    USE SIGNAL ;
    ANTENNAGATEAREA 1.066000 ;
    PORT
      LAYER Metal2 ;
        RECT 36.760 0.000 37.160 0.400 ;
    END
  END Tile_X0Y5_N4END[10]
  PIN Tile_X0Y5_N4END[11]
    DIRECTION INPUT ;
    USE SIGNAL ;
    ANTENNAGATEAREA 1.066000 ;
    PORT
      LAYER Metal2 ;
        RECT 37.720 0.000 38.120 0.400 ;
    END
  END Tile_X0Y5_N4END[11]
  PIN Tile_X0Y5_N4END[12]
    DIRECTION INPUT ;
    USE SIGNAL ;
    ANTENNAGATEAREA 1.066000 ;
    PORT
      LAYER Metal2 ;
        RECT 38.680 0.000 39.080 0.400 ;
    END
  END Tile_X0Y5_N4END[12]
  PIN Tile_X0Y5_N4END[13]
    DIRECTION INPUT ;
    USE SIGNAL ;
    ANTENNAGATEAREA 1.066000 ;
    ANTENNADIFFAREA 40.307999 ;
    PORT
      LAYER Metal2 ;
        RECT 39.640 0.000 40.040 0.400 ;
    END
  END Tile_X0Y5_N4END[13]
  PIN Tile_X0Y5_N4END[14]
    DIRECTION INPUT ;
    USE SIGNAL ;
    ANTENNAGATEAREA 1.066000 ;
    PORT
      LAYER Metal2 ;
        RECT 40.600 0.000 41.000 0.400 ;
    END
  END Tile_X0Y5_N4END[14]
  PIN Tile_X0Y5_N4END[15]
    DIRECTION INPUT ;
    USE SIGNAL ;
    ANTENNAGATEAREA 1.066000 ;
    PORT
      LAYER Metal2 ;
        RECT 41.560 0.000 41.960 0.400 ;
    END
  END Tile_X0Y5_N4END[15]
  PIN Tile_X0Y5_N4END[1]
    DIRECTION INPUT ;
    USE SIGNAL ;
    ANTENNAGATEAREA 1.066000 ;
    PORT
      LAYER Metal2 ;
        RECT 28.120 0.000 28.520 0.400 ;
    END
  END Tile_X0Y5_N4END[1]
  PIN Tile_X0Y5_N4END[2]
    DIRECTION INPUT ;
    USE SIGNAL ;
    ANTENNAGATEAREA 1.066000 ;
    PORT
      LAYER Metal2 ;
        RECT 29.080 0.000 29.480 0.400 ;
    END
  END Tile_X0Y5_N4END[2]
  PIN Tile_X0Y5_N4END[3]
    DIRECTION INPUT ;
    USE SIGNAL ;
    ANTENNAGATEAREA 1.066000 ;
    PORT
      LAYER Metal2 ;
        RECT 30.040 0.000 30.440 0.400 ;
    END
  END Tile_X0Y5_N4END[3]
  PIN Tile_X0Y5_N4END[4]
    DIRECTION INPUT ;
    USE SIGNAL ;
    ANTENNAGATEAREA 1.066000 ;
    ANTENNADIFFAREA 12.092400 ;
    PORT
      LAYER Metal2 ;
        RECT 31.000 0.000 31.400 0.400 ;
    END
  END Tile_X0Y5_N4END[4]
  PIN Tile_X0Y5_N4END[5]
    DIRECTION INPUT ;
    USE SIGNAL ;
    ANTENNAGATEAREA 1.066000 ;
    PORT
      LAYER Metal2 ;
        RECT 31.960 0.000 32.360 0.400 ;
    END
  END Tile_X0Y5_N4END[5]
  PIN Tile_X0Y5_N4END[6]
    DIRECTION INPUT ;
    USE SIGNAL ;
    ANTENNAGATEAREA 1.066000 ;
    PORT
      LAYER Metal2 ;
        RECT 32.920 0.000 33.320 0.400 ;
    END
  END Tile_X0Y5_N4END[6]
  PIN Tile_X0Y5_N4END[7]
    DIRECTION INPUT ;
    USE SIGNAL ;
    ANTENNAGATEAREA 1.066000 ;
    PORT
      LAYER Metal2 ;
        RECT 33.880 0.000 34.280 0.400 ;
    END
  END Tile_X0Y5_N4END[7]
  PIN Tile_X0Y5_N4END[8]
    DIRECTION INPUT ;
    USE SIGNAL ;
    ANTENNAGATEAREA 1.066000 ;
    PORT
      LAYER Metal2 ;
        RECT 34.840 0.000 35.240 0.400 ;
    END
  END Tile_X0Y5_N4END[8]
  PIN Tile_X0Y5_N4END[9]
    DIRECTION INPUT ;
    USE SIGNAL ;
    ANTENNAGATEAREA 1.066000 ;
    PORT
      LAYER Metal2 ;
        RECT 35.800 0.000 36.200 0.400 ;
    END
  END Tile_X0Y5_N4END[9]
  PIN Tile_X0Y5_S1BEG[0]
    DIRECTION OUTPUT ;
    USE SIGNAL ;
    ANTENNADIFFAREA 2.724000 ;
    PORT
      LAYER Metal2 ;
        RECT 46.360 0.000 46.760 0.400 ;
    END
  END Tile_X0Y5_S1BEG[0]
  PIN Tile_X0Y5_S1BEG[1]
    DIRECTION OUTPUT ;
    USE SIGNAL ;
    ANTENNADIFFAREA 2.724000 ;
    PORT
      LAYER Metal2 ;
        RECT 47.320 0.000 47.720 0.400 ;
    END
  END Tile_X0Y5_S1BEG[1]
  PIN Tile_X0Y5_S1BEG[2]
    DIRECTION OUTPUT ;
    USE SIGNAL ;
    ANTENNADIFFAREA 2.724000 ;
    PORT
      LAYER Metal2 ;
        RECT 48.280 0.000 48.680 0.400 ;
    END
  END Tile_X0Y5_S1BEG[2]
  PIN Tile_X0Y5_S1BEG[3]
    DIRECTION OUTPUT ;
    USE SIGNAL ;
    ANTENNADIFFAREA 2.724000 ;
    PORT
      LAYER Metal2 ;
        RECT 49.240 0.000 49.640 0.400 ;
    END
  END Tile_X0Y5_S1BEG[3]
  PIN Tile_X0Y5_S2BEG[0]
    DIRECTION OUTPUT ;
    USE SIGNAL ;
    ANTENNADIFFAREA 2.724000 ;
    PORT
      LAYER Metal2 ;
        RECT 52.120 0.000 52.520 0.400 ;
    END
  END Tile_X0Y5_S2BEG[0]
  PIN Tile_X0Y5_S2BEG[1]
    DIRECTION OUTPUT ;
    USE SIGNAL ;
    ANTENNADIFFAREA 2.724000 ;
    PORT
      LAYER Metal2 ;
        RECT 53.080 0.000 53.480 0.400 ;
    END
  END Tile_X0Y5_S2BEG[1]
  PIN Tile_X0Y5_S2BEG[2]
    DIRECTION OUTPUT ;
    USE SIGNAL ;
    ANTENNADIFFAREA 2.724000 ;
    PORT
      LAYER Metal2 ;
        RECT 54.040 0.000 54.440 0.400 ;
    END
  END Tile_X0Y5_S2BEG[2]
  PIN Tile_X0Y5_S2BEG[3]
    DIRECTION OUTPUT ;
    USE SIGNAL ;
    ANTENNADIFFAREA 2.724000 ;
    PORT
      LAYER Metal2 ;
        RECT 55.000 0.000 55.400 0.400 ;
    END
  END Tile_X0Y5_S2BEG[3]
  PIN Tile_X0Y5_S2BEG[4]
    DIRECTION OUTPUT ;
    USE SIGNAL ;
    ANTENNADIFFAREA 2.724000 ;
    PORT
      LAYER Metal2 ;
        RECT 55.960 0.000 56.360 0.400 ;
    END
  END Tile_X0Y5_S2BEG[4]
  PIN Tile_X0Y5_S2BEG[5]
    DIRECTION OUTPUT ;
    USE SIGNAL ;
    ANTENNADIFFAREA 2.724000 ;
    PORT
      LAYER Metal2 ;
        RECT 56.920 0.000 57.320 0.400 ;
    END
  END Tile_X0Y5_S2BEG[5]
  PIN Tile_X0Y5_S2BEG[6]
    DIRECTION OUTPUT ;
    USE SIGNAL ;
    ANTENNADIFFAREA 2.724000 ;
    PORT
      LAYER Metal2 ;
        RECT 57.880 0.000 58.280 0.400 ;
    END
  END Tile_X0Y5_S2BEG[6]
  PIN Tile_X0Y5_S2BEG[7]
    DIRECTION OUTPUT ;
    USE SIGNAL ;
    ANTENNADIFFAREA 2.724000 ;
    PORT
      LAYER Metal2 ;
        RECT 58.840 0.000 59.240 0.400 ;
    END
  END Tile_X0Y5_S2BEG[7]
  PIN Tile_X0Y5_S2BEGb[0]
    DIRECTION OUTPUT ;
    USE SIGNAL ;
    ANTENNADIFFAREA 2.724000 ;
    PORT
      LAYER Metal2 ;
        RECT 61.720 0.000 62.120 0.400 ;
    END
  END Tile_X0Y5_S2BEGb[0]
  PIN Tile_X0Y5_S2BEGb[1]
    DIRECTION OUTPUT ;
    USE SIGNAL ;
    ANTENNADIFFAREA 2.724000 ;
    PORT
      LAYER Metal2 ;
        RECT 62.680 0.000 63.080 0.400 ;
    END
  END Tile_X0Y5_S2BEGb[1]
  PIN Tile_X0Y5_S2BEGb[2]
    DIRECTION OUTPUT ;
    USE SIGNAL ;
    ANTENNADIFFAREA 2.724000 ;
    PORT
      LAYER Metal2 ;
        RECT 63.640 0.000 64.040 0.400 ;
    END
  END Tile_X0Y5_S2BEGb[2]
  PIN Tile_X0Y5_S2BEGb[3]
    DIRECTION OUTPUT ;
    USE SIGNAL ;
    ANTENNADIFFAREA 2.724000 ;
    PORT
      LAYER Metal2 ;
        RECT 64.600 0.000 65.000 0.400 ;
    END
  END Tile_X0Y5_S2BEGb[3]
  PIN Tile_X0Y5_S2BEGb[4]
    DIRECTION OUTPUT ;
    USE SIGNAL ;
    ANTENNADIFFAREA 2.724000 ;
    PORT
      LAYER Metal2 ;
        RECT 65.560 0.000 65.960 0.400 ;
    END
  END Tile_X0Y5_S2BEGb[4]
  PIN Tile_X0Y5_S2BEGb[5]
    DIRECTION OUTPUT ;
    USE SIGNAL ;
    ANTENNADIFFAREA 2.724000 ;
    PORT
      LAYER Metal2 ;
        RECT 66.520 0.000 66.920 0.400 ;
    END
  END Tile_X0Y5_S2BEGb[5]
  PIN Tile_X0Y5_S2BEGb[6]
    DIRECTION OUTPUT ;
    USE SIGNAL ;
    ANTENNADIFFAREA 2.724000 ;
    PORT
      LAYER Metal2 ;
        RECT 67.480 0.000 67.880 0.400 ;
    END
  END Tile_X0Y5_S2BEGb[6]
  PIN Tile_X0Y5_S2BEGb[7]
    DIRECTION OUTPUT ;
    USE SIGNAL ;
    ANTENNADIFFAREA 2.724000 ;
    PORT
      LAYER Metal2 ;
        RECT 68.440 0.000 68.840 0.400 ;
    END
  END Tile_X0Y5_S2BEGb[7]
  PIN Tile_X0Y5_S4BEG[0]
    DIRECTION OUTPUT ;
    USE SIGNAL ;
    ANTENNADIFFAREA 2.724000 ;
    PORT
      LAYER Metal2 ;
        RECT 73.240 0.000 73.640 0.400 ;
    END
  END Tile_X0Y5_S4BEG[0]
  PIN Tile_X0Y5_S4BEG[10]
    DIRECTION OUTPUT ;
    USE SIGNAL ;
    ANTENNADIFFAREA 2.724000 ;
    PORT
      LAYER Metal2 ;
        RECT 82.840 0.000 83.240 0.400 ;
    END
  END Tile_X0Y5_S4BEG[10]
  PIN Tile_X0Y5_S4BEG[11]
    DIRECTION OUTPUT ;
    USE SIGNAL ;
    ANTENNADIFFAREA 2.724000 ;
    PORT
      LAYER Metal2 ;
        RECT 83.800 0.000 84.200 0.400 ;
    END
  END Tile_X0Y5_S4BEG[11]
  PIN Tile_X0Y5_S4BEG[12]
    DIRECTION OUTPUT ;
    USE SIGNAL ;
    ANTENNADIFFAREA 2.724000 ;
    PORT
      LAYER Metal2 ;
        RECT 84.760 0.000 85.160 0.400 ;
    END
  END Tile_X0Y5_S4BEG[12]
  PIN Tile_X0Y5_S4BEG[13]
    DIRECTION OUTPUT ;
    USE SIGNAL ;
    ANTENNADIFFAREA 2.724000 ;
    PORT
      LAYER Metal2 ;
        RECT 85.720 0.000 86.120 0.400 ;
    END
  END Tile_X0Y5_S4BEG[13]
  PIN Tile_X0Y5_S4BEG[14]
    DIRECTION OUTPUT ;
    USE SIGNAL ;
    ANTENNADIFFAREA 2.724000 ;
    PORT
      LAYER Metal2 ;
        RECT 86.680 0.000 87.080 0.400 ;
    END
  END Tile_X0Y5_S4BEG[14]
  PIN Tile_X0Y5_S4BEG[15]
    DIRECTION OUTPUT ;
    USE SIGNAL ;
    ANTENNADIFFAREA 2.724000 ;
    PORT
      LAYER Metal2 ;
        RECT 87.640 0.000 88.040 0.400 ;
    END
  END Tile_X0Y5_S4BEG[15]
  PIN Tile_X0Y5_S4BEG[1]
    DIRECTION OUTPUT ;
    USE SIGNAL ;
    ANTENNADIFFAREA 2.724000 ;
    PORT
      LAYER Metal2 ;
        RECT 74.200 0.000 74.600 0.400 ;
    END
  END Tile_X0Y5_S4BEG[1]
  PIN Tile_X0Y5_S4BEG[2]
    DIRECTION OUTPUT ;
    USE SIGNAL ;
    ANTENNADIFFAREA 2.724000 ;
    PORT
      LAYER Metal2 ;
        RECT 75.160 0.000 75.560 0.400 ;
    END
  END Tile_X0Y5_S4BEG[2]
  PIN Tile_X0Y5_S4BEG[3]
    DIRECTION OUTPUT ;
    USE SIGNAL ;
    ANTENNADIFFAREA 2.724000 ;
    PORT
      LAYER Metal2 ;
        RECT 76.120 0.000 76.520 0.400 ;
    END
  END Tile_X0Y5_S4BEG[3]
  PIN Tile_X0Y5_S4BEG[4]
    DIRECTION OUTPUT ;
    USE SIGNAL ;
    ANTENNADIFFAREA 2.724000 ;
    PORT
      LAYER Metal2 ;
        RECT 77.080 0.000 77.480 0.400 ;
    END
  END Tile_X0Y5_S4BEG[4]
  PIN Tile_X0Y5_S4BEG[5]
    DIRECTION OUTPUT ;
    USE SIGNAL ;
    ANTENNADIFFAREA 2.724000 ;
    PORT
      LAYER Metal2 ;
        RECT 78.040 0.000 78.440 0.400 ;
    END
  END Tile_X0Y5_S4BEG[5]
  PIN Tile_X0Y5_S4BEG[6]
    DIRECTION OUTPUT ;
    USE SIGNAL ;
    ANTENNADIFFAREA 2.724000 ;
    PORT
      LAYER Metal2 ;
        RECT 79.000 0.000 79.400 0.400 ;
    END
  END Tile_X0Y5_S4BEG[6]
  PIN Tile_X0Y5_S4BEG[7]
    DIRECTION OUTPUT ;
    USE SIGNAL ;
    ANTENNADIFFAREA 2.724000 ;
    PORT
      LAYER Metal2 ;
        RECT 79.960 0.000 80.360 0.400 ;
    END
  END Tile_X0Y5_S4BEG[7]
  PIN Tile_X0Y5_S4BEG[8]
    DIRECTION OUTPUT ;
    USE SIGNAL ;
    ANTENNADIFFAREA 2.724000 ;
    PORT
      LAYER Metal2 ;
        RECT 80.920 0.000 81.320 0.400 ;
    END
  END Tile_X0Y5_S4BEG[8]
  PIN Tile_X0Y5_S4BEG[9]
    DIRECTION OUTPUT ;
    USE SIGNAL ;
    ANTENNADIFFAREA 2.724000 ;
    PORT
      LAYER Metal2 ;
        RECT 81.880 0.000 82.280 0.400 ;
    END
  END Tile_X0Y5_S4BEG[9]
  PIN Tile_X0Y5_UserCLK
    DIRECTION INPUT ;
    USE SIGNAL ;
    ANTENNAGATEAREA 0.180700 ;
    PORT
      LAYER Metal3 ;
        RECT 0.000 1.060 0.400 1.460 ;
    END
  END Tile_X0Y5_UserCLK
  PIN Tile_X0Y5_UserCLKo
    DIRECTION OUTPUT ;
    USE SIGNAL ;
    ANTENNADIFFAREA 2.724000 ;
    PORT
      LAYER Metal3 ;
        RECT 115.280 203.500 115.680 203.900 ;
    END
  END Tile_X0Y5_UserCLKo
  PIN Tile_X0Y5_W1END[0]
    DIRECTION INPUT ;
    USE SIGNAL ;
    ANTENNAGATEAREA 1.066000 ;
    PORT
      LAYER Metal3 ;
        RECT 115.280 102.700 115.680 103.100 ;
    END
  END Tile_X0Y5_W1END[0]
  PIN Tile_X0Y5_W1END[1]
    DIRECTION INPUT ;
    USE SIGNAL ;
    ANTENNAGATEAREA 1.066000 ;
    PORT
      LAYER Metal3 ;
        RECT 115.280 104.380 115.680 104.780 ;
    END
  END Tile_X0Y5_W1END[1]
  PIN Tile_X0Y5_W1END[2]
    DIRECTION INPUT ;
    USE SIGNAL ;
    ANTENNAGATEAREA 1.066000 ;
    PORT
      LAYER Metal3 ;
        RECT 115.280 106.060 115.680 106.460 ;
    END
  END Tile_X0Y5_W1END[2]
  PIN Tile_X0Y5_W1END[3]
    DIRECTION INPUT ;
    USE SIGNAL ;
    ANTENNAGATEAREA 1.066000 ;
    PORT
      LAYER Metal3 ;
        RECT 115.280 107.740 115.680 108.140 ;
    END
  END Tile_X0Y5_W1END[3]
  PIN Tile_X0Y5_W2END[0]
    DIRECTION INPUT ;
    USE SIGNAL ;
    ANTENNAGATEAREA 0.639600 ;
    PORT
      LAYER Metal3 ;
        RECT 115.280 128.740 115.680 129.140 ;
    END
  END Tile_X0Y5_W2END[0]
  PIN Tile_X0Y5_W2END[1]
    DIRECTION INPUT ;
    USE SIGNAL ;
    ANTENNAGATEAREA 0.639600 ;
    PORT
      LAYER Metal3 ;
        RECT 115.280 130.420 115.680 130.820 ;
    END
  END Tile_X0Y5_W2END[1]
  PIN Tile_X0Y5_W2END[2]
    DIRECTION INPUT ;
    USE SIGNAL ;
    ANTENNAGATEAREA 0.639600 ;
    PORT
      LAYER Metal3 ;
        RECT 115.280 132.100 115.680 132.500 ;
    END
  END Tile_X0Y5_W2END[2]
  PIN Tile_X0Y5_W2END[3]
    DIRECTION INPUT ;
    USE SIGNAL ;
    ANTENNAGATEAREA 0.639600 ;
    PORT
      LAYER Metal3 ;
        RECT 115.280 133.780 115.680 134.180 ;
    END
  END Tile_X0Y5_W2END[3]
  PIN Tile_X0Y5_W2END[4]
    DIRECTION INPUT ;
    USE SIGNAL ;
    ANTENNAGATEAREA 0.426400 ;
    PORT
      LAYER Metal3 ;
        RECT 115.280 135.460 115.680 135.860 ;
    END
  END Tile_X0Y5_W2END[4]
  PIN Tile_X0Y5_W2END[5]
    DIRECTION INPUT ;
    USE SIGNAL ;
    ANTENNAGATEAREA 0.426400 ;
    PORT
      LAYER Metal3 ;
        RECT 115.280 137.140 115.680 137.540 ;
    END
  END Tile_X0Y5_W2END[5]
  PIN Tile_X0Y5_W2END[6]
    DIRECTION INPUT ;
    USE SIGNAL ;
    ANTENNAGATEAREA 0.426400 ;
    PORT
      LAYER Metal3 ;
        RECT 115.280 138.820 115.680 139.220 ;
    END
  END Tile_X0Y5_W2END[6]
  PIN Tile_X0Y5_W2END[7]
    DIRECTION INPUT ;
    USE SIGNAL ;
    ANTENNAGATEAREA 0.426400 ;
    PORT
      LAYER Metal3 ;
        RECT 115.280 140.500 115.680 140.900 ;
    END
  END Tile_X0Y5_W2END[7]
  PIN Tile_X0Y5_W2MID[0]
    DIRECTION INPUT ;
    USE SIGNAL ;
    ANTENNAGATEAREA 0.639600 ;
    PORT
      LAYER Metal3 ;
        RECT 115.280 111.940 115.680 112.340 ;
    END
  END Tile_X0Y5_W2MID[0]
  PIN Tile_X0Y5_W2MID[1]
    DIRECTION INPUT ;
    USE SIGNAL ;
    ANTENNAGATEAREA 0.639600 ;
    PORT
      LAYER Metal3 ;
        RECT 115.280 113.620 115.680 114.020 ;
    END
  END Tile_X0Y5_W2MID[1]
  PIN Tile_X0Y5_W2MID[2]
    DIRECTION INPUT ;
    USE SIGNAL ;
    ANTENNAGATEAREA 0.639600 ;
    PORT
      LAYER Metal3 ;
        RECT 115.280 115.300 115.680 115.700 ;
    END
  END Tile_X0Y5_W2MID[2]
  PIN Tile_X0Y5_W2MID[3]
    DIRECTION INPUT ;
    USE SIGNAL ;
    ANTENNAGATEAREA 0.639600 ;
    PORT
      LAYER Metal3 ;
        RECT 115.280 116.980 115.680 117.380 ;
    END
  END Tile_X0Y5_W2MID[3]
  PIN Tile_X0Y5_W2MID[4]
    DIRECTION INPUT ;
    USE SIGNAL ;
    ANTENNAGATEAREA 0.426400 ;
    PORT
      LAYER Metal3 ;
        RECT 115.280 118.660 115.680 119.060 ;
    END
  END Tile_X0Y5_W2MID[4]
  PIN Tile_X0Y5_W2MID[5]
    DIRECTION INPUT ;
    USE SIGNAL ;
    ANTENNAGATEAREA 0.426400 ;
    PORT
      LAYER Metal3 ;
        RECT 115.280 120.340 115.680 120.740 ;
    END
  END Tile_X0Y5_W2MID[5]
  PIN Tile_X0Y5_W2MID[6]
    DIRECTION INPUT ;
    USE SIGNAL ;
    ANTENNAGATEAREA 0.426400 ;
    PORT
      LAYER Metal3 ;
        RECT 115.280 122.020 115.680 122.420 ;
    END
  END Tile_X0Y5_W2MID[6]
  PIN Tile_X0Y5_W2MID[7]
    DIRECTION INPUT ;
    USE SIGNAL ;
    ANTENNAGATEAREA 0.426400 ;
    PORT
      LAYER Metal3 ;
        RECT 115.280 123.700 115.680 124.100 ;
    END
  END Tile_X0Y5_W2MID[7]
  PIN Tile_X0Y5_W6END[0]
    DIRECTION INPUT ;
    USE SIGNAL ;
    ANTENNAGATEAREA 0.639600 ;
    PORT
      LAYER Metal3 ;
        RECT 115.280 179.980 115.680 180.380 ;
    END
  END Tile_X0Y5_W6END[0]
  PIN Tile_X0Y5_W6END[10]
    DIRECTION INPUT ;
    USE SIGNAL ;
    ANTENNAGATEAREA 0.639600 ;
    PORT
      LAYER Metal3 ;
        RECT 115.280 196.780 115.680 197.180 ;
    END
  END Tile_X0Y5_W6END[10]
  PIN Tile_X0Y5_W6END[11]
    DIRECTION INPUT ;
    USE SIGNAL ;
    ANTENNAGATEAREA 0.639600 ;
    PORT
      LAYER Metal3 ;
        RECT 115.280 198.460 115.680 198.860 ;
    END
  END Tile_X0Y5_W6END[11]
  PIN Tile_X0Y5_W6END[1]
    DIRECTION INPUT ;
    USE SIGNAL ;
    ANTENNAGATEAREA 0.639600 ;
    PORT
      LAYER Metal3 ;
        RECT 115.280 181.660 115.680 182.060 ;
    END
  END Tile_X0Y5_W6END[1]
  PIN Tile_X0Y5_W6END[2]
    DIRECTION INPUT ;
    USE SIGNAL ;
    ANTENNAGATEAREA 0.639600 ;
    PORT
      LAYER Metal3 ;
        RECT 115.280 183.340 115.680 183.740 ;
    END
  END Tile_X0Y5_W6END[2]
  PIN Tile_X0Y5_W6END[3]
    DIRECTION INPUT ;
    USE SIGNAL ;
    ANTENNAGATEAREA 0.639600 ;
    PORT
      LAYER Metal3 ;
        RECT 115.280 185.020 115.680 185.420 ;
    END
  END Tile_X0Y5_W6END[3]
  PIN Tile_X0Y5_W6END[4]
    DIRECTION INPUT ;
    USE SIGNAL ;
    ANTENNAGATEAREA 0.639600 ;
    PORT
      LAYER Metal3 ;
        RECT 115.280 186.700 115.680 187.100 ;
    END
  END Tile_X0Y5_W6END[4]
  PIN Tile_X0Y5_W6END[5]
    DIRECTION INPUT ;
    USE SIGNAL ;
    ANTENNAGATEAREA 0.639600 ;
    PORT
      LAYER Metal3 ;
        RECT 115.280 188.380 115.680 188.780 ;
    END
  END Tile_X0Y5_W6END[5]
  PIN Tile_X0Y5_W6END[6]
    DIRECTION INPUT ;
    USE SIGNAL ;
    ANTENNAGATEAREA 0.639600 ;
    PORT
      LAYER Metal3 ;
        RECT 115.280 190.060 115.680 190.460 ;
    END
  END Tile_X0Y5_W6END[6]
  PIN Tile_X0Y5_W6END[7]
    DIRECTION INPUT ;
    USE SIGNAL ;
    ANTENNAGATEAREA 0.639600 ;
    PORT
      LAYER Metal3 ;
        RECT 115.280 191.740 115.680 192.140 ;
    END
  END Tile_X0Y5_W6END[7]
  PIN Tile_X0Y5_W6END[8]
    DIRECTION INPUT ;
    USE SIGNAL ;
    ANTENNAGATEAREA 0.639600 ;
    PORT
      LAYER Metal3 ;
        RECT 115.280 193.420 115.680 193.820 ;
    END
  END Tile_X0Y5_W6END[8]
  PIN Tile_X0Y5_W6END[9]
    DIRECTION INPUT ;
    USE SIGNAL ;
    ANTENNAGATEAREA 0.639600 ;
    PORT
      LAYER Metal3 ;
        RECT 115.280 195.100 115.680 195.500 ;
    END
  END Tile_X0Y5_W6END[9]
  PIN Tile_X0Y5_WW4END[0]
    DIRECTION INPUT ;
    USE SIGNAL ;
    ANTENNAGATEAREA 0.213200 ;
    PORT
      LAYER Metal3 ;
        RECT 115.280 147.220 115.680 147.620 ;
    END
  END Tile_X0Y5_WW4END[0]
  PIN Tile_X0Y5_WW4END[10]
    DIRECTION INPUT ;
    USE SIGNAL ;
    ANTENNAGATEAREA 0.213200 ;
    PORT
      LAYER Metal3 ;
        RECT 115.280 164.020 115.680 164.420 ;
    END
  END Tile_X0Y5_WW4END[10]
  PIN Tile_X0Y5_WW4END[11]
    DIRECTION INPUT ;
    USE SIGNAL ;
    ANTENNAGATEAREA 0.213200 ;
    PORT
      LAYER Metal3 ;
        RECT 115.280 165.700 115.680 166.100 ;
    END
  END Tile_X0Y5_WW4END[11]
  PIN Tile_X0Y5_WW4END[12]
    DIRECTION INPUT ;
    USE SIGNAL ;
    ANTENNAGATEAREA 0.213200 ;
    PORT
      LAYER Metal3 ;
        RECT 115.280 167.380 115.680 167.780 ;
    END
  END Tile_X0Y5_WW4END[12]
  PIN Tile_X0Y5_WW4END[13]
    DIRECTION INPUT ;
    USE SIGNAL ;
    ANTENNAGATEAREA 0.213200 ;
    PORT
      LAYER Metal3 ;
        RECT 115.280 169.060 115.680 169.460 ;
    END
  END Tile_X0Y5_WW4END[13]
  PIN Tile_X0Y5_WW4END[14]
    DIRECTION INPUT ;
    USE SIGNAL ;
    ANTENNAGATEAREA 0.213200 ;
    PORT
      LAYER Metal3 ;
        RECT 115.280 170.740 115.680 171.140 ;
    END
  END Tile_X0Y5_WW4END[14]
  PIN Tile_X0Y5_WW4END[15]
    DIRECTION INPUT ;
    USE SIGNAL ;
    ANTENNAGATEAREA 0.213200 ;
    PORT
      LAYER Metal3 ;
        RECT 115.280 172.420 115.680 172.820 ;
    END
  END Tile_X0Y5_WW4END[15]
  PIN Tile_X0Y5_WW4END[1]
    DIRECTION INPUT ;
    USE SIGNAL ;
    ANTENNAGATEAREA 0.213200 ;
    PORT
      LAYER Metal3 ;
        RECT 115.280 148.900 115.680 149.300 ;
    END
  END Tile_X0Y5_WW4END[1]
  PIN Tile_X0Y5_WW4END[2]
    DIRECTION INPUT ;
    USE SIGNAL ;
    ANTENNAGATEAREA 0.213200 ;
    PORT
      LAYER Metal3 ;
        RECT 115.280 150.580 115.680 150.980 ;
    END
  END Tile_X0Y5_WW4END[2]
  PIN Tile_X0Y5_WW4END[3]
    DIRECTION INPUT ;
    USE SIGNAL ;
    ANTENNAGATEAREA 0.213200 ;
    PORT
      LAYER Metal3 ;
        RECT 115.280 152.260 115.680 152.660 ;
    END
  END Tile_X0Y5_WW4END[3]
  PIN Tile_X0Y5_WW4END[4]
    DIRECTION INPUT ;
    USE SIGNAL ;
    ANTENNAGATEAREA 0.213200 ;
    PORT
      LAYER Metal3 ;
        RECT 115.280 153.940 115.680 154.340 ;
    END
  END Tile_X0Y5_WW4END[4]
  PIN Tile_X0Y5_WW4END[5]
    DIRECTION INPUT ;
    USE SIGNAL ;
    ANTENNAGATEAREA 0.213200 ;
    PORT
      LAYER Metal3 ;
        RECT 115.280 155.620 115.680 156.020 ;
    END
  END Tile_X0Y5_WW4END[5]
  PIN Tile_X0Y5_WW4END[6]
    DIRECTION INPUT ;
    USE SIGNAL ;
    ANTENNAGATEAREA 0.213200 ;
    PORT
      LAYER Metal3 ;
        RECT 115.280 157.300 115.680 157.700 ;
    END
  END Tile_X0Y5_WW4END[6]
  PIN Tile_X0Y5_WW4END[7]
    DIRECTION INPUT ;
    USE SIGNAL ;
    ANTENNAGATEAREA 0.213200 ;
    PORT
      LAYER Metal3 ;
        RECT 115.280 158.980 115.680 159.380 ;
    END
  END Tile_X0Y5_WW4END[7]
  PIN Tile_X0Y5_WW4END[8]
    DIRECTION INPUT ;
    USE SIGNAL ;
    ANTENNAGATEAREA 0.213200 ;
    PORT
      LAYER Metal3 ;
        RECT 115.280 160.660 115.680 161.060 ;
    END
  END Tile_X0Y5_WW4END[8]
  PIN Tile_X0Y5_WW4END[9]
    DIRECTION INPUT ;
    USE SIGNAL ;
    ANTENNAGATEAREA 0.213200 ;
    PORT
      LAYER Metal3 ;
        RECT 115.280 162.340 115.680 162.740 ;
    END
  END Tile_X0Y5_WW4END[9]
  PIN VGND
    DIRECTION INOUT ;
    USE GROUND ;
    PORT
      LAYER Metal4 ;
        RECT 15.380 0.000 16.380 1632.960 ;
    END
    PORT
      LAYER Metal4 ;
        RECT 65.380 0.000 66.380 1632.960 ;
    END
  END VGND
  PIN VPWR
    DIRECTION INOUT ;
    USE POWER ;
    PORT
      LAYER Metal4 ;
        RECT 12.380 0.000 13.380 1632.960 ;
    END
    PORT
      LAYER Metal4 ;
        RECT 62.380 0.000 63.380 1632.960 ;
    END
  END VPWR
  OBS
      LAYER GatPoly ;
        RECT 2.880 3.630 112.800 1629.330 ;
      LAYER Metal1 ;
        RECT 2.880 3.560 112.800 1629.400 ;
      LAYER Metal2 ;
        RECT 0.375 1632.350 1.030 1632.685 ;
        RECT 1.850 1632.350 1.990 1632.685 ;
        RECT 2.810 1632.350 2.950 1632.685 ;
        RECT 3.770 1632.350 3.910 1632.685 ;
        RECT 4.730 1632.350 6.790 1632.685 ;
        RECT 7.610 1632.350 7.750 1632.685 ;
        RECT 8.570 1632.350 8.710 1632.685 ;
        RECT 9.530 1632.350 9.670 1632.685 ;
        RECT 10.490 1632.350 10.630 1632.685 ;
        RECT 11.450 1632.350 11.590 1632.685 ;
        RECT 12.410 1632.350 12.550 1632.685 ;
        RECT 13.370 1632.350 13.510 1632.685 ;
        RECT 14.330 1632.350 16.390 1632.685 ;
        RECT 17.210 1632.350 17.350 1632.685 ;
        RECT 18.170 1632.350 18.310 1632.685 ;
        RECT 19.130 1632.350 19.270 1632.685 ;
        RECT 20.090 1632.350 20.230 1632.685 ;
        RECT 21.050 1632.350 21.190 1632.685 ;
        RECT 22.010 1632.350 22.150 1632.685 ;
        RECT 22.970 1632.350 23.110 1632.685 ;
        RECT 23.930 1632.350 26.950 1632.685 ;
        RECT 27.770 1632.350 27.910 1632.685 ;
        RECT 28.730 1632.350 28.870 1632.685 ;
        RECT 29.690 1632.350 29.830 1632.685 ;
        RECT 30.650 1632.350 30.790 1632.685 ;
        RECT 31.610 1632.350 31.750 1632.685 ;
        RECT 32.570 1632.350 32.710 1632.685 ;
        RECT 33.530 1632.350 33.670 1632.685 ;
        RECT 34.490 1632.350 34.630 1632.685 ;
        RECT 35.450 1632.350 35.590 1632.685 ;
        RECT 36.410 1632.350 36.550 1632.685 ;
        RECT 37.370 1632.350 37.510 1632.685 ;
        RECT 38.330 1632.350 38.470 1632.685 ;
        RECT 39.290 1632.350 39.430 1632.685 ;
        RECT 40.250 1632.350 40.390 1632.685 ;
        RECT 41.210 1632.350 41.350 1632.685 ;
        RECT 42.170 1632.350 46.150 1632.685 ;
        RECT 46.970 1632.350 47.110 1632.685 ;
        RECT 47.930 1632.350 48.070 1632.685 ;
        RECT 48.890 1632.350 49.030 1632.685 ;
        RECT 49.850 1632.350 51.910 1632.685 ;
        RECT 52.730 1632.350 52.870 1632.685 ;
        RECT 53.690 1632.350 53.830 1632.685 ;
        RECT 54.650 1632.350 54.790 1632.685 ;
        RECT 55.610 1632.350 55.750 1632.685 ;
        RECT 56.570 1632.350 56.710 1632.685 ;
        RECT 57.530 1632.350 57.670 1632.685 ;
        RECT 58.490 1632.350 58.630 1632.685 ;
        RECT 59.450 1632.350 61.510 1632.685 ;
        RECT 62.330 1632.350 62.470 1632.685 ;
        RECT 63.290 1632.350 63.430 1632.685 ;
        RECT 64.250 1632.350 64.390 1632.685 ;
        RECT 65.210 1632.350 65.350 1632.685 ;
        RECT 66.170 1632.350 66.310 1632.685 ;
        RECT 67.130 1632.350 67.270 1632.685 ;
        RECT 68.090 1632.350 68.230 1632.685 ;
        RECT 69.050 1632.350 73.030 1632.685 ;
        RECT 73.850 1632.350 73.990 1632.685 ;
        RECT 74.810 1632.350 74.950 1632.685 ;
        RECT 75.770 1632.350 75.910 1632.685 ;
        RECT 76.730 1632.350 76.870 1632.685 ;
        RECT 77.690 1632.350 77.830 1632.685 ;
        RECT 78.650 1632.350 78.790 1632.685 ;
        RECT 79.610 1632.350 79.750 1632.685 ;
        RECT 80.570 1632.350 80.710 1632.685 ;
        RECT 81.530 1632.350 81.670 1632.685 ;
        RECT 82.490 1632.350 82.630 1632.685 ;
        RECT 83.450 1632.350 83.590 1632.685 ;
        RECT 84.410 1632.350 84.550 1632.685 ;
        RECT 85.370 1632.350 85.510 1632.685 ;
        RECT 86.330 1632.350 86.470 1632.685 ;
        RECT 87.290 1632.350 87.430 1632.685 ;
        RECT 88.250 1632.350 94.150 1632.685 ;
        RECT 94.970 1632.350 95.110 1632.685 ;
        RECT 95.930 1632.350 96.070 1632.685 ;
        RECT 96.890 1632.350 97.030 1632.685 ;
        RECT 97.850 1632.350 97.990 1632.685 ;
        RECT 98.810 1632.350 98.950 1632.685 ;
        RECT 99.770 1632.350 99.910 1632.685 ;
        RECT 100.730 1632.350 100.870 1632.685 ;
        RECT 101.690 1632.350 101.830 1632.685 ;
        RECT 102.650 1632.350 102.790 1632.685 ;
        RECT 103.610 1632.350 103.750 1632.685 ;
        RECT 104.570 1632.350 104.710 1632.685 ;
        RECT 105.530 1632.350 105.670 1632.685 ;
        RECT 106.490 1632.350 106.630 1632.685 ;
        RECT 107.450 1632.350 107.590 1632.685 ;
        RECT 108.410 1632.350 108.550 1632.685 ;
        RECT 109.370 1632.350 109.510 1632.685 ;
        RECT 110.330 1632.350 110.470 1632.685 ;
        RECT 111.290 1632.350 111.430 1632.685 ;
        RECT 112.250 1632.350 112.390 1632.685 ;
        RECT 113.210 1632.350 115.305 1632.685 ;
        RECT 0.375 0.610 115.305 1632.350 ;
        RECT 0.375 0.320 1.030 0.610 ;
        RECT 1.850 0.320 1.990 0.610 ;
        RECT 2.810 0.320 2.950 0.610 ;
        RECT 3.770 0.320 3.910 0.610 ;
        RECT 4.730 0.320 6.790 0.610 ;
        RECT 7.610 0.320 7.750 0.610 ;
        RECT 8.570 0.320 8.710 0.610 ;
        RECT 9.530 0.320 9.670 0.610 ;
        RECT 10.490 0.320 10.630 0.610 ;
        RECT 11.450 0.320 11.590 0.610 ;
        RECT 12.410 0.320 12.550 0.610 ;
        RECT 13.370 0.320 13.510 0.610 ;
        RECT 14.330 0.320 16.390 0.610 ;
        RECT 17.210 0.320 17.350 0.610 ;
        RECT 18.170 0.320 18.310 0.610 ;
        RECT 19.130 0.320 19.270 0.610 ;
        RECT 20.090 0.320 20.230 0.610 ;
        RECT 21.050 0.320 21.190 0.610 ;
        RECT 22.010 0.320 22.150 0.610 ;
        RECT 22.970 0.320 23.110 0.610 ;
        RECT 23.930 0.320 26.950 0.610 ;
        RECT 27.770 0.320 27.910 0.610 ;
        RECT 28.730 0.320 28.870 0.610 ;
        RECT 29.690 0.320 29.830 0.610 ;
        RECT 30.650 0.320 30.790 0.610 ;
        RECT 31.610 0.320 31.750 0.610 ;
        RECT 32.570 0.320 32.710 0.610 ;
        RECT 33.530 0.320 33.670 0.610 ;
        RECT 34.490 0.320 34.630 0.610 ;
        RECT 35.450 0.320 35.590 0.610 ;
        RECT 36.410 0.320 36.550 0.610 ;
        RECT 37.370 0.320 37.510 0.610 ;
        RECT 38.330 0.320 38.470 0.610 ;
        RECT 39.290 0.320 39.430 0.610 ;
        RECT 40.250 0.320 40.390 0.610 ;
        RECT 41.210 0.320 41.350 0.610 ;
        RECT 42.170 0.320 46.150 0.610 ;
        RECT 46.970 0.320 47.110 0.610 ;
        RECT 47.930 0.320 48.070 0.610 ;
        RECT 48.890 0.320 49.030 0.610 ;
        RECT 49.850 0.320 51.910 0.610 ;
        RECT 52.730 0.320 52.870 0.610 ;
        RECT 53.690 0.320 53.830 0.610 ;
        RECT 54.650 0.320 54.790 0.610 ;
        RECT 55.610 0.320 55.750 0.610 ;
        RECT 56.570 0.320 56.710 0.610 ;
        RECT 57.530 0.320 57.670 0.610 ;
        RECT 58.490 0.320 58.630 0.610 ;
        RECT 59.450 0.320 61.510 0.610 ;
        RECT 62.330 0.320 62.470 0.610 ;
        RECT 63.290 0.320 63.430 0.610 ;
        RECT 64.250 0.320 64.390 0.610 ;
        RECT 65.210 0.320 65.350 0.610 ;
        RECT 66.170 0.320 66.310 0.610 ;
        RECT 67.130 0.320 67.270 0.610 ;
        RECT 68.090 0.320 68.230 0.610 ;
        RECT 69.050 0.320 73.030 0.610 ;
        RECT 73.850 0.320 73.990 0.610 ;
        RECT 74.810 0.320 74.950 0.610 ;
        RECT 75.770 0.320 75.910 0.610 ;
        RECT 76.730 0.320 76.870 0.610 ;
        RECT 77.690 0.320 77.830 0.610 ;
        RECT 78.650 0.320 78.790 0.610 ;
        RECT 79.610 0.320 79.750 0.610 ;
        RECT 80.570 0.320 80.710 0.610 ;
        RECT 81.530 0.320 81.670 0.610 ;
        RECT 82.490 0.320 82.630 0.610 ;
        RECT 83.450 0.320 83.590 0.610 ;
        RECT 84.410 0.320 84.550 0.610 ;
        RECT 85.370 0.320 85.510 0.610 ;
        RECT 86.330 0.320 86.470 0.610 ;
        RECT 87.290 0.320 87.430 0.610 ;
        RECT 88.250 0.320 94.150 0.610 ;
        RECT 94.970 0.320 95.110 0.610 ;
        RECT 95.930 0.320 96.070 0.610 ;
        RECT 96.890 0.320 97.030 0.610 ;
        RECT 97.850 0.320 97.990 0.610 ;
        RECT 98.810 0.320 98.950 0.610 ;
        RECT 99.770 0.320 99.910 0.610 ;
        RECT 100.730 0.320 100.870 0.610 ;
        RECT 101.690 0.320 101.830 0.610 ;
        RECT 102.650 0.320 102.790 0.610 ;
        RECT 103.610 0.320 103.750 0.610 ;
        RECT 104.570 0.320 104.710 0.610 ;
        RECT 105.530 0.320 105.670 0.610 ;
        RECT 106.490 0.320 106.630 0.610 ;
        RECT 107.450 0.320 107.590 0.610 ;
        RECT 108.410 0.320 108.550 0.610 ;
        RECT 109.370 0.320 109.510 0.610 ;
        RECT 110.330 0.320 110.470 0.610 ;
        RECT 111.290 0.320 111.430 0.610 ;
        RECT 112.250 0.320 112.390 0.610 ;
        RECT 113.210 0.320 115.305 0.610 ;
      LAYER Metal3 ;
        RECT 0.335 1625.390 115.345 1632.645 ;
        RECT 0.335 1624.570 115.070 1625.390 ;
        RECT 0.335 1623.710 115.345 1624.570 ;
        RECT 0.335 1622.890 115.070 1623.710 ;
        RECT 0.335 1622.030 115.345 1622.890 ;
        RECT 0.335 1621.210 115.070 1622.030 ;
        RECT 0.335 1620.350 115.345 1621.210 ;
        RECT 0.335 1619.530 115.070 1620.350 ;
        RECT 0.335 1618.670 115.345 1619.530 ;
        RECT 0.610 1617.850 115.070 1618.670 ;
        RECT 0.335 1616.990 115.345 1617.850 ;
        RECT 0.335 1616.170 115.070 1616.990 ;
        RECT 0.335 1615.310 115.345 1616.170 ;
        RECT 0.335 1614.490 115.070 1615.310 ;
        RECT 0.335 1613.630 115.345 1614.490 ;
        RECT 0.335 1612.810 115.070 1613.630 ;
        RECT 0.335 1611.950 115.345 1612.810 ;
        RECT 0.335 1611.130 115.070 1611.950 ;
        RECT 0.335 1611.110 115.345 1611.130 ;
        RECT 0.610 1610.290 115.345 1611.110 ;
        RECT 0.335 1610.270 115.345 1610.290 ;
        RECT 0.335 1609.450 115.070 1610.270 ;
        RECT 0.335 1608.590 115.345 1609.450 ;
        RECT 0.335 1607.770 115.070 1608.590 ;
        RECT 0.335 1606.910 115.345 1607.770 ;
        RECT 0.335 1606.090 115.070 1606.910 ;
        RECT 0.335 1605.230 115.345 1606.090 ;
        RECT 0.335 1604.410 115.070 1605.230 ;
        RECT 0.335 1603.550 115.345 1604.410 ;
        RECT 0.610 1602.730 115.070 1603.550 ;
        RECT 0.335 1601.870 115.345 1602.730 ;
        RECT 0.335 1601.050 115.070 1601.870 ;
        RECT 0.335 1600.190 115.345 1601.050 ;
        RECT 0.335 1599.370 115.070 1600.190 ;
        RECT 0.335 1598.510 115.345 1599.370 ;
        RECT 0.335 1597.690 115.070 1598.510 ;
        RECT 0.335 1596.830 115.345 1597.690 ;
        RECT 0.335 1596.010 115.070 1596.830 ;
        RECT 0.335 1595.990 115.345 1596.010 ;
        RECT 0.610 1595.170 115.345 1595.990 ;
        RECT 0.335 1595.150 115.345 1595.170 ;
        RECT 0.335 1594.330 115.070 1595.150 ;
        RECT 0.335 1593.470 115.345 1594.330 ;
        RECT 0.335 1592.650 115.070 1593.470 ;
        RECT 0.335 1591.790 115.345 1592.650 ;
        RECT 0.335 1590.970 115.070 1591.790 ;
        RECT 0.335 1590.110 115.345 1590.970 ;
        RECT 0.335 1589.290 115.070 1590.110 ;
        RECT 0.335 1588.430 115.345 1589.290 ;
        RECT 0.610 1587.610 115.070 1588.430 ;
        RECT 0.335 1586.750 115.345 1587.610 ;
        RECT 0.335 1585.930 115.070 1586.750 ;
        RECT 0.335 1585.070 115.345 1585.930 ;
        RECT 0.335 1584.250 115.070 1585.070 ;
        RECT 0.335 1583.390 115.345 1584.250 ;
        RECT 0.335 1582.570 115.070 1583.390 ;
        RECT 0.335 1581.710 115.345 1582.570 ;
        RECT 0.335 1580.890 115.070 1581.710 ;
        RECT 0.335 1580.870 115.345 1580.890 ;
        RECT 0.610 1580.050 115.345 1580.870 ;
        RECT 0.335 1580.030 115.345 1580.050 ;
        RECT 0.335 1579.210 115.070 1580.030 ;
        RECT 0.335 1578.350 115.345 1579.210 ;
        RECT 0.335 1577.530 115.070 1578.350 ;
        RECT 0.335 1576.670 115.345 1577.530 ;
        RECT 0.335 1575.850 115.070 1576.670 ;
        RECT 0.335 1574.990 115.345 1575.850 ;
        RECT 0.335 1574.170 115.070 1574.990 ;
        RECT 0.335 1573.310 115.345 1574.170 ;
        RECT 0.610 1572.490 115.070 1573.310 ;
        RECT 0.335 1565.750 115.345 1572.490 ;
        RECT 0.610 1564.930 115.345 1565.750 ;
        RECT 0.335 1564.910 115.345 1564.930 ;
        RECT 0.335 1564.090 115.070 1564.910 ;
        RECT 0.335 1559.870 115.345 1564.090 ;
        RECT 0.335 1559.050 115.070 1559.870 ;
        RECT 0.335 1558.190 115.345 1559.050 ;
        RECT 0.610 1557.370 115.070 1558.190 ;
        RECT 0.335 1556.510 115.345 1557.370 ;
        RECT 0.335 1555.690 115.070 1556.510 ;
        RECT 0.335 1554.830 115.345 1555.690 ;
        RECT 0.335 1554.010 115.070 1554.830 ;
        RECT 0.335 1553.150 115.345 1554.010 ;
        RECT 0.335 1552.330 115.070 1553.150 ;
        RECT 0.335 1551.470 115.345 1552.330 ;
        RECT 0.335 1550.650 115.070 1551.470 ;
        RECT 0.335 1550.630 115.345 1550.650 ;
        RECT 0.610 1549.810 115.345 1550.630 ;
        RECT 0.335 1549.790 115.345 1549.810 ;
        RECT 0.335 1548.970 115.070 1549.790 ;
        RECT 0.335 1548.110 115.345 1548.970 ;
        RECT 0.335 1547.290 115.070 1548.110 ;
        RECT 0.335 1546.430 115.345 1547.290 ;
        RECT 0.335 1545.610 115.070 1546.430 ;
        RECT 0.335 1544.750 115.345 1545.610 ;
        RECT 0.335 1543.930 115.070 1544.750 ;
        RECT 0.335 1543.070 115.345 1543.930 ;
        RECT 0.610 1542.250 115.070 1543.070 ;
        RECT 0.335 1541.390 115.345 1542.250 ;
        RECT 0.335 1540.570 115.070 1541.390 ;
        RECT 0.335 1535.510 115.345 1540.570 ;
        RECT 0.610 1534.690 115.345 1535.510 ;
        RECT 0.335 1533.830 115.345 1534.690 ;
        RECT 0.335 1533.010 115.070 1533.830 ;
        RECT 0.335 1532.150 115.345 1533.010 ;
        RECT 0.335 1531.330 115.070 1532.150 ;
        RECT 0.335 1530.470 115.345 1531.330 ;
        RECT 0.335 1529.650 115.070 1530.470 ;
        RECT 0.335 1528.790 115.345 1529.650 ;
        RECT 0.335 1527.970 115.070 1528.790 ;
        RECT 0.335 1527.950 115.345 1527.970 ;
        RECT 0.610 1527.130 115.345 1527.950 ;
        RECT 0.335 1527.110 115.345 1527.130 ;
        RECT 0.335 1526.290 115.070 1527.110 ;
        RECT 0.335 1525.430 115.345 1526.290 ;
        RECT 0.335 1524.610 115.070 1525.430 ;
        RECT 0.335 1523.750 115.345 1524.610 ;
        RECT 0.335 1522.930 115.070 1523.750 ;
        RECT 0.335 1522.070 115.345 1522.930 ;
        RECT 0.335 1521.250 115.070 1522.070 ;
        RECT 0.335 1520.390 115.345 1521.250 ;
        RECT 0.610 1519.570 115.070 1520.390 ;
        RECT 0.335 1518.710 115.345 1519.570 ;
        RECT 0.335 1517.890 115.070 1518.710 ;
        RECT 0.335 1517.030 115.345 1517.890 ;
        RECT 0.335 1516.210 115.070 1517.030 ;
        RECT 0.335 1515.350 115.345 1516.210 ;
        RECT 0.335 1514.530 115.070 1515.350 ;
        RECT 0.335 1513.670 115.345 1514.530 ;
        RECT 0.335 1512.850 115.070 1513.670 ;
        RECT 0.335 1512.830 115.345 1512.850 ;
        RECT 0.610 1512.010 115.345 1512.830 ;
        RECT 0.335 1511.990 115.345 1512.010 ;
        RECT 0.335 1511.170 115.070 1511.990 ;
        RECT 0.335 1510.310 115.345 1511.170 ;
        RECT 0.335 1509.490 115.070 1510.310 ;
        RECT 0.335 1508.630 115.345 1509.490 ;
        RECT 0.335 1507.810 115.070 1508.630 ;
        RECT 0.335 1505.270 115.345 1507.810 ;
        RECT 0.610 1504.450 115.345 1505.270 ;
        RECT 0.335 1501.910 115.345 1504.450 ;
        RECT 0.335 1501.090 115.070 1501.910 ;
        RECT 0.335 1500.230 115.345 1501.090 ;
        RECT 0.335 1499.410 115.070 1500.230 ;
        RECT 0.335 1498.550 115.345 1499.410 ;
        RECT 0.335 1497.730 115.070 1498.550 ;
        RECT 0.335 1497.710 115.345 1497.730 ;
        RECT 0.610 1496.890 115.345 1497.710 ;
        RECT 0.335 1496.870 115.345 1496.890 ;
        RECT 0.335 1496.050 115.070 1496.870 ;
        RECT 0.335 1495.190 115.345 1496.050 ;
        RECT 0.335 1494.370 115.070 1495.190 ;
        RECT 0.335 1493.510 115.345 1494.370 ;
        RECT 0.335 1492.690 115.070 1493.510 ;
        RECT 0.335 1491.830 115.345 1492.690 ;
        RECT 0.335 1491.010 115.070 1491.830 ;
        RECT 0.335 1490.150 115.345 1491.010 ;
        RECT 0.610 1489.330 115.070 1490.150 ;
        RECT 0.335 1485.110 115.345 1489.330 ;
        RECT 0.335 1484.290 115.070 1485.110 ;
        RECT 0.335 1483.430 115.345 1484.290 ;
        RECT 0.335 1482.610 115.070 1483.430 ;
        RECT 0.335 1482.590 115.345 1482.610 ;
        RECT 0.610 1481.770 115.345 1482.590 ;
        RECT 0.335 1481.750 115.345 1481.770 ;
        RECT 0.335 1480.930 115.070 1481.750 ;
        RECT 0.335 1480.070 115.345 1480.930 ;
        RECT 0.335 1479.250 115.070 1480.070 ;
        RECT 0.335 1478.390 115.345 1479.250 ;
        RECT 0.335 1477.570 115.070 1478.390 ;
        RECT 0.335 1476.710 115.345 1477.570 ;
        RECT 0.335 1475.890 115.070 1476.710 ;
        RECT 0.335 1475.030 115.345 1475.890 ;
        RECT 0.610 1474.210 115.070 1475.030 ;
        RECT 0.335 1473.350 115.345 1474.210 ;
        RECT 0.335 1472.530 115.070 1473.350 ;
        RECT 0.335 1469.150 115.345 1472.530 ;
        RECT 0.335 1468.330 115.070 1469.150 ;
        RECT 0.335 1467.470 115.345 1468.330 ;
        RECT 0.610 1466.650 115.070 1467.470 ;
        RECT 0.335 1465.790 115.345 1466.650 ;
        RECT 0.335 1464.970 115.070 1465.790 ;
        RECT 0.335 1464.110 115.345 1464.970 ;
        RECT 0.335 1463.290 115.070 1464.110 ;
        RECT 0.335 1459.910 115.345 1463.290 ;
        RECT 0.610 1459.090 115.345 1459.910 ;
        RECT 0.335 1459.070 115.345 1459.090 ;
        RECT 0.335 1458.250 115.070 1459.070 ;
        RECT 0.335 1457.390 115.345 1458.250 ;
        RECT 0.335 1456.570 115.070 1457.390 ;
        RECT 0.335 1455.710 115.345 1456.570 ;
        RECT 0.335 1454.890 115.070 1455.710 ;
        RECT 0.335 1454.030 115.345 1454.890 ;
        RECT 0.335 1453.210 115.070 1454.030 ;
        RECT 0.335 1452.350 115.345 1453.210 ;
        RECT 0.610 1451.530 115.070 1452.350 ;
        RECT 0.335 1450.670 115.345 1451.530 ;
        RECT 0.335 1449.850 115.070 1450.670 ;
        RECT 0.335 1448.990 115.345 1449.850 ;
        RECT 0.335 1448.170 115.070 1448.990 ;
        RECT 0.335 1447.310 115.345 1448.170 ;
        RECT 0.335 1446.490 115.070 1447.310 ;
        RECT 0.335 1445.630 115.345 1446.490 ;
        RECT 0.335 1444.810 115.070 1445.630 ;
        RECT 0.335 1444.790 115.345 1444.810 ;
        RECT 0.610 1443.970 115.345 1444.790 ;
        RECT 0.335 1443.950 115.345 1443.970 ;
        RECT 0.335 1443.130 115.070 1443.950 ;
        RECT 0.335 1442.270 115.345 1443.130 ;
        RECT 0.335 1441.450 115.070 1442.270 ;
        RECT 0.335 1440.590 115.345 1441.450 ;
        RECT 0.335 1439.770 115.070 1440.590 ;
        RECT 0.335 1437.230 115.345 1439.770 ;
        RECT 0.610 1436.410 115.345 1437.230 ;
        RECT 0.335 1433.030 115.345 1436.410 ;
        RECT 0.335 1432.210 115.070 1433.030 ;
        RECT 0.335 1431.350 115.345 1432.210 ;
        RECT 0.335 1430.530 115.070 1431.350 ;
        RECT 0.335 1429.670 115.345 1430.530 ;
        RECT 0.610 1428.850 115.070 1429.670 ;
        RECT 0.335 1427.990 115.345 1428.850 ;
        RECT 0.335 1427.170 115.070 1427.990 ;
        RECT 0.335 1426.310 115.345 1427.170 ;
        RECT 0.335 1425.490 115.070 1426.310 ;
        RECT 0.335 1424.630 115.345 1425.490 ;
        RECT 0.335 1423.810 115.070 1424.630 ;
        RECT 0.335 1422.950 115.345 1423.810 ;
        RECT 0.335 1422.130 115.070 1422.950 ;
        RECT 0.335 1422.110 115.345 1422.130 ;
        RECT 0.610 1421.290 115.345 1422.110 ;
        RECT 0.335 1421.270 115.345 1421.290 ;
        RECT 0.335 1420.450 115.070 1421.270 ;
        RECT 0.335 1419.590 115.345 1420.450 ;
        RECT 0.335 1418.770 115.070 1419.590 ;
        RECT 0.335 1417.910 115.345 1418.770 ;
        RECT 0.335 1417.090 115.070 1417.910 ;
        RECT 0.335 1416.230 115.345 1417.090 ;
        RECT 0.335 1415.410 115.070 1416.230 ;
        RECT 0.335 1414.550 115.345 1415.410 ;
        RECT 0.610 1413.730 115.070 1414.550 ;
        RECT 0.335 1412.870 115.345 1413.730 ;
        RECT 0.335 1412.050 115.070 1412.870 ;
        RECT 0.335 1411.190 115.345 1412.050 ;
        RECT 0.335 1410.370 115.070 1411.190 ;
        RECT 0.335 1409.510 115.345 1410.370 ;
        RECT 0.335 1408.690 115.070 1409.510 ;
        RECT 0.335 1407.830 115.345 1408.690 ;
        RECT 0.335 1407.010 115.070 1407.830 ;
        RECT 0.335 1406.990 115.345 1407.010 ;
        RECT 0.610 1406.170 115.345 1406.990 ;
        RECT 0.335 1401.110 115.345 1406.170 ;
        RECT 0.335 1400.290 115.070 1401.110 ;
        RECT 0.335 1399.430 115.345 1400.290 ;
        RECT 0.610 1398.610 115.070 1399.430 ;
        RECT 0.335 1397.750 115.345 1398.610 ;
        RECT 0.335 1396.930 115.070 1397.750 ;
        RECT 0.335 1396.070 115.345 1396.930 ;
        RECT 0.335 1395.250 115.070 1396.070 ;
        RECT 0.335 1394.390 115.345 1395.250 ;
        RECT 0.335 1393.570 115.070 1394.390 ;
        RECT 0.335 1392.710 115.345 1393.570 ;
        RECT 0.335 1391.890 115.070 1392.710 ;
        RECT 0.335 1391.870 115.345 1391.890 ;
        RECT 0.610 1391.050 115.345 1391.870 ;
        RECT 0.335 1391.030 115.345 1391.050 ;
        RECT 0.335 1390.210 115.070 1391.030 ;
        RECT 0.335 1389.350 115.345 1390.210 ;
        RECT 0.335 1388.530 115.070 1389.350 ;
        RECT 0.335 1384.310 115.345 1388.530 ;
        RECT 0.610 1383.490 115.070 1384.310 ;
        RECT 0.335 1382.630 115.345 1383.490 ;
        RECT 0.335 1381.810 115.070 1382.630 ;
        RECT 0.335 1380.950 115.345 1381.810 ;
        RECT 0.335 1380.130 115.070 1380.950 ;
        RECT 0.335 1379.270 115.345 1380.130 ;
        RECT 0.335 1378.450 115.070 1379.270 ;
        RECT 0.335 1377.590 115.345 1378.450 ;
        RECT 0.335 1376.770 115.070 1377.590 ;
        RECT 0.335 1375.910 115.345 1376.770 ;
        RECT 0.335 1375.090 115.070 1375.910 ;
        RECT 0.335 1374.230 115.345 1375.090 ;
        RECT 0.335 1373.410 115.070 1374.230 ;
        RECT 0.335 1372.550 115.345 1373.410 ;
        RECT 0.335 1371.730 115.070 1372.550 ;
        RECT 0.335 1368.350 115.345 1371.730 ;
        RECT 0.335 1367.530 115.070 1368.350 ;
        RECT 0.335 1366.670 115.345 1367.530 ;
        RECT 0.335 1365.850 115.070 1366.670 ;
        RECT 0.335 1365.830 115.345 1365.850 ;
        RECT 0.610 1365.010 115.345 1365.830 ;
        RECT 0.335 1364.990 115.345 1365.010 ;
        RECT 0.335 1364.170 115.070 1364.990 ;
        RECT 0.335 1363.310 115.345 1364.170 ;
        RECT 0.335 1362.490 115.070 1363.310 ;
        RECT 0.335 1353.230 115.345 1362.490 ;
        RECT 0.335 1352.410 115.070 1353.230 ;
        RECT 0.335 1351.550 115.345 1352.410 ;
        RECT 0.335 1350.730 115.070 1351.550 ;
        RECT 0.335 1349.870 115.345 1350.730 ;
        RECT 0.335 1349.050 115.070 1349.870 ;
        RECT 0.335 1348.190 115.345 1349.050 ;
        RECT 0.335 1347.370 115.070 1348.190 ;
        RECT 0.335 1346.510 115.345 1347.370 ;
        RECT 0.610 1345.690 115.070 1346.510 ;
        RECT 0.335 1344.830 115.345 1345.690 ;
        RECT 0.335 1344.010 115.070 1344.830 ;
        RECT 0.335 1343.150 115.345 1344.010 ;
        RECT 0.335 1342.330 115.070 1343.150 ;
        RECT 0.335 1341.470 115.345 1342.330 ;
        RECT 0.335 1340.650 115.070 1341.470 ;
        RECT 0.335 1339.790 115.345 1340.650 ;
        RECT 0.335 1338.970 115.070 1339.790 ;
        RECT 0.335 1338.950 115.345 1338.970 ;
        RECT 0.610 1338.130 115.345 1338.950 ;
        RECT 0.335 1338.110 115.345 1338.130 ;
        RECT 0.335 1337.290 115.070 1338.110 ;
        RECT 0.335 1336.430 115.345 1337.290 ;
        RECT 0.335 1335.610 115.070 1336.430 ;
        RECT 0.335 1334.750 115.345 1335.610 ;
        RECT 0.335 1333.930 115.070 1334.750 ;
        RECT 0.335 1333.070 115.345 1333.930 ;
        RECT 0.335 1332.250 115.070 1333.070 ;
        RECT 0.335 1331.390 115.345 1332.250 ;
        RECT 0.610 1330.570 115.070 1331.390 ;
        RECT 0.335 1329.710 115.345 1330.570 ;
        RECT 0.335 1328.890 115.070 1329.710 ;
        RECT 0.335 1328.030 115.345 1328.890 ;
        RECT 0.335 1327.210 115.070 1328.030 ;
        RECT 0.335 1326.350 115.345 1327.210 ;
        RECT 0.335 1325.530 115.070 1326.350 ;
        RECT 0.335 1324.670 115.345 1325.530 ;
        RECT 0.335 1323.850 115.070 1324.670 ;
        RECT 0.335 1323.830 115.345 1323.850 ;
        RECT 0.610 1323.010 115.345 1323.830 ;
        RECT 0.335 1322.990 115.345 1323.010 ;
        RECT 0.335 1322.170 115.070 1322.990 ;
        RECT 0.335 1321.310 115.345 1322.170 ;
        RECT 0.335 1320.490 115.070 1321.310 ;
        RECT 0.335 1319.630 115.345 1320.490 ;
        RECT 0.335 1318.810 115.070 1319.630 ;
        RECT 0.335 1317.950 115.345 1318.810 ;
        RECT 0.335 1317.130 115.070 1317.950 ;
        RECT 0.335 1316.270 115.345 1317.130 ;
        RECT 0.610 1315.450 115.070 1316.270 ;
        RECT 0.335 1314.590 115.345 1315.450 ;
        RECT 0.335 1313.770 115.070 1314.590 ;
        RECT 0.335 1312.910 115.345 1313.770 ;
        RECT 0.335 1312.090 115.070 1312.910 ;
        RECT 0.335 1311.230 115.345 1312.090 ;
        RECT 0.335 1310.410 115.070 1311.230 ;
        RECT 0.335 1309.550 115.345 1310.410 ;
        RECT 0.335 1308.730 115.070 1309.550 ;
        RECT 0.335 1308.710 115.345 1308.730 ;
        RECT 0.610 1307.890 115.345 1308.710 ;
        RECT 0.335 1307.870 115.345 1307.890 ;
        RECT 0.335 1307.050 115.070 1307.870 ;
        RECT 0.335 1306.190 115.345 1307.050 ;
        RECT 0.335 1305.370 115.070 1306.190 ;
        RECT 0.335 1304.510 115.345 1305.370 ;
        RECT 0.335 1303.690 115.070 1304.510 ;
        RECT 0.335 1302.830 115.345 1303.690 ;
        RECT 0.335 1302.010 115.070 1302.830 ;
        RECT 0.335 1301.150 115.345 1302.010 ;
        RECT 0.610 1300.330 115.070 1301.150 ;
        RECT 0.335 1293.590 115.345 1300.330 ;
        RECT 0.610 1292.770 115.345 1293.590 ;
        RECT 0.335 1292.750 115.345 1292.770 ;
        RECT 0.335 1291.930 115.070 1292.750 ;
        RECT 0.335 1287.710 115.345 1291.930 ;
        RECT 0.335 1286.890 115.070 1287.710 ;
        RECT 0.335 1286.030 115.345 1286.890 ;
        RECT 0.610 1285.210 115.070 1286.030 ;
        RECT 0.335 1284.350 115.345 1285.210 ;
        RECT 0.335 1283.530 115.070 1284.350 ;
        RECT 0.335 1282.670 115.345 1283.530 ;
        RECT 0.335 1281.850 115.070 1282.670 ;
        RECT 0.335 1280.990 115.345 1281.850 ;
        RECT 0.335 1280.170 115.070 1280.990 ;
        RECT 0.335 1279.310 115.345 1280.170 ;
        RECT 0.335 1278.490 115.070 1279.310 ;
        RECT 0.335 1278.470 115.345 1278.490 ;
        RECT 0.610 1277.650 115.345 1278.470 ;
        RECT 0.335 1277.630 115.345 1277.650 ;
        RECT 0.335 1276.810 115.070 1277.630 ;
        RECT 0.335 1275.950 115.345 1276.810 ;
        RECT 0.335 1275.130 115.070 1275.950 ;
        RECT 0.335 1274.270 115.345 1275.130 ;
        RECT 0.335 1273.450 115.070 1274.270 ;
        RECT 0.335 1272.590 115.345 1273.450 ;
        RECT 0.335 1271.770 115.070 1272.590 ;
        RECT 0.335 1270.910 115.345 1271.770 ;
        RECT 0.610 1270.090 115.070 1270.910 ;
        RECT 0.335 1269.230 115.345 1270.090 ;
        RECT 0.335 1268.410 115.070 1269.230 ;
        RECT 0.335 1263.350 115.345 1268.410 ;
        RECT 0.610 1262.530 115.345 1263.350 ;
        RECT 0.335 1261.670 115.345 1262.530 ;
        RECT 0.335 1260.850 115.070 1261.670 ;
        RECT 0.335 1259.990 115.345 1260.850 ;
        RECT 0.335 1259.170 115.070 1259.990 ;
        RECT 0.335 1258.310 115.345 1259.170 ;
        RECT 0.335 1257.490 115.070 1258.310 ;
        RECT 0.335 1256.630 115.345 1257.490 ;
        RECT 0.335 1255.810 115.070 1256.630 ;
        RECT 0.335 1255.790 115.345 1255.810 ;
        RECT 0.610 1254.970 115.345 1255.790 ;
        RECT 0.335 1254.950 115.345 1254.970 ;
        RECT 0.335 1254.130 115.070 1254.950 ;
        RECT 0.335 1253.270 115.345 1254.130 ;
        RECT 0.335 1252.450 115.070 1253.270 ;
        RECT 0.335 1251.590 115.345 1252.450 ;
        RECT 0.335 1250.770 115.070 1251.590 ;
        RECT 0.335 1249.910 115.345 1250.770 ;
        RECT 0.335 1249.090 115.070 1249.910 ;
        RECT 0.335 1248.230 115.345 1249.090 ;
        RECT 0.610 1247.410 115.070 1248.230 ;
        RECT 0.335 1246.550 115.345 1247.410 ;
        RECT 0.335 1245.730 115.070 1246.550 ;
        RECT 0.335 1244.870 115.345 1245.730 ;
        RECT 0.335 1244.050 115.070 1244.870 ;
        RECT 0.335 1243.190 115.345 1244.050 ;
        RECT 0.335 1242.370 115.070 1243.190 ;
        RECT 0.335 1241.510 115.345 1242.370 ;
        RECT 0.335 1240.690 115.070 1241.510 ;
        RECT 0.335 1240.670 115.345 1240.690 ;
        RECT 0.610 1239.850 115.345 1240.670 ;
        RECT 0.335 1239.830 115.345 1239.850 ;
        RECT 0.335 1239.010 115.070 1239.830 ;
        RECT 0.335 1238.150 115.345 1239.010 ;
        RECT 0.335 1237.330 115.070 1238.150 ;
        RECT 0.335 1236.470 115.345 1237.330 ;
        RECT 0.335 1235.650 115.070 1236.470 ;
        RECT 0.335 1233.110 115.345 1235.650 ;
        RECT 0.610 1232.290 115.345 1233.110 ;
        RECT 0.335 1229.750 115.345 1232.290 ;
        RECT 0.335 1228.930 115.070 1229.750 ;
        RECT 0.335 1228.070 115.345 1228.930 ;
        RECT 0.335 1227.250 115.070 1228.070 ;
        RECT 0.335 1226.390 115.345 1227.250 ;
        RECT 0.335 1225.570 115.070 1226.390 ;
        RECT 0.335 1225.550 115.345 1225.570 ;
        RECT 0.610 1224.730 115.345 1225.550 ;
        RECT 0.335 1224.710 115.345 1224.730 ;
        RECT 0.335 1223.890 115.070 1224.710 ;
        RECT 0.335 1223.030 115.345 1223.890 ;
        RECT 0.335 1222.210 115.070 1223.030 ;
        RECT 0.335 1221.350 115.345 1222.210 ;
        RECT 0.335 1220.530 115.070 1221.350 ;
        RECT 0.335 1219.670 115.345 1220.530 ;
        RECT 0.335 1218.850 115.070 1219.670 ;
        RECT 0.335 1217.990 115.345 1218.850 ;
        RECT 0.610 1217.170 115.070 1217.990 ;
        RECT 0.335 1212.950 115.345 1217.170 ;
        RECT 0.335 1212.130 115.070 1212.950 ;
        RECT 0.335 1211.270 115.345 1212.130 ;
        RECT 0.335 1210.450 115.070 1211.270 ;
        RECT 0.335 1210.430 115.345 1210.450 ;
        RECT 0.610 1209.610 115.345 1210.430 ;
        RECT 0.335 1209.590 115.345 1209.610 ;
        RECT 0.335 1208.770 115.070 1209.590 ;
        RECT 0.335 1207.910 115.345 1208.770 ;
        RECT 0.335 1207.090 115.070 1207.910 ;
        RECT 0.335 1206.230 115.345 1207.090 ;
        RECT 0.335 1205.410 115.070 1206.230 ;
        RECT 0.335 1204.550 115.345 1205.410 ;
        RECT 0.335 1203.730 115.070 1204.550 ;
        RECT 0.335 1202.870 115.345 1203.730 ;
        RECT 0.610 1202.050 115.070 1202.870 ;
        RECT 0.335 1201.190 115.345 1202.050 ;
        RECT 0.335 1200.370 115.070 1201.190 ;
        RECT 0.335 1196.990 115.345 1200.370 ;
        RECT 0.335 1196.170 115.070 1196.990 ;
        RECT 0.335 1195.310 115.345 1196.170 ;
        RECT 0.610 1194.490 115.070 1195.310 ;
        RECT 0.335 1193.630 115.345 1194.490 ;
        RECT 0.335 1192.810 115.070 1193.630 ;
        RECT 0.335 1191.950 115.345 1192.810 ;
        RECT 0.335 1191.130 115.070 1191.950 ;
        RECT 0.335 1187.750 115.345 1191.130 ;
        RECT 0.610 1186.930 115.345 1187.750 ;
        RECT 0.335 1186.910 115.345 1186.930 ;
        RECT 0.335 1186.090 115.070 1186.910 ;
        RECT 0.335 1185.230 115.345 1186.090 ;
        RECT 0.335 1184.410 115.070 1185.230 ;
        RECT 0.335 1183.550 115.345 1184.410 ;
        RECT 0.335 1182.730 115.070 1183.550 ;
        RECT 0.335 1181.870 115.345 1182.730 ;
        RECT 0.335 1181.050 115.070 1181.870 ;
        RECT 0.335 1180.190 115.345 1181.050 ;
        RECT 0.610 1179.370 115.070 1180.190 ;
        RECT 0.335 1178.510 115.345 1179.370 ;
        RECT 0.335 1177.690 115.070 1178.510 ;
        RECT 0.335 1176.830 115.345 1177.690 ;
        RECT 0.335 1176.010 115.070 1176.830 ;
        RECT 0.335 1175.150 115.345 1176.010 ;
        RECT 0.335 1174.330 115.070 1175.150 ;
        RECT 0.335 1173.470 115.345 1174.330 ;
        RECT 0.335 1172.650 115.070 1173.470 ;
        RECT 0.335 1172.630 115.345 1172.650 ;
        RECT 0.610 1171.810 115.345 1172.630 ;
        RECT 0.335 1171.790 115.345 1171.810 ;
        RECT 0.335 1170.970 115.070 1171.790 ;
        RECT 0.335 1170.110 115.345 1170.970 ;
        RECT 0.335 1169.290 115.070 1170.110 ;
        RECT 0.335 1168.430 115.345 1169.290 ;
        RECT 0.335 1167.610 115.070 1168.430 ;
        RECT 0.335 1165.070 115.345 1167.610 ;
        RECT 0.610 1164.250 115.345 1165.070 ;
        RECT 0.335 1160.870 115.345 1164.250 ;
        RECT 0.335 1160.050 115.070 1160.870 ;
        RECT 0.335 1159.190 115.345 1160.050 ;
        RECT 0.335 1158.370 115.070 1159.190 ;
        RECT 0.335 1157.510 115.345 1158.370 ;
        RECT 0.610 1156.690 115.070 1157.510 ;
        RECT 0.335 1155.830 115.345 1156.690 ;
        RECT 0.335 1155.010 115.070 1155.830 ;
        RECT 0.335 1154.150 115.345 1155.010 ;
        RECT 0.335 1153.330 115.070 1154.150 ;
        RECT 0.335 1152.470 115.345 1153.330 ;
        RECT 0.335 1151.650 115.070 1152.470 ;
        RECT 0.335 1150.790 115.345 1151.650 ;
        RECT 0.335 1149.970 115.070 1150.790 ;
        RECT 0.335 1149.950 115.345 1149.970 ;
        RECT 0.610 1149.130 115.345 1149.950 ;
        RECT 0.335 1149.110 115.345 1149.130 ;
        RECT 0.335 1148.290 115.070 1149.110 ;
        RECT 0.335 1147.430 115.345 1148.290 ;
        RECT 0.335 1146.610 115.070 1147.430 ;
        RECT 0.335 1145.750 115.345 1146.610 ;
        RECT 0.335 1144.930 115.070 1145.750 ;
        RECT 0.335 1144.070 115.345 1144.930 ;
        RECT 0.335 1143.250 115.070 1144.070 ;
        RECT 0.335 1142.390 115.345 1143.250 ;
        RECT 0.610 1141.570 115.070 1142.390 ;
        RECT 0.335 1140.710 115.345 1141.570 ;
        RECT 0.335 1139.890 115.070 1140.710 ;
        RECT 0.335 1139.030 115.345 1139.890 ;
        RECT 0.335 1138.210 115.070 1139.030 ;
        RECT 0.335 1137.350 115.345 1138.210 ;
        RECT 0.335 1136.530 115.070 1137.350 ;
        RECT 0.335 1135.670 115.345 1136.530 ;
        RECT 0.335 1134.850 115.070 1135.670 ;
        RECT 0.335 1134.830 115.345 1134.850 ;
        RECT 0.610 1134.010 115.345 1134.830 ;
        RECT 0.335 1128.950 115.345 1134.010 ;
        RECT 0.335 1128.130 115.070 1128.950 ;
        RECT 0.335 1127.270 115.345 1128.130 ;
        RECT 0.610 1126.450 115.070 1127.270 ;
        RECT 0.335 1125.590 115.345 1126.450 ;
        RECT 0.335 1124.770 115.070 1125.590 ;
        RECT 0.335 1123.910 115.345 1124.770 ;
        RECT 0.335 1123.090 115.070 1123.910 ;
        RECT 0.335 1122.230 115.345 1123.090 ;
        RECT 0.335 1121.410 115.070 1122.230 ;
        RECT 0.335 1120.550 115.345 1121.410 ;
        RECT 0.335 1119.730 115.070 1120.550 ;
        RECT 0.335 1119.710 115.345 1119.730 ;
        RECT 0.610 1118.890 115.345 1119.710 ;
        RECT 0.335 1118.870 115.345 1118.890 ;
        RECT 0.335 1118.050 115.070 1118.870 ;
        RECT 0.335 1117.190 115.345 1118.050 ;
        RECT 0.335 1116.370 115.070 1117.190 ;
        RECT 0.335 1112.150 115.345 1116.370 ;
        RECT 0.610 1111.330 115.070 1112.150 ;
        RECT 0.335 1110.470 115.345 1111.330 ;
        RECT 0.335 1109.650 115.070 1110.470 ;
        RECT 0.335 1108.790 115.345 1109.650 ;
        RECT 0.335 1107.970 115.070 1108.790 ;
        RECT 0.335 1107.110 115.345 1107.970 ;
        RECT 0.335 1106.290 115.070 1107.110 ;
        RECT 0.335 1105.430 115.345 1106.290 ;
        RECT 0.335 1104.610 115.070 1105.430 ;
        RECT 0.335 1103.750 115.345 1104.610 ;
        RECT 0.335 1102.930 115.070 1103.750 ;
        RECT 0.335 1102.070 115.345 1102.930 ;
        RECT 0.335 1101.250 115.070 1102.070 ;
        RECT 0.335 1100.390 115.345 1101.250 ;
        RECT 0.335 1099.570 115.070 1100.390 ;
        RECT 0.335 1096.190 115.345 1099.570 ;
        RECT 0.335 1095.370 115.070 1096.190 ;
        RECT 0.335 1094.510 115.345 1095.370 ;
        RECT 0.335 1093.690 115.070 1094.510 ;
        RECT 0.335 1093.670 115.345 1093.690 ;
        RECT 0.610 1092.850 115.345 1093.670 ;
        RECT 0.335 1092.830 115.345 1092.850 ;
        RECT 0.335 1092.010 115.070 1092.830 ;
        RECT 0.335 1091.150 115.345 1092.010 ;
        RECT 0.335 1090.330 115.070 1091.150 ;
        RECT 0.335 1081.070 115.345 1090.330 ;
        RECT 0.335 1080.250 115.070 1081.070 ;
        RECT 0.335 1079.390 115.345 1080.250 ;
        RECT 0.335 1078.570 115.070 1079.390 ;
        RECT 0.335 1077.710 115.345 1078.570 ;
        RECT 0.335 1076.890 115.070 1077.710 ;
        RECT 0.335 1076.030 115.345 1076.890 ;
        RECT 0.335 1075.210 115.070 1076.030 ;
        RECT 0.335 1074.350 115.345 1075.210 ;
        RECT 0.610 1073.530 115.070 1074.350 ;
        RECT 0.335 1072.670 115.345 1073.530 ;
        RECT 0.335 1071.850 115.070 1072.670 ;
        RECT 0.335 1070.990 115.345 1071.850 ;
        RECT 0.335 1070.170 115.070 1070.990 ;
        RECT 0.335 1069.310 115.345 1070.170 ;
        RECT 0.335 1068.490 115.070 1069.310 ;
        RECT 0.335 1067.630 115.345 1068.490 ;
        RECT 0.335 1066.810 115.070 1067.630 ;
        RECT 0.335 1066.790 115.345 1066.810 ;
        RECT 0.610 1065.970 115.345 1066.790 ;
        RECT 0.335 1065.950 115.345 1065.970 ;
        RECT 0.335 1065.130 115.070 1065.950 ;
        RECT 0.335 1064.270 115.345 1065.130 ;
        RECT 0.335 1063.450 115.070 1064.270 ;
        RECT 0.335 1062.590 115.345 1063.450 ;
        RECT 0.335 1061.770 115.070 1062.590 ;
        RECT 0.335 1060.910 115.345 1061.770 ;
        RECT 0.335 1060.090 115.070 1060.910 ;
        RECT 0.335 1059.230 115.345 1060.090 ;
        RECT 0.610 1058.410 115.070 1059.230 ;
        RECT 0.335 1057.550 115.345 1058.410 ;
        RECT 0.335 1056.730 115.070 1057.550 ;
        RECT 0.335 1055.870 115.345 1056.730 ;
        RECT 0.335 1055.050 115.070 1055.870 ;
        RECT 0.335 1054.190 115.345 1055.050 ;
        RECT 0.335 1053.370 115.070 1054.190 ;
        RECT 0.335 1052.510 115.345 1053.370 ;
        RECT 0.335 1051.690 115.070 1052.510 ;
        RECT 0.335 1051.670 115.345 1051.690 ;
        RECT 0.610 1050.850 115.345 1051.670 ;
        RECT 0.335 1050.830 115.345 1050.850 ;
        RECT 0.335 1050.010 115.070 1050.830 ;
        RECT 0.335 1049.150 115.345 1050.010 ;
        RECT 0.335 1048.330 115.070 1049.150 ;
        RECT 0.335 1047.470 115.345 1048.330 ;
        RECT 0.335 1046.650 115.070 1047.470 ;
        RECT 0.335 1045.790 115.345 1046.650 ;
        RECT 0.335 1044.970 115.070 1045.790 ;
        RECT 0.335 1044.110 115.345 1044.970 ;
        RECT 0.610 1043.290 115.070 1044.110 ;
        RECT 0.335 1042.430 115.345 1043.290 ;
        RECT 0.335 1041.610 115.070 1042.430 ;
        RECT 0.335 1040.750 115.345 1041.610 ;
        RECT 0.335 1039.930 115.070 1040.750 ;
        RECT 0.335 1039.070 115.345 1039.930 ;
        RECT 0.335 1038.250 115.070 1039.070 ;
        RECT 0.335 1037.390 115.345 1038.250 ;
        RECT 0.335 1036.570 115.070 1037.390 ;
        RECT 0.335 1036.550 115.345 1036.570 ;
        RECT 0.610 1035.730 115.345 1036.550 ;
        RECT 0.335 1035.710 115.345 1035.730 ;
        RECT 0.335 1034.890 115.070 1035.710 ;
        RECT 0.335 1034.030 115.345 1034.890 ;
        RECT 0.335 1033.210 115.070 1034.030 ;
        RECT 0.335 1032.350 115.345 1033.210 ;
        RECT 0.335 1031.530 115.070 1032.350 ;
        RECT 0.335 1030.670 115.345 1031.530 ;
        RECT 0.335 1029.850 115.070 1030.670 ;
        RECT 0.335 1028.990 115.345 1029.850 ;
        RECT 0.610 1028.170 115.070 1028.990 ;
        RECT 0.335 1021.430 115.345 1028.170 ;
        RECT 0.610 1020.610 115.345 1021.430 ;
        RECT 0.335 1020.590 115.345 1020.610 ;
        RECT 0.335 1019.770 115.070 1020.590 ;
        RECT 0.335 1015.550 115.345 1019.770 ;
        RECT 0.335 1014.730 115.070 1015.550 ;
        RECT 0.335 1013.870 115.345 1014.730 ;
        RECT 0.610 1013.050 115.070 1013.870 ;
        RECT 0.335 1012.190 115.345 1013.050 ;
        RECT 0.335 1011.370 115.070 1012.190 ;
        RECT 0.335 1010.510 115.345 1011.370 ;
        RECT 0.335 1009.690 115.070 1010.510 ;
        RECT 0.335 1008.830 115.345 1009.690 ;
        RECT 0.335 1008.010 115.070 1008.830 ;
        RECT 0.335 1007.150 115.345 1008.010 ;
        RECT 0.335 1006.330 115.070 1007.150 ;
        RECT 0.335 1006.310 115.345 1006.330 ;
        RECT 0.610 1005.490 115.345 1006.310 ;
        RECT 0.335 1005.470 115.345 1005.490 ;
        RECT 0.335 1004.650 115.070 1005.470 ;
        RECT 0.335 1003.790 115.345 1004.650 ;
        RECT 0.335 1002.970 115.070 1003.790 ;
        RECT 0.335 1002.110 115.345 1002.970 ;
        RECT 0.335 1001.290 115.070 1002.110 ;
        RECT 0.335 1000.430 115.345 1001.290 ;
        RECT 0.335 999.610 115.070 1000.430 ;
        RECT 0.335 998.750 115.345 999.610 ;
        RECT 0.610 997.930 115.070 998.750 ;
        RECT 0.335 997.070 115.345 997.930 ;
        RECT 0.335 996.250 115.070 997.070 ;
        RECT 0.335 991.190 115.345 996.250 ;
        RECT 0.610 990.370 115.345 991.190 ;
        RECT 0.335 989.510 115.345 990.370 ;
        RECT 0.335 988.690 115.070 989.510 ;
        RECT 0.335 987.830 115.345 988.690 ;
        RECT 0.335 987.010 115.070 987.830 ;
        RECT 0.335 986.150 115.345 987.010 ;
        RECT 0.335 985.330 115.070 986.150 ;
        RECT 0.335 984.470 115.345 985.330 ;
        RECT 0.335 983.650 115.070 984.470 ;
        RECT 0.335 983.630 115.345 983.650 ;
        RECT 0.610 982.810 115.345 983.630 ;
        RECT 0.335 982.790 115.345 982.810 ;
        RECT 0.335 981.970 115.070 982.790 ;
        RECT 0.335 981.110 115.345 981.970 ;
        RECT 0.335 980.290 115.070 981.110 ;
        RECT 0.335 979.430 115.345 980.290 ;
        RECT 0.335 978.610 115.070 979.430 ;
        RECT 0.335 977.750 115.345 978.610 ;
        RECT 0.335 976.930 115.070 977.750 ;
        RECT 0.335 976.070 115.345 976.930 ;
        RECT 0.610 975.250 115.070 976.070 ;
        RECT 0.335 974.390 115.345 975.250 ;
        RECT 0.335 973.570 115.070 974.390 ;
        RECT 0.335 972.710 115.345 973.570 ;
        RECT 0.335 971.890 115.070 972.710 ;
        RECT 0.335 971.030 115.345 971.890 ;
        RECT 0.335 970.210 115.070 971.030 ;
        RECT 0.335 969.350 115.345 970.210 ;
        RECT 0.335 968.530 115.070 969.350 ;
        RECT 0.335 968.510 115.345 968.530 ;
        RECT 0.610 967.690 115.345 968.510 ;
        RECT 0.335 967.670 115.345 967.690 ;
        RECT 0.335 966.850 115.070 967.670 ;
        RECT 0.335 965.990 115.345 966.850 ;
        RECT 0.335 965.170 115.070 965.990 ;
        RECT 0.335 964.310 115.345 965.170 ;
        RECT 0.335 963.490 115.070 964.310 ;
        RECT 0.335 960.950 115.345 963.490 ;
        RECT 0.610 960.130 115.345 960.950 ;
        RECT 0.335 957.590 115.345 960.130 ;
        RECT 0.335 956.770 115.070 957.590 ;
        RECT 0.335 955.910 115.345 956.770 ;
        RECT 0.335 955.090 115.070 955.910 ;
        RECT 0.335 954.230 115.345 955.090 ;
        RECT 0.335 953.410 115.070 954.230 ;
        RECT 0.335 953.390 115.345 953.410 ;
        RECT 0.610 952.570 115.345 953.390 ;
        RECT 0.335 952.550 115.345 952.570 ;
        RECT 0.335 951.730 115.070 952.550 ;
        RECT 0.335 950.870 115.345 951.730 ;
        RECT 0.335 950.050 115.070 950.870 ;
        RECT 0.335 949.190 115.345 950.050 ;
        RECT 0.335 948.370 115.070 949.190 ;
        RECT 0.335 947.510 115.345 948.370 ;
        RECT 0.335 946.690 115.070 947.510 ;
        RECT 0.335 945.830 115.345 946.690 ;
        RECT 0.610 945.010 115.070 945.830 ;
        RECT 0.335 940.790 115.345 945.010 ;
        RECT 0.335 939.970 115.070 940.790 ;
        RECT 0.335 939.110 115.345 939.970 ;
        RECT 0.335 938.290 115.070 939.110 ;
        RECT 0.335 938.270 115.345 938.290 ;
        RECT 0.610 937.450 115.345 938.270 ;
        RECT 0.335 937.430 115.345 937.450 ;
        RECT 0.335 936.610 115.070 937.430 ;
        RECT 0.335 935.750 115.345 936.610 ;
        RECT 0.335 934.930 115.070 935.750 ;
        RECT 0.335 934.070 115.345 934.930 ;
        RECT 0.335 933.250 115.070 934.070 ;
        RECT 0.335 932.390 115.345 933.250 ;
        RECT 0.335 931.570 115.070 932.390 ;
        RECT 0.335 930.710 115.345 931.570 ;
        RECT 0.610 929.890 115.070 930.710 ;
        RECT 0.335 929.030 115.345 929.890 ;
        RECT 0.335 928.210 115.070 929.030 ;
        RECT 0.335 924.830 115.345 928.210 ;
        RECT 0.335 924.010 115.070 924.830 ;
        RECT 0.335 923.150 115.345 924.010 ;
        RECT 0.610 922.330 115.070 923.150 ;
        RECT 0.335 921.470 115.345 922.330 ;
        RECT 0.335 920.650 115.070 921.470 ;
        RECT 0.335 919.790 115.345 920.650 ;
        RECT 0.335 918.970 115.070 919.790 ;
        RECT 0.335 915.590 115.345 918.970 ;
        RECT 0.610 914.770 115.345 915.590 ;
        RECT 0.335 914.750 115.345 914.770 ;
        RECT 0.335 913.930 115.070 914.750 ;
        RECT 0.335 913.070 115.345 913.930 ;
        RECT 0.335 912.250 115.070 913.070 ;
        RECT 0.335 911.390 115.345 912.250 ;
        RECT 0.335 910.570 115.070 911.390 ;
        RECT 0.335 909.710 115.345 910.570 ;
        RECT 0.335 908.890 115.070 909.710 ;
        RECT 0.335 908.030 115.345 908.890 ;
        RECT 0.610 907.210 115.070 908.030 ;
        RECT 0.335 906.350 115.345 907.210 ;
        RECT 0.335 905.530 115.070 906.350 ;
        RECT 0.335 904.670 115.345 905.530 ;
        RECT 0.335 903.850 115.070 904.670 ;
        RECT 0.335 902.990 115.345 903.850 ;
        RECT 0.335 902.170 115.070 902.990 ;
        RECT 0.335 901.310 115.345 902.170 ;
        RECT 0.335 900.490 115.070 901.310 ;
        RECT 0.335 900.470 115.345 900.490 ;
        RECT 0.610 899.650 115.345 900.470 ;
        RECT 0.335 899.630 115.345 899.650 ;
        RECT 0.335 898.810 115.070 899.630 ;
        RECT 0.335 897.950 115.345 898.810 ;
        RECT 0.335 897.130 115.070 897.950 ;
        RECT 0.335 896.270 115.345 897.130 ;
        RECT 0.335 895.450 115.070 896.270 ;
        RECT 0.335 892.910 115.345 895.450 ;
        RECT 0.610 892.090 115.345 892.910 ;
        RECT 0.335 888.710 115.345 892.090 ;
        RECT 0.335 887.890 115.070 888.710 ;
        RECT 0.335 887.030 115.345 887.890 ;
        RECT 0.335 886.210 115.070 887.030 ;
        RECT 0.335 885.350 115.345 886.210 ;
        RECT 0.610 884.530 115.070 885.350 ;
        RECT 0.335 883.670 115.345 884.530 ;
        RECT 0.335 882.850 115.070 883.670 ;
        RECT 0.335 881.990 115.345 882.850 ;
        RECT 0.335 881.170 115.070 881.990 ;
        RECT 0.335 880.310 115.345 881.170 ;
        RECT 0.335 879.490 115.070 880.310 ;
        RECT 0.335 878.630 115.345 879.490 ;
        RECT 0.335 877.810 115.070 878.630 ;
        RECT 0.335 877.790 115.345 877.810 ;
        RECT 0.610 876.970 115.345 877.790 ;
        RECT 0.335 876.950 115.345 876.970 ;
        RECT 0.335 876.130 115.070 876.950 ;
        RECT 0.335 875.270 115.345 876.130 ;
        RECT 0.335 874.450 115.070 875.270 ;
        RECT 0.335 873.590 115.345 874.450 ;
        RECT 0.335 872.770 115.070 873.590 ;
        RECT 0.335 871.910 115.345 872.770 ;
        RECT 0.335 871.090 115.070 871.910 ;
        RECT 0.335 870.230 115.345 871.090 ;
        RECT 0.610 869.410 115.070 870.230 ;
        RECT 0.335 868.550 115.345 869.410 ;
        RECT 0.335 867.730 115.070 868.550 ;
        RECT 0.335 866.870 115.345 867.730 ;
        RECT 0.335 866.050 115.070 866.870 ;
        RECT 0.335 865.190 115.345 866.050 ;
        RECT 0.335 864.370 115.070 865.190 ;
        RECT 0.335 863.510 115.345 864.370 ;
        RECT 0.335 862.690 115.070 863.510 ;
        RECT 0.335 862.670 115.345 862.690 ;
        RECT 0.610 861.850 115.345 862.670 ;
        RECT 0.335 856.790 115.345 861.850 ;
        RECT 0.335 855.970 115.070 856.790 ;
        RECT 0.335 855.110 115.345 855.970 ;
        RECT 0.610 854.290 115.070 855.110 ;
        RECT 0.335 853.430 115.345 854.290 ;
        RECT 0.335 852.610 115.070 853.430 ;
        RECT 0.335 851.750 115.345 852.610 ;
        RECT 0.335 850.930 115.070 851.750 ;
        RECT 0.335 850.070 115.345 850.930 ;
        RECT 0.335 849.250 115.070 850.070 ;
        RECT 0.335 848.390 115.345 849.250 ;
        RECT 0.335 847.570 115.070 848.390 ;
        RECT 0.335 847.550 115.345 847.570 ;
        RECT 0.610 846.730 115.345 847.550 ;
        RECT 0.335 846.710 115.345 846.730 ;
        RECT 0.335 845.890 115.070 846.710 ;
        RECT 0.335 845.030 115.345 845.890 ;
        RECT 0.335 844.210 115.070 845.030 ;
        RECT 0.335 839.990 115.345 844.210 ;
        RECT 0.610 839.170 115.070 839.990 ;
        RECT 0.335 838.310 115.345 839.170 ;
        RECT 0.335 837.490 115.070 838.310 ;
        RECT 0.335 836.630 115.345 837.490 ;
        RECT 0.335 835.810 115.070 836.630 ;
        RECT 0.335 834.950 115.345 835.810 ;
        RECT 0.335 834.130 115.070 834.950 ;
        RECT 0.335 833.270 115.345 834.130 ;
        RECT 0.335 832.450 115.070 833.270 ;
        RECT 0.335 831.590 115.345 832.450 ;
        RECT 0.335 830.770 115.070 831.590 ;
        RECT 0.335 829.910 115.345 830.770 ;
        RECT 0.335 829.090 115.070 829.910 ;
        RECT 0.335 828.230 115.345 829.090 ;
        RECT 0.335 827.410 115.070 828.230 ;
        RECT 0.335 824.030 115.345 827.410 ;
        RECT 0.335 823.210 115.070 824.030 ;
        RECT 0.335 822.350 115.345 823.210 ;
        RECT 0.335 821.530 115.070 822.350 ;
        RECT 0.335 821.510 115.345 821.530 ;
        RECT 0.610 820.690 115.345 821.510 ;
        RECT 0.335 820.670 115.345 820.690 ;
        RECT 0.335 819.850 115.070 820.670 ;
        RECT 0.335 818.990 115.345 819.850 ;
        RECT 0.335 818.170 115.070 818.990 ;
        RECT 0.335 808.910 115.345 818.170 ;
        RECT 0.335 808.090 115.070 808.910 ;
        RECT 0.335 807.230 115.345 808.090 ;
        RECT 0.335 806.410 115.070 807.230 ;
        RECT 0.335 805.550 115.345 806.410 ;
        RECT 0.335 804.730 115.070 805.550 ;
        RECT 0.335 803.870 115.345 804.730 ;
        RECT 0.335 803.050 115.070 803.870 ;
        RECT 0.335 802.190 115.345 803.050 ;
        RECT 0.610 801.370 115.070 802.190 ;
        RECT 0.335 800.510 115.345 801.370 ;
        RECT 0.335 799.690 115.070 800.510 ;
        RECT 0.335 798.830 115.345 799.690 ;
        RECT 0.335 798.010 115.070 798.830 ;
        RECT 0.335 797.150 115.345 798.010 ;
        RECT 0.335 796.330 115.070 797.150 ;
        RECT 0.335 795.470 115.345 796.330 ;
        RECT 0.335 794.650 115.070 795.470 ;
        RECT 0.335 794.630 115.345 794.650 ;
        RECT 0.610 793.810 115.345 794.630 ;
        RECT 0.335 793.790 115.345 793.810 ;
        RECT 0.335 792.970 115.070 793.790 ;
        RECT 0.335 792.110 115.345 792.970 ;
        RECT 0.335 791.290 115.070 792.110 ;
        RECT 0.335 790.430 115.345 791.290 ;
        RECT 0.335 789.610 115.070 790.430 ;
        RECT 0.335 788.750 115.345 789.610 ;
        RECT 0.335 787.930 115.070 788.750 ;
        RECT 0.335 787.070 115.345 787.930 ;
        RECT 0.610 786.250 115.070 787.070 ;
        RECT 0.335 785.390 115.345 786.250 ;
        RECT 0.335 784.570 115.070 785.390 ;
        RECT 0.335 783.710 115.345 784.570 ;
        RECT 0.335 782.890 115.070 783.710 ;
        RECT 0.335 782.030 115.345 782.890 ;
        RECT 0.335 781.210 115.070 782.030 ;
        RECT 0.335 780.350 115.345 781.210 ;
        RECT 0.335 779.530 115.070 780.350 ;
        RECT 0.335 779.510 115.345 779.530 ;
        RECT 0.610 778.690 115.345 779.510 ;
        RECT 0.335 778.670 115.345 778.690 ;
        RECT 0.335 777.850 115.070 778.670 ;
        RECT 0.335 776.990 115.345 777.850 ;
        RECT 0.335 776.170 115.070 776.990 ;
        RECT 0.335 775.310 115.345 776.170 ;
        RECT 0.335 774.490 115.070 775.310 ;
        RECT 0.335 773.630 115.345 774.490 ;
        RECT 0.335 772.810 115.070 773.630 ;
        RECT 0.335 771.950 115.345 772.810 ;
        RECT 0.610 771.130 115.070 771.950 ;
        RECT 0.335 770.270 115.345 771.130 ;
        RECT 0.335 769.450 115.070 770.270 ;
        RECT 0.335 768.590 115.345 769.450 ;
        RECT 0.335 767.770 115.070 768.590 ;
        RECT 0.335 766.910 115.345 767.770 ;
        RECT 0.335 766.090 115.070 766.910 ;
        RECT 0.335 765.230 115.345 766.090 ;
        RECT 0.335 764.410 115.070 765.230 ;
        RECT 0.335 764.390 115.345 764.410 ;
        RECT 0.610 763.570 115.345 764.390 ;
        RECT 0.335 763.550 115.345 763.570 ;
        RECT 0.335 762.730 115.070 763.550 ;
        RECT 0.335 761.870 115.345 762.730 ;
        RECT 0.335 761.050 115.070 761.870 ;
        RECT 0.335 760.190 115.345 761.050 ;
        RECT 0.335 759.370 115.070 760.190 ;
        RECT 0.335 758.510 115.345 759.370 ;
        RECT 0.335 757.690 115.070 758.510 ;
        RECT 0.335 756.830 115.345 757.690 ;
        RECT 0.610 756.010 115.070 756.830 ;
        RECT 0.335 749.270 115.345 756.010 ;
        RECT 0.610 748.450 115.345 749.270 ;
        RECT 0.335 748.430 115.345 748.450 ;
        RECT 0.335 747.610 115.070 748.430 ;
        RECT 0.335 743.390 115.345 747.610 ;
        RECT 0.335 742.570 115.070 743.390 ;
        RECT 0.335 741.710 115.345 742.570 ;
        RECT 0.610 740.890 115.070 741.710 ;
        RECT 0.335 740.030 115.345 740.890 ;
        RECT 0.335 739.210 115.070 740.030 ;
        RECT 0.335 738.350 115.345 739.210 ;
        RECT 0.335 737.530 115.070 738.350 ;
        RECT 0.335 736.670 115.345 737.530 ;
        RECT 0.335 735.850 115.070 736.670 ;
        RECT 0.335 734.990 115.345 735.850 ;
        RECT 0.335 734.170 115.070 734.990 ;
        RECT 0.335 734.150 115.345 734.170 ;
        RECT 0.610 733.330 115.345 734.150 ;
        RECT 0.335 733.310 115.345 733.330 ;
        RECT 0.335 732.490 115.070 733.310 ;
        RECT 0.335 731.630 115.345 732.490 ;
        RECT 0.335 730.810 115.070 731.630 ;
        RECT 0.335 729.950 115.345 730.810 ;
        RECT 0.335 729.130 115.070 729.950 ;
        RECT 0.335 728.270 115.345 729.130 ;
        RECT 0.335 727.450 115.070 728.270 ;
        RECT 0.335 726.590 115.345 727.450 ;
        RECT 0.610 725.770 115.070 726.590 ;
        RECT 0.335 724.910 115.345 725.770 ;
        RECT 0.335 724.090 115.070 724.910 ;
        RECT 0.335 719.030 115.345 724.090 ;
        RECT 0.610 718.210 115.345 719.030 ;
        RECT 0.335 717.350 115.345 718.210 ;
        RECT 0.335 716.530 115.070 717.350 ;
        RECT 0.335 715.670 115.345 716.530 ;
        RECT 0.335 714.850 115.070 715.670 ;
        RECT 0.335 713.990 115.345 714.850 ;
        RECT 0.335 713.170 115.070 713.990 ;
        RECT 0.335 712.310 115.345 713.170 ;
        RECT 0.335 711.490 115.070 712.310 ;
        RECT 0.335 711.470 115.345 711.490 ;
        RECT 0.610 710.650 115.345 711.470 ;
        RECT 0.335 710.630 115.345 710.650 ;
        RECT 0.335 709.810 115.070 710.630 ;
        RECT 0.335 708.950 115.345 709.810 ;
        RECT 0.335 708.130 115.070 708.950 ;
        RECT 0.335 707.270 115.345 708.130 ;
        RECT 0.335 706.450 115.070 707.270 ;
        RECT 0.335 705.590 115.345 706.450 ;
        RECT 0.335 704.770 115.070 705.590 ;
        RECT 0.335 703.910 115.345 704.770 ;
        RECT 0.610 703.090 115.070 703.910 ;
        RECT 0.335 702.230 115.345 703.090 ;
        RECT 0.335 701.410 115.070 702.230 ;
        RECT 0.335 700.550 115.345 701.410 ;
        RECT 0.335 699.730 115.070 700.550 ;
        RECT 0.335 698.870 115.345 699.730 ;
        RECT 0.335 698.050 115.070 698.870 ;
        RECT 0.335 697.190 115.345 698.050 ;
        RECT 0.335 696.370 115.070 697.190 ;
        RECT 0.335 696.350 115.345 696.370 ;
        RECT 0.610 695.530 115.345 696.350 ;
        RECT 0.335 695.510 115.345 695.530 ;
        RECT 0.335 694.690 115.070 695.510 ;
        RECT 0.335 693.830 115.345 694.690 ;
        RECT 0.335 693.010 115.070 693.830 ;
        RECT 0.335 692.150 115.345 693.010 ;
        RECT 0.335 691.330 115.070 692.150 ;
        RECT 0.335 688.790 115.345 691.330 ;
        RECT 0.610 687.970 115.345 688.790 ;
        RECT 0.335 685.430 115.345 687.970 ;
        RECT 0.335 684.610 115.070 685.430 ;
        RECT 0.335 683.750 115.345 684.610 ;
        RECT 0.335 682.930 115.070 683.750 ;
        RECT 0.335 682.070 115.345 682.930 ;
        RECT 0.335 681.250 115.070 682.070 ;
        RECT 0.335 681.230 115.345 681.250 ;
        RECT 0.610 680.410 115.345 681.230 ;
        RECT 0.335 680.390 115.345 680.410 ;
        RECT 0.335 679.570 115.070 680.390 ;
        RECT 0.335 678.710 115.345 679.570 ;
        RECT 0.335 677.890 115.070 678.710 ;
        RECT 0.335 677.030 115.345 677.890 ;
        RECT 0.335 676.210 115.070 677.030 ;
        RECT 0.335 675.350 115.345 676.210 ;
        RECT 0.335 674.530 115.070 675.350 ;
        RECT 0.335 673.670 115.345 674.530 ;
        RECT 0.610 672.850 115.070 673.670 ;
        RECT 0.335 668.630 115.345 672.850 ;
        RECT 0.335 667.810 115.070 668.630 ;
        RECT 0.335 666.950 115.345 667.810 ;
        RECT 0.335 666.130 115.070 666.950 ;
        RECT 0.335 666.110 115.345 666.130 ;
        RECT 0.610 665.290 115.345 666.110 ;
        RECT 0.335 665.270 115.345 665.290 ;
        RECT 0.335 664.450 115.070 665.270 ;
        RECT 0.335 663.590 115.345 664.450 ;
        RECT 0.335 662.770 115.070 663.590 ;
        RECT 0.335 661.910 115.345 662.770 ;
        RECT 0.335 661.090 115.070 661.910 ;
        RECT 0.335 660.230 115.345 661.090 ;
        RECT 0.335 659.410 115.070 660.230 ;
        RECT 0.335 658.550 115.345 659.410 ;
        RECT 0.610 657.730 115.070 658.550 ;
        RECT 0.335 656.870 115.345 657.730 ;
        RECT 0.335 656.050 115.070 656.870 ;
        RECT 0.335 652.670 115.345 656.050 ;
        RECT 0.335 651.850 115.070 652.670 ;
        RECT 0.335 650.990 115.345 651.850 ;
        RECT 0.610 650.170 115.070 650.990 ;
        RECT 0.335 649.310 115.345 650.170 ;
        RECT 0.335 648.490 115.070 649.310 ;
        RECT 0.335 647.630 115.345 648.490 ;
        RECT 0.335 646.810 115.070 647.630 ;
        RECT 0.335 643.430 115.345 646.810 ;
        RECT 0.610 642.610 115.345 643.430 ;
        RECT 0.335 642.590 115.345 642.610 ;
        RECT 0.335 641.770 115.070 642.590 ;
        RECT 0.335 640.910 115.345 641.770 ;
        RECT 0.335 640.090 115.070 640.910 ;
        RECT 0.335 639.230 115.345 640.090 ;
        RECT 0.335 638.410 115.070 639.230 ;
        RECT 0.335 637.550 115.345 638.410 ;
        RECT 0.335 636.730 115.070 637.550 ;
        RECT 0.335 635.870 115.345 636.730 ;
        RECT 0.610 635.050 115.070 635.870 ;
        RECT 0.335 634.190 115.345 635.050 ;
        RECT 0.335 633.370 115.070 634.190 ;
        RECT 0.335 632.510 115.345 633.370 ;
        RECT 0.335 631.690 115.070 632.510 ;
        RECT 0.335 630.830 115.345 631.690 ;
        RECT 0.335 630.010 115.070 630.830 ;
        RECT 0.335 629.150 115.345 630.010 ;
        RECT 0.335 628.330 115.070 629.150 ;
        RECT 0.335 628.310 115.345 628.330 ;
        RECT 0.610 627.490 115.345 628.310 ;
        RECT 0.335 627.470 115.345 627.490 ;
        RECT 0.335 626.650 115.070 627.470 ;
        RECT 0.335 625.790 115.345 626.650 ;
        RECT 0.335 624.970 115.070 625.790 ;
        RECT 0.335 624.110 115.345 624.970 ;
        RECT 0.335 623.290 115.070 624.110 ;
        RECT 0.335 620.750 115.345 623.290 ;
        RECT 0.610 619.930 115.345 620.750 ;
        RECT 0.335 616.550 115.345 619.930 ;
        RECT 0.335 615.730 115.070 616.550 ;
        RECT 0.335 614.870 115.345 615.730 ;
        RECT 0.335 614.050 115.070 614.870 ;
        RECT 0.335 613.190 115.345 614.050 ;
        RECT 0.610 612.370 115.070 613.190 ;
        RECT 0.335 611.510 115.345 612.370 ;
        RECT 0.335 610.690 115.070 611.510 ;
        RECT 0.335 609.830 115.345 610.690 ;
        RECT 0.335 609.010 115.070 609.830 ;
        RECT 0.335 608.150 115.345 609.010 ;
        RECT 0.335 607.330 115.070 608.150 ;
        RECT 0.335 606.470 115.345 607.330 ;
        RECT 0.335 605.650 115.070 606.470 ;
        RECT 0.335 605.630 115.345 605.650 ;
        RECT 0.610 604.810 115.345 605.630 ;
        RECT 0.335 604.790 115.345 604.810 ;
        RECT 0.335 603.970 115.070 604.790 ;
        RECT 0.335 603.110 115.345 603.970 ;
        RECT 0.335 602.290 115.070 603.110 ;
        RECT 0.335 601.430 115.345 602.290 ;
        RECT 0.335 600.610 115.070 601.430 ;
        RECT 0.335 599.750 115.345 600.610 ;
        RECT 0.335 598.930 115.070 599.750 ;
        RECT 0.335 598.070 115.345 598.930 ;
        RECT 0.610 597.250 115.070 598.070 ;
        RECT 0.335 596.390 115.345 597.250 ;
        RECT 0.335 595.570 115.070 596.390 ;
        RECT 0.335 594.710 115.345 595.570 ;
        RECT 0.335 593.890 115.070 594.710 ;
        RECT 0.335 593.030 115.345 593.890 ;
        RECT 0.335 592.210 115.070 593.030 ;
        RECT 0.335 591.350 115.345 592.210 ;
        RECT 0.335 590.530 115.070 591.350 ;
        RECT 0.335 590.510 115.345 590.530 ;
        RECT 0.610 589.690 115.345 590.510 ;
        RECT 0.335 584.630 115.345 589.690 ;
        RECT 0.335 583.810 115.070 584.630 ;
        RECT 0.335 582.950 115.345 583.810 ;
        RECT 0.610 582.130 115.070 582.950 ;
        RECT 0.335 581.270 115.345 582.130 ;
        RECT 0.335 580.450 115.070 581.270 ;
        RECT 0.335 579.590 115.345 580.450 ;
        RECT 0.335 578.770 115.070 579.590 ;
        RECT 0.335 577.910 115.345 578.770 ;
        RECT 0.335 577.090 115.070 577.910 ;
        RECT 0.335 576.230 115.345 577.090 ;
        RECT 0.335 575.410 115.070 576.230 ;
        RECT 0.335 575.390 115.345 575.410 ;
        RECT 0.610 574.570 115.345 575.390 ;
        RECT 0.335 574.550 115.345 574.570 ;
        RECT 0.335 573.730 115.070 574.550 ;
        RECT 0.335 572.870 115.345 573.730 ;
        RECT 0.335 572.050 115.070 572.870 ;
        RECT 0.335 567.830 115.345 572.050 ;
        RECT 0.610 567.010 115.070 567.830 ;
        RECT 0.335 566.150 115.345 567.010 ;
        RECT 0.335 565.330 115.070 566.150 ;
        RECT 0.335 564.470 115.345 565.330 ;
        RECT 0.335 563.650 115.070 564.470 ;
        RECT 0.335 562.790 115.345 563.650 ;
        RECT 0.335 561.970 115.070 562.790 ;
        RECT 0.335 561.110 115.345 561.970 ;
        RECT 0.335 560.290 115.070 561.110 ;
        RECT 0.335 559.430 115.345 560.290 ;
        RECT 0.335 558.610 115.070 559.430 ;
        RECT 0.335 557.750 115.345 558.610 ;
        RECT 0.335 556.930 115.070 557.750 ;
        RECT 0.335 556.070 115.345 556.930 ;
        RECT 0.335 555.250 115.070 556.070 ;
        RECT 0.335 551.870 115.345 555.250 ;
        RECT 0.335 551.050 115.070 551.870 ;
        RECT 0.335 550.190 115.345 551.050 ;
        RECT 0.335 549.370 115.070 550.190 ;
        RECT 0.335 549.350 115.345 549.370 ;
        RECT 0.610 548.530 115.345 549.350 ;
        RECT 0.335 548.510 115.345 548.530 ;
        RECT 0.335 547.690 115.070 548.510 ;
        RECT 0.335 546.830 115.345 547.690 ;
        RECT 0.335 546.010 115.070 546.830 ;
        RECT 0.335 536.750 115.345 546.010 ;
        RECT 0.335 535.930 115.070 536.750 ;
        RECT 0.335 535.070 115.345 535.930 ;
        RECT 0.335 534.250 115.070 535.070 ;
        RECT 0.335 533.390 115.345 534.250 ;
        RECT 0.335 532.570 115.070 533.390 ;
        RECT 0.335 531.710 115.345 532.570 ;
        RECT 0.335 530.890 115.070 531.710 ;
        RECT 0.335 530.030 115.345 530.890 ;
        RECT 0.610 529.210 115.070 530.030 ;
        RECT 0.335 528.350 115.345 529.210 ;
        RECT 0.335 527.530 115.070 528.350 ;
        RECT 0.335 526.670 115.345 527.530 ;
        RECT 0.335 525.850 115.070 526.670 ;
        RECT 0.335 524.990 115.345 525.850 ;
        RECT 0.335 524.170 115.070 524.990 ;
        RECT 0.335 523.310 115.345 524.170 ;
        RECT 0.335 522.490 115.070 523.310 ;
        RECT 0.335 522.470 115.345 522.490 ;
        RECT 0.610 521.650 115.345 522.470 ;
        RECT 0.335 521.630 115.345 521.650 ;
        RECT 0.335 520.810 115.070 521.630 ;
        RECT 0.335 519.950 115.345 520.810 ;
        RECT 0.335 519.130 115.070 519.950 ;
        RECT 0.335 518.270 115.345 519.130 ;
        RECT 0.335 517.450 115.070 518.270 ;
        RECT 0.335 516.590 115.345 517.450 ;
        RECT 0.335 515.770 115.070 516.590 ;
        RECT 0.335 514.910 115.345 515.770 ;
        RECT 0.610 514.090 115.070 514.910 ;
        RECT 0.335 513.230 115.345 514.090 ;
        RECT 0.335 512.410 115.070 513.230 ;
        RECT 0.335 511.550 115.345 512.410 ;
        RECT 0.335 510.730 115.070 511.550 ;
        RECT 0.335 509.870 115.345 510.730 ;
        RECT 0.335 509.050 115.070 509.870 ;
        RECT 0.335 508.190 115.345 509.050 ;
        RECT 0.335 507.370 115.070 508.190 ;
        RECT 0.335 507.350 115.345 507.370 ;
        RECT 0.610 506.530 115.345 507.350 ;
        RECT 0.335 506.510 115.345 506.530 ;
        RECT 0.335 505.690 115.070 506.510 ;
        RECT 0.335 504.830 115.345 505.690 ;
        RECT 0.335 504.010 115.070 504.830 ;
        RECT 0.335 503.150 115.345 504.010 ;
        RECT 0.335 502.330 115.070 503.150 ;
        RECT 0.335 501.470 115.345 502.330 ;
        RECT 0.335 500.650 115.070 501.470 ;
        RECT 0.335 499.790 115.345 500.650 ;
        RECT 0.610 498.970 115.070 499.790 ;
        RECT 0.335 498.110 115.345 498.970 ;
        RECT 0.335 497.290 115.070 498.110 ;
        RECT 0.335 496.430 115.345 497.290 ;
        RECT 0.335 495.610 115.070 496.430 ;
        RECT 0.335 494.750 115.345 495.610 ;
        RECT 0.335 493.930 115.070 494.750 ;
        RECT 0.335 493.070 115.345 493.930 ;
        RECT 0.335 492.250 115.070 493.070 ;
        RECT 0.335 492.230 115.345 492.250 ;
        RECT 0.610 491.410 115.345 492.230 ;
        RECT 0.335 491.390 115.345 491.410 ;
        RECT 0.335 490.570 115.070 491.390 ;
        RECT 0.335 489.710 115.345 490.570 ;
        RECT 0.335 488.890 115.070 489.710 ;
        RECT 0.335 488.030 115.345 488.890 ;
        RECT 0.335 487.210 115.070 488.030 ;
        RECT 0.335 486.350 115.345 487.210 ;
        RECT 0.335 485.530 115.070 486.350 ;
        RECT 0.335 484.670 115.345 485.530 ;
        RECT 0.610 483.850 115.070 484.670 ;
        RECT 0.335 477.110 115.345 483.850 ;
        RECT 0.610 476.290 115.345 477.110 ;
        RECT 0.335 476.270 115.345 476.290 ;
        RECT 0.335 475.450 115.070 476.270 ;
        RECT 0.335 471.230 115.345 475.450 ;
        RECT 0.335 470.410 115.070 471.230 ;
        RECT 0.335 469.550 115.345 470.410 ;
        RECT 0.610 468.730 115.070 469.550 ;
        RECT 0.335 467.870 115.345 468.730 ;
        RECT 0.335 467.050 115.070 467.870 ;
        RECT 0.335 466.190 115.345 467.050 ;
        RECT 0.335 465.370 115.070 466.190 ;
        RECT 0.335 464.510 115.345 465.370 ;
        RECT 0.335 463.690 115.070 464.510 ;
        RECT 0.335 462.830 115.345 463.690 ;
        RECT 0.335 462.010 115.070 462.830 ;
        RECT 0.335 461.990 115.345 462.010 ;
        RECT 0.610 461.170 115.345 461.990 ;
        RECT 0.335 461.150 115.345 461.170 ;
        RECT 0.335 460.330 115.070 461.150 ;
        RECT 0.335 459.470 115.345 460.330 ;
        RECT 0.335 458.650 115.070 459.470 ;
        RECT 0.335 457.790 115.345 458.650 ;
        RECT 0.335 456.970 115.070 457.790 ;
        RECT 0.335 456.110 115.345 456.970 ;
        RECT 0.335 455.290 115.070 456.110 ;
        RECT 0.335 454.430 115.345 455.290 ;
        RECT 0.610 453.610 115.070 454.430 ;
        RECT 0.335 452.750 115.345 453.610 ;
        RECT 0.335 451.930 115.070 452.750 ;
        RECT 0.335 446.870 115.345 451.930 ;
        RECT 0.610 446.050 115.345 446.870 ;
        RECT 0.335 445.190 115.345 446.050 ;
        RECT 0.335 444.370 115.070 445.190 ;
        RECT 0.335 443.510 115.345 444.370 ;
        RECT 0.335 442.690 115.070 443.510 ;
        RECT 0.335 441.830 115.345 442.690 ;
        RECT 0.335 441.010 115.070 441.830 ;
        RECT 0.335 440.150 115.345 441.010 ;
        RECT 0.335 439.330 115.070 440.150 ;
        RECT 0.335 439.310 115.345 439.330 ;
        RECT 0.610 438.490 115.345 439.310 ;
        RECT 0.335 438.470 115.345 438.490 ;
        RECT 0.335 437.650 115.070 438.470 ;
        RECT 0.335 436.790 115.345 437.650 ;
        RECT 0.335 435.970 115.070 436.790 ;
        RECT 0.335 435.110 115.345 435.970 ;
        RECT 0.335 434.290 115.070 435.110 ;
        RECT 0.335 433.430 115.345 434.290 ;
        RECT 0.335 432.610 115.070 433.430 ;
        RECT 0.335 431.750 115.345 432.610 ;
        RECT 0.610 430.930 115.070 431.750 ;
        RECT 0.335 430.070 115.345 430.930 ;
        RECT 0.335 429.250 115.070 430.070 ;
        RECT 0.335 428.390 115.345 429.250 ;
        RECT 0.335 427.570 115.070 428.390 ;
        RECT 0.335 426.710 115.345 427.570 ;
        RECT 0.335 425.890 115.070 426.710 ;
        RECT 0.335 425.030 115.345 425.890 ;
        RECT 0.335 424.210 115.070 425.030 ;
        RECT 0.335 424.190 115.345 424.210 ;
        RECT 0.610 423.370 115.345 424.190 ;
        RECT 0.335 423.350 115.345 423.370 ;
        RECT 0.335 422.530 115.070 423.350 ;
        RECT 0.335 421.670 115.345 422.530 ;
        RECT 0.335 420.850 115.070 421.670 ;
        RECT 0.335 419.990 115.345 420.850 ;
        RECT 0.335 419.170 115.070 419.990 ;
        RECT 0.335 416.630 115.345 419.170 ;
        RECT 0.610 415.810 115.345 416.630 ;
        RECT 0.335 413.270 115.345 415.810 ;
        RECT 0.335 412.450 115.070 413.270 ;
        RECT 0.335 411.590 115.345 412.450 ;
        RECT 0.335 410.770 115.070 411.590 ;
        RECT 0.335 409.910 115.345 410.770 ;
        RECT 0.335 409.090 115.070 409.910 ;
        RECT 0.335 409.070 115.345 409.090 ;
        RECT 0.610 408.250 115.345 409.070 ;
        RECT 0.335 408.230 115.345 408.250 ;
        RECT 0.335 407.410 115.070 408.230 ;
        RECT 0.335 406.550 115.345 407.410 ;
        RECT 0.335 405.730 115.070 406.550 ;
        RECT 0.335 404.870 115.345 405.730 ;
        RECT 0.335 404.050 115.070 404.870 ;
        RECT 0.335 403.190 115.345 404.050 ;
        RECT 0.335 402.370 115.070 403.190 ;
        RECT 0.335 401.510 115.345 402.370 ;
        RECT 0.610 400.690 115.070 401.510 ;
        RECT 0.335 396.470 115.345 400.690 ;
        RECT 0.335 395.650 115.070 396.470 ;
        RECT 0.335 394.790 115.345 395.650 ;
        RECT 0.335 393.970 115.070 394.790 ;
        RECT 0.335 393.950 115.345 393.970 ;
        RECT 0.610 393.130 115.345 393.950 ;
        RECT 0.335 393.110 115.345 393.130 ;
        RECT 0.335 392.290 115.070 393.110 ;
        RECT 0.335 391.430 115.345 392.290 ;
        RECT 0.335 390.610 115.070 391.430 ;
        RECT 0.335 389.750 115.345 390.610 ;
        RECT 0.335 388.930 115.070 389.750 ;
        RECT 0.335 388.070 115.345 388.930 ;
        RECT 0.335 387.250 115.070 388.070 ;
        RECT 0.335 386.390 115.345 387.250 ;
        RECT 0.610 385.570 115.070 386.390 ;
        RECT 0.335 384.710 115.345 385.570 ;
        RECT 0.335 383.890 115.070 384.710 ;
        RECT 0.335 380.510 115.345 383.890 ;
        RECT 0.335 379.690 115.070 380.510 ;
        RECT 0.335 378.830 115.345 379.690 ;
        RECT 0.610 378.010 115.070 378.830 ;
        RECT 0.335 377.150 115.345 378.010 ;
        RECT 0.335 376.330 115.070 377.150 ;
        RECT 0.335 375.470 115.345 376.330 ;
        RECT 0.335 374.650 115.070 375.470 ;
        RECT 0.335 371.270 115.345 374.650 ;
        RECT 0.610 370.450 115.345 371.270 ;
        RECT 0.335 370.430 115.345 370.450 ;
        RECT 0.335 369.610 115.070 370.430 ;
        RECT 0.335 368.750 115.345 369.610 ;
        RECT 0.335 367.930 115.070 368.750 ;
        RECT 0.335 367.070 115.345 367.930 ;
        RECT 0.335 366.250 115.070 367.070 ;
        RECT 0.335 365.390 115.345 366.250 ;
        RECT 0.335 364.570 115.070 365.390 ;
        RECT 0.335 363.710 115.345 364.570 ;
        RECT 0.610 362.890 115.070 363.710 ;
        RECT 0.335 362.030 115.345 362.890 ;
        RECT 0.335 361.210 115.070 362.030 ;
        RECT 0.335 360.350 115.345 361.210 ;
        RECT 0.335 359.530 115.070 360.350 ;
        RECT 0.335 358.670 115.345 359.530 ;
        RECT 0.335 357.850 115.070 358.670 ;
        RECT 0.335 356.990 115.345 357.850 ;
        RECT 0.335 356.170 115.070 356.990 ;
        RECT 0.335 356.150 115.345 356.170 ;
        RECT 0.610 355.330 115.345 356.150 ;
        RECT 0.335 355.310 115.345 355.330 ;
        RECT 0.335 354.490 115.070 355.310 ;
        RECT 0.335 353.630 115.345 354.490 ;
        RECT 0.335 352.810 115.070 353.630 ;
        RECT 0.335 351.950 115.345 352.810 ;
        RECT 0.335 351.130 115.070 351.950 ;
        RECT 0.335 348.590 115.345 351.130 ;
        RECT 0.610 347.770 115.345 348.590 ;
        RECT 0.335 344.390 115.345 347.770 ;
        RECT 0.335 343.570 115.070 344.390 ;
        RECT 0.335 342.710 115.345 343.570 ;
        RECT 0.335 341.890 115.070 342.710 ;
        RECT 0.335 341.030 115.345 341.890 ;
        RECT 0.610 340.210 115.070 341.030 ;
        RECT 0.335 339.350 115.345 340.210 ;
        RECT 0.335 338.530 115.070 339.350 ;
        RECT 0.335 337.670 115.345 338.530 ;
        RECT 0.335 336.850 115.070 337.670 ;
        RECT 0.335 335.990 115.345 336.850 ;
        RECT 0.335 335.170 115.070 335.990 ;
        RECT 0.335 334.310 115.345 335.170 ;
        RECT 0.335 333.490 115.070 334.310 ;
        RECT 0.335 333.470 115.345 333.490 ;
        RECT 0.610 332.650 115.345 333.470 ;
        RECT 0.335 332.630 115.345 332.650 ;
        RECT 0.335 331.810 115.070 332.630 ;
        RECT 0.335 330.950 115.345 331.810 ;
        RECT 0.335 330.130 115.070 330.950 ;
        RECT 0.335 329.270 115.345 330.130 ;
        RECT 0.335 328.450 115.070 329.270 ;
        RECT 0.335 327.590 115.345 328.450 ;
        RECT 0.335 326.770 115.070 327.590 ;
        RECT 0.335 325.910 115.345 326.770 ;
        RECT 0.610 325.090 115.070 325.910 ;
        RECT 0.335 324.230 115.345 325.090 ;
        RECT 0.335 323.410 115.070 324.230 ;
        RECT 0.335 322.550 115.345 323.410 ;
        RECT 0.335 321.730 115.070 322.550 ;
        RECT 0.335 320.870 115.345 321.730 ;
        RECT 0.335 320.050 115.070 320.870 ;
        RECT 0.335 319.190 115.345 320.050 ;
        RECT 0.335 318.370 115.070 319.190 ;
        RECT 0.335 318.350 115.345 318.370 ;
        RECT 0.610 317.530 115.345 318.350 ;
        RECT 0.335 312.470 115.345 317.530 ;
        RECT 0.335 311.650 115.070 312.470 ;
        RECT 0.335 310.790 115.345 311.650 ;
        RECT 0.610 309.970 115.070 310.790 ;
        RECT 0.335 309.110 115.345 309.970 ;
        RECT 0.335 308.290 115.070 309.110 ;
        RECT 0.335 307.430 115.345 308.290 ;
        RECT 0.335 306.610 115.070 307.430 ;
        RECT 0.335 305.750 115.345 306.610 ;
        RECT 0.335 304.930 115.070 305.750 ;
        RECT 0.335 304.070 115.345 304.930 ;
        RECT 0.335 303.250 115.070 304.070 ;
        RECT 0.335 303.230 115.345 303.250 ;
        RECT 0.610 302.410 115.345 303.230 ;
        RECT 0.335 302.390 115.345 302.410 ;
        RECT 0.335 301.570 115.070 302.390 ;
        RECT 0.335 300.710 115.345 301.570 ;
        RECT 0.335 299.890 115.070 300.710 ;
        RECT 0.335 295.670 115.345 299.890 ;
        RECT 0.610 294.850 115.070 295.670 ;
        RECT 0.335 293.990 115.345 294.850 ;
        RECT 0.335 293.170 115.070 293.990 ;
        RECT 0.335 292.310 115.345 293.170 ;
        RECT 0.335 291.490 115.070 292.310 ;
        RECT 0.335 290.630 115.345 291.490 ;
        RECT 0.335 289.810 115.070 290.630 ;
        RECT 0.335 288.950 115.345 289.810 ;
        RECT 0.335 288.130 115.070 288.950 ;
        RECT 0.335 287.270 115.345 288.130 ;
        RECT 0.335 286.450 115.070 287.270 ;
        RECT 0.335 285.590 115.345 286.450 ;
        RECT 0.335 284.770 115.070 285.590 ;
        RECT 0.335 283.910 115.345 284.770 ;
        RECT 0.335 283.090 115.070 283.910 ;
        RECT 0.335 279.710 115.345 283.090 ;
        RECT 0.335 278.890 115.070 279.710 ;
        RECT 0.335 278.030 115.345 278.890 ;
        RECT 0.335 277.210 115.070 278.030 ;
        RECT 0.335 277.190 115.345 277.210 ;
        RECT 0.610 276.370 115.345 277.190 ;
        RECT 0.335 276.350 115.345 276.370 ;
        RECT 0.335 275.530 115.070 276.350 ;
        RECT 0.335 274.670 115.345 275.530 ;
        RECT 0.335 273.850 115.070 274.670 ;
        RECT 0.335 264.590 115.345 273.850 ;
        RECT 0.335 263.770 115.070 264.590 ;
        RECT 0.335 262.910 115.345 263.770 ;
        RECT 0.335 262.090 115.070 262.910 ;
        RECT 0.335 261.230 115.345 262.090 ;
        RECT 0.335 260.410 115.070 261.230 ;
        RECT 0.335 259.550 115.345 260.410 ;
        RECT 0.335 258.730 115.070 259.550 ;
        RECT 0.335 258.710 115.345 258.730 ;
        RECT 0.610 257.890 115.345 258.710 ;
        RECT 0.335 257.870 115.345 257.890 ;
        RECT 0.335 257.050 115.070 257.870 ;
        RECT 0.335 257.030 115.345 257.050 ;
        RECT 0.610 256.210 115.345 257.030 ;
        RECT 0.335 256.190 115.345 256.210 ;
        RECT 0.335 255.370 115.070 256.190 ;
        RECT 0.335 255.350 115.345 255.370 ;
        RECT 0.610 254.530 115.345 255.350 ;
        RECT 0.335 254.510 115.345 254.530 ;
        RECT 0.335 253.690 115.070 254.510 ;
        RECT 0.335 253.670 115.345 253.690 ;
        RECT 0.610 252.850 115.345 253.670 ;
        RECT 0.335 252.830 115.345 252.850 ;
        RECT 0.335 252.010 115.070 252.830 ;
        RECT 0.335 251.990 115.345 252.010 ;
        RECT 0.610 251.170 115.345 251.990 ;
        RECT 0.335 251.150 115.345 251.170 ;
        RECT 0.335 250.330 115.070 251.150 ;
        RECT 0.335 250.310 115.345 250.330 ;
        RECT 0.610 249.490 115.345 250.310 ;
        RECT 0.335 249.470 115.345 249.490 ;
        RECT 0.335 248.650 115.070 249.470 ;
        RECT 0.335 248.630 115.345 248.650 ;
        RECT 0.610 247.810 115.345 248.630 ;
        RECT 0.335 247.790 115.345 247.810 ;
        RECT 0.335 246.970 115.070 247.790 ;
        RECT 0.335 246.950 115.345 246.970 ;
        RECT 0.610 246.130 115.345 246.950 ;
        RECT 0.335 246.110 115.345 246.130 ;
        RECT 0.335 245.290 115.070 246.110 ;
        RECT 0.335 245.270 115.345 245.290 ;
        RECT 0.610 244.450 115.345 245.270 ;
        RECT 0.335 244.430 115.345 244.450 ;
        RECT 0.335 243.610 115.070 244.430 ;
        RECT 0.335 243.590 115.345 243.610 ;
        RECT 0.610 242.770 115.345 243.590 ;
        RECT 0.335 242.750 115.345 242.770 ;
        RECT 0.335 241.930 115.070 242.750 ;
        RECT 0.335 241.910 115.345 241.930 ;
        RECT 0.610 241.090 115.345 241.910 ;
        RECT 0.335 241.070 115.345 241.090 ;
        RECT 0.335 240.250 115.070 241.070 ;
        RECT 0.335 240.230 115.345 240.250 ;
        RECT 0.610 239.410 115.345 240.230 ;
        RECT 0.335 239.390 115.345 239.410 ;
        RECT 0.335 238.570 115.070 239.390 ;
        RECT 0.335 238.550 115.345 238.570 ;
        RECT 0.610 237.730 115.345 238.550 ;
        RECT 0.335 237.710 115.345 237.730 ;
        RECT 0.335 236.890 115.070 237.710 ;
        RECT 0.335 236.870 115.345 236.890 ;
        RECT 0.610 236.050 115.345 236.870 ;
        RECT 0.335 236.030 115.345 236.050 ;
        RECT 0.335 235.210 115.070 236.030 ;
        RECT 0.335 235.190 115.345 235.210 ;
        RECT 0.610 234.370 115.345 235.190 ;
        RECT 0.335 234.350 115.345 234.370 ;
        RECT 0.335 233.530 115.070 234.350 ;
        RECT 0.335 233.510 115.345 233.530 ;
        RECT 0.610 232.690 115.345 233.510 ;
        RECT 0.335 232.670 115.345 232.690 ;
        RECT 0.335 231.850 115.070 232.670 ;
        RECT 0.335 231.830 115.345 231.850 ;
        RECT 0.610 231.010 115.345 231.830 ;
        RECT 0.335 230.990 115.345 231.010 ;
        RECT 0.335 230.170 115.070 230.990 ;
        RECT 0.335 230.150 115.345 230.170 ;
        RECT 0.610 229.330 115.345 230.150 ;
        RECT 0.335 229.310 115.345 229.330 ;
        RECT 0.335 228.490 115.070 229.310 ;
        RECT 0.335 228.470 115.345 228.490 ;
        RECT 0.610 227.650 115.345 228.470 ;
        RECT 0.335 227.630 115.345 227.650 ;
        RECT 0.335 226.810 115.070 227.630 ;
        RECT 0.335 226.790 115.345 226.810 ;
        RECT 0.610 225.970 115.345 226.790 ;
        RECT 0.335 225.950 115.345 225.970 ;
        RECT 0.335 225.130 115.070 225.950 ;
        RECT 0.335 225.110 115.345 225.130 ;
        RECT 0.610 224.290 115.345 225.110 ;
        RECT 0.335 224.270 115.345 224.290 ;
        RECT 0.335 223.450 115.070 224.270 ;
        RECT 0.335 223.430 115.345 223.450 ;
        RECT 0.610 222.610 115.345 223.430 ;
        RECT 0.335 222.590 115.345 222.610 ;
        RECT 0.335 221.770 115.070 222.590 ;
        RECT 0.335 221.750 115.345 221.770 ;
        RECT 0.610 220.930 115.345 221.750 ;
        RECT 0.335 220.910 115.345 220.930 ;
        RECT 0.335 220.090 115.070 220.910 ;
        RECT 0.335 220.070 115.345 220.090 ;
        RECT 0.610 219.250 115.345 220.070 ;
        RECT 0.335 219.230 115.345 219.250 ;
        RECT 0.335 218.410 115.070 219.230 ;
        RECT 0.335 218.390 115.345 218.410 ;
        RECT 0.610 217.570 115.345 218.390 ;
        RECT 0.335 217.550 115.345 217.570 ;
        RECT 0.335 216.730 115.070 217.550 ;
        RECT 0.335 216.710 115.345 216.730 ;
        RECT 0.610 215.890 115.345 216.710 ;
        RECT 0.335 215.870 115.345 215.890 ;
        RECT 0.335 215.050 115.070 215.870 ;
        RECT 0.335 215.030 115.345 215.050 ;
        RECT 0.610 214.210 115.345 215.030 ;
        RECT 0.335 214.190 115.345 214.210 ;
        RECT 0.335 213.370 115.070 214.190 ;
        RECT 0.335 213.350 115.345 213.370 ;
        RECT 0.610 212.530 115.345 213.350 ;
        RECT 0.335 212.510 115.345 212.530 ;
        RECT 0.335 211.690 115.070 212.510 ;
        RECT 0.335 211.670 115.345 211.690 ;
        RECT 0.610 210.850 115.345 211.670 ;
        RECT 0.335 209.990 115.345 210.850 ;
        RECT 0.610 209.170 115.345 209.990 ;
        RECT 0.335 208.310 115.345 209.170 ;
        RECT 0.610 207.490 115.345 208.310 ;
        RECT 0.335 206.630 115.345 207.490 ;
        RECT 0.610 205.810 115.345 206.630 ;
        RECT 0.335 204.950 115.345 205.810 ;
        RECT 0.610 204.130 115.345 204.950 ;
        RECT 0.335 204.110 115.345 204.130 ;
        RECT 0.335 203.290 115.070 204.110 ;
        RECT 0.335 203.270 115.345 203.290 ;
        RECT 0.610 202.450 115.345 203.270 ;
        RECT 0.335 201.590 115.345 202.450 ;
        RECT 0.610 200.770 115.345 201.590 ;
        RECT 0.335 199.910 115.345 200.770 ;
        RECT 0.610 199.090 115.345 199.910 ;
        RECT 0.335 199.070 115.345 199.090 ;
        RECT 0.335 198.250 115.070 199.070 ;
        RECT 0.335 198.230 115.345 198.250 ;
        RECT 0.610 197.410 115.345 198.230 ;
        RECT 0.335 197.390 115.345 197.410 ;
        RECT 0.335 196.570 115.070 197.390 ;
        RECT 0.335 196.550 115.345 196.570 ;
        RECT 0.610 195.730 115.345 196.550 ;
        RECT 0.335 195.710 115.345 195.730 ;
        RECT 0.335 194.890 115.070 195.710 ;
        RECT 0.335 194.870 115.345 194.890 ;
        RECT 0.610 194.050 115.345 194.870 ;
        RECT 0.335 194.030 115.345 194.050 ;
        RECT 0.335 193.210 115.070 194.030 ;
        RECT 0.335 193.190 115.345 193.210 ;
        RECT 0.610 192.370 115.345 193.190 ;
        RECT 0.335 192.350 115.345 192.370 ;
        RECT 0.335 191.530 115.070 192.350 ;
        RECT 0.335 191.510 115.345 191.530 ;
        RECT 0.610 190.690 115.345 191.510 ;
        RECT 0.335 190.670 115.345 190.690 ;
        RECT 0.335 189.850 115.070 190.670 ;
        RECT 0.335 189.830 115.345 189.850 ;
        RECT 0.610 189.010 115.345 189.830 ;
        RECT 0.335 188.990 115.345 189.010 ;
        RECT 0.335 188.170 115.070 188.990 ;
        RECT 0.335 188.150 115.345 188.170 ;
        RECT 0.610 187.330 115.345 188.150 ;
        RECT 0.335 187.310 115.345 187.330 ;
        RECT 0.335 186.490 115.070 187.310 ;
        RECT 0.335 186.470 115.345 186.490 ;
        RECT 0.610 185.650 115.345 186.470 ;
        RECT 0.335 185.630 115.345 185.650 ;
        RECT 0.335 184.810 115.070 185.630 ;
        RECT 0.335 184.790 115.345 184.810 ;
        RECT 0.610 183.970 115.345 184.790 ;
        RECT 0.335 183.950 115.345 183.970 ;
        RECT 0.335 183.130 115.070 183.950 ;
        RECT 0.335 183.110 115.345 183.130 ;
        RECT 0.610 182.290 115.345 183.110 ;
        RECT 0.335 182.270 115.345 182.290 ;
        RECT 0.335 181.450 115.070 182.270 ;
        RECT 0.335 181.430 115.345 181.450 ;
        RECT 0.610 180.610 115.345 181.430 ;
        RECT 0.335 180.590 115.345 180.610 ;
        RECT 0.335 179.770 115.070 180.590 ;
        RECT 0.335 179.750 115.345 179.770 ;
        RECT 0.610 178.930 115.345 179.750 ;
        RECT 0.335 178.070 115.345 178.930 ;
        RECT 0.610 177.250 115.345 178.070 ;
        RECT 0.335 176.390 115.345 177.250 ;
        RECT 0.610 175.570 115.345 176.390 ;
        RECT 0.335 174.710 115.345 175.570 ;
        RECT 0.610 173.890 115.345 174.710 ;
        RECT 0.335 173.030 115.345 173.890 ;
        RECT 0.610 172.210 115.070 173.030 ;
        RECT 0.335 171.350 115.345 172.210 ;
        RECT 0.610 170.530 115.070 171.350 ;
        RECT 0.335 169.670 115.345 170.530 ;
        RECT 0.610 168.850 115.070 169.670 ;
        RECT 0.335 167.990 115.345 168.850 ;
        RECT 0.610 167.170 115.070 167.990 ;
        RECT 0.335 166.310 115.345 167.170 ;
        RECT 0.610 165.490 115.070 166.310 ;
        RECT 0.335 164.630 115.345 165.490 ;
        RECT 0.610 163.810 115.070 164.630 ;
        RECT 0.335 162.950 115.345 163.810 ;
        RECT 0.610 162.130 115.070 162.950 ;
        RECT 0.335 161.270 115.345 162.130 ;
        RECT 0.610 160.450 115.070 161.270 ;
        RECT 0.335 159.590 115.345 160.450 ;
        RECT 0.610 158.770 115.070 159.590 ;
        RECT 0.335 157.910 115.345 158.770 ;
        RECT 0.610 157.090 115.070 157.910 ;
        RECT 0.335 156.230 115.345 157.090 ;
        RECT 0.610 155.410 115.070 156.230 ;
        RECT 0.335 154.550 115.345 155.410 ;
        RECT 0.610 153.730 115.070 154.550 ;
        RECT 0.335 152.870 115.345 153.730 ;
        RECT 0.610 152.050 115.070 152.870 ;
        RECT 0.335 151.190 115.345 152.050 ;
        RECT 0.610 150.370 115.070 151.190 ;
        RECT 0.335 149.510 115.345 150.370 ;
        RECT 0.610 148.690 115.070 149.510 ;
        RECT 0.335 147.830 115.345 148.690 ;
        RECT 0.610 147.010 115.070 147.830 ;
        RECT 0.335 146.150 115.345 147.010 ;
        RECT 0.610 145.330 115.345 146.150 ;
        RECT 0.335 144.470 115.345 145.330 ;
        RECT 0.610 143.650 115.345 144.470 ;
        RECT 0.335 142.790 115.345 143.650 ;
        RECT 0.610 141.970 115.345 142.790 ;
        RECT 0.335 141.110 115.345 141.970 ;
        RECT 0.610 140.290 115.070 141.110 ;
        RECT 0.335 139.430 115.345 140.290 ;
        RECT 0.610 138.610 115.070 139.430 ;
        RECT 0.335 137.750 115.345 138.610 ;
        RECT 0.610 136.930 115.070 137.750 ;
        RECT 0.335 136.070 115.345 136.930 ;
        RECT 0.610 135.250 115.070 136.070 ;
        RECT 0.335 134.390 115.345 135.250 ;
        RECT 0.610 133.570 115.070 134.390 ;
        RECT 0.335 132.710 115.345 133.570 ;
        RECT 0.610 131.890 115.070 132.710 ;
        RECT 0.335 131.030 115.345 131.890 ;
        RECT 0.610 130.210 115.070 131.030 ;
        RECT 0.335 129.350 115.345 130.210 ;
        RECT 0.610 128.530 115.070 129.350 ;
        RECT 0.335 127.670 115.345 128.530 ;
        RECT 0.610 126.850 115.345 127.670 ;
        RECT 0.335 125.990 115.345 126.850 ;
        RECT 0.610 125.170 115.345 125.990 ;
        RECT 0.335 124.310 115.345 125.170 ;
        RECT 0.610 123.490 115.070 124.310 ;
        RECT 0.335 122.630 115.345 123.490 ;
        RECT 0.610 121.810 115.070 122.630 ;
        RECT 0.335 120.950 115.345 121.810 ;
        RECT 0.610 120.130 115.070 120.950 ;
        RECT 0.335 119.270 115.345 120.130 ;
        RECT 0.610 118.450 115.070 119.270 ;
        RECT 0.335 117.590 115.345 118.450 ;
        RECT 0.610 116.770 115.070 117.590 ;
        RECT 0.335 115.910 115.345 116.770 ;
        RECT 0.610 115.090 115.070 115.910 ;
        RECT 0.335 114.230 115.345 115.090 ;
        RECT 0.610 113.410 115.070 114.230 ;
        RECT 0.335 112.550 115.345 113.410 ;
        RECT 0.610 111.730 115.070 112.550 ;
        RECT 0.335 110.870 115.345 111.730 ;
        RECT 0.610 110.050 115.345 110.870 ;
        RECT 0.335 109.190 115.345 110.050 ;
        RECT 0.610 108.370 115.345 109.190 ;
        RECT 0.335 108.350 115.345 108.370 ;
        RECT 0.335 107.530 115.070 108.350 ;
        RECT 0.335 107.510 115.345 107.530 ;
        RECT 0.610 106.690 115.345 107.510 ;
        RECT 0.335 106.670 115.345 106.690 ;
        RECT 0.335 105.850 115.070 106.670 ;
        RECT 0.335 105.830 115.345 105.850 ;
        RECT 0.610 105.010 115.345 105.830 ;
        RECT 0.335 104.990 115.345 105.010 ;
        RECT 0.335 104.170 115.070 104.990 ;
        RECT 0.335 104.150 115.345 104.170 ;
        RECT 0.610 103.330 115.345 104.150 ;
        RECT 0.335 103.310 115.345 103.330 ;
        RECT 0.335 102.490 115.070 103.310 ;
        RECT 0.335 102.470 115.345 102.490 ;
        RECT 0.610 101.650 115.345 102.470 ;
        RECT 0.335 100.790 115.345 101.650 ;
        RECT 0.610 99.970 115.345 100.790 ;
        RECT 0.335 99.110 115.345 99.970 ;
        RECT 0.610 98.290 115.345 99.110 ;
        RECT 0.335 98.270 115.345 98.290 ;
        RECT 0.335 97.450 115.070 98.270 ;
        RECT 0.335 97.430 115.345 97.450 ;
        RECT 0.610 96.610 115.345 97.430 ;
        RECT 0.335 96.590 115.345 96.610 ;
        RECT 0.335 95.770 115.070 96.590 ;
        RECT 0.335 95.750 115.345 95.770 ;
        RECT 0.610 94.930 115.345 95.750 ;
        RECT 0.335 94.910 115.345 94.930 ;
        RECT 0.335 94.090 115.070 94.910 ;
        RECT 0.335 94.070 115.345 94.090 ;
        RECT 0.610 93.250 115.345 94.070 ;
        RECT 0.335 93.230 115.345 93.250 ;
        RECT 0.335 92.410 115.070 93.230 ;
        RECT 0.335 92.390 115.345 92.410 ;
        RECT 0.610 91.570 115.345 92.390 ;
        RECT 0.335 91.550 115.345 91.570 ;
        RECT 0.335 90.730 115.070 91.550 ;
        RECT 0.335 90.710 115.345 90.730 ;
        RECT 0.610 89.890 115.345 90.710 ;
        RECT 0.335 89.870 115.345 89.890 ;
        RECT 0.335 89.050 115.070 89.870 ;
        RECT 0.335 89.030 115.345 89.050 ;
        RECT 0.610 88.210 115.345 89.030 ;
        RECT 0.335 88.190 115.345 88.210 ;
        RECT 0.335 87.370 115.070 88.190 ;
        RECT 0.335 87.350 115.345 87.370 ;
        RECT 0.610 86.530 115.345 87.350 ;
        RECT 0.335 86.510 115.345 86.530 ;
        RECT 0.335 85.690 115.070 86.510 ;
        RECT 0.335 85.670 115.345 85.690 ;
        RECT 0.610 84.850 115.345 85.670 ;
        RECT 0.335 84.830 115.345 84.850 ;
        RECT 0.335 84.010 115.070 84.830 ;
        RECT 0.335 83.990 115.345 84.010 ;
        RECT 0.610 83.170 115.345 83.990 ;
        RECT 0.335 83.150 115.345 83.170 ;
        RECT 0.335 82.330 115.070 83.150 ;
        RECT 0.335 82.310 115.345 82.330 ;
        RECT 0.610 81.490 115.345 82.310 ;
        RECT 0.335 81.470 115.345 81.490 ;
        RECT 0.335 80.650 115.070 81.470 ;
        RECT 0.335 80.630 115.345 80.650 ;
        RECT 0.610 79.810 115.345 80.630 ;
        RECT 0.335 79.790 115.345 79.810 ;
        RECT 0.335 78.970 115.070 79.790 ;
        RECT 0.335 78.950 115.345 78.970 ;
        RECT 0.610 78.130 115.345 78.950 ;
        RECT 0.335 72.230 115.345 78.130 ;
        RECT 0.335 71.410 115.070 72.230 ;
        RECT 0.335 70.550 115.345 71.410 ;
        RECT 0.335 69.730 115.070 70.550 ;
        RECT 0.335 68.870 115.345 69.730 ;
        RECT 0.335 68.050 115.070 68.870 ;
        RECT 0.335 67.190 115.345 68.050 ;
        RECT 0.335 66.370 115.070 67.190 ;
        RECT 0.335 65.510 115.345 66.370 ;
        RECT 0.335 64.690 115.070 65.510 ;
        RECT 0.335 63.830 115.345 64.690 ;
        RECT 0.335 63.010 115.070 63.830 ;
        RECT 0.335 62.150 115.345 63.010 ;
        RECT 0.335 61.330 115.070 62.150 ;
        RECT 0.335 60.470 115.345 61.330 ;
        RECT 0.335 59.650 115.070 60.470 ;
        RECT 0.335 59.630 115.345 59.650 ;
        RECT 0.610 58.810 115.345 59.630 ;
        RECT 0.335 58.790 115.345 58.810 ;
        RECT 0.335 57.970 115.070 58.790 ;
        RECT 0.335 57.950 115.345 57.970 ;
        RECT 0.610 57.130 115.345 57.950 ;
        RECT 0.335 57.110 115.345 57.130 ;
        RECT 0.335 56.290 115.070 57.110 ;
        RECT 0.335 56.270 115.345 56.290 ;
        RECT 0.610 55.450 115.345 56.270 ;
        RECT 0.335 55.430 115.345 55.450 ;
        RECT 0.335 54.610 115.070 55.430 ;
        RECT 0.335 54.590 115.345 54.610 ;
        RECT 0.610 53.770 115.345 54.590 ;
        RECT 0.335 53.750 115.345 53.770 ;
        RECT 0.335 52.930 115.070 53.750 ;
        RECT 0.335 52.910 115.345 52.930 ;
        RECT 0.610 52.090 115.345 52.910 ;
        RECT 0.335 52.070 115.345 52.090 ;
        RECT 0.335 51.250 115.070 52.070 ;
        RECT 0.335 51.230 115.345 51.250 ;
        RECT 0.610 50.410 115.345 51.230 ;
        RECT 0.335 50.390 115.345 50.410 ;
        RECT 0.335 49.570 115.070 50.390 ;
        RECT 0.335 49.550 115.345 49.570 ;
        RECT 0.610 48.730 115.345 49.550 ;
        RECT 0.335 48.710 115.345 48.730 ;
        RECT 0.335 47.890 115.070 48.710 ;
        RECT 0.335 47.870 115.345 47.890 ;
        RECT 0.610 47.050 115.345 47.870 ;
        RECT 0.335 47.030 115.345 47.050 ;
        RECT 0.335 46.210 115.070 47.030 ;
        RECT 0.335 46.190 115.345 46.210 ;
        RECT 0.610 45.370 115.345 46.190 ;
        RECT 0.335 44.510 115.345 45.370 ;
        RECT 0.610 43.690 115.345 44.510 ;
        RECT 0.335 42.830 115.345 43.690 ;
        RECT 0.610 42.010 115.345 42.830 ;
        RECT 0.335 41.150 115.345 42.010 ;
        RECT 0.610 40.330 115.345 41.150 ;
        RECT 0.335 40.310 115.345 40.330 ;
        RECT 0.335 39.490 115.070 40.310 ;
        RECT 0.335 39.470 115.345 39.490 ;
        RECT 0.610 38.650 115.345 39.470 ;
        RECT 0.335 38.630 115.345 38.650 ;
        RECT 0.335 37.810 115.070 38.630 ;
        RECT 0.335 37.790 115.345 37.810 ;
        RECT 0.610 36.970 115.345 37.790 ;
        RECT 0.335 36.950 115.345 36.970 ;
        RECT 0.335 36.130 115.070 36.950 ;
        RECT 0.335 36.110 115.345 36.130 ;
        RECT 0.610 35.290 115.345 36.110 ;
        RECT 0.335 35.270 115.345 35.290 ;
        RECT 0.335 34.450 115.070 35.270 ;
        RECT 0.335 34.430 115.345 34.450 ;
        RECT 0.610 33.610 115.345 34.430 ;
        RECT 0.335 33.590 115.345 33.610 ;
        RECT 0.335 32.770 115.070 33.590 ;
        RECT 0.335 32.750 115.345 32.770 ;
        RECT 0.610 31.930 115.345 32.750 ;
        RECT 0.335 31.910 115.345 31.930 ;
        RECT 0.335 31.090 115.070 31.910 ;
        RECT 0.335 31.070 115.345 31.090 ;
        RECT 0.610 30.250 115.345 31.070 ;
        RECT 0.335 30.230 115.345 30.250 ;
        RECT 0.335 29.410 115.070 30.230 ;
        RECT 0.335 29.390 115.345 29.410 ;
        RECT 0.610 28.570 115.345 29.390 ;
        RECT 0.335 28.550 115.345 28.570 ;
        RECT 0.335 27.730 115.070 28.550 ;
        RECT 0.335 27.710 115.345 27.730 ;
        RECT 0.610 26.890 115.345 27.710 ;
        RECT 0.335 26.030 115.345 26.890 ;
        RECT 0.610 25.210 115.345 26.030 ;
        RECT 0.335 24.350 115.345 25.210 ;
        RECT 0.610 23.530 115.345 24.350 ;
        RECT 0.335 23.510 115.345 23.530 ;
        RECT 0.335 22.690 115.070 23.510 ;
        RECT 0.335 22.670 115.345 22.690 ;
        RECT 0.610 21.850 115.345 22.670 ;
        RECT 0.335 21.830 115.345 21.850 ;
        RECT 0.335 21.010 115.070 21.830 ;
        RECT 0.335 20.990 115.345 21.010 ;
        RECT 0.610 20.170 115.345 20.990 ;
        RECT 0.335 20.150 115.345 20.170 ;
        RECT 0.335 19.330 115.070 20.150 ;
        RECT 0.335 19.310 115.345 19.330 ;
        RECT 0.610 18.490 115.345 19.310 ;
        RECT 0.335 18.470 115.345 18.490 ;
        RECT 0.335 17.650 115.070 18.470 ;
        RECT 0.335 17.630 115.345 17.650 ;
        RECT 0.610 16.810 115.345 17.630 ;
        RECT 0.335 16.790 115.345 16.810 ;
        RECT 0.335 15.970 115.070 16.790 ;
        RECT 0.335 15.950 115.345 15.970 ;
        RECT 0.610 15.130 115.345 15.950 ;
        RECT 0.335 15.110 115.345 15.130 ;
        RECT 0.335 14.290 115.070 15.110 ;
        RECT 0.335 14.270 115.345 14.290 ;
        RECT 0.610 13.450 115.345 14.270 ;
        RECT 0.335 13.430 115.345 13.450 ;
        RECT 0.335 12.610 115.070 13.430 ;
        RECT 0.335 12.590 115.345 12.610 ;
        RECT 0.610 11.770 115.345 12.590 ;
        RECT 0.335 11.750 115.345 11.770 ;
        RECT 0.335 10.930 115.070 11.750 ;
        RECT 0.335 10.910 115.345 10.930 ;
        RECT 0.610 10.090 115.345 10.910 ;
        RECT 0.335 9.230 115.345 10.090 ;
        RECT 0.610 8.410 115.345 9.230 ;
        RECT 0.335 7.550 115.345 8.410 ;
        RECT 0.610 6.730 115.070 7.550 ;
        RECT 0.335 5.870 115.345 6.730 ;
        RECT 0.335 5.050 115.070 5.870 ;
        RECT 0.335 4.190 115.345 5.050 ;
        RECT 0.335 3.370 115.070 4.190 ;
        RECT 0.335 2.510 115.345 3.370 ;
        RECT 0.335 1.690 115.070 2.510 ;
        RECT 0.335 1.670 115.345 1.690 ;
        RECT 0.610 0.850 115.345 1.670 ;
        RECT 0.335 0.315 115.345 0.850 ;
      LAYER Metal4 ;
        RECT 0.380 0.275 12.170 1632.685 ;
        RECT 13.590 0.275 15.170 1632.685 ;
        RECT 16.590 0.275 62.170 1632.685 ;
        RECT 63.590 0.275 65.170 1632.685 ;
        RECT 66.590 0.275 115.300 1632.685 ;
      LAYER TopMetal1 ;
        RECT 20.780 21.340 107.860 1628.100 ;
  END
END AXIL_S_IO_W
END LIBRARY

